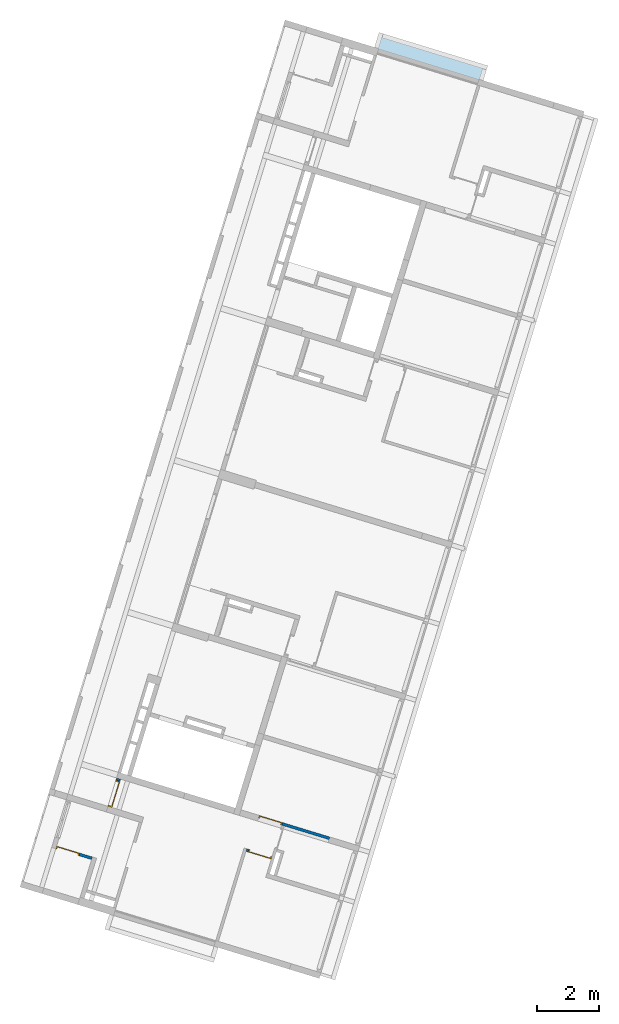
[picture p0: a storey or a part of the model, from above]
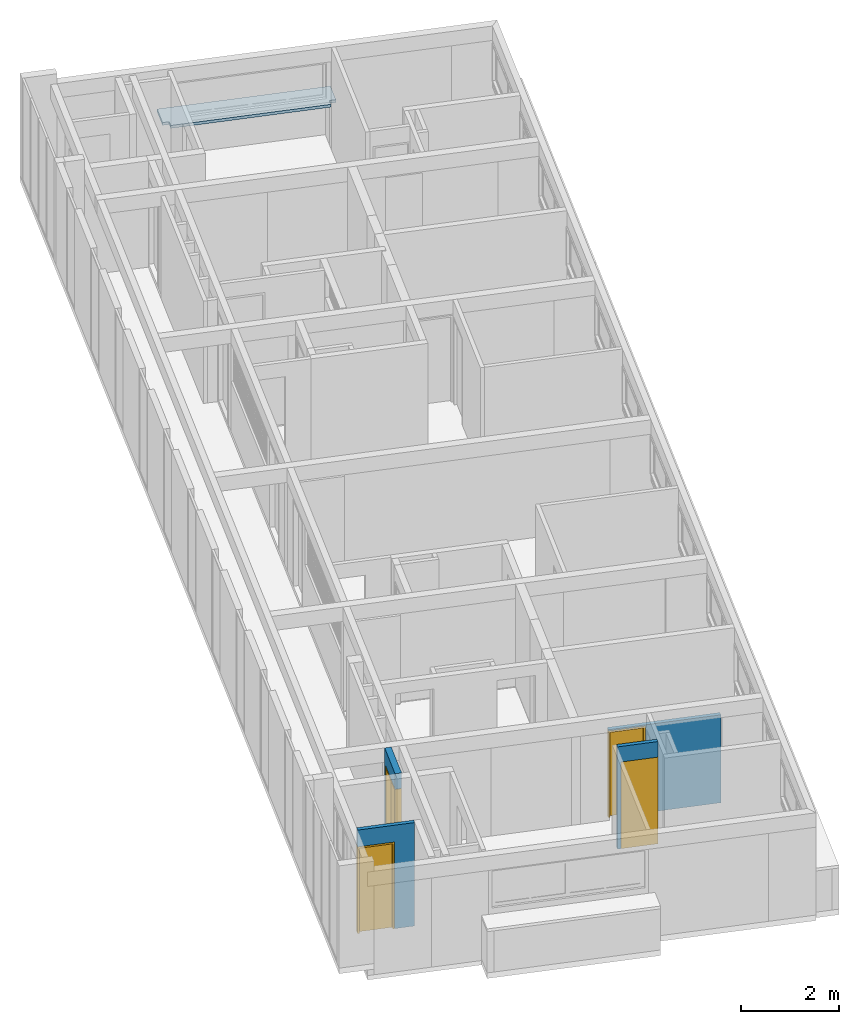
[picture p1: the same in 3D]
Properties of the parts of a building model (IFC2X3), part 1 of 11

# File
Description: ViewDefinition [CoordinationView_V2.0, SurfaceGeometryAddOnView, QuantityTakeOffAddOnView, SpaceBoundary2ndLevelAddOnView], Option [Elements to export: Visible elements (on all stories)], Option [Partial Structure Display: Entire Model], Option [IFC Domain: All], Option [Structural Function: All Elements], Option [Convert Grid elements: On], Option [Convert IFC Annotations and Archicad 2D elements: On], Option [Convert 2D symbols of Doors and Windows: On], Option [Export geometries that Participates in Collision Detection only: Off], Option [Split complex elements: Off], Option [Material Preservation: Explode where necessary], Option [IFC Model position: Survey Point and Project Origin], Option [Curtain Wall export mode: Single Element], Option [Railing export mode: Single Element], Option [Stair export mode: Single Element], Option [Properties To Export: All properties], Option [Space containment: On], Option [IFC Domain For Space Containment: All], Option [Geometry to type objects: Off], Option [Element Properties: All], Option [Building Material Properties: On], Option [Element Parameters: All], Option [Component Parameters: All], Option [IFC Base Quantities: On], Option [Door Window Parameters: On], Option [IFC Space boundaries: On], Option [Archicad Zone Categories as IFC Space classification data: On], Option [Element Classifications: On]
File name: /Users/gustavooliveira/Desktop/Academico/PHD/PAP - AUT0518/NOVOS EXERCICIOS/Pav.-Tipo-JardimEdite.R01.ifc
Time: 2023-04-25T23:43:38
Author: Architect
Organization: Building Designer Office
Written by: The EXPRESS Data Manager Version 5.02.0100.09 : 18 Aug 2016
Made in: IFC file generated by Graphisoft Archicad 26.0.0 INT FULL Macintosh version (IFC add-on version: 3001 INT FULL).
Authorization: The authorising person

# IfcSite, Site
RefLatitude: -23, -36, -48, -600000; RefLongitude: -46, -41, -38, -500000; RefElevation: 728220 mm
BaseQuantities - GrossPerimeter: 0 mm; GrossArea: 0 m2

# IfcBuilding, Building
Description: Jardim-Edite-Pavimento-Tipo
BaseQuantities - GrossFloorArea: 304.282 m2

# IfcBuildingStorey, Pavimento tipo
In: Building
Elevation: 0 mm
BaseQuantities - NetHeight: 2700 mm; GrossHeight: 2700 mm; Height: 2700 mm; GrossFloorArea: 304.282 m2

# IfcSpace: Circulação Comum (4)
In: Pavimento tipo
InteriorOrExteriorSpace: INTERNAL
Pset_SpaceCommon - Category: Circulação Comum
ArchiCADProperties - Surface: Vidro - Azul; Uniform Surface: yes; Zone Category: 0; Zone Category Code: CIR; Layer: A------------GZ; Library Part Name: Selo de Zona BRA 26; Locked: no; Home Story Name: Pavimento tipo; Home Story Number: 0; Element Type: Zone; Absolute Top Link Story: Vazio; Relative Top Link Story: Home + 1; Top Link Story: Home + 1 (Vazio); Surfaces (All): Vidro - Azul; Cover Fill: 25 %; Show On Renovation Filter: All Relevant Filters; Renovation Status: Existing
AC_Pset_Selo_de_Zona_BRA_26 - Tamanho Texto Marcador 1(Padrão): 1.5; Fonte do Texto: Arial Ocidental; Estilo Texto Marcador 1(Padrão): 0; Alinhamento Texto Marcador 1 (padrão): 2; Espaço entre Linhas Texto Marcador 1 (padrão): 1; Fator de Largura do Caractere Texto Marcador 1 (padrão): 1; Espaçamento do Caractere Texto Marcador 1 (padrão): 1; Caneta Texto Marcador 1(Padrão): Texto - Cotas; Área da Parede Extraída: 0; Área de Parede Cortina Extraída: 0; Área da Coluna Extraída: 0; Área Trama Extraída: 0; Áreas Baixas Extraídas: 0; Área Total Extraída: 0; Factor Área Zona: 1; Área de Superfície do Topo do Telhado: 0; Área de Superfície da Base do Telhado: 0; Área de Superfície no Topo da Laje: 0; Área de Superfície no Fundo da Laje: 0; Área da Superfície da Viga no Topo: 0; Superfície da Viga na Base: 0; Área da Superfície do Topo das Inserções da Parede: 0; Superfície de Trás das Inserções da Parede: 0; Área de Superfície do Lado das Inserções da Parede: 0; Nome de Zona (bShowZoneName): yes; Usar Categoria como Nome: no; ID do Element: no; Mostrar ID como...: 2; Área: yes; Tipo de Área: 1; Nível: no; Tipo de Nível: 1; Nível Pavimento Acabado Personal.: ±0.00; Prefixo Acabamento Nível Pavimento: 1; Título Acabamento Nível Pavimento: ANP; Nível Zona Automático: no; Nível Zona Personal.: -0.10; Prefixo Nível Zona: 1; Título Nível Zona: NZ; Acabamento do Piso: no; Código de Acabamento Piso: 0; Acabamento Parede: no; Código de Acabamento Parede: 0; Acabamento do Teto: no; Código de Acabamento do Teto: 0; Acabamento Rodapé: no; Código de Acabamento Rodapé: 0; Acabamento Peitoril / Soleira: no; Código de Acabamento Peitoril / Soleira: 0; Sobrepor Formato do Texto Nome da Zona: no; Nome da Zona Tipo de Fonte: Arial; Nome da Zona Tamanho da Fonte: 2.5; Estilo de Texto Nome da Zona: 1; Caneta Nome de Zona (penZoneName): Aberturas - Geral; Caneta Nome de Zona (penZoneName_int): 3; Sobrepor Formato do Texto Códigos de Acabamento: no; Fonte do Acabamento: Arial; Tamanho do Texto do Acabamento: 2; Estilo de Texto Códigos de Acabamento: 0; Caneta Códigos de Acabamento (penFinish): Zonas - Geral; Caneta Códigos de Acabamento (penFinish_int): 14; Tamanho da forma automático: yes; Diâmetro da cota de nível: 3; Altura da forma: 4.5; Preço por m2: 0; Preço por m3: 0; Preço Calculado a partir de Área Medida: 0; Preço Calculado a partir de Área Útil Medida: 0; Preço Calculado a partir de Área Reduzida: 0; Preço Calculado a partir de Área Calculada: 0; Preço Calculado a partir de Volume Útil: 0; Preço Calculado a partir de Volume Bruto: 0; Ângulo de Rotação: 0 deg
ILUMINAÇÃO E VENTILAÇÃO (Expressão) - Atende: Atende; Não Atende: Não Atende
REVESTIMENTO DE PAREDE POR ZONA (Expressão) - Número de Linhas: 10; DImensão 1: 0 mm; Dimensão 2: 0 mm; Largura do Rejunte: 10 mm; Altura do Revestimento: 100 mm
RODAPÉ (Expressão) - Comprimento da Barra (m): 2.4; Custo da Barra: 0; Estimativa de Custo: 0
AC_Pset_RenovationAndPhasing - Renovation Status: Existing
BaseQuantities - FinishFloorHeight: 0 mm
ArchiCADQuantities - Number of Lamps: 0; Number of Objects: 0; Floor Thickness: 0 mm; Area Reducement: 1 m2; Extracted Column Area: 0 m2; Extracted Fill Area: 0 m2; Extracted Low Area: 0 m2; Extracted Wall Area: 0 m2; Total Extracted Area: 0 m2; Wall Inset Back Side Surface Area: 0 m2; Wall Inset Side Surface Area: 0 m2; Wall Inset Top Surface Area: 0 m2; Extracted Curtain Wall Area: 0 m2; Elevation to Project Zero: 0 mm; Elevation to 1º Nível de Referência: 0 mm; Elevation to 2º Nível de Referência: 0 mm; Elevation to Sea Level: 728220 mm; Elevation to Linked/Home Story: 0 mm; Home Offset: 0 mm; Bottom Elevation To First Reference Level: 0 mm; Bottom Elevation To Home Story: 0 mm; Bottom Elevation To Project Zero: 0 mm; Bottom Elevation To Sea Level: 728220 mm; Bottom Elevation To Second Reference Level: 0 mm
AC_Equantity_Selo_de_Zona_BRA_26 - Nível do Piso: 0 mm; Espessura do Subpiso: 0 mm; Afastamento X: 0 mm; Afastamento Y: 0 mm
Name | LongName = Zone Name = Related Zone Name = Nome de Zona (ROOM_NAME) | Classification | Zone Number = Related Zone Number = Número da Zona | Related Element(s) 3D | Element ID = Hotlink and Element ID = Parent ID | Área Medida = Área Útil Medida = Área Reduzida = Área Calculada = Área da Superfície do Topo = Área da Superfície do Fundo = GrossFloorArea (m2) = NetFloorArea (m2) = SpaceNetFloorAreaBOMA (m2) = SpaceUsableFloorAreaBOMA (m2) = GrossCeilingArea (m2) = NetCeilingArea (m2) = Calculated Area (m2) = Measured Area (m2) = Measured Net Area (m2) = Reduced Area (m2) = Area (m2) = Top Surface Area (Net) (m2) = Bottom Surface Area (Net) (m2) | Nº do Todos os Cantos = Number of the Corners | Nº dos Cantos Côncavos = Number of the Concave Corners | Área da Superfície das Paredes do Perímetro | Área da Superfície das Portas | Área da Superfície das Janelas | Volume = GrossVolume (m3) = NetVolume (m3) = Volume (Net) (m3) | Área da Superfície das Bordas = Edge Surface Area (Net) (m2) | Nível Pavimento Acabado Automático | Área das Aberturas Projetada = Windows Surface Area (m2) | Zona - Número de Azulejos Necessários | Quantidade de Barras | ID Dinâmico por Classificação | BaseQuantities, Height (mm) = FinishCeilingHeight (mm) = ClearHeight (mm) = ArchiCADQuantities, Height (mm) = Top Elevation To First Reference Level (mm) = Top Elevation To Home Story (mm) = Top Elevation To Project Zero (mm) = Top Elevation To Second Reference Level (mm) = Altura (mm) | GrossWallArea (m2) | NetWallArea (m2) = Walls Surface Area (m2) | GrossPerimeter (mm) = NetPerimeter (mm) = Zone Net Perimeter (mm) = Zone Gross Perimeter (mm) = Perímetro (mm) = Perímetro Útil (mm) | Number of Beams | Number of Columns | Number of Doors | Number of Windows | Number of Wall Parts | Doors Surface Area (m2) | Doors Width (mm) | Windows Width (mm) | Walls Perimeter (mm) = Comprimento das Paredes Perímetro (mm) | Top Offset (mm) | Floor Plan Holes Perimeter (mm) = Perímetro dos Vãos (mm) | Top Elevation To Sea Level (mm) | Largura Combinada das Portas (mm) | Largura Combinada das Janelas (mm) | Estimativa de Rodapé (ml) (mm)
06 | Escada | Zoneamento (Classificação ARCHICAD); 4A 16 01 04 Escada (NBR 15965-6 4A); CIR Circulação Comum | 06 | J29; Parede 75; Parede 76; Parede 77; Parede 78; Parede 79; Porta 12; Porta 13; V02 | Zona 06 | 14.7399 | 14 | 7 | 18.4824 | 0 | 0 | 37.7341 | 51.1228 | yes | 0.78 | 19170 | 3 | Zoneamento -Zona 06 | 2560 | 33.4912 | 30.9752 | 19969.8 | 2 | 2 | 1 | 1 | 17 | 1.736 | 800 | 1300 | 8104.9 | -140 | 2890 | 730780 | 0 | 0 | 7304.9
07 | Elevadores | Zoneamento (Classificação ARCHICAD); CIR Circulação Comum; 4A 16 01 01 Elevador (NBR 15965-6 4A) | 07 | Parede 63; V02 | Zona 07 | 6.99 | 4 | 0 | 8.118 | 0 | 0 | 18.873 | 29.673 | no | 0 | 9370 | 1 | Zoneamento -Zona 07 | 2700 | 12.7222 | 8.9962 | 10990 | 2 | 0 | 2 | 0 | 2 | 3.726 | 1620 | 0 | 3690 | 0 | 0 | 730920 | 0 | 0 | 2070
05 | Corredor | Zoneamento (Classificação ARCHICAD); CIR Circulação Comum; 4A 16 04 01 Corredor (NBR 15965-6 4A) | 05 | Laje 11; Parede 69; V01; V05; V06; V07; V08; V09 | Zona 05 | 44.3925 | 10 | 3 | 55.6357 | 7.6384 | 25.944 | 113.645 | 125.901 | yes | 25.944 | 44860 | 14 | Zoneamento -Zona 05 | 2560 | 104.837 | 69.5189 | 49180 | 7 | 5 | 5 | 20 | 11 | 9.3744 | 4320 | 14260 | 37700 | -140 | 0 | 730780 | 3520 | 14260 | 33380
17 | Hall dos Elevadores | Zoneamento (Classificação ARCHICAD); CIR Circulação Comum; 4A 16 16 04 04 Hall do Elevador (NBR 15965-6 4A) | 17 | Parede 53; Parede 63; Parede 71; Parede 72; Parede 73; Parede 74; Porta 10; Porta 11; V02 | Zona 17 | 10.1419 | 12 | 6 | 11.9656 | 0 | 0 | 27.3833 | 42.336 | no | 0 | 14060 | 2 | Zoneamento -Zona 17 | 2700 | 25.3361 | 21.6101 | 15680 | 2 | 3 | 2 | 0 | 9 | 3.726 | 1620 | 0 | 5217.5 | 0 | 2600 | 730920 | 0 | 0 | 3597.5

# IfcSpace: Área Privativa (4)
In: Pavimento tipo
InteriorOrExteriorSpace: INTERNAL; Classification: Zoneamento (Classificação ARCHICAD); 4A 19 Espaços residenciais (NBR 15965-6 4A); APT Área Privativa
Pset_SpaceCommon - Category: Área Privativa
ArchiCADProperties - Surface: Vidro - Azul; Uniform Surface: yes; Zone Category: 0; Zone Category Code: APT; Layer: A------------GZ; Library Part Name: Selo de Zona BRA 26; Locked: no; Home Story Name: Pavimento tipo; Home Story Number: 0; Element Type: Zone; Absolute Top Link Story: Vazio; Relative Top Link Story: Home + 1; Top Link Story: Home + 1 (Vazio); Surfaces (All): Vidro - Azul; Cover Fill: 25 %; Show On Renovation Filter: All Relevant Filters; Renovation Status: Existing
AC_Pset_Selo_de_Zona_BRA_26 - Tamanho Texto Marcador 1(Padrão): 1.5; Fonte do Texto: Arial Ocidental; Estilo Texto Marcador 1(Padrão): 0; Alinhamento Texto Marcador 1 (padrão): 2; Espaço entre Linhas Texto Marcador 1 (padrão): 1; Fator de Largura do Caractere Texto Marcador 1 (padrão): 1; Espaçamento do Caractere Texto Marcador 1 (padrão): 1; Caneta Texto Marcador 1(Padrão): Texto - Geral; Área da Parede Extraída: 0; Área de Parede Cortina Extraída: 0; Área da Coluna Extraída: 0; Área Trama Extraída: 0; Áreas Baixas Extraídas: 0; Área Total Extraída: 0; Factor Área Zona: 1; Área de Superfície do Topo do Telhado: 0; Área de Superfície da Base do Telhado: 0; Área de Superfície no Topo da Laje: 0; Área de Superfície no Fundo da Laje: 0; Área da Superfície da Viga no Topo: 0; Superfície da Viga na Base: 0; Área da Superfície do Topo das Inserções da Parede: 0; Superfície de Trás das Inserções da Parede: 0; Área de Superfície do Lado das Inserções da Parede: 0; Nome de Zona (bShowZoneName): yes; Usar Categoria como Nome: no; ID do Element: no; Mostrar ID como...: 2; Área: yes; Tipo de Área: 1; Nível: no; Tipo de Nível: 1; Nível Pavimento Acabado Automático: no; Nível Pavimento Acabado Personal.: ±0.00; Prefixo Acabamento Nível Pavimento: 1; Título Acabamento Nível Pavimento: ANP; Nível Zona Automático: no; Nível Zona Personal.: -0.10; Prefixo Nível Zona: 1; Título Nível Zona: NZ; Acabamento do Piso: no; Código de Acabamento Piso: 0; Acabamento Parede: no; Código de Acabamento Parede: 0; Acabamento do Teto: no; Código de Acabamento do Teto: 0; Acabamento Rodapé: no; Código de Acabamento Rodapé: 0; Acabamento Peitoril / Soleira: no; Código de Acabamento Peitoril / Soleira: 0; Sobrepor Formato do Texto Nome da Zona: no; Nome da Zona Tipo de Fonte: Arial; Nome da Zona Tamanho da Fonte: 2.5; Estilo de Texto Nome da Zona: 0; Caneta Nome de Zona (penZoneName): Aberturas - Geral; Caneta Nome de Zona (penZoneName_int): 3; Sobrepor Formato do Texto Códigos de Acabamento: no; Fonte do Acabamento: Arial; Tamanho do Texto do Acabamento: 2; Estilo de Texto Códigos de Acabamento: 0; Caneta Códigos de Acabamento (penFinish): Zonas - Geral; Caneta Códigos de Acabamento (penFinish_int): 14; Tamanho da forma automático: yes; Diâmetro da cota de nível: 3; Altura da forma: 4.5; Preço por m2: 0; Preço por m3: 0; Preço Calculado a partir de Área Medida: 0; Preço Calculado a partir de Área Útil Medida: 0; Preço Calculado a partir de Área Reduzida: 0; Preço Calculado a partir de Área Calculada: 0; Preço Calculado a partir de Volume Útil: 0; Preço Calculado a partir de Volume Bruto: 0; Ângulo de Rotação: 0 deg
ILUMINAÇÃO E VENTILAÇÃO (Expressão) - Atende: Atende; Não Atende: Não Atende
REVESTIMENTO DE PAREDE POR ZONA (Expressão) - Número de Linhas: 10; DImensão 1: 0 mm; Dimensão 2: 0 mm; Largura do Rejunte: 10 mm; Altura do Revestimento: 100 mm
RODAPÉ (Expressão) - Comprimento da Barra (m): 2.4; Custo da Barra: 0; Estimativa de Custo: 0
AC_Pset_RenovationAndPhasing - Renovation Status: Existing
BaseQuantities - Height: 2700 mm; FinishCeilingHeight: 2700 mm; FinishFloorHeight: 0 mm; ClearHeight: 2700 mm
ArchiCADQuantities - Number of Doors: 1; Number of Lamps: 0; Number of Objects: 0; Doors Surface Area: 1.9096 m2; Floor Thickness: 0 mm; Area Reducement: 1 m2; Extracted Column Area: 0 m2; Extracted Fill Area: 0 m2; Extracted Low Area: 0 m2; Extracted Wall Area: 0 m2; Total Extracted Area: 0 m2; Wall Inset Back Side Surface Area: 0 m2; Wall Inset Side Surface Area: 0 m2; Wall Inset Top Surface Area: 0 m2; Extracted Curtain Wall Area: 0 m2; Height: 2700 mm; Elevation to Project Zero: 0 mm; Elevation to 1º Nível de Referência: 0 mm; Elevation to 2º Nível de Referência: 0 mm; Elevation to Sea Level: 728220 mm; Elevation to Linked/Home Story: 0 mm; Home Offset: 0 mm; Top Offset: 0 mm; Top Elevation To First Reference Level: 2700 mm; Top Elevation To Home Story: 2700 mm; Top Elevation To Project Zero: 2700 mm; Top Elevation To Sea Level: 730920 mm; Top Elevation To Second Reference Level: 2700 mm; Bottom Elevation To First Reference Level: 0 mm; Bottom Elevation To Home Story: 0 mm; Bottom Elevation To Project Zero: 0 mm; Bottom Elevation To Sea Level: 728220 mm; Bottom Elevation To Second Reference Level: 0 mm
AC_Equantity_Selo_de_Zona_BRA_26 - Nível do Piso: 0 mm; Espessura do Subpiso: 0 mm; Altura: 2700 mm; Afastamento X: 0 mm; Afastamento Y: 0 mm
Name | LongName = Zone Name = Related Zone Name = Nome de Zona (ROOM_NAME) | Zone Number = Related Zone Number = Número da Zona | Related Element(s) 3D | Element ID = Hotlink and Element ID = Parent ID | Área Medida = Área Útil Medida = Área Reduzida = Área Calculada = Área da Superfície do Topo = Área da Superfície do Fundo = GrossFloorArea (m2) = NetFloorArea (m2) = SpaceNetFloorAreaBOMA (m2) = SpaceUsableFloorAreaBOMA (m2) = GrossCeilingArea (m2) = NetCeilingArea (m2) = Calculated Area (m2) = Measured Area (m2) = Measured Net Area (m2) = Reduced Area (m2) = Area (m2) = Top Surface Area (Net) (m2) = Bottom Surface Area (Net) (m2) | Nº do Todos os Cantos = Number of the Corners | Nº dos Cantos Côncavos = Number of the Concave Corners | Área da Superfície das Paredes do Perímetro | Área da Superfície das Portas | Área da Superfície das Janelas | Volume = GrossVolume (m3) = NetVolume (m3) = Volume (Net) (m3) | Área da Superfície das Bordas = Edge Surface Area (Net) (m2) | Área das Aberturas Projetada = Windows Surface Area (m2) | Zona - Número de Azulejos Necessários | Quantidade de Barras | ID Dinâmico por Classificação | GrossWallArea (m2) | NetWallArea (m2) = Walls Surface Area (m2) | GrossPerimeter (mm) = NetPerimeter (mm) = Zone Net Perimeter (mm) = Zone Gross Perimeter (mm) = Perímetro (mm) = Perímetro Útil (mm) | Number of Beams | Number of Columns | Number of Windows | Number of Wall Parts | Doors Width (mm) | Windows Width (mm) | Walls Perimeter (mm) = Comprimento das Paredes Perímetro (mm) | Floor Plan Holes Perimeter (mm) = Perímetro dos Vãos (mm) | Largura Combinada das Portas (mm) | Largura Combinada das Janelas (mm) | Estimativa de Rodapé (ml) (mm)
01 | Apartamento 01 | 01 | J01; J02; J03; J04; J05; J06; J07; J08; J09; Laje 11; Laje 12; Laje 13; Parede 01; Parede 02; Parede 03; Parede 04; Parede 05; Parede 06; Parede 07; Parede 10; Parede 11; Parede 12; Parede 13; Parede 14; Parede 15; Parede 16; Parede 17; Parede 18; Parede 19; Parede 20; Parede 21; Parede 24; Parede 26; Parede 27; Parede 42; Parede 43; Parede 44; Parede 66; Parede 67; Pilar 06; Pilar 07; Pilar 17; Porta 02; Porta 03; Porta 04; Porta 05; V01; V02; V03; V09; V10 | Zona 01 | 52.1599 | 24 | 12 | 28.1855 | 1.90959 | 5.44825 | 140.832 | 106.575 | 0 | 38592 | 7 | Zoneamento -Zona 01 | 22.9575 | 21.0479 | 39472.3 | 5 | 5 | 0 | 18 | 879.999 | 0 | 18540.2 | 1758.97 | 879.996 | 5890 | 17660.2
04 | Apartamento 04 | 04 | J01; J02; J03; J04; J05; J06; J07; J08; J09; Laje 11; Laje 12; Laje 13; Parede 01; Parede 02; Parede 03; Parede 04; Parede 05; Parede 06; Parede 07; Parede 10; Parede 11; Parede 12; Parede 13; Parede 14; Parede 15; Parede 16; Parede 17; Parede 18; Parede 19; Parede 20; Parede 21; Parede 24; Parede 26; Parede 27; Parede 42; Parede 43; Parede 44; Parede 70; Pilar 01; Pilar 02; Porta 02; Porta 03; Porta 04; Porta 05; V01; V02; V03; V04; V05 | Zona 04 | 52.1599 | 24 | 12 | 28.1855 | 1.90959 | 5.44825 | 140.832 | 106.575 | 0 | 38592 | 7 | Zoneamento -Zona 04 | 36.1169 | 34.2073 | 39472.3 | 5 | 5 | 0 | 20 | 880 | 0 | 18540.2 | 1758.98 | 879.996 | 5890 | 17660.2
03 | Apartamento 03 | 03 | J10; J11; J12; J13; Laje 14; Parede 29; Parede 30; Parede 31; Parede 32; Parede 33; Parede 35; Parede 36; Parede 37; Parede 39; Parede 40; Parede 41; Parede 46; Parede 47; Pilar 03; Porta 07; Porta 08; Porta 09; V03; V06 | Zona 03 | 50.3822 | 14 | 7 | 37.9771 | 1.9096 | 9.3875 | 136.032 | 88.4947 | 3.116 | 31896 | 10 | Zoneamento -Zona 03 | 44.0379 | 39.0123 | 32775.8 | 4 | 4 | 5 | 11 | 880 | 3280 | 25515.3 | 1720 | 880 | 10060 | 24635.3
02 | Apartamento 02 | 02 | J10; J11; J12; J13; Laje 14; Parede 29; Parede 30; Parede 31; Parede 32; Parede 33; Parede 35; Parede 36; Parede 37; Parede 39; Parede 40; Parede 41; Parede 46; Parede 47; Pilar 04; Pilar 05; Porta 07; Porta 08; Porta 09; V03; V08 | Zona 02 | 50.3822 | 14 | 7 | 37.9771 | 1.9096 | 9.3875 | 136.032 | 88.4947 | 3.116 | 31896 | 10 | Zoneamento -Zona 02 | 34.2074 | 29.1818 | 32775.8 | 4 | 5 | 5 | 10 | 880 | 3280 | 25515.3 | 1720 | 880 | 10060 | 24635.3

# IfcSpace: Área Técnica (16)
In: Pavimento tipo
InteriorOrExteriorSpace: INTERNAL
Pset_SpaceCommon - Category: Área Técnica
ArchiCADProperties - Surface: Vidro - Azul; Uniform Surface: yes; Zone Category: 0; Zone Category Code: TEC; Layer: A------------GZ; Library Part Name: Selo de Zona BRA 26; Locked: no; Home Story Name: Pavimento tipo; Home Story Number: 0; Element Type: Zone; Absolute Top Link Story: Vazio; Relative Top Link Story: Home + 1; Top Link Story: Home + 1 (Vazio); Surfaces (All): Vidro - Azul; Cover Fill: 25 %; Show On Renovation Filter: All Relevant Filters; Renovation Status: Existing
AC_Pset_Selo_de_Zona_BRA_26 - Tamanho Texto Marcador 1(Padrão): 1.5; Fonte do Texto: Arial Ocidental; Estilo Texto Marcador 1(Padrão): 0; Alinhamento Texto Marcador 1 (padrão): 2; Espaço entre Linhas Texto Marcador 1 (padrão): 1; Fator de Largura do Caractere Texto Marcador 1 (padrão): 1; Espaçamento do Caractere Texto Marcador 1 (padrão): 1; Caneta Texto Marcador 1(Padrão): Texto - Geral; Nº do Todos os Cantos: 4; Nº dos Cantos Côncavos: 0; Área da Superfície das Portas: 0; Área da Superfície das Janelas: 0; Área da Parede Extraída: 0; Área de Parede Cortina Extraída: 0; Área da Coluna Extraída: 0; Área Trama Extraída: 0; Áreas Baixas Extraídas: 0; Área Total Extraída: 0; Factor Área Zona: 1; Área de Superfície do Topo do Telhado: 0; Área de Superfície da Base do Telhado: 0; Área de Superfície no Topo da Laje: 0; Área de Superfície no Fundo da Laje: 0; Área da Superfície da Viga no Topo: 0; Superfície da Viga na Base: 0; Área da Superfície do Topo das Inserções da Parede: 0; Superfície de Trás das Inserções da Parede: 0; Área de Superfície do Lado das Inserções da Parede: 0; Nome de Zona (bShowZoneName): yes; Usar Categoria como Nome: no; ID do Element: no; Mostrar ID como...: 2; Área: yes; Tipo de Área: 1; Nível: no; Tipo de Nível: 1; Nível Pavimento Acabado Automático: no; Nível Pavimento Acabado Personal.: ±0.00; Prefixo Acabamento Nível Pavimento: 1; Título Acabamento Nível Pavimento: ANP; Nível Zona Automático: no; Nível Zona Personal.: -0.10; Prefixo Nível Zona: 1; Título Nível Zona: NZ; Acabamento do Piso: no; Código de Acabamento Piso: 0; Acabamento Parede: no; Código de Acabamento Parede: 0; Acabamento do Teto: no; Código de Acabamento do Teto: 0; Acabamento Rodapé: no; Código de Acabamento Rodapé: 0; Acabamento Peitoril / Soleira: no; Código de Acabamento Peitoril / Soleira: 0; Sobrepor Formato do Texto Nome da Zona: no; Nome da Zona Tipo de Fonte: Arial; Nome da Zona Tamanho da Fonte: 2.5; Estilo de Texto Nome da Zona: 0; Caneta Nome de Zona (penZoneName): Aberturas - Geral; Caneta Nome de Zona (penZoneName_int): 3; Sobrepor Formato do Texto Códigos de Acabamento: no; Fonte do Acabamento: Arial; Tamanho do Texto do Acabamento: 2; Estilo de Texto Códigos de Acabamento: 0; Caneta Códigos de Acabamento (penFinish): Zonas - Geral; Caneta Códigos de Acabamento (penFinish_int): 14; Tamanho da forma automático: yes; Diâmetro da cota de nível: 3; Altura da forma: 4.5; Preço por m2: 0; Preço por m3: 0; Preço Calculado a partir de Área Medida: 0; Preço Calculado a partir de Área Útil Medida: 0; Preço Calculado a partir de Área Reduzida: 0; Preço Calculado a partir de Área Calculada: 0; Preço Calculado a partir de Volume Útil: 0; Preço Calculado a partir de Volume Bruto: 0; Ângulo de Rotação: 0 deg
ILUMINAÇÃO E VENTILAÇÃO (Expressão) - Atende: Atende; Não Atende: Não Atende
REVESTIMENTO DE PAREDE POR ZONA (Expressão) - Número de Linhas: 10; DImensão 1: 0 mm; Dimensão 2: 0 mm; Largura do Rejunte: 10 mm; Altura do Revestimento: 100 mm
RODAPÉ (Expressão) - Comprimento da Barra (m): 2.4; Custo da Barra: 0; Estimativa de Custo: 0
AC_Pset_RenovationAndPhasing - Renovation Status: Existing
BaseQuantities - Height: 2700 mm; FinishCeilingHeight: 2700 mm; FinishFloorHeight: 0 mm; ClearHeight: 2700 mm
ArchiCADQuantities - Number of Doors: 0; Number of Lamps: 0; Number of Objects: 0; Doors Surface Area: 0 m2; Doors Width: 0 mm; Floor Thickness: 0 mm; Area Reducement: 1 m2; Extracted Column Area: 0 m2; Extracted Fill Area: 0 m2; Extracted Low Area: 0 m2; Extracted Wall Area: 0 m2; Number of the Concave Corners: 0; Number of the Corners: 4; Total Extracted Area: 0 m2; Wall Inset Back Side Surface Area: 0 m2; Wall Inset Side Surface Area: 0 m2; Wall Inset Top Surface Area: 0 m2; Extracted Curtain Wall Area: 0 m2; Height: 2700 mm; Elevation to Project Zero: 0 mm; Elevation to 1º Nível de Referência: 0 mm; Elevation to 2º Nível de Referência: 0 mm; Elevation to Sea Level: 728220 mm; Elevation to Linked/Home Story: 0 mm; Home Offset: 0 mm; Top Offset: 0 mm; Floor Plan Holes Perimeter: 0 mm; Top Elevation To First Reference Level: 2700 mm; Top Elevation To Home Story: 2700 mm; Top Elevation To Project Zero: 2700 mm; Top Elevation To Sea Level: 730920 mm; Top Elevation To Second Reference Level: 2700 mm; Bottom Elevation To First Reference Level: 0 mm; Bottom Elevation To Home Story: 0 mm; Bottom Elevation To Project Zero: 0 mm; Bottom Elevation To Sea Level: 728220 mm; Bottom Elevation To Second Reference Level: 0 mm
AC_Equantity_Selo_de_Zona_BRA_26 - Perímetro dos Vãos: 0 mm; Largura Combinada das Portas: 0 mm; Largura Combinada das Janelas: 0 mm; Nível do Piso: 0 mm; Espessura do Subpiso: 0 mm; Altura: 2700 mm; Afastamento X: 0 mm; Afastamento Y: 0 mm
Name | LongName = Zone Name = Related Zone Name = Nome de Zona (ROOM_NAME) | Classification | Zone Number = Related Zone Number = Número da Zona | Element ID = Hotlink and Element ID = Parent ID | Área Medida = Área Útil Medida = Área Reduzida = Área Calculada = Área da Superfície do Topo = Área da Superfície do Fundo = GrossFloorArea (m2) = NetFloorArea (m2) = SpaceNetFloorAreaBOMA (m2) = SpaceUsableFloorAreaBOMA (m2) = GrossCeilingArea (m2) = NetCeilingArea (m2) = Calculated Area (m2) = Measured Area (m2) = Measured Net Area (m2) = Reduced Area (m2) = Area (m2) = Top Surface Area (Net) (m2) = Bottom Surface Area (Net) (m2) | Área da Superfície das Paredes do Perímetro | Volume = GrossVolume (m3) = NetVolume (m3) = Volume (Net) (m3) | Área da Superfície das Bordas = Edge Surface Area (Net) (m2) | Área das Aberturas Projetada = Windows Surface Area (m2) | Zona - Número de Azulejos Necessários | Quantidade de Barras | ID Dinâmico por Classificação | GrossWallArea (m2) | NetWallArea (m2) = Walls Surface Area (m2) | GrossPerimeter (mm) = NetPerimeter (mm) = Zone Net Perimeter (mm) = Zone Gross Perimeter (mm) = Perímetro (mm) = Perímetro Útil (mm) | Number of Beams | Number of Columns = Number of Windows | Number of Wall Parts | Windows Width (mm) | Walls Perimeter (mm) = Comprimento das Paredes Perímetro (mm) = Estimativa de Rodapé (ml) (mm)
18 | Telefone / Tv | Zoneamento (Classificação ARCHICAD); 4A 13 01 13 16 Shaft de Distribuição de Dados (NBR 15965-6 4A); TEC Área Técnica | 18 | Zona 18 | 0.126 | 19.6709 | 0.3402 | 4.374 | 0 | 1620 | 4 | Zoneamento -Zona 18 | 3.8292 | 3.8292 | 1620 | 1 | 0 | 4 | 0 | 8259.8
25 | Prumada Adm | Zoneamento (Classificação ARCHICAD); TEC Área Técnica; 4A 13 01 13 13 Shaft de Distribuição de Energia (NBR 15965-6 4A) | 25 | Zona 25 | 0.1725 | 6.708 | 0.46575 | 7.02 | 0 | 2600 | 1 | Zoneamento -Zona 25 | 6.70795 | 6.70795 | 2600 | 0 | 0 | 4 | 0 | 2600
19 | Interfone | Zoneamento (Classificação ARCHICAD); 4A 13 01 13 16 Shaft de Distribuição de Dados (NBR 15965-6 4A); TEC Área Técnica | 19 | Zona 19 | 0.25725 | 19.6709 | 0.694574 | 7.749 | 0 | 2870 | 4 | Zoneamento -Zona 19 | 7.1845 | 7.1845 | 2870 | 1 | 0 | 6 | 0 | 8259.8 | ArchiCADProperties - Related Element(s) 3D: Parede 50
21 | Gás / Água | Zoneamento (Classificação ARCHICAD); TEC Área Técnica; 4A 13 01 13 19 Shaft de Distribuição de Gás (NBR 15965-6 4A) | 21 | Zona 21 | 0.16485 | 19.6709 | 0.445094 | 5.37299 | 0 | 1990 | 4 | Zoneamento -Zona 21 | 4.17465 | 4.17465 | 1990 | 1 | 0 | 3 | 0 | 8259.8
24 | Prumada Força | Zoneamento (Classificação ARCHICAD); TEC Área Técnica; 4A 13 01 13 13 Shaft de Distribuição de Energia (NBR 15965-6 4A) | 24 | Zona 24 | 0.209979 | 19.6709 | 0.566942 | 6.53345 | 0 | 2420 | 4 | Zoneamento -Zona 24 | 5.17613 | 5.17613 | 2419.8 | 1 | 0 | 3 | 0 | 8259.8
22 | Interfone | Zoneamento (Classificação ARCHICAD); 4A 13 01 13 16 Shaft de Distribuição de Dados (NBR 15965-6 4A); TEC Área Técnica | 22 | Zona 22 | 0.0797999 | 19.6709 | 0.21546 | 3.186 | 0 | 1180 | 4 | Zoneamento -Zona 22 | 2.804 | 2.804 | 1180 | 1 | 0 | 4 | 0 | 8259.8
09 | Aréa Técnica | Zoneamento (Classificação ARCHICAD); TEC Área Técnica; 4A 13 01 13 22 Shaft de Distribuição de Hidráulica (NBR 15965-6 4A) | 09 | Zona 09 | 0.103528 | 4.50297 | 0.279526 | 4.74922 | 0 | 1759 | 1 | Zoneamento -Zona 09 | 4.14457 | 4.14457 | 1758.97 | 0 | 0 | 3 | 0 | 1758.97
23 | Telefone / Tv | Zoneamento (Classificação ARCHICAD); 4A 13 01 13 16 Shaft de Distribuição de Dados (NBR 15965-6 4A); TEC Área Técnica | 23 | Zona 23 | 0.1302 | 19.6709 | 0.35154 | 4.482 | 0 | 1660 | 4 | Zoneamento -Zona 23 | 3.9224 | 3.9224 | 1660 | 1 | 0 | 4 | 0 | 8259.8
16 | Aréa Técnica | Zoneamento (Classificação ARCHICAD); TEC Área Técnica; 4A 13 04 16 Zona de Distribuição de Ar (NBR 15965-6 4A) | 16 | Zona 16 | 2.1021 | 3.8466 | 5.67567 | 16.065 | 0.78 | 5950 | 1 | Zoneamento -Zona 16 | 11.5221 | 10.7421 | 5950 | 1 | 1 | 4 | 1300 | 1665
12 | Aréa Técnica | Zoneamento (Classificação ARCHICAD); TEC Área Técnica; 4A 13 01 13 22 Shaft de Distribuição de Hidráulica (NBR 15965-6 4A) | 12 | Zona 12 | 0.1065 | 4.4032 | 0.287551 | 4.644 | 0 | 1720 | 1 | Zoneamento -Zona 12 | 1.81322 | 1.81322 | 1720 | 0 | 0 | 1 | 0 | 1720 | ArchiCADProperties - Related Element(s) 3D: Parede 30; Parede 36
15 | Aréa Técnica | Zoneamento (Classificação ARCHICAD); TEC Área Técnica; 4A 13 01 13 22 Shaft de Distribuição de Hidráulica (NBR 15965-6 4A) | 15 | Zona 15 | 0.194001 | 3.4568 | 0.523801 | 6.318 | 0 | 2340 | 1 | Zoneamento -Zona 15 | 1.024 | 1.024 | 2340 | 1 | 0 | 2 | 0 | 1370 | ArchiCADProperties - Related Element(s) 3D: Parede 05; V02
08 | Aréa Técnica | Zoneamento (Classificação ARCHICAD); TEC Área Técnica; 4A 13 01 13 22 Shaft de Distribuição de Hidráulica (NBR 15965-6 4A) | 08 | Zona 08 | 0.194 | 3.4568 | 0.5238 | 6.318 | 0 | 2340 | 1 | Zoneamento -Zona 08 | 3.45676 | 3.45676 | 2340 | 1 | 0 | 3 | 0 | 1370 | ArchiCADProperties - Related Element(s) 3D: V02
11 | Aréa Técnica | Zoneamento (Classificação ARCHICAD); TEC Área Técnica; 4A 13 01 13 22 Shaft de Distribuição de Hidráulica (NBR 15965-6 4A) | 11 | Zona 11 | 0.1065 | 4.4032 | 0.287551 | 4.644 | 0 | 1720 | 1 | Zoneamento -Zona 11 | 1.81322 | 1.81322 | 1720 | 0 | 0 | 1 | 0 | 1720 | ArchiCADProperties - Related Element(s) 3D: Parede 30; Parede 36
10 | Prumada Força | Zoneamento (Classificação ARCHICAD); TEC Área Técnica; 4A 13 01 13 13 Shaft de Distribuição de Energia (NBR 15965-6 4A) | 10 | Zona 10 | 0.209979 | 19.6709 | 0.566942 | 6.53345 | 0 | 2420 | 4 | Zoneamento -Zona 10 | 5.17613 | 5.17613 | 2419.8 | 1 | 0 | 3 | 0 | 8259.8
20 | Gás / Água | Zoneamento (Classificação ARCHICAD); TEC Área Técnica; 4A 13 01 13 19 Shaft de Distribuição de Gás (NBR 15965-6 4A) | 20 | Zona 20 | 0.1428 | 19.6709 | 0.38556 | 4.806 | 0 | 1780 | 4 | Zoneamento -Zona 20 | 4.202 | 4.202 | 1780 | 1 | 0 | 4 | 0 | 8259.8
14 | Aréa Técnica | Zoneamento (Classificação ARCHICAD); TEC Área Técnica; 4A 13 01 13 22 Shaft de Distribuição de Hidráulica (NBR 15965-6 4A) | 14 | Zona 14 | 0.103528 | 4.50297 | 0.279526 | 4.74922 | 0 | 1759 | 1 | Zoneamento -Zona 14 | 4.14456 | 4.14456 | 1758.97 | 0 | 0 | 3 | 0 | 1758.97

# IfcBeam: Concreto Armado - Estrutural 140 x 360 (3)
In: 01
Classification: Viga (Classificação ARCHICAD); 3E 12 06 02 00 Viga (NBR 15965-5 3E); Material: Concreto Armado - Estrutural
ArchiCADProperties - Beam Cross Section: Rectangular; End Surface: Concreto - 03; Left Side Surface: Concreto - 03; Right Side Surface: Concreto - 03; Beam Slant Angle: 0 deg; Structural Analytical Model Generation: yes; Layer: A--VIGA-STRU-E-; Building Material / Composite / Profile / Fill: Concreto Armado - Estrutural; Building Material: Concreto Armado - Estrutural; Locked: no; Home Story Name: Pavimento tipo; Home Story Number: 0; Element Type: Beam; Structure Type: Basic; Building Materials (All): Concreto Armado - Estrutural; Surfaces (All): Concreto - 03; Cover Fill: Trama Vazia; Slant Angle: 0 deg; Number of Openings: 0; Top Surface: Concreto - 03; Bottom Surface: Concreto - 03; Show On Renovation Filter: All Relevant Filters; Structural Function: Load-Bearing Element; Renovation Status: Existing
ESTRUTURA (Expressão) - Custo por Volume (m3): 0; Estimativa de Custo Total por Volume: 0; Estimativa de Custo Total por Volume (R$): 0,00 R$
SUPERFÍCIES (Mapas) - Superfície do Topo (Geral): Concreto - 03; Superfície da Base (Geral): Concreto - 03
AC_Pset_RenovationAndPhasing - Renovation Status: Existing
Pset_BeamCommon - LoadBearing: yes; Reference: Concreto Armado - Estrutural 140 x 360
Component Properties - Concreto Armado - Estrutural, Component Type: Core
Material Properties - Concreto Armado - Estrutural, ThermalConductivity: 2.5; Concreto Armado - Estrutural, SpecificHeatCapacity: 1000 J/kg/K; Concreto Armado - Estrutural, MassDensity: 2400 kg/m3; Concreto Armado - Estrutural, Embodied Energy: 2.33 (MJ/kg); Concreto Armado - Estrutural, Embodied Carbon: 0.242 (kgCO₂/kg); Concreto Armado - Estrutural, Name: Concreto Armado - Estrutural; Concreto Armado - Estrutural, ID: CON; Concreto Armado - Estrutural, Participates in Collision Detection: yes
BaseQuantities - Width: 140 mm; Depth: 360 mm; CrossSectionArea: 0.0504 m2
ArchiCADQuantities - Hole Number: 0; Holes Edge Surface Area: 0 m2; Holes Surface Area: 0 m2; Holes Volume: 0 m3; Offset: 0 mm; Height: 360 mm; Width: 140 mm; Elevation to Project Zero: 2560 mm; Elevation to 1º Nível de Referência: 2560 mm; Elevation to 2º Nível de Referência: 2560 mm; Elevation to Sea Level: 730780 mm; Elevation to Linked/Home Story: 2560 mm; Home Offset: 2560 mm; Top Elevation To First Reference Level: 2560 mm; Top Elevation To Home Story: 2560 mm; Top Elevation To Project Zero: 2560 mm; Top Elevation To Sea Level: 730780 mm; Top Elevation To Second Reference Level: 2560 mm; Bottom Elevation To First Reference Level: 2200 mm; Bottom Elevation To Home Story: 2200 mm; Bottom Elevation To Project Zero: 2200 mm; Bottom Elevation To Sea Level: 730420 mm; Bottom Elevation To Second Reference Level: 2200 mm; Cross Section Height at Top/End (perpendicular): 360 mm; Cross Section Height at Bottom/Start (perpendicular): 360 mm; Cross Section Width at Top/End (perpendicular): 140 mm; Cross Section Width at Bottom/Start (perpendicular): 140 mm; Cross Section Height at Top/End (cut): 360 mm; Cross Section Height at Bottom/Start (cut): 360 mm; Cross Section Width at Top/End (cut): 140 mm; Cross Section Width at Bottom/Start (cut): 140 mm; Number of Segments: 1
Component Quantities - Concreto Armado - Estrutural, Component Thickness: 140 mm; Concreto Armado - Estrutural, Rectangular Component Height: 360 mm; Concreto Armado - Estrutural, Rectangular Component Width: 140 mm; Concreto Armado - Estrutural, Component Cross Section Area: 0.0504 m2
Name | Description | Element ID = Hotlink and Element ID = Parent ID | Colliding Zones | Related Zone Name | Related Zone Number | Position | ID Dinâmico por Classificação | IsExternal | Concreto Armado - Estrutural, Embodied Carbon | Concreto Armado - Estrutural, Embodied Energy (MJ) | NetSurfaceAreaExtrudedSides (m2) = OuterSurfaceArea (m2) | Length (mm) = 3D Length (mm) | TotalSurfaceArea (m2) = GrossSurfaceArea (m2) = NetSurfaceArea (m2) | GrossVolume (m3) = Volume (Gross) (m3) | NetVolume (m3) = Volume (Net) (m3) = Volume (Conditional) (m3) = Concreto Armado - Estrutural, Component Volume (Net) (m3) = Concreto Armado - Estrutural, Component Volume (Gross) (m3) = Concreto Armado - Estrutural, Component Volume (Conditional) (m3) | Surface Area of Both Beam Ends (m2) | Surface Area of the Beam Left Side (Net) (m2) | Length Left (mm) | Length Right (mm) | Surface Area of the Beam Right Side (Net) (m2) | Area (m2) = Top Surface Area (Net) (m2) = Bottom Surface Area (Net) (m2) = Área da Superfície do Topo (Geral) (m2) = Área da Superfície da Base (Geral) (m2) | Surface Area (m2) | Cross Section Area at Bottom/Start (m2) = Cross Section Area at Top/End (m2) | Concreto Armado - Estrutural, Mass (kg) | Concreto Armado - Estrutural, Projected Component Area (Net) (m2) = Concreto Armado - Estrutural, Projected Component Area (Gross) (m2)
V03 | Viga-exterior-generico_in-loco-concreto_armado-140mm-360mm | V03 | Apartamento 01; Apartamento 02; Apartamento 03; Apartamento 04 | Apartamento 04 | 04 | Exterior | Viga -V03 | yes | 845.97 (kgCO₂) | 8145.08 | 28.9 | 29090 | 29.0008 | 1.45656 | 1.45656 | 0.169926 | 10.4724 | 29090 | 28710 | 10.3356 | 4.046 | 29.0699 | 0.0849631 | 3495.74 | 10.4724
V01 | Viga-interior-generico_in-loco-concreto_armado-140mm-360mm | V01 | Apartamento 01; Apartamento 04; Corredor | Corredor | 05 | Interior | Viga -V01 | no | 840.408 (kgCO₂) | 8091.53 | 28.71 | 28900 | 28.8108 | 1.45656 | 1.44698 | 0.169926 | 10.2672 | 28710 | 29090 | 10.404 | 4.0194 | 28.9807 | 0.0849631 | 3472.76 | 10.404
V02 | Viga-interior-generico_in-loco-concreto_armado-140mm-360mm | V02 | Apartamento 01; Apartamento 04; Aréa Técnica; Aréa Técnica; Elevadores; Escada; Hall dos Elevadores | Corredor | 05 | Interior | Viga -V02 | no | 809.087 (kgCO₂) | 7789.97 | 27.64 | 27640 | 27.7408 | 1.44094 | 1.39306 | 0.1008 | 9.9504 | 28590 | 28590 | 9.9504 | 3.8696 | 28.2448 | 0.0504 | 3343.33 | 9.9504

# IfcBeam: Concreto Armado - Estrutural 190 x 360 (7)
Classification: Viga (Classificação ARCHICAD); 3E 12 06 02 00 Viga (NBR 15965-5 3E); Material: Concreto Armado - Estrutural
ArchiCADProperties - Beam Cross Section: Rectangular; End Surface: Concreto - 03; Left Side Surface: Concreto - 03; Right Side Surface: Concreto - 03; Beam Slant Angle: 0 deg; Structural Analytical Model Generation: yes; Layer: A--VIGA-STRU-E-; Building Material / Composite / Profile / Fill: Concreto Armado - Estrutural; Building Material: Concreto Armado - Estrutural; Locked: no; Home Story Name: Pavimento tipo; Home Story Number: 0; Element Type: Beam; Structure Type: Basic; Building Materials (All): Concreto Armado - Estrutural; Surfaces (All): Concreto - 03; Cover Fill: Trama Vazia; Slant Angle: 0 deg; Number of Openings: 0; Top Surface: Concreto - 03; Bottom Surface: Concreto - 03; Show On Renovation Filter: All Relevant Filters; Structural Function: Load-Bearing Element; Renovation Status: Existing
ESTRUTURA (Expressão) - Custo por Volume (m3): 0; Estimativa de Custo Total por Volume: 0; Estimativa de Custo Total por Volume (R$): 0,00 R$
SUPERFÍCIES (Mapas) - Superfície do Topo (Geral): Concreto - 03; Superfície da Base (Geral): Concreto - 03
AC_Pset_RenovationAndPhasing - Renovation Status: Existing
Pset_BeamCommon - LoadBearing: yes; Reference: Concreto Armado - Estrutural 190 x 360
Component Properties - Concreto Armado - Estrutural, Component Type: Core
Material Properties - Concreto Armado - Estrutural, ThermalConductivity: 2.5; Concreto Armado - Estrutural, SpecificHeatCapacity: 1000 J/kg/K; Concreto Armado - Estrutural, MassDensity: 2400 kg/m3; Concreto Armado - Estrutural, Embodied Energy: 2.33 (MJ/kg); Concreto Armado - Estrutural, Embodied Carbon: 0.242 (kgCO₂/kg); Concreto Armado - Estrutural, Name: Concreto Armado - Estrutural; Concreto Armado - Estrutural, ID: CON; Concreto Armado - Estrutural, Participates in Collision Detection: yes
BaseQuantities - Width: 190 mm; Depth: 360 mm; CrossSectionArea: 0.0684 m2
ArchiCADQuantities - Hole Number: 0; Holes Edge Surface Area: 0 m2; Holes Surface Area: 0 m2; Holes Volume: 0 m3; Offset: 0 mm; Height: 360 mm; Width: 190 mm; Elevation to Project Zero: 2560 mm; Elevation to 1º Nível de Referência: 2560 mm; Elevation to 2º Nível de Referência: 2560 mm; Elevation to Sea Level: 730780 mm; Elevation to Linked/Home Story: 2560 mm; Home Offset: 2560 mm; Top Elevation To First Reference Level: 2560 mm; Top Elevation To Home Story: 2560 mm; Top Elevation To Project Zero: 2560 mm; Top Elevation To Sea Level: 730780 mm; Top Elevation To Second Reference Level: 2560 mm; Bottom Elevation To First Reference Level: 2200 mm; Bottom Elevation To Home Story: 2200 mm; Bottom Elevation To Project Zero: 2200 mm; Bottom Elevation To Sea Level: 730420 mm; Bottom Elevation To Second Reference Level: 2200 mm; Cross Section Height at Top/End (perpendicular): 360 mm; Cross Section Height at Bottom/Start (perpendicular): 360 mm; Cross Section Width at Top/End (perpendicular): 190 mm; Cross Section Width at Bottom/Start (perpendicular): 190 mm; Cross Section Height at Top/End (cut): 360 mm; Cross Section Height at Bottom/Start (cut): 360 mm; Cross Section Width at Top/End (cut): 190 mm; Cross Section Width at Bottom/Start (cut): 190 mm; Number of Segments: 1
Component Quantities - Concreto Armado - Estrutural, Component Thickness: 190 mm; Concreto Armado - Estrutural, Rectangular Component Height: 360 mm; Concreto Armado - Estrutural, Rectangular Component Width: 190 mm; Concreto Armado - Estrutural, Component Cross Section Area: 0.0684 m2
Name | In | Description | Element ID = Hotlink and Element ID = Parent ID | Colliding Zones | Related Zone Name | Related Zone Number | Position | ID Dinâmico por Classificação | IsExternal | Concreto Armado - Estrutural, Embodied Carbon | Concreto Armado - Estrutural, Embodied Energy (MJ) | NetSurfaceAreaExtrudedSides (m2) = OuterSurfaceArea (m2) | Length (mm) = 3D Length (mm) | TotalSurfaceArea (m2) = GrossSurfaceArea (m2) = NetSurfaceArea (m2) | GrossVolume (m3) = Volume (Gross) (m3) | NetVolume (m3) = Volume (Net) (m3) = Volume (Conditional) (m3) = Concreto Armado - Estrutural, Component Volume (Net) (m3) = Concreto Armado - Estrutural, Component Volume (Gross) (m3) = Concreto Armado - Estrutural, Component Volume (Conditional) (m3) | Surface Area of Both Beam Ends (m2) | Surface Area of the Beam Left Side (Net) (m2) | Length Left (mm) | Length Right (mm) | Surface Area of the Beam Right Side (Net) (m2) | Area (m2) = Top Surface Area (Net) (m2) = Bottom Surface Area (Net) (m2) = Área da Superfície do Topo (Geral) (m2) = Área da Superfície da Base (Geral) (m2) | Surface Area (m2) | Cross Section Area at Bottom/Start (m2) | Cross Section Area at Top/End (m2) | Concreto Armado - Estrutural, Mass (kg) | Concreto Armado - Estrutural, Projected Component Area (Net) (m2) = Concreto Armado - Estrutural, Projected Component Area (Gross) (m2)
V09 | 01 | Viga-interior-generico_in-loco-concreto_armado-190mm-360mm | V09 | Apartamento 01; Corredor | Corredor | 05 | Interior | Viga -V09 | no | 363.897 (kgCO₂) | 3503.63 | 10.076 | 9160 | 10.2128 | 0.645696 | 0.626544 | 0 | 3.2976 | 9160 | 9160 | 3.2976 | 1.7404 | 10.2128 | 0 | 0 | 1503.71 | 3.2976
V10 | 01 | Viga-exterior-generico_in-loco-concreto_armado-190mm-360mm | V10 | Apartamento 01 | Apartamento 01 | 01 | Exterior | Viga -V10 | yes | 369.459 (kgCO₂) | 3557.18 | 10.23 | 9440 | 10.3668 | 0.63612 | 0.63612 | 0.169926 | 3.2976 | 9160 | 9440 | 3.3984 | 1.767 | 10.3999 | 0.0849631 | 0.0849631 | 1526.69 | 3.3984
V04 | 04 | Viga-exterior-generico_in-loco-concreto_armado-190mm-360mm | V04 | Apartamento 04 | Apartamento 04 | 04 | Exterior | Viga -V04 | yes | 369.458 (kgCO₂) | 3557.18 | 10.23 | 9440 | 10.3668 | 0.63612 | 0.63612 | 0.169926 | 3.3984 | 9440 | 9160 | 3.2976 | 1.767 | 10.3999 | 0.0849631 | 0.0849631 | 1526.69 | 3.3984
V05 | 04 | Viga-interior-generico_in-loco-concreto_armado-190mm-360mm | V05 | Apartamento 04; Corredor | Corredor | 05 | Interior | Viga -V05 | no | 369.542 (kgCO₂) | 3557.99 | 10.2323 | 9302.11 | 10.3691 | 0.64584 | 0.636264 | 0.0684 | 3.34876 | 9302.11 | 9302.11 | 3.34876 | 1.7674 | 10.3691 | 0.0684 | 0 | 1527.03 | 3.34876
V06 | 03 | Viga-interior-generico_in-loco-concreto_armado-190mm-360mm | V06 | Apartamento 03; Corredor | Corredor | 05 | Interior | Viga -V06 | no | 363.897 (kgCO₂) | 3503.63 | 10.076 | 9160 | 10.2128 | 0.645696 | 0.626544 | 0 | 3.2976 | 9160 | 9160 | 3.2976 | 1.7404 | 10.2128 | 0 | 0 | 1503.71 | 3.2976
V08 | 05 | Viga-interior-generico_in-loco-concreto_armado-190mm-360mm | V08 | Apartamento 02; Corredor | Corredor | 05 | Interior | Viga -V08 | no | 363.897 (kgCO₂) | 3503.63 | 10.076 | 9160 | 10.2128 | 0.645696 | 0.626544 | 0 | 3.2976 | 9160 | 9160 | 3.2976 | 1.7404 | 10.2128 | 0 | 0 | 1503.71 | 3.2976
V07 | 05 | Viga-interior-generico_in-loco-concreto_armado-190mm-360mm | V07 | Corredor | Corredor | 05 | Interior | Viga -V07 | no | 363.897 (kgCO₂) | 3503.63 | 10.076 | 9160 | 10.2128 | 0.645696 | 0.626544 | 0 | 3.2976 | 9160 | 9160 | 3.2976 | 1.7404 | 10.2128 | 0 | 0 | 1503.71 | 3.2976

# IfcColumn: Concreto - Estrutural 1000 x 190 (7)
Description: Pilar_retangular_seção_constante_1000mm_190mm; Classification: Pilar (Classificação ARCHICAD); 3E 12 10 02 02 Pilar (NBR 15965-5 3E); Material: Concreto - Estrutural
ArchiCADProperties - Column Cross Section: Rectangular; Column Slant Angle: 90 deg; Extrusion Surface: Concreto - 03; End Surface: Concreto - 03; Structural Analytical Model Generation: yes; Layer: A--PILR-STRU-E-; Building Material / Composite / Profile / Fill: Concreto - Estrutural; Building Material: Concreto - Estrutural; Locked: no; Home Story Name: Pavimento tipo; Home Story Number: 0; Element Type: Column; Absolute Top Link Story: Vazio; Relative Top Link Story: Home + 1; Top Link Story: Home + 1 (Vazio); Structure Type: Basic; Building Materials (All): Concreto - Estrutural; Surfaces (All): Concreto - 03; Cover Fill: Trama Vazia; Slant Angle: 90 deg; Show On Renovation Filter: All Relevant Filters; Structural Function: Load-Bearing Element; Renovation Status: Existing
ESTRUTURA (Expressão) - Custo por Volume (m3): 0
AC_Pset_RenovationAndPhasing - Renovation Status: Existing
Pset_ColumnCommon - LoadBearing: yes; Reference: Concreto - Estrutural 1000 x 190
Component Properties - Concreto - Estrutural, Embodied Carbon: 190.357 (kgCO₂); Concreto - Estrutural, Embodied Energy: 1845.89 MJ; Concreto - Estrutural, Component Type: Core
Material Properties - Concreto - Estrutural, ThermalConductivity: 2.3; Concreto - Estrutural, SpecificHeatCapacity: 1000 J/kg/K; Concreto - Estrutural, MassDensity: 2300 kg/m3; Concreto - Estrutural, Embodied Energy: 1.92 (MJ/kg); Concreto - Estrutural, Embodied Carbon: 0.198 (kgCO₂/kg); Concreto - Estrutural, Name: Concreto - Estrutural; Concreto - Estrutural, ID: CON; Concreto - Estrutural, Participates in Collision Detection: yes
BaseQuantities - Length: 2200 mm; Width: 1000 mm; Depth: 190 mm; CrossSectionArea: 0.19 m2; OuterSurfaceArea: 5.236 m2; TotalSurfaceArea: 5.616 m2; GrossSurfaceArea: 5.616 m2; GrossVolume: 0.418 m3; NetVolume: 0.418 m3
ArchiCADQuantities - Core Height / Diameter: 190 mm; Volume of the Column Core (Net): 0.418 m3; Core Width: 1000 mm; Surface Area of the Column Core (Gross, without Top/Bottom): 5.236 m2; Surface Area of the Column Core Top (Gross): 0.19 m2; Surface Area of the Column Core Bottom (Gross): 0.19 m2; Volume of the Column Core (Gross): 0.418 m3; Surface Area of the Column Veneer (Gross, without Top/Bottom): 0 m2; Surface Area of the Column Veneer Top (Gross): 0 m2; Surface Area of the Column Veneer Bottom (Gross): 0 m2; Volume of the Column Veneer (Gross): 0 m3; Maximum Height of the Column: 2200 mm; Minimum Height of the Column: 2200 mm; Surface Area of the Column Core Bottom (Net): 0.19 m2; Surface Area of the Column Core (Net, without Top/Bottom): 5.236 m2; Surface Area of the Column Core Top (Net): 0.19 m2; Surface Area of the Column Veneer Bottom (Net): 0 m2; Surface Area of the Column Veneer (Net): 0 m2; Surface Area of the Column Veneer Top (Net): 0 m2; Perimeter of Column Profile (bottom): 2380 mm; Volume of the Column Veneer (Net): 0 m3; Area: 0.19 m2; Height: 2200 mm; Volume (Net): 0.418 m3; Width: 1000 mm; Elevation to Project Zero: 0 mm; Elevation to 1º Nível de Referência: 0 mm; Elevation to 2º Nível de Referência: 0 mm; Elevation to Sea Level: 728220 mm; Elevation to Linked/Home Story: 0 mm; Home Offset: 0 mm; Top Offset: -500 mm; Surface Area: 5.236 m2; 3D Length: 2200 mm; Volume (Gross): 0.418 m3; Top Elevation To First Reference Level: 2200 mm; Top Elevation To Home Story: 2200 mm; Top Elevation To Project Zero: 2200 mm; Top Elevation To Sea Level: 730420 mm; Top Elevation To Second Reference Level: 2200 mm; Bottom Elevation To First Reference Level: 0 mm; Bottom Elevation To Home Story: 0 mm; Bottom Elevation To Project Zero: 0 mm; Bottom Elevation To Sea Level: 728220 mm; Bottom Elevation To Second Reference Level: 0 mm; Cross Section Height at Top/End (perpendicular): 190 mm; Cross Section Height at Bottom/Start (perpendicular): 190 mm; Cross Section Width at Top/End (perpendicular): 1000 mm; Cross Section Width at Bottom/Start (perpendicular): 1000 mm; Cross Section Height at Top/End (cut): 190 mm; Cross Section Height at Bottom/Start (cut): 190 mm; Cross Section Width at Top/End (cut): 1000 mm; Cross Section Width at Bottom/Start (cut): 1000 mm; Cross Section Area at Bottom/Start: 0.19 m2; Cross Section Area at Top/End: 0.19 m2; Number of Segments: 1; Top Surface Area (Net): 0.19 m2; Bottom Surface Area (Net): 5.236 m2; Top Surface Area (Gross): 0.19 m2
Component Quantities - Concreto - Estrutural, Mass: 961.4 kg; Concreto - Estrutural, Component Thickness: 1000 mm; Concreto - Estrutural, Rectangular Component Height: 190 mm; Concreto - Estrutural, Rectangular Component Width: 1000 mm; Concreto - Estrutural, Component Cross Section Area: 0.19 m2; Concreto - Estrutural, Component Volume (Net): 0.418 m3; Concreto - Estrutural, Component Volume (Gross): 0.418 m3
Name | In | Element ID = Hotlink and Element ID = Parent ID | Colliding Zones = Related Zone Name | Related Zone Number | Position | ID Dinâmico por Classificação | IsExternal
Pilar 06 | 01 | Pilar 06 | Apartamento 01 | 01 | Interior | Pilar -Pilar 06 | no
Pilar 07 | 01 | Pilar 07 | Apartamento 01 | 01 | Exterior | Pilar -Pilar 07 | yes
Pilar 01 | 04 | Pilar 01 | Apartamento 04 | 04 | Exterior | Pilar -Pilar 01 | yes
Pilar 02 | 04 | Pilar 02 | Apartamento 04 | 04 | Interior | Pilar -Pilar 02 | no
Pilar 03 | 03 | Pilar 03 | Apartamento 03 | 03 | Interior | Pilar -Pilar 03 | no
Pilar 05 | 02 | Pilar 05 | Apartamento 02 | 02 | Interior | Pilar -Pilar 05 | no
Pilar 04 | 02 | Pilar 04 | Apartamento 02 | 02 | Interior | Pilar -Pilar 04 | no

# IfcColumn: Concreto - Estrutural 1200 x 250 (4)
In: Pavimento tipo
Description: Pilar_retangular_seção_constante_1200mm_250mm; Classification: Pilar (Classificação ARCHICAD); 3E 12 10 02 02 Pilar (NBR 15965-5 3E); Material: Concreto - Estrutural
ArchiCADProperties - Column Cross Section: Rectangular; Column Slant Angle: 90 deg; Extrusion Surface: Concreto - 03; End Surface: Concreto - 03; Structural Analytical Model Generation: yes; Layer: A--PILR-STRU-E-; Building Material / Composite / Profile / Fill: Concreto - Estrutural; Building Material: Concreto - Estrutural; Locked: no; Home Story Name: Pavimento tipo; Home Story Number: 0; Element Type: Column; Absolute Top Link Story: Vazio; Relative Top Link Story: Home + 1; Top Link Story: Home + 1 (Vazio); Structure Type: Basic; Building Materials (All): Concreto - Estrutural; Surfaces (All): Concreto - 03; Cover Fill: Trama Vazia; Slant Angle: 90 deg; Show On Renovation Filter: All Relevant Filters; Structural Function: Load-Bearing Element; Renovation Status: Existing
ESTRUTURA (Expressão) - Custo por Volume (m3): 0
AC_Pset_RenovationAndPhasing - Renovation Status: Existing
Pset_ColumnCommon - LoadBearing: yes; Reference: Concreto - Estrutural 1200 x 250
Component Properties - Concreto - Estrutural, Component Type: Core
Material Properties - Concreto - Estrutural, ThermalConductivity: 2.3; Concreto - Estrutural, SpecificHeatCapacity: 1000 J/kg/K; Concreto - Estrutural, MassDensity: 2300 kg/m3; Concreto - Estrutural, Embodied Energy: 1.92 (MJ/kg); Concreto - Estrutural, Embodied Carbon: 0.198 (kgCO₂/kg); Concreto - Estrutural, Name: Concreto - Estrutural; Concreto - Estrutural, ID: CON; Concreto - Estrutural, Participates in Collision Detection: yes
BaseQuantities - Width: 1200 mm; Depth: 250 mm; CrossSectionArea: 0.3 m2
ArchiCADQuantities - Core Height / Diameter: 250 mm; Core Width: 1200 mm; Surface Area of the Column Core Top (Gross): 0.3 m2; Surface Area of the Column Core Bottom (Gross): 0.3 m2; Surface Area of the Column Veneer (Gross, without Top/Bottom): 0 m2; Surface Area of the Column Veneer Top (Gross): 0 m2; Surface Area of the Column Veneer Bottom (Gross): 0 m2; Volume of the Column Veneer (Gross): 0 m3; Surface Area of the Column Core Bottom (Net): 0.3 m2; Surface Area of the Column Core Top (Net): 0.3 m2; Surface Area of the Column Veneer Bottom (Net): 0 m2; Surface Area of the Column Veneer (Net): 0 m2; Surface Area of the Column Veneer Top (Net): 0 m2; Perimeter of Column Profile (bottom): 2900 mm; Volume of the Column Veneer (Net): 0 m3; Area: 0.3 m2; Width: 1200 mm; Top Offset: -500 mm; Top Elevation To First Reference Level: 2200 mm; Top Elevation To Home Story: 2200 mm; Top Elevation To Project Zero: 2200 mm; Top Elevation To Sea Level: 730420 mm; Top Elevation To Second Reference Level: 2200 mm; Cross Section Height at Top/End (perpendicular): 250 mm; Cross Section Height at Bottom/Start (perpendicular): 250 mm; Cross Section Width at Top/End (perpendicular): 1200 mm; Cross Section Width at Bottom/Start (perpendicular): 1200 mm; Cross Section Height at Top/End (cut): 250 mm; Cross Section Height at Bottom/Start (cut): 250 mm; Cross Section Width at Top/End (cut): 1200 mm; Cross Section Width at Bottom/Start (cut): 1200 mm; Cross Section Area at Bottom/Start: 0.3 m2; Cross Section Area at Top/End: 0.3 m2; Number of Segments: 1; Top Surface Area (Net): 0.3 m2; Top Surface Area (Gross): 0.3 m2
Component Quantities - Concreto - Estrutural, Component Thickness: 1200 mm; Concreto - Estrutural, Rectangular Component Height: 250 mm; Concreto - Estrutural, Rectangular Component Width: 1200 mm; Concreto - Estrutural, Component Cross Section Area: 0.3 m2
Name | Element ID = Hotlink and Element ID = Parent ID | Related Zone Name | Related Zone Number | Position | ID Dinâmico por Classificação | IsExternal | Concreto - Estrutural, Embodied Carbon | Concreto - Estrutural, Embodied Energy (MJ) | Length (mm) = Maximum Height of the Column (mm) = Minimum Height of the Column (mm) = Height (mm) = 3D Length (mm) | OuterSurfaceArea (m2) = Surface Area of the Column Core (Gross, without Top/Bottom) (m2) = Surface Area of the Column Core (Net, without Top/Bottom) (m2) = Surface Area (m2) = Bottom Surface Area (Net) (m2) | TotalSurfaceArea (m2) = GrossSurfaceArea (m2) | GrossVolume (m3) = NetVolume (m3) = Volume of the Column Core (Net) (m3) = Volume of the Column Core (Gross) (m3) = Volume (Net) (m3) = Volume (Gross) (m3) = Concreto - Estrutural, Component Volume (Net) (m3) = Concreto - Estrutural, Component Volume (Gross) (m3) | Elevation to Project Zero (mm) = Elevation to 1º Nível de Referência (mm) = Elevation to 2º Nível de Referência (mm) = Elevation to Linked/Home Story (mm) = Home Offset (mm) = Bottom Elevation To First Reference Level (mm) = Bottom Elevation To Home Story (mm) = Bottom Elevation To Project Zero (mm) = Bottom Elevation To Second Reference Level (mm) | Elevation to Sea Level (mm) = Bottom Elevation To Sea Level (mm) | Concreto - Estrutural, Mass (kg)
Pilar 14 | Pilar 14 | Corredor | 05 | Interior | Pilar -Pilar 14 | no | 300.564 (kgCO₂) | 2914.56 | 2200 | 6.38 | 6.98 | 0.66 | 0 | 728220 | 1518
Pilar 12 | Pilar 12 | Apartamento 04 | 04 | Exterior | Pilar -Pilar 12 | yes | 304.663 (kgCO₂) | 2954.3 | 2230 | 6.467 | 7.067 | 0.669 | -30 | 728190 | 1538.7
Pilar 16 | Pilar 16 | Corredor | 05 | Interior | Pilar -Pilar 16 | no | 300.564 (kgCO₂) | 2914.56 | 2200 | 6.38 | 6.98 | 0.66 | 0 | 728220 | 1518
Pilar 18 | Pilar 18 | Apartamento 01 | 01 | Exterior | Pilar -Pilar 18 | yes | 304.663 (kgCO₂) | 2954.3 | 2230 | 6.467 | 7.067 | 0.669 | -30 | 728190 | 1538.7

# IfcColumn: Concreto - Estrutural 1200 x 300, Pilar 15
In: Pavimento tipo
Description: Pilar_retangular_seção_constante_1200mm_300mm; Classification: Pilar (Classificação ARCHICAD); 3E 12 10 02 02 Pilar (NBR 15965-5 3E); Material: Concreto - Estrutural
ArchiCADProperties - Column Cross Section: Rectangular; Column Slant Angle: 90 deg; Extrusion Surface: Concreto - 03; End Surface: Concreto - 03; Structural Analytical Model Generation: yes; Element ID: Pilar 15; Hotlink and Element ID: Pilar 15; Layer: A--PILR-STRU-E-; Building Material / Composite / Profile / Fill: Concreto - Estrutural; Building Material: Concreto - Estrutural; Related Zone Name: Corredor; Related Zone Number: 05; Locked: no; Home Story Name: Pavimento tipo; Home Story Number: 0; Element Type: Column; Absolute Top Link Story: Vazio; Relative Top Link Story: Home + 1; Top Link Story: Home + 1 (Vazio); Structure Type: Basic; Parent ID: Pilar 15; Building Materials (All): Concreto - Estrutural; Surfaces (All): Concreto - 03; Cover Fill: Trama Vazia; Slant Angle: 90 deg; Position: Interior; Show On Renovation Filter: All Relevant Filters; Structural Function: Load-Bearing Element; Renovation Status: Existing
ESTRUTURA (Expressão) - Custo por Volume (m3): 0
EXPRESSÕES DE TEXTO (Expressão) - ID Dinâmico por Classificação: Pilar -Pilar 15
AC_Pset_RenovationAndPhasing - Renovation Status: Existing
Pset_ColumnCommon - IsExternal: no; LoadBearing: yes; Reference: Concreto - Estrutural 1200 x 300
Component Properties - Concreto - Estrutural, Embodied Carbon: 360.677 (kgCO₂); Concreto - Estrutural, Embodied Energy: 3497.47 MJ; Concreto - Estrutural, Component Type: Core
Material Properties - Concreto - Estrutural, ThermalConductivity: 2.3; Concreto - Estrutural, SpecificHeatCapacity: 1000 J/kg/K; Concreto - Estrutural, MassDensity: 2300 kg/m3; Concreto - Estrutural, Embodied Energy: 1.92 (MJ/kg); Concreto - Estrutural, Embodied Carbon: 0.198 (kgCO₂/kg); Concreto - Estrutural, Name: Concreto - Estrutural; Concreto - Estrutural, ID: CON; Concreto - Estrutural, Participates in Collision Detection: yes
BaseQuantities - Length: 2200 mm; Width: 1200 mm; Depth: 300 mm; CrossSectionArea: 0.36 m2; OuterSurfaceArea: 6.6 m2; TotalSurfaceArea: 7.32 m2; GrossSurfaceArea: 7.32 m2; GrossVolume: 0.792 m3; NetVolume: 0.792 m3
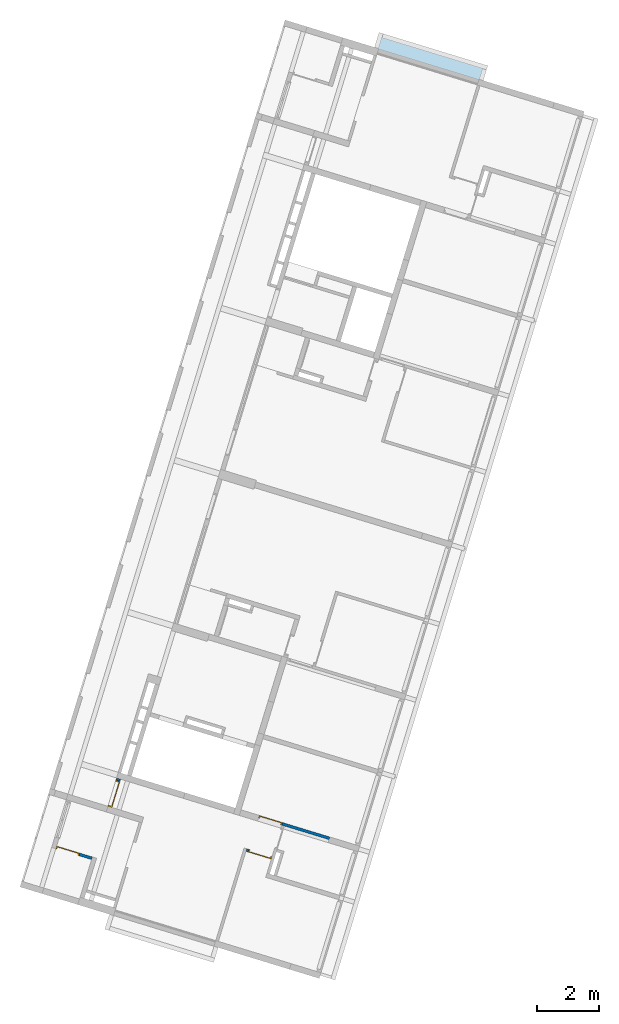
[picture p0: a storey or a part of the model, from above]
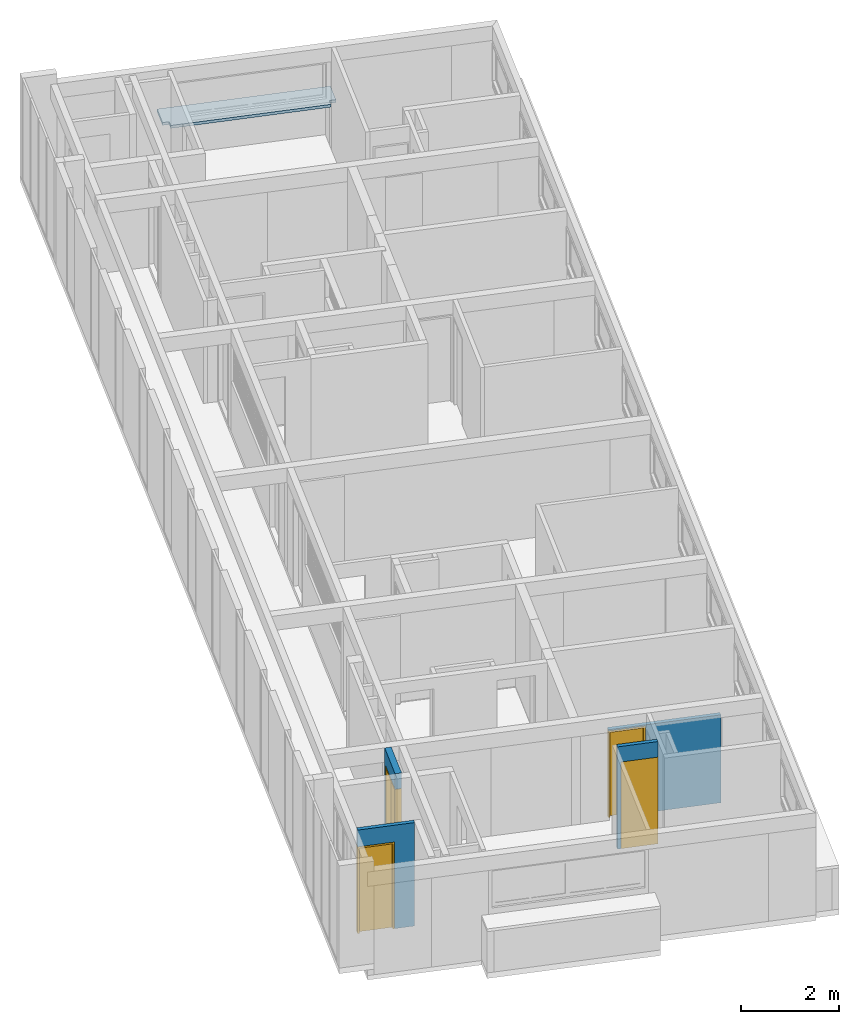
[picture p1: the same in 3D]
Properties of the parts of a building model (IFC2X3), part 4 of 11

# IfcDoor: Door 26 (9)
AC_Equantity_Door_26 - Height: 2170 mm; Z Dimension: 1000 mm; Bottom Level: 1000 mm; Top Level: 0 mm; Reveal to Wall Core: 0 mm; New Wall Fill Width Right: 150 mm; New Wall Fill Width Left: 150 mm; Shoulder Height: 1840 mm; Sidelight 1 Width (gs_sidelight_width_right): 0 mm; Sidelight 1 Width (gs_sidelight_width_right_half): 150 mm; Sidelight 1 Width (gs_sidelight_width_right_orig): 300 mm; Sidelight 1 Sill Height: 0 mm; Sidelight 2 Width (gs_sidelight_width_left): 0 mm; Sidelight 2 Width (gs_sidelight_width_left_half): 300 mm; Sidelight 2 Width (gs_sidelight_width_left_orig): 600 mm; Sidelight 2 Sill Height: 0 mm; Transom Height: 300 mm; Pivot Axis Offset: 275 mm; Tolerance Side 1: 0 mm; Tolerance Side 1 Lower: 0 mm; Tolerance Sidelight 1 Bottom: 0 mm; Tolerance Side 2: 0 mm; Tolerance Side 2 Lower: 0 mm; Tolerance Sidelight 2 Bottom: 0 mm; Tolerance Upper: 0 mm; Tolerance Lower: 0 mm; Wallhole Height: 2170 mm; Reveal Height: 2170 mm; Unit Height: 2170 mm; Egress Height: 2130 mm; Nominal Leaf Height: 2140 mm; Frame Thickness: 115 mm; Frame Thickness Inside: 115 mm; Leaf Offset: 0 mm; Frame Width: 40 mm; Frame Oversize: 10 mm; Frame Outer Thickness: 10 mm; Frame Width Side 1: 40 mm; Middle Frame Width Side 1: 40 mm; Bottom Frame Width Side 1: 40 mm; Frame Width Side 2: 40 mm; Middle Frame Width Side 2: 40 mm; Bottom Frame Width Side 2: 40 mm; Transom Frame Width (gs_frame_width_transom): 40 mm; Upper Frame Width: 40 mm; Door Stop Thickness: 32 mm; Door Stop Width: 16 mm; Rebate Width: 10 mm; Leaf Rebate Depth in 3D: 30 mm; Sidelight and Transom Rebate Width: 10 mm; Sidelight and Transom Rebate Depth: 18 mm; Leaf Thickness: 30 mm; Leaf Frame Width Side: 100 mm; Leaf Frame Width Right: 100 mm; Leaf Frame Width Left: 100 mm; Leaf Frame Width Lower: 200 mm; Leaf Frame Width Upper: 100 mm; Leaf Frame Width Internal: 25 mm; Leaf Undercut: 0 mm; Grid Width: 12 mm; Grid Thickness: 25 mm; Glass Thickness: 12 mm; Handle Height: 1000 mm; Handle Position: 50 mm; Kick Board Height: 100 mm; Horizontal Division Height Sidelight Side 1: 900 mm; Horizontal Division Height Sidelight Side 2: 900 mm; Horizontal Division Height Middle Transom: 900 mm; Horizontal Division Height Transom Side 1: 900 mm; Horizontal Division Height Transom Side 2: 900 mm; Sidelight and Transom Frame Thickness: 44 mm; Transom Frame Width (gs_sash_width): 67 mm; Sidelight Frame Width: 67 mm; Grill Width: 20 mm; Grill Thickness: 25 mm; Sidelight Division Width: 40 mm; Architrave Capital Width: 20 mm; Width Side 1 (gs_tw_right_out): 70 mm; Width Side 2 (gs_tw_left_out): 50 mm; Width Top (gs_tw_top_out): 50 mm; Thickness on Wall (gs_trim_thk_out): 19 mm; Thickness in Wallhole (gs_trim_width_out): 25 mm; Offset (gs_trim_offs_out): 15 mm; Nosing (gs_trim_jambext_nosing_out): 50 mm; Top Overhang (gs_trimov_top_left_out): 0 mm; Top Overhang (gs_trimov_top_right_out): 0 mm; Width Side 1 (gs_tw_right_in): 70 mm; Width Side 2 (gs_tw_left_in): 50 mm; Width Top (gs_tw_top_in): 50 mm; Thickness on Wall (gs_trim_thk_in): 19 mm; Thickness in Wallhole (gs_trim_width_in): 25 mm; Offset (gs_trim_offs_in): 15 mm; Nosing (gs_trim_jambext_nosing_in): 50 mm; Top Overhang (gs_trimov_top_left_in): 0 mm; Top Overhang (gs_trimov_top_right_in): 0 mm; Threshold Thickness: 12 mm; Threshold Width: 10 mm; Threshold External Thickness: 5.80738 mm; Threshold Nosing Outside: 10 mm; Threshold Nosing Inside: 10 mm; Side Overhang Outside: 0 mm; Side Overhang Inside: 0 mm; Sill Thickness: 100 mm; Sill Front Side Thickness: 15 mm; Sill Elevation: 5 mm; Sill Drip Overlap: 20 mm; Sill Drip Width: 30 mm; Sill Nosing: 45 mm; Sill Overhang Side 1: 0 mm; Sill Overhang Side 2: 0 mm; Sill Slip-in Depth: 35 mm; Sill Top Width: 10 mm; Sill Top Height: 10 mm; Sill Slip from Wall: 0 mm; Rear Hole Depth (gs_sill_holeDepthBehind): 0 mm; Width of Sill: 80 mm; Brick Thickness (gs_brick_sill_br_thk): 65 mm; Mortar Thickness (gs_brick_sill_mort_thk): 15 mm; Board Width: 100 mm; Board Thickness: 25 mm; Board Nosing: 30 mm; Board Overhang Side 1: 0 mm; Board Overhang Side 2: 0 mm; Board Slip-in Depth: 0 mm; Profile Height: 65 mm; Profile Thickness: 110 mm; Panel Height: 2088 mm; Inner Offset: 20 mm; Closing Depth: 0 mm; Extra Frame Width: 40 mm; Extra Frame Thickness: 30 mm; Rail Width: 30 mm; Hanging Stick Length: 20 mm; Hanging Stick Radius: 5 mm; Panel Distance: 6 mm; Outside Overhang: 0 mm; Inner Panel Width: 120 mm; 3D Opening Length: 1500 mm; 3D Closed Length: 0 mm; 3D Opening Length 1: 560 mm; 3D Opening Length 2: 140 mm; 3D Opening Height: 1500 mm; 3D Closed Height: 0 mm; Panel Thickness: 50 mm; Panel Frame Width: 50 mm; Frame Width Bottom: 50 mm; Panel Width: 388 mm; Panel Fill Thickness: 10 mm; Louver Thickness: 10 mm; Louver Width: 40 mm; Horizontal Frame Divider Width: 50 mm; Vertical Frame Divider Width: 50 mm; Hole Radius: 10 mm; Vertical Board Width: 100 mm; Z Frame Width: 50 mm; Z Frame Thickness: 25 mm; Vertical Boards Thickness: 25 mm; Horizontal Boards Thickness: 25 mm; Vertical Boards Approximate Width: 80 mm; Horizontal Boards Approximate Width: 115 mm; Box Height (gs_shutRoll_boxHeight): 200 mm; Box Depth (gs_shutRoll_boxWidth): 150 mm; Box Left Offset: 0 mm; Box Right Offset: 0 mm; Depth of Rails: 72.5 mm; Distance from Wall (gs_shutRoll_distFromWall): 0 mm; Distance from Header (gs_shutRoll_distFromHead): 0 mm; Slat Width: 50 mm; Box Height (gs_shutLam_boxHeight): 200 mm; Box Depth (gs_shutLam_boxWidth): 150 mm; Cover Width: 0 mm; Distance from Wall (gs_shutLam_distFromWall): 0 mm; Distance from Header (gs_shutLam_distFromHead): 0 mm; Segment Width (gs_shutLam_segmentWidth): 60 mm; Box Height (gs_shutLam2_boxHeight): 60 mm; Box Width: 60 mm; Distance from Window: 60 mm; Distance from Header (gs_shutLam2_distFromHead): 60 mm; Box Axis Height from Header: 0 mm; Segment Width (gs_shutLam2_segmentWidth): 60 mm; Distance between Arch and Door: 0 mm; Masonry Arch Overhang Side 1: 0 mm; Masonry Arch Overhang Side 2: 0 mm; Masonry Arch Rise: 30 mm; Masonry Arch Projection: 0 mm; Masonry Arch Height: 250 mm; Masonry Arch Depth: 120 mm; Rear Hole Depth (gs_masonry_arch_rearHoleDepth): 0 mm; Brick Thickness (gs_masonry_arch_brick_thk): 65 mm; Mortar Thickness (gs_masonry_arch_mort_thk): 10 mm; Keystone Width: 100 mm; Keystone Oversize: 0 mm; Keystone Projection: 10 mm; Reveal Depth (gs_wido_sill): 0 mm; Reveal Depth (AC_wido_sill): 0 mm; Jamb Depth: 60 mm; Jamb Depth Side 2: 60 mm; Lower Jamb Depth Side 1: 60 mm; Lower Jamb Depth Side 2: 60 mm; Inner Jamb Depth Side 2 (gs_reveal_splayed_innerLeft): 60 mm; Inner Jamb Depth (gs_reveal_splayed_innerRight): 60 mm; Inner Jamb Depth (gs_reveal_double_innerRight): 60 mm; Inner Jamb Depth Side 2 (gs_reveal_double_innerLeft): 60 mm; Inner Lower Jamb Depth Side 1: 60 mm; Inner Lower Jamb Depth Side 2: 60 mm; Head Depth: 60 mm; Sill Depth: 60 mm; Sill Depth Side 1: 60 mm; Sill Depth Side 2: 60 mm; Inner Head Depth (gs_reveal_splayed_innerTop): 60 mm; Inner Sill Depth (gs_reveal_splayed_innerBottom): 0 mm; Inner Head Depth (gs_reveal_double_innerTop): 60 mm; Inner Sill Depth (gs_reveal_double_innerBottom): 0 mm; Inner Sill Depth Side 1: 0 mm; Inner Sill Depth Side 2: 0 mm; Outer Jamb Depth: 80 mm; Plaster Thickness Limit: 40 mm; Distance of Skin from Closer: 0 mm; Closer Width: 38 mm; Closer Thickness: 100 mm; Strip Thickness: 25 mm; Profile Width: 150 mm; Custom Thickness: 15 mm; Skin Overhang to Frame Depth: 0 mm; Left Opening Oversize: 0 mm; Right Opening Oversize: 0 mm; Upper Opening Oversize: 0 mm; Lower Opening Oversize: 0 mm; Opening Width in 3D: 0 mm; Opening Width in 3D on Side 2: 0 mm; Opening Width in 2D: 0 mm; Opening Width in 2D on Side 2: 0 mm; Opening Distance 1 Main Sash Side 1: 0 mm; Opening Distance 2 Main Sash Side 1: 0 mm; Opening Distance 1 Main Sash Side 2: 0 mm; Opening Distance 2 Main Sash Side 2: 0 mm; Opening Distance 1 Middle Transom: 0 mm; Opening Distance 2 Middle Transom: 0 mm; Opening Distance 1 Transom Side 1: 0 mm; Opening Distance 2 Transom Side 1: 0 mm; Opening Distance 1 Transom Side 2: 0 mm; Opening Distance 2 Transom Side 2: 0 mm; Opening Side Width 2: 200 mm; Opening Side Width 1: 100 mm; Opening Side Depth: 1000 mm; Opposite Side Width 2: 100 mm; Opposite Side Width 1: 100 mm; Opposite Side Depth: 1000 mm; AC Left Opening Oversize: 0 mm; AC Right Opening Oversize: 0 mm; AC Upper Opening Oversize: 0 mm; AC Lower Opening Oversize: 0 mm; ID Offset X: 0 mm; ID Offset Y: 0 mm; Custom Text Offset X: 0 mm; Custom Text Offset Y: 0 mm; Leaf Width Offset X: 0 mm; Leaf Width Offset Y: 0 mm
Name | In | Description | OverallWidth (mm) = BaseQuantities, Width (mm) = W/D Opening Width on the Reveal Side (mm) = W/D Opening Width on the Side Opposite to the Reveal Side (mm) = Nominal W/D Opening Width on the Reveal Side (mm) = Nominal W/D Opening Width on the Side Opposite to the Reveal Side (mm) = ArchiCADQuantities, Width (mm) = AC_Equantity_Door_26, Width (mm) = Wallhole Width (mm) = Reveal Width (mm) = Unit Width (mm) | Reveal Dimensions = Wallhole Dimensions = Unit Dimensions = Nominal W x H Size | Egress Dimensions | Leaf Dimensions | Nominal W x H x T Size | Element ID | Hotlink and Element ID | Related Zone Name = To Zone = Location | Related Zone Number = To Zone Number | Parent ID | Hotlink Master ID | From Zone | From Zone Number | Wall Direction Type | Door Leaf Widths | Localização do Produto no Projeto | ID de Aberturas com Master ID | ID Dinâmico por Classificação | Perimeter (mm) | Area (m2) = W/D Opening Nominal Surface Area (m2) = W/D Opening Surface Area on the Reveal Side (m2) = W/D Opening Surface Area on the Side Opposite to the Reveal Side (m2) = Nominal W/D Opening Surface Area on the Reveal Side (m2) = Nominal W/D Opening Surface Area on the Side Opposite to the Reveal Side (m2) | Volume (m3) = NetVolume (m3) = Volume (Net) (m3) = Component, Component Volume (Net) (m3) = Component, Component Volume (Gross) (m3) | Depth (mm) = Wall Thickness (mm) = Frame Thickness (mm) = Real Frame Thickness (mm) | W/D Opening Opening Volume (m3) = W/D Opening Nominal Volume (m3) | W/D Opening Surface Area (m2) = Surface Area (m2) = Bottom Surface Area (Net) (m2) | Elevation to Project Zero (mm) = Elevation to 1º Nível de Referência (mm) = Elevation to 2º Nível de Referência (mm) = Elevation to Linked/Home Story (mm) = Home Offset (mm) | Elevation to Sea Level (mm) = Bottom Elevation To Sea Level (mm) | Top Elevation To First Reference Level (mm) = Top Elevation To Home Story (mm) = Top Elevation To Project Zero (mm) = Top Elevation To Second Reference Level (mm) | Top Elevation To Sea Level (mm) | Bottom Elevation To First Reference Level (mm) = Bottom Elevation To Home Story (mm) = Bottom Elevation To Project Zero (mm) = Bottom Elevation To Second Reference Level (mm) | Sill Height to Current Story (mm) | Egress Width (mm) | Nominal Leaf Width (mm) | Nominal Leaf Width Side 1 (mm) | Sidelight Division Thickness (mm) | Colliding Zones
Apt 03 - Porta 06 | Pavimento tipo | Porta_abrir-interior-generico-generico-generico-88cm | 880 | 0,88×2,17 | 0,80×2,13 | 0,82×2,14 | 0,88×2,17×0,14 | Porta 06 | Apt 03 - Porta 06 | Apartamento 03 | 03 | Parede 34 | Apt 03 - | Corredor | 05 | 3 | 0,82 | Projeto: Jardim EditeLocal: Piso: Pavimento tipo Cômodo: Apartamento 03 | Apt 03 - 03Porta 06 | Porta -Porta 06 | 6100 | 1.9096 | 0.079904 | 140 | 0.267344 | 5.5706 | 0 | 728220 | 2170 | 730390 | -8.57253e-15 | 0 | 800 | 820 | 360 | 100
Apt 01 - Porta 03 | 01 | Porta_abrir-interior-generico-generico-generico-78cm | 780 | 0,78×2,17 | 0,70×2,13 | 0,72×2,14 | 0,78×2,17×0,09 | Porta 03 | Apt 01 - Porta 03 | Apartamento 01 | 01 | Parede 10 | Apt 01 - | Apartamento 01 | 01 | 1 | 0,72 | Projeto: Jardim EditeLocal: Piso: Pavimento tipo Cômodo: Apartamento 01 | Apt 01 - 01Porta 03 | Porta -Porta 03 | 5900 | 1.6926 | 0.062874 | 90 | 0.152334 | 4.5846 | 0 | 728220 | 2170 | 730390 | -5.51091e-15 | 0 | 700 | 720 | 350 | 90 | Apartamento 01
Apt 04 - Porta 05 | Pavimento tipo | Porta_abrir-interior-generico-generico-generico-78cm | 780 | 0,78×2,17 | 0,70×2,13 | 0,72×2,14 | 0,78×2,17×0,09 | Porta 05 | Apt 04 - Porta 05 | Apartamento 04 | 04 | Parede 14 | Apt 04 - | Apartamento 04 | 04 | 1 | 0,72 | Projeto: Jardim EditeLocal: Piso: Pavimento tipo Cômodo: Apartamento 04 | Apt 04 - 04Porta 05 | Porta -Porta 05 | 5900 | 1.6926 | 0.062874 | 90 | 0.152334 | 4.5846 | 0 | 728220 | 2170 | 730390 | -5.51091e-15 | 0 | 700 | 720 | 350 | 90 | Apartamento 04
Apt 04 - Porta 04 | Pavimento tipo | Porta_abrir-interior-generico-generico-generico-68cm | 680 | 0,68×2,17 | 0,60×2,13 | 0,62×2,14 | 0,68×2,17×0,09 | Porta 04 | Apt 04 - Porta 04 | Apartamento 04 | 04 | Parede 20 | Apt 04 - | Apartamento 04 | 04 | 1 | 0,62 | Projeto: Jardim EditeLocal: Piso: Pavimento tipo Cômodo: Apartamento 04 | Apt 04 - 04Porta 04 | Porta -Porta 04 | 5700 | 1.4756 | 0.056124 | 90 | 0.132804 | 4.1246 | 0 | 728220 | 2170 | 730390 | -5.51091e-15 | 0 | 600 | 620 | 310 | 90 | Apartamento 04
Apt 04 - Porta 02 | 04 | Porta_abrir-interior-generico-generico-generico-78cm | 780 | 0,78×2,17 | 0,70×2,13 | 0,72×2,14 | 0,78×2,17×0,09 | Porta 02 | Apt 04 - Porta 02 | Apartamento 04 | 04 | Parede 06 | Apt 04 - | Apartamento 04 | 04 | 1 | 0,72 | Projeto: Jardim EditeLocal: Piso: Pavimento tipo Cômodo: Apartamento 04 | Apt 04 - 04Porta 02 | Porta -Porta 02 | 5900 | 1.6926 | 0.062874 | 90 | 0.152334 | 4.5846 | -30 | 728190 | 2140 | 730360 | -30 | 2670 | 700 | 720 | 350 | 90 | Apartamento 04
Apt 03 - Porta 09 | 03 | Porta_abrir-interior-generico-generico-generico-68cm | 680 | 0,68×2,17 | 0,60×2,13 | 0,62×2,14 | 0,68×2,17×0,14 | Porta 09 | Apt 03 - Porta 09 | Apartamento 03 | 03 | Parede 39 | Apt 03 - | Apartamento 03 | 03 | 1 | 0,62 | Projeto: Jardim EditeLocal: Piso: Pavimento tipo Cômodo: Apartamento 03 | Apt 03 - 03Porta 09 | Porta -Porta 09 | 5700 | 1.4756 | 0.066004 | 140 | 0.206584 | 4.6306 | 0 | 728220 | 2170 | 730390 | -8.57253e-15 | 0 | 600 | 620 | 310 | 90 | Apartamento 03
Apt 02 - Porta 07 | 02 | Porta_abrir-interior-generico-generico-generico-78cm | 780 | 0,78×2,17 | 0,70×2,13 | 0,72×2,14 | 0,78×2,17×0,09 | Porta 07 | Apt 02 - Porta 07 | Apartamento 02 | 02 | Parede 29 | Apt 02 - | Apartamento 02 | 02 | 1 | 0,72 | Projeto: Jardim EditeLocal: Piso: Pavimento tipo Cômodo: Apartamento 02 | Apt 02 - 02Porta 07 | Porta -Porta 07 | 5900 | 1.6926 | 0.062874 | 90 | 0.152334 | 4.5846 | 0 | 728220 | 2170 | 730390 | -5.51091e-15 | 0 | 700 | 720 | 350 | 90 | Apartamento 02
Apt 02 - Porta 08 | 02 | Porta_abrir-interior-generico-generico-generico-78cm | 780 | 0,78×2,17 | 0,70×2,13 | 0,72×2,14 | 0,78×2,17×0,09 | Porta 08 | Apt 02 - Porta 08 | Apartamento 02 | 02 | Parede 40 | Apt 02 - | Apartamento 02 | 02 | 2 | 0,72 | Projeto: Jardim EditeLocal: Piso: Pavimento tipo Cômodo: Apartamento 02 | Apt 02 - 02Porta 08 | Porta -Porta 08 | 5900 | 1.6926 | 0.062874 | 90 | 0.152334 | 4.5846 | 0 | 728220 | 2170 | 730390 | -5.51091e-15 | 0 | 700 | 720 | 350 | 90 | Apartamento 02
Apt 04 - Porta 01 | Pavimento tipo | Porta_abrir-interior-generico-generico-generico-88cm | 880 | 0,88×2,17 | 0,80×2,13 | 0,82×2,14 | 0,88×2,17×0,14 | Porta 01 | Apt 04 - Porta 01 | Apartamento 04 | 04 | Parede 22 | Apt 04 - | Corredor | 05 | 0 | 0,82 | Projeto: Jardim EditeLocal: Piso: Pavimento tipo Cômodo: Apartamento 04 | Apt 04 - 04Porta 01 | Porta -Porta 01 | 6100 | 1.9096 | 0.079904 | 140 | 0.267344 | 5.5706 | 0 | 728220 | 2170 | 730390 | -8.57253e-15 | 0 | 800 | 820 | 360 | 100

# IfcDoor: Door 26, Porta 12
In: 06
Type - OperationType: SINGLE_SWING_RIGHT; ParameterTakesPrecedence: no; Sizeable: no
Type - Door Lining Properties - LiningThickness: 50 mm
Type - Door Panel Properties - Panel 1 - PanelDepth: 50 mm; PanelOperation: SWINGING; PanelWidth: 1; PanelPosition: MIDDLE
Description: Porta_abrir-corta-fogo-generico-generico-generico-80cm; OverallHeight: 2220 mm; OverallWidth: 900 mm; Classification: Porta (Classificação ARCHICAD); 3E 20 02 02 04 Porta de girar (NBR 15965-5 3E)
Pset_DoorCommon - ThermalTransmittance: 0; IsExternal: no
ArchiCADProperties - Reveal Dimensions: 0,90×2,22; Wallhole Dimensions: 0,90×2,22; Unit Dimensions: 0,90×2,22; Egress Dimensions: 0,80×2,17; Leaf Dimensions: 0,86×2,20; Nominal W x H Size: 0,80×2,17; Nominal W x H x T Size: 0,80×2,17×0,14; Wall Structure: Tijolo - Estrutural; Orientation: E; Opening Library Part Name: Door 26; Opening Side Fill Index: Trama Vazia; Element ID: Porta 12; Hotlink and Element ID: Porta 12; Layer: A--PRDE-VEDS-E-; Library Part Name: Door 26; Building Material / Composite / Profile / Fill: Trama Vazia; Fill Type: Trama Vazia; Colliding Zones: Escada; Related Zone Name: Corredor; Related Zone Number: 05; Locked: no; Home Story Name: Pavimento tipo; Home Story Number: 0; Element Type: Door; Parent ID: Parede 79; Surfaces (All): Pintura - Vermelhão; From Zone: Corredor; From Zone Number: 05; Position: Interior; Show On Renovation Filter: All Relevant Filters; Structural Function: Non-Load-Bearing Element; Renovation Status: Existing
AC_Pset_Door_26 - Wall Contours (0-None,1-Full,2-Side,3-Length): 0; Hotspots 0-None,1-2D,2-3D,3-All: 3; Show 2D Hotspots in 3D: yes; Floor Plan Display Option: 3; Hole Position Angle: 0 deg; Hole has Wall's Side Surface: yes; Hole Surface's Split is Curved in Curved Walls: no; Wall Type: 1; Wall Direction Type: 1; Reveal Anchor Position: 1; Opening Direction: 0; Flip: no; Parapet Wall Inset Value: 3; Demolition / New construction: 1; New Wall Fill Type: Bloco; New Wall Fill Pen: Geral - Geral; New Wall Fill Background Pen: Fundos - Cor 1; Show new construction on Wall: no; Demolition line type: 1; Show Demolition/New parameter: no; Display as Transom: no; Sidelight (gs_SidelightTransomRelation): Abaixo da Bandeira; Sidelight (gs_SidelightTransomRelation_m): 1; Sidelight 1: no; Sidelight 2: no; Transom: no; Uniform Tolerances: yes; Nominal Size: 8; Set Wallhole Size as Nominal Size: no; Set Reveal Size as Nominal Size: no; Set Unit Size as Nominal Size: no; Set Egress Size as Nominal Size: yes; Set Leaf Size as Nominal Size: no; Transfer Current Nominal Size to Selection: no; Show Editable Hotspots: yes; 2D Detail Level: 1; Show Reveal on Symbol: 2; Symbolic Display of Opening: no; 3D Detail Level: 8; Opening Direction Sidelight (gs_opening_dir_sl): Oposta à Folha; Opening Direction Sidelight (gs_opening_dir_sl_m): 2; Door Frame (gs_pocket_door_frame): yes; Frame Style (gs_frame_style): Rebaixo Samblado; Frame Style (gs_frame_style_m): 3; Frame Thickness=Wall Thickness: yes; Uniform Frame Thickness: yes; Centered Leaf: yes; Uniform Frame Width: yes; Frame Style Changed Automatically: no; Number of Door Leaves: 4; Number of Door Leaves - Side 2: 3; Door Panel Style: 1; Leaves Configuration (gs_LeavesConfig): Folhas Uniformes; Leaves Configuration (gs_iLeavesConfig): 1; Grid Position (gs_grill_pos): Por tudo; Grid Position (gs_grill_pos_m): 3; Panes Number Vertically: 4; Panes Number Horizontally: 3; Panes Number Vertically Side 1: 4; Panes Number Horizontally Side 1: 3; Show as Glass Panel on Symbol: no; Show Chinese Spring Door Symbol: no; Show Symbol as Airtight Panel: no; Opening Handle (gs_handle_type): Barra Pânico 1; Opening Handle (gs_handle_type_m): 34; Show Handle on Symbol: no; Kick Board Outside (bKickBoardOut): no; Kick Board Inside (bKickBoardIn): no; Uniform Sashes: no; Opening Type (gs_optype_m_05): 3; Opening Type (gs_optype_m_09): 3; Opening Type (gs_optype_m_02): 1; Opening Type (gs_optype_m_06): 1; Opening Type (gs_optype_m_10): 1; Sash Type (MullionStyle_00): Sem Grelha; Sash Type (iMullionStyle_00): 1; Sash Type (iMullionStyle_05): 1; Sash Type (iMullionStyle_09): 1; Sash Type (iMullionStyle_02): 1; Sash Type (iMullionStyle_06): 1; Sash Type (iMullionStyle_10): 1; Hotspot Grill Editing: yes; Grid Position (MullionPosition): Por tudo; Grid Position (iMullionPosition): 3; Panes Number Vertically Main Sash Side 1: 4; Panes Number Horizontally Main Sash Side 1: 2; Panes Number Vertically 2 Main Sash Side 1: 4; Panes Number Horizontally 2 Main Sash Side 1: 2; Panes Number Vertically Main Sash Side 2: 4; Panes Number Horizontally Main Sash Side 2: 2; Panes Number Vertically 2 Main Sash Side 2: 4; Panes Number Horizontally 2 Main Sash Side 2: 2; Panes Number Vertically Middle Transom: 2; Panes Number Horizontally Middle Transom: 2; Panes Number Vertically 2 Middle Transom: 2; Panes Number Horizontally 2 Middle Transom: 2; Panes Number Vertically Transom Side 1: 2; Panes Number Horizontally Transom Side 1: 2; Panes Number Vertically 2 Transom Side 1: 2; Panes Number Horizontally 2 Transom Side 1: 2; Panes Number Vertically Transom Side 2: 2; Panes Number Horizontally Transom Side 2: 2; Panes Number Vertically 2 Transom Side 2: 2; Panes Number Horizontally 2 Transom Side 2: 2; Casing Outside: no; Casing Type Outside (gs_trimtype_out): Simples; Casing Type Outside (gs_trimtype_out_int): 1; Outside Casing Head Type: 1; Architrave Capital: yes; Architrave Capital Type: 1; Cover Outer Wall Surface: yes; Uniform Casing Widths (gs_trim_outside_uniform): yes; Casing Inside: no; Casing Type Inside (gs_trimtype_in): Simples; Casing Type Inside (gs_trimtype_in_int): 1; Cover Inner Wall Surface: yes; Uniform Casing Widths (gs_trim_inside_uniform): yes; Threshold (bThreshold): no; Threshold Type: 4; Threshold Angle: 3.1996 deg; Threshold Changed Automatically: no; Sill - Door: no; Sill - Sidelight Side 1: no; Sill - Sidelight Side 2: no; Sill Oversize: no; Type of the Sill: 3; Sill Angle: 10 deg; Sill is Curved in Curved Walls: yes; Insulation below Sill: yes; Use Wall Insulation Skin: no; Brick Sill 3D Detail Level: 1; Sill Style Changed Automatically: no; Board - Sidelight Side 1: no; Board - Sidelight Side 2: no; Board - Door: no; Board Angle: 0 deg; Board is Curved in Curved Walls: yes; Board in Polygonal Walls: 1; Natural Ventilation: no; Natural Ventilation Type: 2; Sunshade: no; Sunshade Type: 1; Enabled Sunshade Types: 126; Number of Panels: 2; Number of Panels 2: 1; Panel Position (gs_shutter_panelPos): Simétrico; Panel Position (gs_shutter_iPanelPos): 1; Automatic Shutter Height: yes; Extra Frame: no; Cover Type (gs_slidingShutter_cover): Perfil-Z; Cover Type (gs_slidingShutter_iCover): 1; Stacking Direction (gs_foldingShutter_stacking): Dentro; Stacking Direction (gs_foldingShutter_iStacking): 1; Open in 3D: yes; 3D Opening Angle: 180 deg; Show 2D Symbol: yes; Show Opening Lines on Symbol: no; Panel Type (gs_shutPanel_type): Estilo 1; Panel Type (gs_shutPanel_iType): 1; Different Bottom Frame Width: no; Automatic Shutter Width: yes; Louver Angle: 30 deg; Holes Number Horizontal: 5; Holes Number Vertical: 8; Rolling Shutter Placement (gs_shutRoll_placement): Na Fachada; Rolling Shutter Placement (gs_shutRoll_iPlacement): 1; Box Type (gs_shutRoll_boxType): Rectangular; Box Type (gs_shutRoll_iBoxType): 1; Rail Position (gs_shutRoll_railPos): Em Guarnição; Rail Position (gs_shutRoll_iRailPos): 1; Show Casing behind Sunshade (gs_shutRoll_showCasingBehind): no; Insulation behind Box (gs_shutRoll_cutWallBehind): no; Include Height in Wallhole Height: no; Box Top Angle: 10 deg; Box Default Width (gs_shutRoll_boxDefaultSize): Largura Face de Vão; Box Default Width (gs_shutRoll_iBoxDefaultSize): 1; Venetian Blinds Placement (gs_shutLam_placement): Fixada na Fachada; Venetian Blinds Placement (gs_shutLam_iPlacement): 1; Insulation behind Box (gs_shutLam_cutWallBehind): no; Opened Box: yes; Rail (gs_shutLam_bRail): yes; Rail Position (gs_shutLam_railPos): Em Guarnição; Rail Position (gs_shutLam_iRailPos): 1; Show Casing behind Sunshade (gs_shutLam_showCasingBehind): no; Rotation Angle of Slats (gs_shutLam_rotation): 45 deg; Rotation Angle of Slats (gs_shutLam2_rotation): 45 deg; Masonry Arch (bMasonryArch): no; Masonry Arch (gs_masonry_arch_int): 2; Masonry Arch Type (gs_masonry_arch_structure): Arco de Reboco; Masonry Arch Type (gs_masonry_arch_structure_int): 1; Arch on Header: yes; Niche below Arch: yes; Skewback Angle: 75 deg; Custom Niche Surface: no; Reveal Type (gs_reveal_type_new): Requadro Reto - Borda; Reveal Type (gs_reveal_type_int): 1; Bottom Reveal Type (gs_reveal_type_bottom): Requadro Reto; Bottom Reveal Type (gs_reveal_type_bottom_int): 2; Set Jamb Depth on Side: 1; Uniform Jamb Depth: yes; Outer Reveal Type: Requadro Reto; Reveal Type (gs_reveal_doubleOuterTypeInt): 0; Inner Reveal Type: Requadro Reto; Reveal Type (gs_reveal_doubleInnerTypeInt): 0; Angle Side 2: 20 deg; Angle Side: 20 deg; Upper Side Angle: 20 deg; Bottom Side Angle: 20 deg; Outer Angle Side 2: 20 deg; Outer Angle Side: 20 deg; Outer Angle Upper Side: 20 deg; Outer Angle Bottom Side: 20 deg; Rail under Leaves: no; Rail (gs_door_rail_ext): Off; Rail (gs_door_rail_ext_m): 1; Use Wall Finish Component: no; Auto Turn Inside Face Plaster: yes; Turn Inside Face Plaster: 0; Auto Turn Outside Face Plaster: yes; Turn Outside Face Plaster: 0; Dimensionable on 2D: no; Show in 3D: no; Closure Type (gs_closure_type): Sem Fechamento; Closure Type (gs_closure_type_int): 1; Turn Skin on Side (gs_cavity_side): Ambas; Turn Skin on Side (iCavityClosureSide): 1; Number of Skins to Turn: 1; Number from (gs_nTurnDir): Face externa; Number from (iCavityClosureTurnDir): 1; Place Closer on Side 1: yes; Place Closer on Side 2: yes; Place Closer on Top: no; Place Closer on Bottom: no; Place Closer to Skin: 1; Place Closer from Side (gs_cc_dutch_ClosureToSide): 1; Gap at Outside Skin: yes; Turn Skin to Closer: no; Insert Insulation Strip: yes; Show Insulation Strip: yes; Contour Pen (gs_penJoint): Aberturas - Corte Não Estrutural; Contour Line Type (gs_ltJoint): 1; Fill Type (gs_fillJoint): Isolamento 2; Fill Pen (gs_penJointFg): Geral - Geral; Fill Background Pen (gs_penJointBg): Elementos 2D - Desenhos; Custom Surface: no; Surface: Madeira - Pinho Granulado Horizontal; Contour Pen (gs_penPlug): Aberturas - Corte Não Estrutural; Contour Line Type (gs_ltPlug): 1; Fill Type (gs_fillPlug): Isolamento 2; Fill Pen (gs_penPlugFg): Geral - Geral; Fill Background Pen (gs_penPlugBg): Elementos 2D - Desenhos; Edited Jamb Side: 1; Edited Wall Side: 1; Edited Skin Number: 1; Turn-in Skin: no; Consider Skin as Plaster: no; Turn-in Thickness: 1; Hatch Orientation: 1; Separating Line at Turn-in: no; Separating Line Pen: Geral - Geral; Last Selected Side: no; Closure Method Changed Automatically: no; Connection on Side 1: no; Connection on Side 2: no; Connection on the Top: no; Opening Type (gs_leaf_optype): Preso Lateral; Opening Type (gs_leaf_optype_m): 1; End Panel Opening Side 1: no; End Panel Opening Side 2: no; Opening Angle in 2D: 90 deg; Opening Angle in 2D on Side 2: 90 deg; Opening Angle in 3D: 0 deg; End Panel Opening Angle in 3D on Side 2: 0 deg; Opening Angle of Main Sash Side 1 (openingAngle_05): 0 deg; Opening Angle of Main Sash Side 1 (openingAngle2_05): 0 deg; Opening Angle of Main Sash Side 2 (openingAngle_09): 0 deg; Opening Angle of Main Sash Side 2 (openingAngle2_09): 0 deg; Opening Angle of Middle Transom (openingAngle_02): 0 deg; Opening Angle of Middle Transom (openingAngle2_02): 0 deg; Opening Angle of Transom Side 1 (openingAngle_06): 0 deg; Opening Angle of Transom Side 1 (openingAngle2_06): 0 deg; Opening Angle of Transom Side 2 (openingAngle_10): 0 deg; Opening Angle of Transom Side 2 (openingAngle2_10): 0 deg; Double Acting Line Type: 4; Override MVO for 2D Symbolic Display: no; Opening Line Type: 1; Opening Line Shape (or_SwingType): Curva; Opening Line Shape (or_iSwingType): 1; Opening Line Shape (or_SlidingType): Nenhum; Opening Line Shape (or_iSlidingType): 0; Show Glazing Line in 2D: yes; Glazing Line Pen in 2D (or_iGlazingLinePen): 3; Glazing Line Pen in 2D (or_glazingLinePen): Aberturas - Geral; Override MVO for Door 3D Projections: no; Show Opening Line (or_bOplines3d): yes; Line Type Opening Side (or_opLineType3dIn): Linha Sólida; Line Type Opening Side (or_iOpLineType3dIn): 0; Line Type Opposite Side (or_opLineType3dOut): Linha Sólida; Line Type Opposite Side (or_iOpLineType3dOut): 0; Line Orientation (or_oplineStyle): Maçaneta; Line Orientation (or_iOplineStyle): 1; Opening Line Pen in 2D/3D (or_opLinePen): Aberturas - Geral; Opening Line Pen in 2D/3D (or_iOpLinePen): 3; Override MVO for Sidelight/Transom 3D Projections: no; Show Opening Line (or_bWinOplines3d): yes; Line Type Opening Side (or_winOpLineType3dIn): Linha Sólida; Line Type Opening Side (or_iWinOpLineType3dIn): 0; Line Type Opposite Side (or_winOpLineType3dOut): Linha Sólida; Line Type Opposite Side (or_iWinOpLineType3dOut): 0; Line Orientation (or_winOplineStyle): Maçaneta; Line Orientation (or_iWinOplineStyle): 1; Opening Line Pen in 2D/3D (or_winOpLinePen): Aberturas - Geral; Opening Line Pen in 2D/3D (or_iWinOpLinePen): 3; Symbol Pen: Aberturas - Geral; Frame Contour Pen: Aberturas - Moldura; Casing Cut Line Pen on Both Sides: Aberturas - Geral; Leaf Contour Pen: Aberturas - Geral; Wall Contour Line (gs_wcont_line): Desligado; Wall Contour Line (iWallContourLine): 1; Wall Contour Line Type Inside: 4; Wall Contour Line Type Outside: 4; Hidden Wall Contour Line Type Inside: 4; Hidden Wall Contour Line Type Outside: 4; Sidelight Wall Contour Line (gs_wcont_line_sl): Ambos Lados; Sidelight Wall Contour Line (iWallContourLineSl): 4; Sidelight Wall Contour Line Type Inside: 1; Sidelight Wall Contour Line Type Outside: 1; Sidelight Hidden Wall Contour Line Type Inside: 4; Sidelight Hidden Wall Contour Line Type Outside: 4; Wall Contour Line Pen: Aberturas - Geral; Use Fills: yes; Frame Fill Type: Trama Vazia; Frame Fill Pen: Aberturas - Fundo de Trama; Frame Fill Background Pen: Fundos - Cor 1; Leaf Fill Type: Ar (Vazio); Leaf Fill Pen: Aberturas - Fundo de Trama; Leaf Fill Background Pen: Fundos - Cor 1; Airtight Symbol Fill Type: Trama Sólida; Airtight Symbol Fill Pen: Geral - Geral; Airtight Symbol Fill Background Pen: Geral - Geral; Door Plan Symbol Fill Type: Trama Vazia; Door Plan Symbol Fill Pen: Fundos - Cor 1; Door Plan Symbol Fill Background Pen: Transparent; Sidelight Plan Symbol Fill Type: Trama Vazia; Sidelight Plan Symbol Fill Pen: Fundos - Cor 1; Sidelight Plan Symbol Fill Background Pen: Fundos - Cor 1; Threshold and Sill Line Type: 1; Threshold Section Contour Pen: Aberturas - Geral; Threshold Section Fill Type: Trama Vazia; Threshold Section Fill Pen: Fundos - Cor 1; Threshold Section Fill Background Pen: Fundos - Cor 1; Sill 3D and Uncut Pen: Geral - Geral; Sill Section Contour Pen: Geral - Geral; Sill Section Fill Type: Trama Vazia; Sill Section Fill Pen: Fundos - Cor 1; Sill Section Fill Background Pen: Fundos - Cor 1; Section Insulation Contour Pen: Geral - Geral; Section Insulation Fill Type: Isolamento 2; Section Insulation Fill Pen: Geral - Geral; Section Insulation Fill Background Pen: Fundos - Cor 1; Board 3D and Uncut Pen: Geral - Geral; Board Section Contour Pen: Geral - Geral; Board Section Fill Type: Trama Vazia; Board Section Fill Pen: Fundos - Cor 1; Board Section Fill Bkg. Pen: Fundos - Cor 1; Casing Fill Type Inside: Trama Vazia; Casing Fill Pen Inside: Aberturas - Fundo de Trama; Casing Fill Background Pen Inside: Fundos - Cor 1; Casing Fill Type Outside: Trama Vazia; Casing Fill Pen Outside: Aberturas - Fundo de Trama; Casing Fill Background Pen Outside: Fundos - Cor 1; Arch Section Fill Type: Trama Vazia; Arch Section Fill Pen: Fundos - Cor 1; Arch Section Fill Bkg. Pen: Fundos - Cor 1; Ventilation Profile Section Fill Type: Ar (Vazio); Ventilation Profile Section Fill Pen: Fundos - Cor 1; Ventilation Profile Section Fill Background Pen: Fundos - Cor 1; Sunshade Symbol Line Type: 1; Sunshade Cut Line Pen: Geral - Geral; 3D/Section Uncut Line Pen: Aberturas - Geral; Sunshade Cut Fill Type: Trama Vazia; Sunshade Cut Fill Pen: Geral - Geral; Sunshade Cut Fill Background Pen: Window Background; Sunshade Insulation Fill Type: Trama Vazia; Sunshade Insulation Fill Pen: Geral - Geral; Sunshade Insulation Background Pen: Window Background; Uncut Fill Type: Trama Vazia; Uncut Fill Pen: Elementos 2D - Geral; Uncut Fill Background Pen: Fundos - Cor 1; Opening Side Values (gs_opside_list): Pessoal; Opening Side Values (gs_opside_list_m): 0; Frame Element Joinery (gs_SashText_typ): Travessa Sobrepõe Montante; Frame Element Joinery (gs_SashText_typ_num): 2; Frame Pen: Aberturas - Geral; Leaf Pen: Aberturas - Geral; Sash Glass Pen: Aberturas - Corte Não Estrutural; Leaf Glass Pen: Aberturas - Corte Não Estrutural; Masonry Arch Pen: Paredes - Geral; Curve Resolution: 32; Shadow: yes; Uniform Door Surfaces: no; Frame Outside: Pintura - Vermelhão; Frame Inside: Pintura - Vermelhão; Leaf Outside: Pintura - Vermelhão; Leaf Inside: Pintura - Vermelhão; Leaf 2: Madeira - Pinho Granulado Horizontal; Leaf 3: Madeira - Pinho Granulado Horizontal; Lock: Pintura - Anthracite; Grid Outside (gs_grill_mat): Madeira - Pinho Granulado Horizontal; Grid Inside (gs_grill_mat2): Madeira - Pinho Granulado Horizontal; Grid Outside (gs_leaf_grill_mat): Madeira - Pinho Granulado Horizontal; Grid Inside (gs_leaf_grill_mat2): Madeira - Pinho Granulado Horizontal; Solid Panel Outside: Madeira - Pinho Granulado Horizontal; Solid Panel Inside: Madeira - Pinho Granulado Horizontal; Sash Glass: Vidro - Simples; Leaf Glass: Vidro - Simples; Rail (gs_rail_mat): Metal - Ferro; Louver Outside: Madeira - Pinho Granulado Horizontal; Louver Inside: Madeira - Pinho Granulado Horizontal; Kick Plate: Metal - Alumínio; Uniform Casing Surfaces: no; Interior Casing: Pintura - Vermelhão; Exterior Casing: Pintura - Vermelhão; Ventilation Profile: Metal - Alumínio; Shutter Panel: Madeira - Pinho Granulado Horizontal; Shutter Panel Frame: Madeira - Pinho Granulado Horizontal; Rolling Shutter Box: Metal - Aço Inoxidável; Rolling Shutter Blades: Pintura - Branco Titânio; Rolling Shutter Rail: Pintura - Branco Titânio; Venetian Blinds Box: Metal - Aço Inoxidável; Venetian Blinds Segments: Pintura - Branco Titânio; Sliding Shutter Rail: Metal - Aço Inoxidável; Threshold (gs_treshold_mat): Pedra - Granito Cinza; Threshold Metal: Metal - Alumínio; Sill (gs_sill_mat): Tijolo - Aparelho ao Comprido; Brick Sill Mortar: Estuque - Branco Áspera; Board (gs_board_mat): Madeira - Pinho Granulado Horizontal; Handle: Metal - Aço Inoxidável; Handle Accessories: Metal - Ferro; Kick Board Outside (matKickBoardOut): Metal - Aço Inoxidável; Kick Board Inside (matKickBoardIn): Metal - Aço Inoxidável; Masonry Arch Brick: Tijolo - Aparelho ao Comprido; Masonry Arch Mortar: Estuque - Branco Áspera; Masonry Arch Keystone: Pedra - Arenito 01; Niche: Pintura - Óxido de Chumbo Amarelo; Tags and Labels: 1; Show Leaf Width Dimensions: yes; Show Door ID: no; Show Custom Text: yes; Custom Text: <Texto Personalizado>; Always Readable: yes; Font Type: Arial; Font Size: 2; Font Style: 0; Text Pen (iPenText): 1; Text Pen (penText): Geral - Geral; Door belongs to the Zone into which it opens: yes; Cost: 0; Location as: Nome do Compartimento; Total Glazed Area (gs_list_glassarea_tmp): 0; Override Glazed Area: yes; Total Glazed Area (gs_list_glassarea): 0; Total Glass Perimeter: 0; Free Air Performance (mm2/l/m): 0; Group Type (FM_Type): Outros; Group Type (iFMType): 25; Object Weight: 0; Object Weight Unit: kg; Door Orientation Definition: 0; Door Orientation: E; Door Closer: no; Vision Panel Type: Sem Painel Vision; Hold Open Device: no; Door Leaf Widths: 0,86; IFC Operation (ifc_optypestr): Porta Simples Abertura Simples; IFC Operation (ifc_optype): 1
CLASSIFICAÇÕES GERAIS - Resistência ao Fogo: 60 minutos; Transmissão Sonora: 0
INFORMAÇÕES DO PRODUTO - Data de Aquisição: DD/MM/YYYY
FABRICAÇÃO - Data de Fabricação: DD/MM/YYYY; Site do Produto: www.graphisoft.com
GARANTIA - Ínicio da Garantia: DD/MM/YYYY; Fim da Garantia: DD/MM/YYYY
ABERTURAS - Tipo de Abertura: Abrir Simples; Material: Aço Galvanizado
EXPRESSÕES DE TEXTO (Expressão) - Localização do Produto no Projeto: Projeto: Jardim EditeLocal: Piso: Pavimento tipo Cômodo: Corredor; ID de Aberturas com Master ID: 05Porta 12; ID Dinâmico por Classificação: Porta -Porta 12
AC_Pset_RenovationAndPhasing - Renovation Status: Existing
BaseQuantities - Height: 2220 mm; Width: 900 mm; Perimeter: 6240 mm; Area: 1.998 m2; Volume: 0.12348 m3; Depth: 140 mm; NetVolume: 0.12348 m3
ArchiCADQuantities - W/D Opening Opening Volume: 0.27972 m3; W/D Opening Nominal Volume: 0.24304 m3; W/D Opening Surface Area: 6.1202 m2; W/D Opening Nominal Surface Area: 1.736 m2; W/D Opening Width on the Reveal Side: 900 mm; W/D Opening Height on the Reveal Side: 2220 mm; W/D Opening Width on the Side Opposite to the Reveal Side: 900 mm; W/D Opening Height on the Side Opposite to the Reveal Side: 2220 mm; W/D Opening Surface Area on the Reveal Side: 1.998 m2; W/D Opening Surface Area on the Side Opposite to the Reveal Side: 1.998 m2; Nominal W/D Opening Width on the Reveal Side: 900 mm; Nominal W/D Opening Height on the Reveal Side: 2220 mm; Nominal W/D Opening Width on the Side Opposite to the Reveal Side: 900 mm; Nominal W/D Opening Height on the Side Opposite to the Reveal Side: 2220 mm; Nominal W/D Opening Surface Area on the Reveal Side: 1.998 m2; Nominal W/D Opening Surface Area on the Side Opposite to the Reveal Side: 1.998 m2; Sill/Header Value: 0 mm; W/D Nominal Sill Height: 0 mm; W/D Sill Height on the Reveal Side: 20 mm; W/D Sill Height on the Side Opposite to the Reveal Side: 20 mm; W/D Nominal Head Height: 2170 mm; W/D Head Height on the Reveal Side: 2140 mm; W/D Head Height on the Side Opposite to the Reveal Side: 2140 mm; Wall Thickness: 140 mm; Frame Thickness: 140 mm; Height: 2170 mm; Volume (Net): 0.12348 m3; Width: 800 mm; Elevation to Project Zero: 0 mm; Elevation to 1º Nível de Referência: 0 mm; Elevation to 2º Nível de Referência: 0 mm; Elevation to Sea Level: 728220 mm; Elevation to Linked/Home Story: 0 mm; Home Offset: 0 mm; Surface Area: 6.1202 m2; Top Elevation To First Reference Level: 2220 mm; Top Elevation To Home Story: 2220 mm; Top Elevation To Project Zero: 2220 mm; Top Elevation To Sea Level: 730440 mm; Top Elevation To Second Reference Level: 2220 mm; Bottom Elevation To First Reference Level: -8.57253e-15 mm; Bottom Elevation To Home Story: -8.57253e-15 mm; Bottom Elevation To Project Zero: -8.57253e-15 mm; Bottom Elevation To Sea Level: 728220 mm; Bottom Elevation To Second Reference Level: -8.57253e-15 mm; Bottom Surface Area (Net): 6.1202 m2
AC_Equantity_Door_26 - Width: 800 mm; Height: 2170 mm; Z Dimension: 1000 mm; Bottom Level: 1000 mm; Top Level: 0 mm; Sill Height to Current Story: 0 mm; Reveal to Wall Core: 0 mm; New Wall Fill Width Right: 150 mm; New Wall Fill Width Left: 150 mm; Shoulder Height: 1840 mm; Sidelight 1 Width (gs_sidelight_width_right): 0 mm; Sidelight 1 Width (gs_sidelight_width_right_half): 150 mm; Sidelight 1 Width (gs_sidelight_width_right_orig): 300 mm; Sidelight 1 Sill Height: 0 mm; Sidelight 2 Width (gs_sidelight_width_left): 0 mm; Sidelight 2 Width (gs_sidelight_width_left_half): 300 mm; Sidelight 2 Width (gs_sidelight_width_left_orig): 600 mm; Sidelight 2 Sill Height: 0 mm; Transom Height: 300 mm; Pivot Axis Offset: 275 mm; Tolerance Side 1: 0 mm; Tolerance Side 1 Lower: 0 mm; Tolerance Sidelight 1 Bottom: 0 mm; Tolerance Side 2: 0 mm; Tolerance Side 2 Lower: 0 mm; Tolerance Sidelight 2 Bottom: 0 mm; Tolerance Upper: 0 mm; Tolerance Lower: 0 mm; Wallhole Width: 900 mm; Wallhole Height: 2220 mm; Reveal Width: 900 mm; Reveal Height: 2220 mm; Unit Width: 900 mm; Unit Height: 2220 mm; Egress Width: 800 mm; Egress Height: 2170 mm; Nominal Leaf Width: 860 mm; Nominal Leaf Height: 2200 mm; Frame Thickness: 115 mm; Frame Thickness Inside: 115 mm; Leaf Offset: 0 mm; Frame Width: 50 mm; Frame Oversize: 10 mm; Frame Outer Thickness: 10 mm; Frame Width Side 1: 40 mm; Middle Frame Width Side 1: 40 mm; Bottom Frame Width Side 1: 40 mm; Frame Width Side 2: 40 mm; Middle Frame Width Side 2: 40 mm; Bottom Frame Width Side 2: 40 mm; Transom Frame Width (gs_frame_width_transom): 40 mm; Upper Frame Width: 40 mm; Door Stop Thickness: 32 mm; Door Stop Width: 16 mm; Rebate Width: 30 mm; Leaf Rebate Depth in 3D: 50 mm; Sidelight and Transom Rebate Width: 10 mm; Sidelight and Transom Rebate Depth: 18 mm; Nominal Leaf Width Side 1: 380 mm; Leaf Thickness: 50 mm; Leaf Frame Width Side: 100 mm; Leaf Frame Width Right: 100 mm; Leaf Frame Width Left: 100 mm; Leaf Frame Width Lower: 200 mm; Leaf Frame Width Upper: 100 mm; Leaf Frame Width Internal: 25 mm; Leaf Undercut: 0 mm; Grid Width: 12 mm; Grid Thickness: 25 mm; Glass Thickness: 12 mm; Handle Height: 1000 mm; Handle Position: 50 mm; Kick Board Height: 100 mm; Horizontal Division Height Sidelight Side 1: 900 mm; Horizontal Division Height Sidelight Side 2: 900 mm; Horizontal Division Height Middle Transom: 900 mm; Horizontal Division Height Transom Side 1: 900 mm; Horizontal Division Height Transom Side 2: 900 mm; Sidelight and Transom Frame Thickness: 44 mm; Transom Frame Width (gs_sash_width): 67 mm; Sidelight Frame Width: 67 mm; Grill Width: 20 mm; Grill Thickness: 25 mm; Sidelight Division Width: 40 mm; Sidelight Division Thickness: 90 mm; Architrave Capital Width: 20 mm; Width Side 1 (gs_tw_right_out): 100 mm; Width Side 2 (gs_tw_left_out): 100 mm; Width Top (gs_tw_top_out): 100 mm; Thickness on Wall (gs_trim_thk_out): 12 mm; Thickness in Wallhole (gs_trim_width_out): 25 mm; Offset (gs_trim_offs_out): 0 mm; Nosing (gs_trim_jambext_nosing_out): 50 mm; Top Overhang (gs_trimov_top_left_out): 0 mm; Top Overhang (gs_trimov_top_right_out): 0 mm; Width Side 1 (gs_tw_right_in): 100 mm; Width Side 2 (gs_tw_left_in): 100 mm; Width Top (gs_tw_top_in): 100 mm; Thickness on Wall (gs_trim_thk_in): 10 mm; Thickness in Wallhole (gs_trim_width_in): 25 mm; Offset (gs_trim_offs_in): 40 mm; Nosing (gs_trim_jambext_nosing_in): 50 mm; Top Overhang (gs_trimov_top_left_in): 0 mm; Top Overhang (gs_trimov_top_right_in): 0 mm; Threshold Thickness: 12 mm; Threshold Width: 10 mm; Threshold External Thickness: 5.80738 mm; Threshold Nosing Outside: 10 mm; Threshold Nosing Inside: 10 mm; Side Overhang Outside: 0 mm; Side Overhang Inside: 0 mm; Sill Thickness: 100 mm; Sill Front Side Thickness: 15 mm; Sill Elevation: 5 mm; Sill Drip Overlap: 20 mm; Sill Drip Width: 30 mm; Sill Nosing: 45 mm; Sill Overhang Side 1: 0 mm; Sill Overhang Side 2: 0 mm; Sill Slip-in Depth: 35 mm; Sill Top Width: 10 mm; Sill Top Height: 10 mm; Sill Slip from Wall: 0 mm; Rear Hole Depth (gs_sill_holeDepthBehind): 0 mm; Width of Sill: 80 mm; Brick Thickness (gs_brick_sill_br_thk): 65 mm; Mortar Thickness (gs_brick_sill_mort_thk): 15 mm; Board Width: 100 mm; Board Thickness: 25 mm; Board Nosing: 30 mm; Board Overhang Side 1: 0 mm; Board Overhang Side 2: 0 mm; Board Slip-in Depth: 0 mm; Profile Height: 65 mm; Profile Thickness: 110 mm; Panel Height: 2088 mm; Inner Offset: 20 mm; Closing Depth: 0 mm; Extra Frame Width: 40 mm; Extra Frame Thickness: 30 mm; Rail Width: 30 mm; Hanging Stick Length: 20 mm; Hanging Stick Radius: 5 mm; Panel Distance: 6 mm; Outside Overhang: 0 mm; Inner Panel Width: 120 mm; 3D Opening Length: 1500 mm; 3D Closed Length: 0 mm; 3D Opening Length 1: 560 mm; 3D Opening Length 2: 140 mm; 3D Opening Height: 1500 mm; 3D Closed Height: 0 mm; Panel Thickness: 50 mm; Panel Frame Width: 50 mm; Frame Width Bottom: 50 mm; Panel Width: 388 mm; Panel Fill Thickness: 10 mm; Louver Thickness: 10 mm; Louver Width: 40 mm; Horizontal Frame Divider Width: 50 mm; Vertical Frame Divider Width: 50 mm; Hole Radius: 10 mm; Vertical Board Width: 100 mm; Z Frame Width: 50 mm; Z Frame Thickness: 25 mm; Vertical Boards Thickness: 25 mm; Horizontal Boards Thickness: 25 mm; Vertical Boards Approximate Width: 80 mm; Horizontal Boards Approximate Width: 115 mm; Box Height (gs_shutRoll_boxHeight): 200 mm; Box Depth (gs_shutRoll_boxWidth): 150 mm; Box Left Offset: 0 mm; Box Right Offset: 0 mm; Depth of Rails: 72.5 mm; Distance from Wall (gs_shutRoll_distFromWall): 0 mm; Distance from Header (gs_shutRoll_distFromHead): 0 mm; Slat Width: 50 mm; Box Height (gs_shutLam_boxHeight): 200 mm; Box Depth (gs_shutLam_boxWidth): 150 mm; Cover Width: 0 mm; Distance from Wall (gs_shutLam_distFromWall): 0 mm; Distance from Header (gs_shutLam_distFromHead): 0 mm; Segment Width (gs_shutLam_segmentWidth): 60 mm; Box Height (gs_shutLam2_boxHeight): 60 mm; Box Width: 60 mm; Distance from Window: 60 mm; Distance from Header (gs_shutLam2_distFromHead): 60 mm; Box Axis Height from Header: 0 mm; Segment Width (gs_shutLam2_segmentWidth): 60 mm; Distance between Arch and Door: 0 mm; Masonry Arch Overhang Side 1: 0 mm; Masonry Arch Overhang Side 2: 0 mm; Masonry Arch Rise: 30 mm; Masonry Arch Projection: 0 mm; Masonry Arch Height: 250 mm; Masonry Arch Depth: 120 mm; Rear Hole Depth (gs_masonry_arch_rearHoleDepth): 0 mm; Brick Thickness (gs_masonry_arch_brick_thk): 65 mm; Mortar Thickness (gs_masonry_arch_mort_thk): 10 mm; Keystone Width: 100 mm; Keystone Oversize: 0 mm; Keystone Projection: 10 mm; Reveal Depth (gs_wido_sill): 0 mm; Reveal Depth (AC_wido_sill): 0 mm; Jamb Depth: 60 mm; Jamb Depth Side 2: 60 mm; Lower Jamb Depth Side 1: 60 mm; Lower Jamb Depth Side 2: 60 mm; Inner Jamb Depth Side 2 (gs_reveal_splayed_innerLeft): 60 mm; Inner Jamb Depth (gs_reveal_splayed_innerRight): 60 mm; Inner Jamb Depth (gs_reveal_double_innerRight): 60 mm; Inner Jamb Depth Side 2 (gs_reveal_double_innerLeft): 60 mm; Inner Lower Jamb Depth Side 1: 60 mm; Inner Lower Jamb Depth Side 2: 60 mm; Head Depth: 60 mm; Sill Depth: 60 mm; Sill Depth Side 1: 60 mm; Sill Depth Side 2: 60 mm; Inner Head Depth (gs_reveal_splayed_innerTop): 60 mm; Inner Sill Depth (gs_reveal_splayed_innerBottom): 0 mm; Inner Head Depth (gs_reveal_double_innerTop): 60 mm; Inner Sill Depth (gs_reveal_double_innerBottom): 0 mm; Inner Sill Depth Side 1: 0 mm; Inner Sill Depth Side 2: 0 mm; Outer Jamb Depth: 80 mm; Plaster Thickness Limit: 40 mm; Distance of Skin from Closer: 0 mm; Closer Width: 38 mm; Closer Thickness: 100 mm; Strip Thickness: 25 mm; Profile Width: 150 mm; Custom Thickness: 15 mm; Skin Overhang to Frame Depth: 0 mm; Left Opening Oversize: 0 mm; Right Opening Oversize: 0 mm; Upper Opening Oversize: 0 mm; Lower Opening Oversize: 0 mm; Opening Width in 3D: 0 mm; Opening Width in 3D on Side 2: 0 mm; Opening Width in 2D: 0 mm; Opening Width in 2D on Side 2: 0 mm; Opening Distance 1 Main Sash Side 1: 0 mm; Opening Distance 2 Main Sash Side 1: 0 mm; Opening Distance 1 Main Sash Side 2: 0 mm; Opening Distance 2 Main Sash Side 2: 0 mm; Opening Distance 1 Middle Transom: 0 mm; Opening Distance 2 Middle Transom: 0 mm; Opening Distance 1 Transom Side 1: 0 mm; Opening Distance 2 Transom Side 1: 0 mm; Opening Distance 1 Transom Side 2: 0 mm; Opening Distance 2 Transom Side 2: 0 mm; Opening Side Width 2: 200 mm; Opening Side Width 1: 100 mm; Opening Side Depth: 1000 mm; Opposite Side Width 2: 100 mm; Opposite Side Width 1: 100 mm; Opposite Side Depth: 1000 mm; AC Left Opening Oversize: 50 mm; AC Right Opening Oversize: 50 mm; AC Upper Opening Oversize: 50 mm; AC Lower Opening Oversize: 0 mm; Real Frame Thickness: 140 mm; ID Offset X: 0 mm; ID Offset Y: 0 mm; Custom Text Offset X: 0 mm; Custom Text Offset Y: 0 mm; Leaf Width Offset X: 0 mm; Leaf Width Offset Y: 0 mm
Component Quantities - Component, Component Volume (Net): 0.12348 m3; Component, Component Volume (Gross): 0.12348 m3

# IfcOpeningElement (73)
Name | In | Depth (mm) | Height (mm) | Width (mm) | Area (m2) | Volume (m3)
Apt 03 - J14 | Pavimento tipo | 140 | 950 | 656 | 0.6232 | 0.0113357
Apt 03 - J15 | Pavimento tipo | 140 | 950 | 656 | 0.6232 | 0.0113357
Apt 03 - J16 | Pavimento tipo | 140 | 950 | 656 | 0.6232 | 0.0113357
Apt 03 - J17 | Pavimento tipo | 140 | 950 | 656 | 0.6232 | 0.0113357
Apt 03 - J18 | Pavimento tipo | 140 | 950 | 656 | 0.6232 | 0.0113357
Apt 03 - Porta 06 | Pavimento tipo | 140 | 2170 | 880 | 1.9096 | 0.079904
Apt 02 - J14 | Pavimento tipo | 140 | 950 | 656 | 0.6232 | 0.0113357
Apt 02 - J15 | Pavimento tipo | 140 | 950 | 656 | 0.6232 | 0.0113357
Apt 02 - J16 | Pavimento tipo | 140 | 950 | 656 | 0.6232 | 0.0113357
Apt 02 - J17 | Pavimento tipo | 140 | 950 | 656 | 0.6232 | 0.0113357
Apt 02 - J18 | Pavimento tipo | 140 | 950 | 656 | 0.6232 | 0.0113357
Apt 02 - Porta 06 | Pavimento tipo | 140 | 2170 | 880 | 1.9096 | 0.079904
Apt 01 - J07 | 01 | 140 | 925 | 2260 | 2.0905 | 0.0328775
Apt 01 - J09 | 01 | 140 | 925 | 2260 | 2.0905 | 0.0328775
Apt 01 - J08 | 01 | 140 | 925 | 1370 | 1.26725 | 0.0237525
Apt 01 - Porta 05 | 01 | 90 | 2170 | 780 | 1.6926 | 0.062874
Apt 01 - Porta 04 | 01 | 90 | 2170 | 680 | 1.4756 | 0.056124
Apt 01 - Porta 02 | 01 | 90 | 2170 | 780 | 1.6926 | 0.062874
Apt 01 - Porta 03 | 01 | 90 | 2170 | 780 | 1.6926 | 0.062874
Apt 01 - J06 | 01 | 140 | 925 | 3220 | 2.9785 | 0.0593525
Apt 01 - J05 | 01 | 140 | 1120 | 1200 | 1.344 | 0.024715
Apt 01 - J01 | 01 | 190 | 2560 | 730 | 1.8688 | 0.02895
Apt 01 - J02 | 01 | 190 | 2560 | 730 | 1.8688 | 0.02895
Apt 01 - J03 | 01 | 190 | 2560 | 730 | 1.8688 | 0.02895
Apt 01 - J04 | 01 | 190 | 2560 | 729.989 | 1.86877 | 0.02895
Apt 01 - Vão 01 | 01 | 90 | 2170 | 850 | 1.8445 | 0
Porta 12 | 06 | 140 | 2220 | 900 | 1.998 | 0.12348
Porta 13 | 06 | 90 | 2220 | 900 | 1.998 | 0.11038
J29 | 06 | 140 | 600 | 1300 | 0.78 | 0.012924
Apt 04 - Porta 05 | 04 | 90 | 2170 | 780 | 1.6926 | 0.062874
Apt 04 - Porta 04 | 04 | 90 | 2170 | 680 | 1.4756 | 0.056124
Apt 04 - J06 | 04 | 140 | 925 | 3220 | 2.9785 | 0.0593525
Apt 04 - Vão 01 | 04 | 90 | 2170 | 850 | 1.8445 | 0
Apt 04 - Porta 02 | 04 | 90 | 2170 | 780 | 1.6926 | 0.062874
Apt 04 - J07 | 04 | 140 | 925 | 2260 | 2.0905 | 0.0328775
Apt 04 - J09 | 04 | 140 | 925 | 2260 | 2.0905 | 0.0328775
Apt 04 - J08 | 04 | 140 | 925 | 1370 | 1.26725 | 0.0237525
Apt 04 - Porta 03 | 04 | 90 | 2170 | 780 | 1.6926 | 0.062874
Apt 04 - J01 | 04 | 190 | 2560 | 730 | 1.8688 | 0.02895
Apt 04 - J02 | 04 | 190 | 2560 | 730 | 1.8688 | 0.02895
Apt 04 - J03 | 04 | 190 | 2560 | 730 | 1.8688 | 0.02895
Apt 04 - J04 | 04 | 190 | 2560 | 729.989 | 1.86877 | 0.02895
Apt 04 - J05 | 04 | 140 | 1120 | 1200 | 1.344 | 0.024715
Apt 03 - Porta 07 | 03 | 90 | 2170 | 780 | 1.6926 | 0.062874
Apt 03 - Vão 02 | 03 | 90 | 2200 | 680 | 1.496 | 0
Apt 03 - J13 | 03 | 140 | 590 | 880 | 0.5192 | 0.015714
Apt 03 - Porta 09 | 03 | 140 | 2170 | 680 | 1.4756 | 0.066004
Apt 03 - Porta 08 | 03 | 90 | 2170 | 780 | 1.6926 | 0.062874
Apt 03 - J10 | 03 | 140 | 925 | 2260 | 2.0905 | 0.0328775
Apt 03 - J11 | 03 | 140 | 925 | 2260 | 2.0905 | 0.0328775
Apt 03 - J12 | 03 | 140 | 925 | 2260 | 2.0905 | 0.0328775
Porta 10 | 17 | 140 | 2300 | 810 | 1.863 | 0
Porta 11 | 17 | 140 | 2300 | 810 | 1.863 | 0
Apt 02 - J10 | 02 | 140 | 925 | 2260 | 2.0905 | 0.0328775
Apt 02 - J11 | 02 | 140 | 925 | 2260 | 2.0905 | 0.0328775
Apt 02 - J12 | 02 | 140 | 925 | 2260 | 2.0905 | 0.0328775
Apt 02 - Porta 07 | 02 | 90 | 2170 | 780 | 1.6926 | 0.062874
Apt 02 - J13 | 02 | 140 | 590 | 880 | 0.5192 | 0.015714
Apt 02 - Porta 08 | 02 | 90 | 2170 | 780 | 1.6926 | 0.062874
Apt 02 - Porta 09 | 02 | 140 | 2170 | 680 | 1.4756 | 0.066004
Apt 02 - Vão 02 | 02 | 90 | 2200 | 680 | 1.496 | 0
J19 | Pavimento tipo | 140 | 2560 | 770 | 1.9712 | 0.03007
J20 | Pavimento tipo | 140 | 2560 | 770 | 1.9712 | 0.03007
J21 | Pavimento tipo | 140 | 2560 | 770 | 1.9712 | 0.03007
J22 | Pavimento tipo | 140 | 2560 | 770 | 1.9712 | 0.03007
J23 | Pavimento tipo | 140 | 2560 | 770 | 1.9712 | 0.03007
J24 | Pavimento tipo | 140 | 2560 | 770 | 1.9712 | 0.03007
J25 | Pavimento tipo | 140 | 2560 | 770 | 1.9712 | 0.03007
J26 | Pavimento tipo | 140 | 2560 | 770 | 1.9712 | 0.03007
J27 | Pavimento tipo | 140 | 2560 | 770 | 1.9712 | 0.03007
J28 | Pavimento tipo | 140 | 2560 | 770 | 1.9712 | 0.03007
Apt 01 - Porta 01 | Pavimento tipo | 140 | 2170 | 880 | 1.9096 | 0.079904
Apt 04 - Porta 01 | Pavimento tipo | 140 | 2170 | 880 | 1.9096 | 0.079904

# IfcSlab: Concreto - Estrutural 110 (8)
In: Pavimento tipo
Type - PredefinedType: FLOOR
Description: Laje_interior_generico_in-loco_concreto-armado_110mm; Classification: Laje (Classificação ARCHICAD); 3E 12 06 08 Laje (NBR 15965-5 3E); Material: Concreto - Estrutural
ArchiCADProperties - Reference Plane Location: Top; Structural Analytical Model Generation: yes; Layer: A--LAJE-STRU-E-; Building Material / Composite / Profile / Fill: Concreto - Estrutural; Building Material: Concreto - Estrutural; Locked: no; Home Story Name: Pavimento tipo; Home Story Number: 0; Element Type: Slab; Structure Type: Basic; Building Materials (All): Concreto - Estrutural; Surfaces (All): Concreto - 03; Cover Fill: Trama Vazia; Number of Openings: 0; Top Surface: Concreto - 03; Edge Surface: Concreto - 03; Bottom Surface: Concreto - 03; Position: Interior; Show On Renovation Filter: All Relevant Filters; Structural Function: Load-Bearing Element; Renovation Status: Existing
PISOS (Expressão) - Índice de Perda (%): 10
ESTRUTURA (Expressão) - Custo por Volume (m3): 0; Estimativa de Custo Total por Volume: 0; Estimativa de Custo Total por Volume (R$): 0,00 R$
SUPERFÍCIES (Mapas) - Superfície do Topo (Geral): Concreto - 03; Superfície da Face (Geral): Concreto - 03; Superfície da Base (Geral): Concreto - 03
AC_Pset_RenovationAndPhasing - Renovation Status: Existing
Pset_SlabCommon - IsExternal: no; LoadBearing: yes
Material Properties - Concreto - Estrutural, ThermalConductivity: 2.3; Concreto - Estrutural, SpecificHeatCapacity: 1000 J/kg/K; Concreto - Estrutural, MassDensity: 2300 kg/m3; Concreto - Estrutural, Embodied Energy: 1.92 (MJ/kg); Concreto - Estrutural, Embodied Carbon: 0.198 (kgCO₂/kg); Concreto - Estrutural, Name: Concreto - Estrutural; Concreto - Estrutural, ID: CON; Concreto - Estrutural, Participates in Collision Detection: yes
BaseQuantities - Width: 110 mm
ArchiCADQuantities - Elevation Bottom: -140 mm; Holes Surface Area: 0 m2; Elevation Top: -30 mm; Height: 110 mm; Elevation to Project Zero: -30 mm; Elevation to 1º Nível de Referência: -30 mm; Elevation to 2º Nível de Referência: -30 mm; Elevation to Sea Level: 728190 mm; Elevation to Linked/Home Story: -30 mm; Home Offset: -30 mm; Thickness: 110 mm; Floor Plan Holes Perimeter: 0 mm; Top Elevation To First Reference Level: -30 mm; Top Elevation To Home Story: -30 mm; Top Elevation To Project Zero: -30 mm; Top Elevation To Sea Level: 728190 mm; Top Elevation To Second Reference Level: -30 mm; Bottom Elevation To First Reference Level: -140 mm; Bottom Elevation To Home Story: -140 mm; Bottom Elevation To Project Zero: -140 mm; Bottom Elevation To Sea Level: 728080 mm; Bottom Elevation To Second Reference Level: -140 mm
Component Quantities - Concreto - Estrutural, Component Thickness: 110 mm
Name | Element ID = Hotlink and Element ID = Parent ID | ID Dinâmico por Classificação | Concreto - Estrutural, Embodied Carbon | Concreto - Estrutural, Embodied Energy (MJ) | Perimeter (mm) = Floor Plan Perimeter (mm) | GrossArea (m2) = NetArea (m2) = Surface Area of the Slab Top (Conditional) (m2) = Surface Area of the Slab Bottom (Gross) (m2) = Surface Area of the Slab Bottom (Gross, with holes) (m2) = Surface Area of the Slab Top (Gross) (m2) = Surface Area of the Slab Top (Gross, with holes) (m2) = Area (m2) = Surface Area (m2) = Top Surface Area (Net) (m2) = Top Surface Area (Conditional) (m2) = Bottom Surface Area (Net) (m2) = Bottom Surface Area (Conditional) (m2) = Bottom Surface Area (Gross) (m2) = Top Surface Area (Gross) (m2) = Área da Superfície do Topo (Geral) (m2) = Área da Superfície da Base (Geral) (m2) = Área Condicional da Superfície do Topo (Geral) (m2) = Área Condicional da Superfície da Base (Geral) (m2) = Concreto - Estrutural, Projected Component Area (Net) (m2) = Concreto - Estrutural, Projected Component Area (Gross) (m2) = Concreto - Estrutural, Projected Component Area (Conditional) (m2) | GrossVolume (m3) = NetVolume (m3) = Volume (Net) (m3) = Volume (Conditional) (m3) = Volume (Gross) (m3) = Concreto - Estrutural, Component Volume (Net) (m3) = Concreto - Estrutural, Component Volume (Gross) (m3) = Concreto - Estrutural, Component Volume (Conditional) (m3) | Surface Area of the Slab Edges (Gross) (m2) = Surface Area of the Slab Edges (Gross, with holes) (m2) = Edge Surface Area (Net) (m2) = Edge Surface Area (Gross) (m2) = Área da Superfície da Face (Geral) (m2) | Concreto - Estrutural, Mass (kg)
Laje 06 | Laje 06 | Laje -Laje 06 | 128.872 (kgCO₂) | 1249.67 | 6897.76 | 2.5726 | 0.282986 | 0.758754 | 650.867
Laje 05 | Laje 05 | Laje -Laje 05 | 80.4973 (kgCO₂) | 780.58 | 5074.3 | 1.60692 | 0.176762 | 0.558173 | 406.552
Laje 03 | Laje 03 | Laje -Laje 03 | 176.466 (kgCO₂) | 1711.18 | 7939.99 | 3.5227 | 0.387497 | 0.873399 | 891.242
Laje 09 | Laje 09 | Laje -Laje 09 | 373.105 (kgCO₂) | 3617.99 | 13240.1 | 7.4481 | 0.819291 | 1.45641 | 1884.37
Laje 04 | Laje 04 | Laje -Laje 04 | 128.876 (kgCO₂) | 1249.71 | 6894.34 | 2.57268 | 0.282995 | 0.758377 | 650.888
Laje 08 | Laje 08 | Laje -Laje 08 | 176.416 (kgCO₂) | 1710.7 | 7939.1 | 3.5217 | 0.387387 | 0.873301 | 890.991
Laje 07 | Laje 07 | Laje -Laje 07 | 80.3857 (kgCO₂) | 779.498 | 5070.92 | 1.6047 | 0.176517 | 0.557802 | 405.989
Laje 02 | Laje 02 | Laje -Laje 02 | 373.101 (kgCO₂) | 3617.95 | 13240 | 7.44802 | 0.819283 | 1.4564 | 1884.35

# IfcSlab: Concreto - Estrutural 120 (2)
In: Pavimento tipo
Type - PredefinedType: FLOOR
Description: Laje_interior_generico_in-loco_concreto-armado_140mm; Classification: Laje (Classificação ARCHICAD); 3E 12 06 08 Laje (NBR 15965-5 3E); Material: Concreto - Estrutural
ArchiCADProperties - Reference Plane Location: Top; Structural Analytical Model Generation: yes; Layer: A--LAJE-STRU-E-; Building Material / Composite / Profile / Fill: Concreto - Estrutural; Building Material: Concreto - Estrutural; Locked: no; Home Story Name: Pavimento tipo; Home Story Number: 0; Element Type: Slab; Structure Type: Basic; Building Materials (All): Concreto - Estrutural; Surfaces (All): Concreto - 03; Cover Fill: Trama Vazia; Number of Openings: 0; Top Surface: Concreto - 03; Edge Surface: Concreto - 03; Bottom Surface: Concreto - 03; Position: Interior; Show On Renovation Filter: All Relevant Filters; Structural Function: Load-Bearing Element; Renovation Status: Existing
PISOS (Expressão) - Índice de Perda (%): 10
ESTRUTURA (Expressão) - Custo por Volume (m3): 0; Estimativa de Custo Total por Volume: 0; Estimativa de Custo Total por Volume (R$): 0,00 R$
SUPERFÍCIES (Mapas) - Superfície do Topo (Geral): Concreto - 03; Superfície da Face (Geral): Concreto - 03; Superfície da Base (Geral): Concreto - 03
AC_Pset_RenovationAndPhasing - Renovation Status: Existing
Pset_SlabCommon - IsExternal: no; LoadBearing: yes
Material Properties - Concreto - Estrutural, ThermalConductivity: 2.3; Concreto - Estrutural, SpecificHeatCapacity: 1000 J/kg/K; Concreto - Estrutural, MassDensity: 2300 kg/m3; Concreto - Estrutural, Embodied Energy: 1.92 (MJ/kg); Concreto - Estrutural, Embodied Carbon: 0.198 (kgCO₂/kg); Concreto - Estrutural, Name: Concreto - Estrutural; Concreto - Estrutural, ID: CON; Concreto - Estrutural, Participates in Collision Detection: yes
BaseQuantities - Width: 120 mm
ArchiCADQuantities - Elevation Bottom: -140 mm; Elevation Top: -20 mm; Height: 120 mm; Elevation to Project Zero: -20 mm; Elevation to 1º Nível de Referência: -20 mm; Elevation to 2º Nível de Referência: -20 mm; Elevation to Sea Level: 728200 mm; Elevation to Linked/Home Story: -20 mm; Home Offset: -20 mm; Thickness: 120 mm; Top Elevation To First Reference Level: -20 mm; Top Elevation To Home Story: -20 mm; Top Elevation To Project Zero: -20 mm; Top Elevation To Sea Level: 728200 mm; Top Elevation To Second Reference Level: -20 mm; Bottom Elevation To First Reference Level: -140 mm; Bottom Elevation To Home Story: -140 mm; Bottom Elevation To Project Zero: -140 mm; Bottom Elevation To Sea Level: 728080 mm; Bottom Elevation To Second Reference Level: -140 mm
Component Quantities - Concreto - Estrutural, Component Thickness: 120 mm
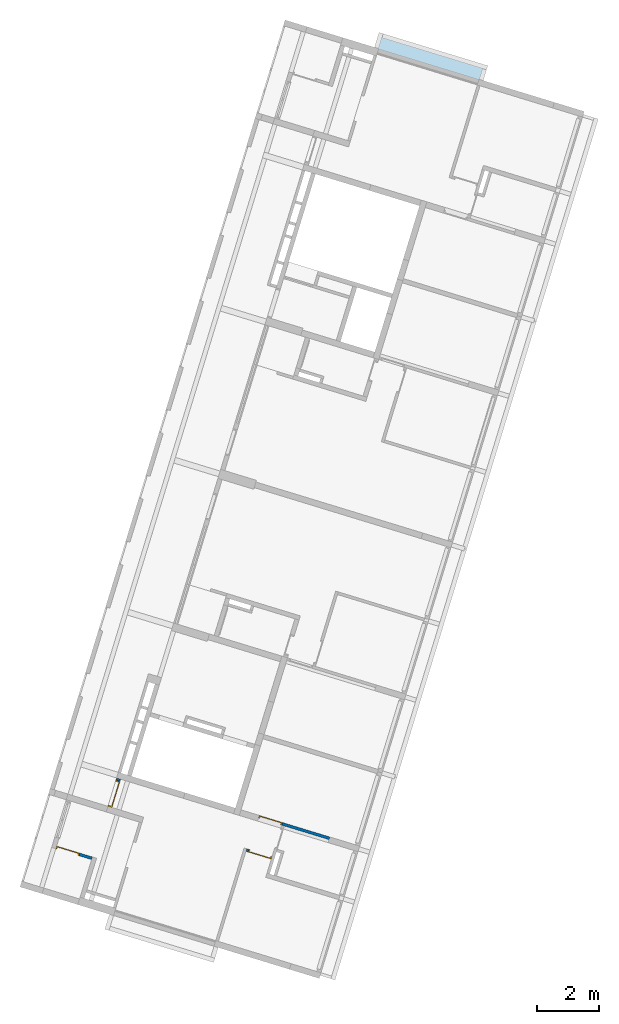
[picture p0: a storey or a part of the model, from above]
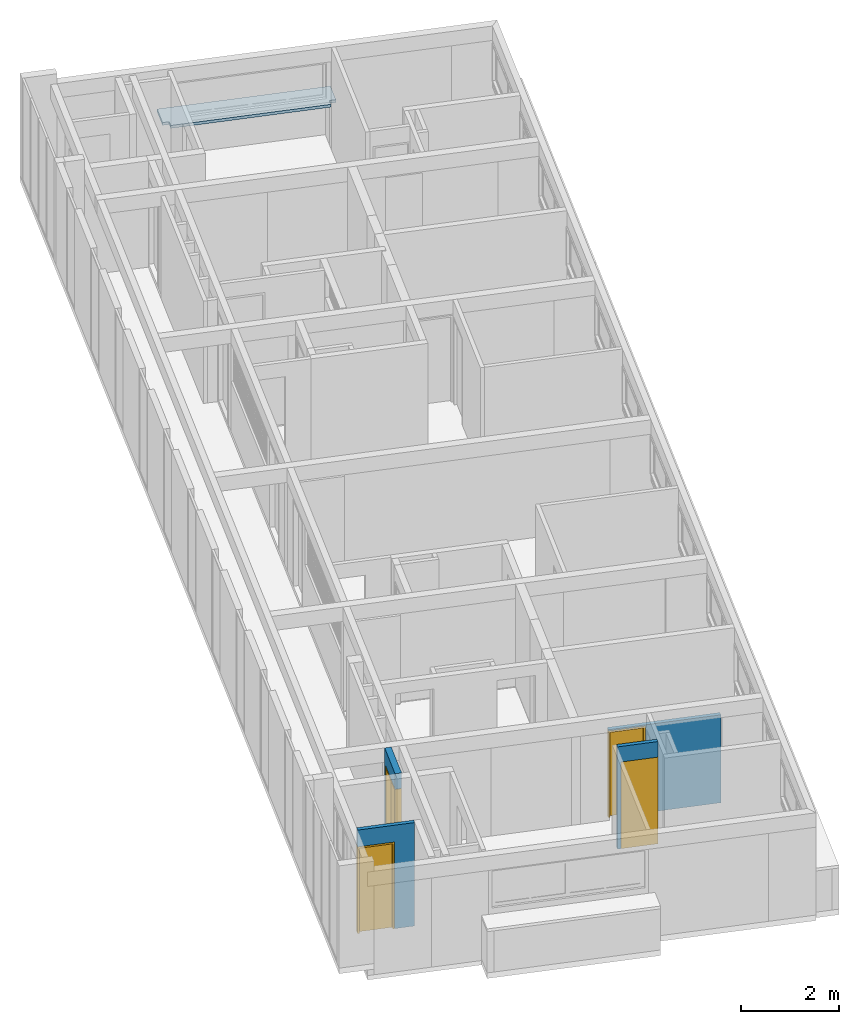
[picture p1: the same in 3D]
Properties of the parts of a building model (IFC2X3), part 5 of 11

# IfcSlab: Concreto - Estrutural 120 (2)
Name | Element ID = Hotlink and Element ID = Parent ID | ID Dinâmico por Classificação | Concreto - Estrutural, Embodied Carbon | Concreto - Estrutural, Embodied Energy (MJ) | Perimeter (mm) | GrossArea (m2) = Surface Area of the Slab Top (Conditional) (m2) = Surface Area of the Slab Bottom (Gross) (m2) = Surface Area of the Slab Top (Gross) (m2) = Top Surface Area (Conditional) (m2) = Bottom Surface Area (Conditional) (m2) = Bottom Surface Area (Gross) (m2) = Top Surface Area (Gross) (m2) = Área Condicional da Superfície do Topo (Geral) (m2) = Área Condicional da Superfície da Base (Geral) (m2) = Concreto - Estrutural, Projected Component Area (Gross) (m2) = Concreto - Estrutural, Projected Component Area (Conditional) (m2) | NetArea (m2) = Surface Area of the Slab Bottom (Gross, with holes) (m2) = Surface Area of the Slab Top (Gross, with holes) (m2) = Area (m2) = Surface Area (m2) = Top Surface Area (Net) (m2) = Bottom Surface Area (Net) (m2) = Área da Superfície do Topo (Geral) (m2) = Área da Superfície da Base (Geral) (m2) = Concreto - Estrutural, Projected Component Area (Net) (m2) | GrossVolume (m3) = Volume (Conditional) (m3) = Volume (Gross) (m3) = Concreto - Estrutural, Component Volume (Gross) (m3) = Concreto - Estrutural, Component Volume (Conditional) (m3) | NetVolume (m3) = Volume (Net) (m3) = Concreto - Estrutural, Component Volume (Net) (m3) | Surface Area of the Slab Edges (Gross) (m2) = Edge Surface Area (Gross) (m2) | Surface Area of the Slab Edges (Gross, with holes) (m2) = Edge Surface Area (Net) (m2) = Área da Superfície da Face (Geral) (m2) | Holes Surface Area (m2) | Floor Plan Perimeter (mm) | Floor Plan Holes Perimeter (mm) | Concreto - Estrutural, Mass (kg)
Laje 16 | Laje 16 | Laje -Laje 16 | 262.66 (kgCO₂) | 2547 | 11179.5 | 4.80639 | 4.80639 | 0.576767 | 0.576767 | 1.34155 | 1.34155 | 0 | 11179.5 | 0 | 1326.56
Laje 15 | Laje 15 | Laje -Laje 15 | 554.237 (kgCO₂) | 5374.42 | 13080 | 10.3144 | 10.1419 | 1.23773 | 1.21703 | 1.5696 | 1.8816 | 0.1725 | 15680 | 2600 | 2799.18

# IfcSlab: Concreto - Estrutural 140 (3)
Type - PredefinedType: FLOOR
Description: Laje_interior_generico_in-loco_concreto-armado_140mm; Classification: Laje (Classificação ARCHICAD); 3E 12 06 08 Laje (NBR 15965-5 3E); Material: Concreto - Estrutural
ArchiCADProperties - Reference Plane Location: Top; Structural Analytical Model Generation: yes; Layer: A--LAJE-STRU-E-; Building Material / Composite / Profile / Fill: Concreto - Estrutural; Building Material: Concreto - Estrutural; Locked: no; Home Story Name: Pavimento tipo; Home Story Number: 0; Element Type: Slab; Structure Type: Basic; Building Materials (All): Concreto - Estrutural; Surfaces (All): Concreto - 03; Cover Fill: Trama Vazia; Number of Openings: 0; Top Surface: Concreto - 03; Edge Surface: Concreto - 03; Bottom Surface: Concreto - 03; Position: Interior; Show On Renovation Filter: All Relevant Filters; Structural Function: Load-Bearing Element; Renovation Status: Existing
PISOS (Expressão) - Índice de Perda (%): 10
ESTRUTURA (Expressão) - Custo por Volume (m3): 0; Estimativa de Custo Total por Volume: 0; Estimativa de Custo Total por Volume (R$): 0,00 R$
SUPERFÍCIES (Mapas) - Superfície do Topo (Geral): Concreto - 03; Superfície da Face (Geral): Concreto - 03; Superfície da Base (Geral): Concreto - 03
AC_Pset_RenovationAndPhasing - Renovation Status: Existing
Pset_SlabCommon - IsExternal: no; LoadBearing: yes
Material Properties - Concreto - Estrutural, ThermalConductivity: 2.3; Concreto - Estrutural, SpecificHeatCapacity: 1000 J/kg/K; Concreto - Estrutural, MassDensity: 2300 kg/m3; Concreto - Estrutural, Embodied Energy: 1.92 (MJ/kg); Concreto - Estrutural, Embodied Carbon: 0.198 (kgCO₂/kg); Concreto - Estrutural, Name: Concreto - Estrutural; Concreto - Estrutural, ID: CON; Concreto - Estrutural, Participates in Collision Detection: yes
BaseQuantities - Width: 140 mm
ArchiCADQuantities - Height: 140 mm; Thickness: 140 mm
Component Quantities - Concreto - Estrutural, Component Thickness: 140 mm
Name | In | Element ID = Hotlink and Element ID = Parent ID | ID Dinâmico por Classificação | Concreto - Estrutural, Embodied Carbon | Concreto - Estrutural, Embodied Energy (MJ) | Perimeter (mm) | GrossArea (m2) = Surface Area of the Slab Bottom (Gross) (m2) = Surface Area of the Slab Top (Gross) (m2) = Bottom Surface Area (Gross) (m2) = Top Surface Area (Gross) (m2) = Concreto - Estrutural, Projected Component Area (Gross) (m2) | NetArea (m2) = Surface Area of the Slab Bottom (Gross, with holes) (m2) = Surface Area of the Slab Top (Gross, with holes) (m2) = Area (m2) = Surface Area (m2) = Top Surface Area (Net) (m2) = Bottom Surface Area (Net) (m2) = Área da Superfície do Topo (Geral) (m2) = Área da Superfície da Base (Geral) (m2) = Concreto - Estrutural, Projected Component Area (Net) (m2) | GrossVolume (m3) = Volume (Conditional) (m3) = Volume (Gross) (m3) = Concreto - Estrutural, Component Volume (Gross) (m3) = Concreto - Estrutural, Component Volume (Conditional) (m3) | NetVolume (m3) = Volume (Net) (m3) = Concreto - Estrutural, Component Volume (Net) (m3) | Elevation Bottom (mm) = Bottom Elevation To First Reference Level (mm) = Bottom Elevation To Home Story (mm) = Bottom Elevation To Project Zero (mm) = Bottom Elevation To Second Reference Level (mm) | Surface Area of the Slab Top (Conditional) (m2) = Top Surface Area (Conditional) (m2) = Bottom Surface Area (Conditional) (m2) = Área Condicional da Superfície do Topo (Geral) (m2) = Área Condicional da Superfície da Base (Geral) (m2) = Concreto - Estrutural, Projected Component Area (Conditional) (m2) | Surface Area of the Slab Edges (Gross) (m2) = Edge Surface Area (Gross) (m2) | Surface Area of the Slab Edges (Gross, with holes) (m2) | Holes Surface Area (m2) | Elevation Top (mm) = Elevation to Project Zero (mm) = Elevation to 1º Nível de Referência (mm) = Elevation to 2º Nível de Referência (mm) = Elevation to Linked/Home Story (mm) = Home Offset (mm) = Top Elevation To First Reference Level (mm) = Top Elevation To Home Story (mm) = Top Elevation To Project Zero (mm) = Top Elevation To Second Reference Level (mm) | Elevation to Sea Level (mm) = Top Elevation To Sea Level (mm) | Floor Plan Perimeter (mm) | Floor Plan Holes Perimeter (mm) | Bottom Elevation To Sea Level (mm) | Edge Surface Area (Net) (m2) = Área da Superfície da Face (Geral) (m2) | Concreto - Estrutural, Mass (kg)
Laje 01 | Pavimento tipo | Laje 01 | Laje -Laje 01 | 12074.8 (kgCO₂) | 117089 | 93300.1 | 205.209 | 189.391 | 28.7293 | 26.5147 | -140 | 189.391 | 13.062 | 19.6096 | 15.8187 | 0 | 728220 | 140068 | 46768.4 | 728080 | 19.6054 | 60983.8
Laje 10 | Pavimento tipo | Laje 10 | Laje -Laje 10 | 2321.43 (kgCO₂) | 22510.9 | 51580 | 37.5032 | 36.4112 | 5.25045 | 5.09757 | -240 | 37.5032 | 7.2212 | 9.14757 | 1.09198 | -100 | 728120 | 65339.8 | 13759.8 | 727980 | 9.14757 | 11724.4
Laje 11 | 01 | Laje 11 | Laje -Laje 11 | 1372.45 (kgCO₂) | 13308.6 | 59660 | 21.5267 | 21.5267 | 3.01373 | 3.01373 | 110 | 21.5267 | 8.3524 | 8.3524 | 0 | 250 | 728470 | 59660 | 0 | 728330 | 8.3524 | 6931.58 | ArchiCADProperties - Colliding Zones: Apartamento 01; Apartamento 04; Corredor

# IfcSlab: Concreto - Estrutural 70 (6)
Type - PredefinedType: FLOOR
Description: Laje_exterior_generico_in-loco_concreto-armado_70mm; Classification: Laje (Classificação ARCHICAD); 3E 12 06 08 Laje (NBR 15965-5 3E); Material: Concreto - Estrutural
ArchiCADProperties - Reference Plane Location: Top; Structural Analytical Model Generation: yes; Layer: A--LAJE-STRU-E-; Building Material / Composite / Profile / Fill: Concreto - Estrutural; Building Material: Concreto - Estrutural; Locked: yes; Home Story Name: Pavimento tipo; Home Story Number: 0; Element Type: Slab; Structure Type: Basic; Building Materials (All): Concreto - Estrutural; Surfaces (All): Concreto - 03; Cover Fill: Trama Vazia; Number of Openings: 0; Top Surface: Concreto - 03; Edge Surface: Concreto - 03; Bottom Surface: Concreto - 03; Position: Exterior; Show On Renovation Filter: All Relevant Filters; Structural Function: Load-Bearing Element; Renovation Status: Existing
PISOS (Expressão) - Índice de Perda (%): 10
ESTRUTURA (Expressão) - Custo por Volume (m3): 0; Estimativa de Custo Total por Volume: 0; Estimativa de Custo Total por Volume (R$): 0,00 R$
SUPERFÍCIES (Mapas) - Superfície do Topo (Geral): Concreto - 03; Superfície da Face (Geral): Concreto - 03; Superfície da Base (Geral): Concreto - 03
AC_Pset_RenovationAndPhasing - Renovation Status: Existing
Pset_SlabCommon - IsExternal: yes; LoadBearing: yes
Material Properties - Concreto - Estrutural, ThermalConductivity: 2.3; Concreto - Estrutural, SpecificHeatCapacity: 1000 J/kg/K; Concreto - Estrutural, MassDensity: 2300 kg/m3; Concreto - Estrutural, Embodied Energy: 1.92 (MJ/kg); Concreto - Estrutural, Embodied Carbon: 0.198 (kgCO₂/kg); Concreto - Estrutural, Name: Concreto - Estrutural; Concreto - Estrutural, ID: CON; Concreto - Estrutural, Participates in Collision Detection: yes
BaseQuantities - Width: 70 mm
ArchiCADQuantities - Elevation Bottom: 1030 mm; Elevation Top: 1100 mm; Height: 70 mm; Elevation to Project Zero: 1100 mm; Elevation to 1º Nível de Referência: 1100 mm; Elevation to 2º Nível de Referência: 1100 mm; Elevation to Sea Level: 729320 mm; Elevation to Linked/Home Story: 1100 mm; Home Offset: 1100 mm; Thickness: 70 mm; Floor Plan Holes Perimeter: 0 mm; Top Elevation To First Reference Level: 1100 mm; Top Elevation To Home Story: 1100 mm; Top Elevation To Project Zero: 1100 mm; Top Elevation To Sea Level: 729320 mm; Top Elevation To Second Reference Level: 1100 mm; Bottom Elevation To First Reference Level: 1030 mm; Bottom Elevation To Home Story: 1030 mm; Bottom Elevation To Project Zero: 1030 mm; Bottom Elevation To Sea Level: 729250 mm; Bottom Elevation To Second Reference Level: 1030 mm
Component Quantities - Concreto - Estrutural, Component Thickness: 70 mm
Name | In | Element ID = Parent ID | Hotlink and Element ID | Colliding Zones | Hotlink Master ID | ID Dinâmico por Classificação | Concreto - Estrutural, Embodied Carbon | Concreto - Estrutural, Embodied Energy (MJ) | Perimeter (mm) = Floor Plan Perimeter (mm) | GrossArea (m2) = Surface Area of the Slab Bottom (Gross) (m2) = Surface Area of the Slab Bottom (Gross, with holes) (m2) = Surface Area of the Slab Top (Gross) (m2) = Surface Area of the Slab Top (Gross, with holes) (m2) = Bottom Surface Area (Gross) (m2) = Top Surface Area (Gross) (m2) | NetArea (m2) = Surface Area of the Slab Top (Conditional) (m2) = Area (m2) = Surface Area (m2) = Top Surface Area (Net) (m2) = Top Surface Area (Conditional) (m2) = Bottom Surface Area (Net) (m2) = Bottom Surface Area (Conditional) (m2) = Área da Superfície do Topo (Geral) (m2) = Área da Superfície da Base (Geral) (m2) = Área Condicional da Superfície do Topo (Geral) (m2) = Área Condicional da Superfície da Base (Geral) (m2) = Concreto - Estrutural, Projected Component Area (Net) (m2) = Concreto - Estrutural, Projected Component Area (Gross) (m2) = Concreto - Estrutural, Projected Component Area (Conditional) (m2) | GrossVolume (m3) = NetVolume (m3) = Volume (Net) (m3) = Volume (Conditional) (m3) = Volume (Gross) (m3) = Concreto - Estrutural, Component Volume (Net) (m3) = Concreto - Estrutural, Component Volume (Gross) (m3) = Concreto - Estrutural, Component Volume (Conditional) (m3) | Surface Area of the Slab Edges (Gross) (m2) = Surface Area of the Slab Edges (Gross, with holes) (m2) = Edge Surface Area (Gross) (m2) | Holes Surface Area (m2) | Edge Surface Area (Net) (m2) = Área da Superfície da Face (Geral) (m2) | Concreto - Estrutural, Mass (kg)
Apt 01 - Laje 12 | 01 | Laje 12 | Apt 01 - Laje 12 | Apartamento 01 | Apt 01 - | Laje -Laje 12 | 73.2174 (kgCO₂) | 709.987 | 8580 | 2.2968 | 2.2968 | 0.160776 | 0.6006 | 0 | 0.6006 | 369.785
Apt 01 - Laje 13 | 01 | Laje 13 | Apt 01 - Laje 13 | Apartamento 01 | Apt 01 - | Laje -Laje 13 | 136.444 (kgCO₂) | 1323.1 | 15430 | 4.2802 | 4.2802 | 0.299614 | 1.0801 | 0.00000140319 | 1.0703 | 689.112
Apt 04 - Laje 13 | 04 | Laje 13 | Apt 04 - Laje 13 | Apartamento 04 | Apt 04 - | Laje -Laje 13 | 136.444 (kgCO₂) | 1323.1 | 15430 | 4.2802 | 4.2802 | 0.299614 | 1.0801 | 0 | 1.0801 | 689.112
Apt 04 - Laje 12 | 04 | Laje 12 | Apt 04 - Laje 12 | Apartamento 04 | Apt 04 - | Laje -Laje 12 | 73.2174 (kgCO₂) | 709.987 | 8580 | 2.2968 | 2.2968 | 0.160776 | 0.6006 | 0 | 0.6006 | 369.785
Apt 03 - Laje 14 | 03 | Laje 14 | Apt 03 - Laje 14 | Apartamento 03 | Apt 03 - | Laje -Laje 14 | 153.865 (kgCO₂) | 1492.03 | 17140 | 4.8267 | 4.8267 | 0.337869 | 1.1998 | 0.00000282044 | 1.18335 | 777.098
Apt 02 - Laje 14 | 02 | Laje 14 | Apt 02 - Laje 14 | Apartamento 02 | Apt 02 - | Laje -Laje 14 | 153.865 (kgCO₂) | 1492.03 | 17140 | 4.8267 | 4.82669 | 0.337869 | 1.1998 | 0.00000736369 | 1.17355 | 777.098

# IfcWall: Tijolo - Estrutural 140 (57)
Classification: Parede (Classificação ARCHICAD); 3E 14 02 00 Parede (NBR 15965-5 3E); Material: Tijolo - Estrutural
Pset_WallCommon - AcousticRating: 0,00
ArchiCADProperties - Wall Complexity: Straight; Geometry Method: Uniform; Inside Face Surface: Tijolo - Comum ao Comprido; Outside Face Surface: Tijolo - Comum ao Comprido; Wall Inside Slant Angle: 90 deg; Wall Outside Slant Angle: 90 deg; Layer: A--PRDE-VEDS-E-; Building Material / Composite / Profile / Fill: Tijolo - Estrutural; Building Material: Tijolo - Estrutural; Home Story Name: Pavimento tipo; Home Story Number: 0; Element Type: Wall; Structure Type: Basic; Building Materials (All): Tijolo - Estrutural; Surfaces (All): Tijolo - Comum ao Comprido; Slant Angle: 90 deg; Number of Openings: 0; Edge Surface: Tijolo - Comum ao Comprido; Show On Renovation Filter: All Relevant Filters; Renovation Status: Existing
CLASSIFICAÇÕES GERAIS - Transmissão Sonora: 0
SUPERFÍCIES (Mapas) - Superfície da Face (Geral): Tijolo - Comum ao Comprido
AC_Pset_RenovationAndPhasing - Renovation Status: Existing
Material Properties - Tijolo - Estrutural, ThermalConductivity: 0.6; Tijolo - Estrutural, SpecificHeatCapacity: 840 J/kg/K; Tijolo - Estrutural, MassDensity: 1500 kg/m3; Tijolo - Estrutural, Embodied Energy: 3 (MJ/kg); Tijolo - Estrutural, Embodied Carbon: 0.24 (kgCO₂/kg); Tijolo - Estrutural, Name: Tijolo - Estrutural; Tijolo - Estrutural, ID: VED; Tijolo - Estrutural, Participates in Collision Detection: yes
BaseQuantities - Width: 140 mm
ArchiCADQuantities - Number of Holes (Number of Empty Openings): 0; Volume of the Columns: 0 m3; Maximum Height of the Wall Skin on the Inside Face: 0 mm; Minimum Height of the Wall Skin on the Inside Face: 0 mm; Maximum Height of the Wall Skin on the Outside Face: 0 mm; Minimum Height of the Wall Skin on the Outside Face: 0 mm; Air Skin Thickness: 0 mm; Wall Component Thickness on the Inside Face: 0 mm; Wall Component Thickness on the Outside Face: 0 mm; End Thickness of the Wall: 140 mm; Surface Area of Empty Openings in the Wall: 0 m2; Width: 140 mm; Thickness: 140 mm; Insulation Skin Thickness: 0 mm
ALVENARIAS (Expressão) - Espessura da Argamassa: 10 mm
Component Quantities - Tijolo - Estrutural, Component Thickness: 140 mm; Tijolo - Estrutural, Rectangular Component Width: 140 mm
Name | In | Description | IsExternal | LoadBearing | Reference Line Location | Structural Analytical Model Generation | Element ID = Parent ID | Hotlink and Element ID | Related Zone Name | Related Zone Number | Locked | Absolute Top Link Story | Relative Top Link Story | Top Link Story | Position | Structural Function | ID Dinâmico por Classificação | Tijolo - Estrutural, Embodied Carbon | Tijolo - Estrutural, Embodied Energy (MJ) | Length (mm) = Average length of the Wall (mm) = Length of the Wall at the Center (mm) | BaseQuantities, Height (mm) = Maximum Height of the Wall (mm) | GrossFootprintArea (m2) = NetFootprintArea (m2) = Area (m2) = Top Surface Area (Net) (m2) | GrossSideArea (m2) | NetSideArea (m2) | GrossVolume (m3) = Volume (Conditional) (m3) = Tijolo - Estrutural, Component Volume (Gross) (m3) | NetVolume (m3) = Volume (Net) (m3) | Number of Doors | Number of Windows | Number of Columns | Minimum Height of the Wall (mm) | Area of the Doors (m2) | Combined Width of Doors (mm) | Area of the Windows (m2) | Combined Width of Windows (mm) | Analytic Surface Area of Openings on the Inside Face (m2) | Analytic Surface Area of Openings on the Outside Face (m2) | Surface Area of the Wall Inside Face (Net) (m2) | Surface Area of the Wall Outside Face (Net) (m2) = Surface Area (m2) = Bottom Surface Area (Net) (m2) | Analytic Volume of the Openings (m3) | Length of Reference Line (mm) | Length of the Wall Inside Face (Conditional) (mm) | Surface Area of the Wall Inside Face (Conditional) (m2) = Tijolo - Estrutural, Projected Component Area (Conditional) (m2) | Length of the Wall Outside Face (Conditional) (mm) | Surface Area of the Wall Outside Face (Conditional) (m2) | Surface Area of the Wall Inside Face (Gross) (m2) | Surface Area of the Wall Outside Face (Gross) (m2) | Length of the Wall on the Inside Face (mm) | Length of the Wall on the Outside Face (mm) | ArchiCADQuantities, Height (mm) = Tijolo - Estrutural, Rectangular Component Height (mm) | Elevation to Project Zero (mm) = Elevation to 1º Nível de Referência (mm) = Elevation to 2º Nível de Referência (mm) = Elevation to Linked/Home Story (mm) = Home Offset (mm) = Bottom Elevation To First Reference Level (mm) = Bottom Elevation To Home Story (mm) = Bottom Elevation To Project Zero (mm) = Bottom Elevation To Second Reference Level (mm) | Elevation to Sea Level (mm) = Bottom Elevation To Sea Level (mm) | Top Offset (mm) | 3D Length (mm) | Volume (Gross) (m3) | Floor Plan Perimeter (mm) | Top Elevation To First Reference Level (mm) = Top Elevation To Home Story (mm) = Top Elevation To Project Zero (mm) = Top Elevation To Second Reference Level (mm) | Top Elevation To Sea Level (mm) | Edge Surface Area (Net) (m2) = Área da Superfície da Face (Geral) (m2) | Tijolo - Estrutural, Mass (kg) | Tijolo - Estrutural, Projected Component Area (Net) (m2) | Tijolo - Estrutural, Projected Component Area (Gross) (m2) | Tijolo - Estrutural, Component Cross Section Area (m2) | Tijolo - Estrutural, Component Volume (Net) (m3) | Tijolo - Estrutural, Component Volume (Conditional) (m3) | Hotlink Master ID | Colliding Zones
Parede 45 | Pavimento tipo | Parede-exterior-generico-in_loco-tijolo_maciço_sem_revestimento-140mm | yes | yes | Center | yes | Parede 45 | Parede 45 | Apartamento 01 | 01 | no | Not Linked | Not Linked | Not Linked | Exterior | Load-Bearing Element | Parede -Parede 45 | 22.2128 (kgCO₂) | 277.66 | 427.894 | 1030 | 0.0599051 | 0.440731 | 0.440731 | 0.0617023 | 0.0617023 | 0 | 0 | 0 | 1030 | 0 | 0 | 0 | 0 | 0 | 0 | 0.440731 | 0.440731 | 0 | 427.894 | 427.894 | 0.440731 | 427.894 | 0.440731 | 0.440731 | 0.440731 | 427.894 | 427.894 | 1030 | 0 | 728220 | 0 | 427.894 | 0.0617023 | 1135.79 | 1030 | 729250 | 0.40821 | 92.5534 | 0.440731 | 0.440731 | 0.1442 | 0.0617023 | 0.0617023
Apt 03 - Parede 34 | Pavimento tipo | Parede-interior-generico-in_loco-tijolo_maciço_sem_revestimento-140mm | no | yes | Center | yes | Parede 34 | Apt 03 - Parede 34 | Corredor | 05 | yes | Not Linked | Not Linked | Not Linked | Interior | Load-Bearing Element | Parede -Parede 34 | 285.032 (kgCO₂) | 3562.9 | 4855 | 2200 | 0.5565 | 10.681 | 5.6554 | 1.49534 | 0.791756 | 1 | 5 | 2 | 2200 | 1.9096 | 880 | 3.116 | 3280 | 5.0256 | 5.0256 | 5.6554 | 5.6554 | 0.703584 | 4855 | 3975 | 7.565 | 3975 | 7.565 | 10.681 | 10.681 | 4855 | 4855 | 2200 | 0 | 728220 | -500 | 4855 | 1.49534 | 9990 | 2200 | 730420 | 1.26 | 1187.63 | 5.6554 | 10.681 | 0.308 | 0.791756 | 1.49534 | Apt 03 -
Apt 03 - Parede 68 | Pavimento tipo | Parede-exterior-generico-in_loco-tijolo_maciço_sem_revestimento-140mm | yes | yes | Inside Face | yes | Parede 68 | Apt 03 - Parede 68 |  |  | yes | Not Linked | Not Linked | Not Linked | Exterior | Load-Bearing Element | Parede -Parede 68 | 397.127 (kgCO₂) | 4964.08 | 7649.99 | 1030 | 1.071 | 7.87949 | 7.87949 | 1.10313 | 1.10313 | 0 | 0 | 0 | 1030 | 0 | 0 | 0 | 0 | 0 | 0 | 7.87949 | 7.87949 | 0 | 7649.99 | 7649.99 | 7.87949 | 7649.99 | 7.87949 | 7.87949 | 7.87949 | 7649.99 | 7649.99 | 1030 | 0 | 728220 | 0 | 7649.99 | 1.10313 | 15580 | 1030 | 729250 | 2.4304 | 1654.69 | 7.87949 | 7.87949 | 0.1442 | 1.10313 | 1.10313 | Apt 03 -
Parede 60 | Pavimento tipo | Parede-interior-generico-in_loco-tijolo_maciço_sem_revestimento-140mm | no | yes | Outside Face | yes | Parede 60 | Parede 60 | Escada | 06 | no | Vazio | Home + 1 | Home + 1 (Vazio) | Interior | Load-Bearing Element | Parede -Parede 60 | 448.019 (kgCO₂) | 5600.24 | 3864.9 | 2300 | 0.541086 | 8.88927 | 8.88927 | 1.2445 | 1.2445 | 0 | 0 | 0 | 0 | 0 | 0 | 0 | 0 | 0 | 0 | 8.88927 | 8.88927 | -1.55431e-15 | 3864.9 | 3864.9 | 8.88927 | 3864.9 | 8.88927 | 9.89414 | 9.89414 | 3864.9 | 3864.9 | 2560 | -100 | 728120 | -240 | 3864.9 | 1.38518 | 8009.8 | 2200 | 730420 | 0.863086 | 1866.75 | 8.88927 | 8.88927 | 0.3584 | 1.2445 | 1.2445
Parede 48 | Pavimento tipo | Parede-exterior-generico-in_loco-tijolo_maciço_sem_revestimento-140mm | yes | yes | Center | yes | Parede 48 | Parede 48 | Apartamento 03 | 03 | no | Not Linked | Not Linked | Not Linked | Exterior | Load-Bearing Element | Parede -Parede 48 | 22.2128 (kgCO₂) | 277.66 | 427.894 | 1030 | 0.0599051 | 0.440731 | 0.440731 | 0.0617023 | 0.0617023 | 0 | 0 | 1 | 1030 | 0 | 0 | 0 | 0 | 0 | 0 | 0.440731 | 0.440731 | 0 | 427.894 | 427.894 | 0.440731 | 427.894 | 0.440731 | 0.440731 | 0.440731 | 427.894 | 427.894 | 1030 | 0 | 728220 | -140 | 427.894 | 0.0617023 | 1135.79 | 1030 | 729250 | 0.40821 | 92.5534 | 0.440731 | 0.440731 | 0.1442 | 0.0617023 | 0.0617023
Apt 04 - Parede 58 | Pavimento tipo | Parede-exterior-generico-in_loco-tijolo_maciço_sem_revestimento-140mm | yes | yes | Outside Face | yes | Parede 58 | Apt 04 - Parede 58 |  |  | yes | Not Linked | Not Linked | Not Linked | Exterior | Load-Bearing Element | Parede -Parede 58 | 352.742 (kgCO₂) | 4409.28 | 6750.01 | 1030 | 0.951301 | 6.99886 | 6.99886 | 0.97984 | 0.97984 | 0 | 0 | 0 | 0 | 0 | 0 | 0 | 0 | 0 | 0 | 6.99886 | 6.99886 | 0 | 6795.01 | 6705.01 | 6.99886 | 6795.01 | 6.99886 | 6.99886 | 6.99886 | 6705.01 | 6795.01 | 1030 | 0 | 728220 | 0 | 6795.01 | 0.97984 | 13806.5 | 1030 | 729250 | 2.0468 | 1469.76 | 6.99886 | 6.99886 | 0.1442 | 0.97984 | 0.97984 | Apt 04 -
Apt 02 - Parede 68 | Pavimento tipo | Parede-exterior-generico-in_loco-tijolo_maciço_sem_revestimento-140mm | yes | yes | Inside Face | yes | Parede 68 | Apt 02 - Parede 68 |  |  | yes | Not Linked | Not Linked | Not Linked | Exterior | Load-Bearing Element | Parede -Parede 68 | 397.127 (kgCO₂) | 4964.08 | 7649.99 | 1030 | 1.071 | 7.87949 | 7.87949 | 1.10313 | 1.10313 | 0 | 0 | 0 | 1030 | 0 | 0 | 0 | 0 | 0 | 0 | 7.87949 | 7.87949 | 0 | 7649.99 | 7649.99 | 7.87949 | 7649.99 | 7.87949 | 7.87949 | 7.87949 | 7649.99 | 7649.99 | 1030 | 0 | 728220 | 0 | 7649.99 | 1.10313 | 15580 | 1030 | 729250 | 2.4304 | 1654.69 | 7.87949 | 7.87949 | 0.1442 | 1.10313 | 1.10313 | Apt 02 -
Apt 02 - Parede 34 | Pavimento tipo | Parede-interior-generico-in_loco-tijolo_maciço_sem_revestimento-140mm | no | yes | Center | yes | Parede 34 | Apt 02 - Parede 34 | Corredor | 05 | yes | Not Linked | Not Linked | Not Linked | Interior | Load-Bearing Element | Parede -Parede 34 | 285.032 (kgCO₂) | 3562.9 | 4855 | 2200 | 0.5565 | 10.681 | 5.6554 | 1.49534 | 0.791756 | 1 | 5 | 2 | 2200 | 1.9096 | 880 | 3.116 | 3280 | 5.0256 | 5.0256 | 5.6554 | 5.6554 | 0.703584 | 4855 | 3975 | 7.565 | 3975 | 7.565 | 10.681 | 10.681 | 4855 | 4855 | 2200 | 0 | 728220 | -500 | 4855 | 1.49534 | 9990 | 2200 | 730420 | 1.26 | 1187.63 | 5.6554 | 10.681 | 0.308 | 0.791756 | 1.49534 | Apt 02 -
Parede 67 | 01 | Parede-interior-generico-in_loco-tijolo_maciço_sem_revestimento-140mm | no | yes | Outside Face | yes | Parede 67 | Parede 67 | Apartamento 01 | 01 | no | Not Linked | Not Linked | Not Linked | Interior | Load-Bearing Element | Parede -Parede 67 | 10.6546 (kgCO₂) | 133.182 | 1510 | 140 | 0.2114 | 0.2114 | 0.2114 | 0.029596 | 0.029596 | 0 | 0 | 0 | 140 | 0 | 0 | 0 | 0 | 0 | 0 | 0.2114 | 0.2114 | 0 | 1510 | 1510 | 0.2114 | 1510 | 0.2114 | 0.2114 | 0.2114 | 1510 | 1510 | 140 | -30 | 728190 | 0 | 1510 | 0.029596 | 3300 | 110 | 728330 | 0.462 | 44.394 | 0.2114 | 0.2114 | 0.0196 | 0.029596 | 0.029596 |  | Apartamento 01
Parede 66 | 01 | Parede-interior-generico-in_loco-tijolo_maciço_sem_revestimento-140mm | no | yes | Center | yes | Parede 66 | Parede 66 | Apartamento 01 | 01 | no | Vazio | Home + 1 | Home + 1 (Vazio) | Interior | Load-Bearing Element | Parede -Parede 66 | 495.452 (kgCO₂) | 6193.16 | 3935 | 2560 | 0.5376 | 9.83041 | 9.83041 | 1.37626 | 1.37626 | 0 | 0 | 0 | 0 | 0 | 0 | 0 | 0 | 0 | 0 | 9.83041 | 9.83041 | 0 | 3935 | 4030 | 9.83041 | 3840 | 9.83041 | 10.3168 | 10.3168 | 4030 | 3840 | 2560 | 0 | 728220 | -140 | 3840 | 1.44435 | 8246.01 | 2560 | 730780 | 1.4336 | 2064.39 | 9.83041 | 9.83041 | 0.3584 | 1.37626 | 1.37626 |  | Apartamento 01
Apt 01 - Parede 24 | 01 | Parede-exterior-generico-in_loco-tijolo_maciço_sem_revestimento-140mm | yes | yes | Outside Face | yes | Parede 24 | Apt 01 - Parede 24 | Apartamento 01 | 01 | yes | Not Linked | Not Linked | Not Linked | Exterior | Load-Bearing Element | Parede -Parede 24 | 86.6001 (kgCO₂) | 1082.5 | 6705.01 | 1100 | 0.912103 | 7.16651 | 1.71826 | 1.00331 | 0.240557 | 0 | 3 | 1 | 0 | 0 | 0 | 5.44825 | 5890 | 5.44825 | 5.44825 | 1.71826 | 1.71826 | 0.762756 | 6705.01 | 6705.01 | 2.98551 | 6705.01 | 2.98551 | 7.37551 | 7.37551 | 6705.01 | 6705.01 | 1100 | 1100 | 729320 | -500 | 6515.01 | 1.03257 | 13690 | 2200 | 730420 | 2.13221 | 360.834 | 1.71826 | 7.16651 | 0.154 | 0.240556 | 1.00331 | Apt 01 - | Apartamento 01
Apt 01 - Parede 11 | 01 | Parede-interior-generico-in_loco-tijolo_maciço_sem_revestimento-140mm | no | yes | Inside Face | yes | Parede 11 | Apt 01 - Parede 11 | Apartamento 01 | 01 | yes | Not Linked | Not Linked | Not Linked | Interior | Load-Bearing Element | Parede -Parede 11 | 323.871 (kgCO₂) | 4048.38 | 2405 | 2560 | 0.3626 | 6.426 | 6.426 | 0.89964 | 0.89964 | 0 | 0 | 0 | 0 | 0 | 0 | 0 | 0 | 0 | 0 | 6.426 | 6.426 | 0 | 2590 | 2450 | 6.426 | 2360 | 6.426 | 6.6304 | 6.6304 | 2450 | 2360 | 2560 | 0 | 728220 | -140 | 2590 | 0.928256 | 5116.43 | 2560 | 730780 | 0.7056 | 1349.46 | 6.426 | 6.426 | 0.3584 | 0.89964 | 0.89964 | Apt 01 - | Apartamento 01
Apt 01 - Parede 27 | 01 | Parede-exterior-generico-in_loco-tijolo_maciço_sem_revestimento-140mm | yes | yes | Outside Face | yes | Parede 27 | Apt 01 - Parede 27 | Apartamento 01 | 01 | yes | Not Linked | Not Linked | Not Linked | Exterior | Load-Bearing Element | Parede -Parede 27 | 18.6883 (kgCO₂) | 233.604 | 430 | 1030 | 0.0504 | 0.3708 | 0.3708 | 0.051912 | 0.051912 | 0 | 0 | 0 | 0 | 0 | 0 | 0 | 0 | 0 | 0 | 0.3708 | 0.3708 | 0 | 500 | 360 | 0.3708 | 500 | 0.3708 | 0.7107 | 0.7107 | 360 | 500 | 1030 | 0 | 728220 | -140 | 360 | 0.099498 | 1197.99 | 1030 | 729250 | 0.1008 | 77.8681 | 0.3708 | 0.3708 | 0.1442 | 0.051912 | 0.051912 | Apt 01 - | Apartamento 01
Apt 01 - Parede 17 | 01 | Parede-interior-generico-in_loco-tijolo_maciço_sem_revestimento-140mm | no | yes | Center | yes | Parede 17 | Apt 01 - Parede 17 | Apartamento 01 | 01 | yes | Not Linked | Not Linked | Not Linked | Interior | Load-Bearing Element | Parede -Parede 17 | 176.222 (kgCO₂) | 2202.78 | 1304.99 | 2590 | 0.188999 | 3.49647 | 3.49647 | 0.489506 | 0.489506 | 0 | 0 | 0 | 0 | 0 | 0 | 0 | 0 | 0 | 0 | 3.49647 | 3.49647 | 0 | 1349.99 | 1349.99 | 3.49647 | 1259.99 | 3.49647 | 3.49647 | 3.49647 | 1349.99 | 1259.99 | 2590 | -30 | 728190 | -140 | 1349.99 | 0.489506 | 2916.41 | 2560 | 730780 | 0.740597 | 734.26 | 3.49647 | 3.49647 | 0.3626 | 0.489506 | 0.489506 | Apt 01 - | Apartamento 01
Apt 01 - Parede 26 | 01 | Parede-exterior-generico-in_loco-tijolo_maciço_sem_revestimento-140mm | yes | yes | Outside Face | yes | Parede 26 | Apt 01 - Parede 26 | Apartamento 01 | 01 | yes | Not Linked | Not Linked | Not Linked | Exterior | Load-Bearing Element | Parede -Parede 26 | 182.211 (kgCO₂) | 2277.64 | 3510 | 1030 | 0.4914 | 3.6153 | 3.6153 | 0.506142 | 0.506142 | 0 | 0 | 0 | 0 | 0 | 0 | 0 | 0 | 0 | 0 | 3.6153 | 3.6153 | 0 | 3510 | 3370 | 3.6153 | 3650 | 3.6153 | 3.7595 | 3.7595 | 3370 | 3650 | 1030 | 0 | 728220 | -140 | 3510 | 0.52633 | 7415.98 | 1030 | 729250 | 0.9828 | 759.213 | 3.6153 | 3.6153 | 0.1442 | 0.506142 | 0.506142 | Apt 01 - | Apartamento 01
Apt 01 - Parede 43 | 01 | Parede-exterior-generico-in_loco-tijolo_maciço_sem_revestimento-140mm | yes | yes | Outside Face | yes | Parede 43 | Apt 01 - Parede 43 | Apartamento 01 | 01 | yes | Not Linked | Not Linked | Not Linked | Exterior | Load-Bearing Element | Parede -Parede 43 | 18.6883 (kgCO₂) | 233.604 | 360.001 | 1030 | 0.0504001 | 0.370801 | 0.370801 | 0.0519121 | 0.0519121 | 0 | 0 | 0 | 0 | 0 | 0 | 0 | 0 | 0 | 0 | 0.370801 | 0.370801 | 0 | 500.001 | 360.001 | 0.370801 | 360.001 | 0.370801 | 0.515001 | 0.515001 | 360.001 | 360.001 | 1030 | 0 | 728220 | -140 | 360.001 | 0.0721001 | 1000 | 1030 | 729250 | 0.245 | 77.8681 | 0.370801 | 0.370801 | 0.1442 | 0.0519121 | 0.0519121 | Apt 01 - | Apartamento 01
Apt 01 - Parede 03 | 01 | Parede-exterior-generico-in_loco-tijolo_maciço_sem_revestimento-140mm | yes | yes | Outside Face | yes | Parede 03 | Apt 01 - Parede 03 | Apartamento 01 | 01 | yes | Not Linked | Not Linked | Not Linked | Exterior | Load-Bearing Element | Parede -Parede 03 | 36.7165 (kgCO₂) | 458.956 | 3370 | 1100 | 0.4718 | 3.707 | 0.728502 | 0.51898 | 0.10199 | 0 | 1 | 1 | 1100 | 0 | 0 | 2.9785 | 3220 | 2.9785 | 2.9785 | 0.728502 | 0.728502 | 0.41699 | 3370 | 3370 | 0.728502 | 3370 | 0.728502 | 3.707 | 3.707 | 3370 | 3370 | 1100 | 1100 | 729320 | -500 | 3370 | 0.51898 | 7020 | 2200 | 730420 | 1.2516 | 152.985 | 0.728502 | 3.707 | 0.154 | 0.10199 | 0.51898 | Apt 01 - | Apartamento 01
Apt 01 - Parede 44 | 01 | Parede-exterior-generico-in_loco-tijolo_maciço_sem_revestimento-140mm | yes | yes | Center | yes | Parede 44 | Apt 01 - Parede 44 | Apartamento 01 | 01 | yes | Not Linked | Not Linked | Not Linked | Exterior | Load-Bearing Element | Parede -Parede 44 | 18.6883 (kgCO₂) | 233.604 | 360 | 1030 | 0.0504 | 0.3708 | 0.3708 | 0.051912 | 0.051912 | 0 | 0 | 1 | 0 | 0 | 0 | 0 | 0 | 0 | 0 | 0.3708 | 0.3708 | 0 | 500 | 360 | 0.3708 | 360 | 0.3708 | 0.515 | 0.515 | 360 | 360 | 1030 | 0 | 728220 | -140 | 360 | 0.0721 | 1000 | 1030 | 729250 | 0.245 | 77.8681 | 0.3708 | 0.3708 | 0.1442 | 0.051912 | 0.051912 | Apt 01 - | Apartamento 01
Apt 01 - Parede 16 | 01 | Parede-interior-generico-in_loco-tijolo_maciço_sem_revestimento-140mm | no | yes | Outside Face | yes | Parede 16 | Apt 01 - Parede 16 | Apartamento 01 | 01 | yes | Not Linked | Not Linked | Not Linked | Interior | Load-Bearing Element | Parede -Parede 16 | 100.801 (kgCO₂) | 1260.02 | 1555.01 | 2230 | 0.224002 | 3.34403 | 2.00003 | 0.468164 | 0.280004 | 0 | 1 | 0 | 0 | 0 | 0 | 1.344 | 1200 | 1.344 | 1.344 | 2.00003 | 2.00003 | 0.18816 | 1700.01 | 1600.01 | 3.34403 | 1510.01 | 3.34403 | 3.99173 | 3.99173 | 1600.01 | 1510.01 | 2230 | -30 | 728190 | -500 | 1600.02 | 0.558842 | 3416.46 | 2200 | 730420 | 0.448004 | 420.006 | 2.00003 | 3.34403 | 0.3122 | 0.280004 | 0.468164 | Apt 01 - | Apartamento 01
Parede 79 | 06 | Parede-interior-generico-in_loco-tijolo_maciço_sem_revestimento-140mm | no | yes | Outside Face | yes | Parede 79 | Parede 79 | Corredor | 05 | no | Vazio | Home + 1 | Home + 1 (Vazio) | Interior | Load-Bearing Element | Parede -Parede 79 | 10.4175 (kgCO₂) | 130.218 | 984.998 | 2220 | 0.1379 | 2.1867 | 0.206696 | 0.306137 | 0.0289374 | 1 | 0 | 1 | 2220 | 1.998 | 800 | 0 | 0 | 1.98 | 1.98 | 0.206696 | 0.206696 | 0.2772 | 984.998 | 84.998 | 2.1867 | 984.998 | 2.1867 | 2.54129 | 2.54129 | 984.998 | 984.998 | 2580 | -20 | 728200 | -140 | 984.998 | 0.355781 | 2250 | 2200 | 730420 | 0.7595 | 43.4061 | 0.206696 | 2.1867 | 0.3612 | 0.0289374 | 0.306137 |  | Escada
Parede 77 | 06 | Parede-interior-generico-in_loco-tijolo_maciço_sem_revestimento-140mm | no | yes | Inside Face | yes | Parede 77 | Parede 77 | Escada | 06 | no | Vazio | Home + 1 | Home + 1 (Vazio) | Interior | Load-Bearing Element | Parede -Parede 77 | 327.696 (kgCO₂) | 4096.2 | 2455 | 2600 | 0.3633 | 6.5019 | 6.5019 | 0.910266 | 0.910266 | 0 | 0 | 0 | 0 | 0 | 0 | 0 | 0 | 0 | 0 | 6.5019 | 6.5019 | 0 | 2505 | 2410 | 6.5019 | 2500 | 6.5019 | 6.9902 | 6.9902 | 2410 | 2500 | 2600 | -20 | 728200 | -120 | 2595 | 0.978628 | 5216.43 | 2580 | 730800 | 0.7133 | 1365.4 | 6.5019 | 6.5019 | 0.364 | 0.910266 | 0.910266 |  | Escada
Parede 75 | 06 | Parede-interior-generico-in_loco-tijolo_maciço_sem_revestimento-140mm | no | yes | Inside Face | yes | Parede 75 | Parede 75 | Escada | 06 | no | Vazio | Home + 1 | Home + 1 (Vazio) | Interior | Load-Bearing Element | Parede -Parede 75 | 199.182 (kgCO₂) | 2489.78 | 1820.01 | 2600 | 0.254801 | 4.73203 | 3.95203 | 0.662484 | 0.553284 | 0 | 1 | 0 | 0 | 0 | 0 | 0.78 | 1300 | 0.78 | 0.78 | 3.95203 | 3.95203 | 0.1092 | 1820.01 | 1820.01 | 4.73203 | 1820.01 | 4.73203 | 5.09603 | 5.09603 | 1820.01 | 1820.01 | 2600 | -20 | 728200 | -120 | 1820.01 | 0.713444 | 3920.02 | 2580 | 730800 | 0.873603 | 829.925 | 3.95203 | 4.73203 | 0.364 | 0.553284 | 0.662484 |  | Escada
Apt 04 - Parede 43 | 04 | Parede-exterior-generico-in_loco-tijolo_maciço_sem_revestimento-140mm | yes | yes | Outside Face | yes | Parede 43 | Apt 04 - Parede 43 | Apartamento 04 | 04 | yes | Not Linked | Not Linked | Not Linked | Exterior | Load-Bearing Element | Parede -Parede 43 | 18.6883 (kgCO₂) | 233.604 | 360.001 | 1030 | 0.0504001 | 0.370801 | 0.370801 | 0.0519121 | 0.0519121 | 0 | 0 | 0 | 0 | 0 | 0 | 0 | 0 | 0 | 0 | 0.370801 | 0.370801 | 0 | 500.001 | 360.001 | 0.370801 | 360.001 | 0.370801 | 0.515001 | 0.515001 | 360.001 | 360.001 | 1030 | 0 | 728220 | -140 | 360.001 | 0.0721001 | 1000 | 1030 | 729250 | 0.245 | 77.8681 | 0.370801 | 0.370801 | 0.1442 | 0.0519121 | 0.0519121 | Apt 04 - | Apartamento 04
Apt 04 - Parede 11 | 04 | Parede-interior-generico-in_loco-tijolo_maciço_sem_revestimento-140mm | no | yes | Inside Face | yes | Parede 11 | Apt 04 - Parede 11 | Apartamento 04 | 04 | yes | Not Linked | Not Linked | Not Linked | Interior | Load-Bearing Element | Parede -Parede 11 | 323.87 (kgCO₂) | 4048.38 | 2405 | 2560 | 0.3626 | 6.426 | 6.426 | 0.89964 | 0.89964 | 0 | 0 | 0 | 0 | 0 | 0 | 0 | 0 | 0 | 0 | 6.426 | 6.426 | 0 | 2590 | 2450 | 6.426 | 2360 | 6.426 | 6.6304 | 6.6304 | 2450 | 2360 | 2560 | 0 | 728220 | -140 | 2590 | 0.928256 | 5116.43 | 2560 | 730780 | 0.7056 | 1349.46 | 6.426 | 6.426 | 0.3584 | 0.89964 | 0.89964 | Apt 04 - | Apartamento 04
Parede 70 | 04 | Parede-interior-generico-in_loco-tijolo_maciço_sem_revestimento-140mm | no | yes | Inside Face | yes | Parede 70 | Parede 70 | Apartamento 04 | 04 | no | Not Linked | Not Linked | Not Linked | Interior | Load-Bearing Element | Parede -Parede 70 | 9.63145 (kgCO₂) | 120.393 | 1460 | 140 | 0.1911 | 0.1911 | 0.1911 | 0.026754 | 0.026754 | 0 | 0 | 0 | 0 | 0 | 0 | 0 | 0 | 0 | 0 | 0.1911 | 0.1911 | 0 | 1460 | 1365 | 0.1911 | 1555 | 0.1911 | 0.2177 | 0.2177 | 1365 | 1555 | 140 | -30 | 728190 | 0 | 1365 | 0.030478 | 3296.01 | 110 | 728330 | 0.4018 | 40.131 | 0.1911 | 0.1911 | 0.0196 | 0.026754 | 0.026754 |  | Apartamento 04
Apt 04 - Parede 26 | 04 | Parede-exterior-generico-in_loco-tijolo_maciço_sem_revestimento-140mm | yes | yes | Outside Face | yes | Parede 26 | Apt 04 - Parede 26 | Apartamento 04 | 04 | yes | Not Linked | Not Linked | Not Linked | Exterior | Load-Bearing Element | Parede -Parede 26 | 182.211 (kgCO₂) | 2277.64 | 3510 | 1030 | 0.4914 | 3.6153 | 3.6153 | 0.506142 | 0.506142 | 0 | 0 | 0 | 0 | 0 | 0 | 0 | 0 | 0 | 0 | 3.6153 | 3.6153 | 0 | 3510 | 3370 | 3.6153 | 3650 | 3.6153 | 3.7595 | 3.7595 | 3370 | 3650 | 1030 | 0 | 728220 | -140 | 3510 | 0.52633 | 7415.98 | 1030 | 729250 | 0.9828 | 759.213 | 3.6153 | 3.6153 | 0.1442 | 0.506142 | 0.506142 | Apt 04 - | Apartamento 04
Apt 04 - Parede 44 | 04 | Parede-exterior-generico-in_loco-tijolo_maciço_sem_revestimento-140mm | yes | yes | Center | yes | Parede 44 | Apt 04 - Parede 44 | Apartamento 04 | 04 | yes | Not Linked | Not Linked | Not Linked | Exterior | Load-Bearing Element | Parede -Parede 44 | 18.6883 (kgCO₂) | 233.604 | 360 | 1030 | 0.0504 | 0.3708 | 0.3708 | 0.051912 | 0.051912 | 0 | 0 | 1 | 0 | 0 | 0 | 0 | 0 | 0 | 0 | 0.3708 | 0.3708 | 0 | 500 | 360 | 0.3708 | 360 | 0.3708 | 0.515 | 0.515 | 360 | 360 | 1030 | 0 | 728220 | -140 | 360 | 0.0721 | 1000 | 1030 | 729250 | 0.245 | 77.8681 | 0.3708 | 0.3708 | 0.1442 | 0.051912 | 0.051912 | Apt 04 - | Apartamento 04
Apt 04 - Parede 27 | 04 | Parede-exterior-generico-in_loco-tijolo_maciço_sem_revestimento-140mm | yes | yes | Outside Face | yes | Parede 27 | Apt 04 - Parede 27 | Apartamento 04 | 04 | yes | Not Linked | Not Linked | Not Linked | Exterior | Load-Bearing Element | Parede -Parede 27 | 18.6883 (kgCO₂) | 233.604 | 430 | 1030 | 0.0504 | 0.3708 | 0.3708 | 0.051912 | 0.051912 | 0 | 0 | 0 | 0 | 0 | 0 | 0 | 0 | 0 | 0 | 0.3708 | 0.3708 | 0 | 500 | 360 | 0.3708 | 500 | 0.3708 | 0.7107 | 0.7107 | 360 | 500 | 1030 | 0 | 728220 | -140 | 360 | 0.099498 | 1197.99 | 1030 | 729250 | 0.1008 | 77.8681 | 0.3708 | 0.3708 | 0.1442 | 0.051912 | 0.051912 | Apt 04 - | Apartamento 04
Apt 04 - Parede 03 | 04 | Parede-exterior-generico-in_loco-tijolo_maciço_sem_revestimento-140mm | yes | yes | Outside Face | yes | Parede 03 | Apt 04 - Parede 03 | Apartamento 04 | 04 | yes | Not Linked | Not Linked | Not Linked | Exterior | Load-Bearing Element | Parede -Parede 03 | 36.7165 (kgCO₂) | 458.956 | 3370 | 1100 | 0.4718 | 3.707 | 0.728502 | 0.51898 | 0.10199 | 0 | 1 | 1 | 1100 | 0 | 0 | 2.9785 | 3220 | 2.9785 | 2.9785 | 0.728502 | 0.728502 | 0.41699 | 3370 | 3370 | 0.728502 | 3370 | 0.728502 | 3.707 | 3.707 | 3370 | 3370 | 1100 | 1100 | 729320 | -500 | 3370 | 0.51898 | 7020 | 2200 | 730420 | 1.2516 | 152.985 | 0.728502 | 3.707 | 0.154 | 0.10199 | 0.51898 | Apt 04 - | Apartamento 04
Apt 04 - Parede 24 | 04 | Parede-exterior-generico-in_loco-tijolo_maciço_sem_revestimento-140mm | yes | yes | Outside Face | yes | Parede 24 | Apt 04 - Parede 24 | Apartamento 04 | 04 | yes | Not Linked | Not Linked | Not Linked | Exterior | Load-Bearing Element | Parede -Parede 24 | 86.6002 (kgCO₂) | 1082.5 | 6705.01 | 1100 | 0.912094 | 7.16651 | 1.71826 | 1.0033 | 0.240552 | 0 | 3 | 2 | 0 | 0 | 0 | 5.44825 | 5890 | 5.44825 | 5.44825 | 1.71826 | 1.71826 | 0.762751 | 6705.01 | 6705.01 | 2.98551 | 6705.01 | 2.98551 | 7.37551 | 7.37551 | 6705.01 | 6705.01 | 1100 | 1100 | 729320 | -500 | 6515.01 | 1.03257 | 13690 | 2200 | 730420 | 2.13219 | 360.834 | 1.71826 | 7.16651 | 0.154 | 0.240556 | 1.0033 | Apt 04 - | Apartamento 04
Apt 04 - Parede 17 | 04 | Parede-interior-generico-in_loco-tijolo_maciço_sem_revestimento-140mm | no | yes | Center | yes | Parede 17 | Apt 04 - Parede 17 | Apartamento 04 | 04 | yes | Not Linked | Not Linked | Not Linked | Interior | Load-Bearing Element | Parede -Parede 17 | 176.222 (kgCO₂) | 2202.78 | 1304.99 | 2590 | 0.188999 | 3.49647 | 3.49647 | 0.489506 | 0.489506 | 0 | 0 | 1 | 0 | 0 | 0 | 0 | 0 | 0 | 0 | 3.49647 | 3.49647 | 0 | 1349.99 | 1349.99 | 3.49647 | 1259.99 | 3.49647 | 3.49647 | 3.49647 | 1349.99 | 1259.99 | 2590 | -30 | 728190 | -140 | 1349.99 | 0.489506 | 2916.41 | 2560 | 730780 | 0.740597 | 734.26 | 3.49647 | 3.49647 | 0.3626 | 0.489506 | 0.489506 | Apt 04 - | Apartamento 04
Apt 04 - Parede 16 | 04 | Parede-interior-generico-in_loco-tijolo_maciço_sem_revestimento-140mm | no | yes | Outside Face | yes | Parede 16 | Apt 04 - Parede 16 | Apartamento 04 | 04 | yes | Not Linked | Not Linked | Not Linked | Interior | Load-Bearing Element | Parede -Parede 16 | 100.801 (kgCO₂) | 1260.02 | 1555.01 | 2230 | 0.224002 | 3.34403 | 2.00003 | 0.468164 | 0.280004 | 0 | 1 | 0 | 0 | 0 | 0 | 1.344 | 1200 | 1.344 | 1.344 | 2.00003 | 2.00003 | 0.18816 | 1700.01 | 1600.01 | 3.34403 | 1510.01 | 3.34403 | 3.99173 | 3.99173 | 1600.01 | 1510.01 | 2230 | -30 | 728190 | -500 | 1600.02 | 0.558842 | 3416.46 | 2200 | 730420 | 0.448004 | 420.006 | 2.00003 | 3.34403 | 0.3122 | 0.280004 | 0.468164 | Apt 04 - | Apartamento 04
Parede 63 | 07 | Parede-interior-generico-in_loco-tijolo_maciço_sem_revestimento-140mm | no | yes | Outside Face | yes | Parede 63 | Parede 63 | Elevadores | 07 | no | Vazio | Home + 1 | Home + 1 (Vazio) | Interior | Load-Bearing Element | Parede -Parede 63 | 353.984 (kgCO₂) | 4424.79 | 3182.5 | 2300 | 0.4277 | 6.9843 | 6.9843 | 0.983288 | 0.983288 | 0 | 0 | 1 | 0 | 0 | 0 | 0 | 0 | 8.88178e-15 | 0 | 7.0265 | 6.9421 | -6.66134e-16 | 3310 | 3055 | 7.0265 | 3310 | 6.9421 | 8.4736 | 8.4736 | 3055 | 3310 | 2560 | -100 | 728120 | -240 | 3055 | 1.1863 | 6795.9 | 2200 | 730420 | 0.730423 | 1474.93 | 7.0265 | 7.0265 | 0.3584 | 0.983288 | 0.983288 |  | Elevadores; Hall dos Elevadores
Apt 03 - Parede 47 | 03 | Parede-exterior-generico-in_loco-tijolo_maciço_sem_revestimento-140mm | yes | yes | Center | yes | Parede 47 | Apt 03 - Parede 47 | Apartamento 03 | 03 | yes | Not Linked | Not Linked | Not Linked | Exterior | Load-Bearing Element | Parede -Parede 47 | 18.6883 (kgCO₂) | 233.604 | 360 | 1030 | 0.0504 | 0.3708 | 0.3708 | 0.051912 | 0.051912 | 0 | 0 | 0 | 0 | 0 | 0 | 0 | 0 | 0 | 0 | 0.3708 | 0.3708 | 0 | 500 | 360 | 0.3708 | 360 | 0.3708 | 0.515 | 0.515 | 360 | 360 | 1030 | 0 | 728220 | 0 | 360 | 0.0721 | 1000 | 1030 | 729250 | 0.245 | 77.868 | 0.3708 | 0.3708 | 0.1442 | 0.051912 | 0.051912 | Apt 03 - | Apartamento 03
Apt 03 - Parede 32 | 03 | Parede-interior-generico-in_loco-tijolo_maciço_sem_revestimento-140mm | no | yes | Outside Face | yes | Parede 32 | Apt 03 - Parede 32 | Apartamento 03 | 03 | yes | Not Linked | Not Linked | Not Linked | Interior | Load-Bearing Element | Parede -Parede 32 | 317.399 (kgCO₂) | 3967.48 | 2320 | 2560 | 0.3444 | 6.29759 | 6.29759 | 0.881663 | 0.881663 | 0 | 0 | 0 | 0 | 0 | 0 | 0 | 0 | 0 | 0 | 6.29759 | 6.29759 | 0 | 2460 | 2180 | 6.29759 | 2460 | 6.29759 | 6.29759 | 6.29759 | 2180 | 2460 | 2560 | 0 | 728220 | -140 | 2460 | 0.881663 | 5035.97 | 2560 | 730780 | 0.688799 | 1322.49 | 6.29759 | 6.29759 | 0.3584 | 0.881663 | 0.881663 | Apt 03 - | Apartamento 03
Apt 03 - Parede 46 | 03 | Parede-exterior-generico-in_loco-tijolo_maciço_sem_revestimento-140mm | yes | yes | Center | yes | Parede 46 | Apt 03 - Parede 46 | Apartamento 03 | 03 | yes | Not Linked | Not Linked | Not Linked | Exterior | Load-Bearing Element | Parede -Parede 46 | 18.579 (kgCO₂) | 232.238 | 357.894 | 1030 | 0.0501052 | 0.368631 | 0.368631 | 0.0516084 | 0.0516084 | 0 | 0 | 1 | 1030 | 0 | 0 | 0 | 0 | 0 | 0 | 0.368631 | 0.368631 | 0 | 357.894 | 357.894 | 0.368631 | 357.894 | 0.368631 | 0.368631 | 0.368631 | 357.894 | 357.894 | 1030 | 0 | 728220 | -140 | 357.894 | 0.0516084 | 995.789 | 1030 | 729250 | 0.38861 | 77.4126 | 0.368631 | 0.368631 | 0.1442 | 0.0516084 | 0.0516084 | Apt 03 - | Apartamento 03
Apt 03 - Parede 35 | 03 | Parede-interior-generico-in_loco-tijolo_maciço_sem_revestimento-140mm | no | yes | Outside Face | yes | Parede 35 | Apt 03 - Parede 35 | Apartamento 03 | 03 | yes | Not Linked | Not Linked | Not Linked | Interior | Load-Bearing Element | Parede -Parede 35 | 106.361 (kgCO₂) | 1329.52 | 1027.17 | 2560 | 0.143804 | 2.62955 | 2.11035 | 0.368136 | 0.295448 | 0 | 1 | 0 | 0 | 0 | 0 | 0.5192 | 880 | 0.5192 | 0.5192 | 2.11035 | 2.11035 | 0.072688 | 1122.17 | 1027.17 | 2.62955 | 1027.17 | 2.62955 | 3.08176 | 3.08176 | 1027.17 | 1027.17 | 2560 | 0 | 728220 | -140 | 1027.17 | 0.431446 | 2334.34 | 2560 | 730780 | 0.646007 | 443.173 | 2.11035 | 2.62954 | 0.3584 | 0.295448 | 0.368136 | Apt 03 - | Apartamento 03
Apt 03 - Parede 39 | 03 | Parede-interior-generico-in_loco-tijolo_maciço_sem_revestimento-140mm | no | yes | Outside Face | yes | Parede 39 | Apt 03 - Parede 39 | Apartamento 03 | 03 | yes | Not Linked | Not Linked | Not Linked | Interior | Load-Bearing Element | Parede -Parede 39 | 89.1242 (kgCO₂) | 1114.05 | 1382.16 | 2560 | 0.0822031 | 3.24393 | 1.76833 | 0.454153 | 0.247568 | 1 | 0 | 1 | 0 | 1.4756 | 680 | 0 | 0 | 1.4756 | 1.4756 | 1.76833 | 1.76833 | 0.206586 | 1407.16 | 677.157 | 3.24393 | 727.157 | 3.24393 | 3.80032 | 3.80032 | 1357.16 | 1407.16 | 2560 | 0 | 728220 | -140 | 1267.16 | 0.532045 | 3128.74 | 2560 | 730780 | 0.259605 | 371.351 | 1.76833 | 3.24393 | 0.3584 | 0.247567 | 0.454154 | Apt 03 - | Apartamento 03
Apt 03 - Parede 36 | 03 | Parede-interior-generico-in_loco-tijolo_maciço_sem_revestimento-140mm | no | yes | Outside Face | yes | Parede 36 | Apt 03 - Parede 36 | Apartamento 03 | 03 | yes | Not Linked | Not Linked | Not Linked | Interior | Load-Bearing Element | Parede -Parede 36 | 30.9658 (kgCO₂) | 387.072 | 310 | 2560 | 0.0336 | 0.6144 | 0.6144 | 0.086016 | 0.086016 | 0 | 0 | 0 | 0 | 0 | 0 | 0 | 0 | 0 | 0 | 0.6144 | 0.6144 | 0 | 380 | 240 | 0.6144 | 380 | 0.6144 | 0.9728 | 0.9728 | 240 | 380 | 2560 | 0 | 728220 | -140 | 240 | 0.136192 | 957.99 | 2560 | 730780 | 0.4256 | 129.024 | 0.6144 | 0.6144 | 0.3584 | 0.086016 | 0.086016 | Apt 03 - | Apartamento 03; Aréa Técnica
Apt 03 - Parede 41 | 03 | Parede-exterior-generico-in_loco-tijolo_maciço_sem_revestimento-140mm | yes | yes | Outside Face | yes | Parede 41 | Apt 03 - Parede 41 | Apartamento 03 | 03 | yes | Not Linked | Not Linked | Not Linked | Exterior | Load-Bearing Element | Parede -Parede 41 | 92.2318 (kgCO₂) | 1152.9 | 7555 | 1100 | 1.03109 | 8.1015 | 1.83 | 1.1342 | 0.256196 | 0 | 3 | 2 | 0 | 0 | 0 | 6.2715 | 6780 | 6.2715 | 6.2715 | 1.83 | 1.83 | 0.878004 | 7555 | 7555 | 1.83 | 7555 | 1.83 | 8.3105 | 8.3105 | 7555 | 7555 | 1100 | 1100 | 729320 | -500 | 7365 | 1.16347 | 15390 | 2200 | 730420 | 2.37018 | 384.299 | 1.83 | 8.1015 | 0.154 | 0.256199 | 1.1342 | Apt 03 - | Apartamento 03
Parede 69 | 05 | Parede-interior-generico-in_loco-tijolo_maciço_sem_revestimento-140mm | no | yes | Outside Face | yes | Parede 69 | Parede 69 | Corredor | 05 | no | Not Linked | Not Linked | Not Linked | Interior | Load-Bearing Element | Parede -Parede 69 | 239.039 (kgCO₂) | 2987.99 | 22680 | 210 | 3.1619 | 4.74285 | 4.74285 | 0.663998 | 0.663998 | 0 | 0 | 0 | 0 | 0 | 0 | 0 | 0 | 0 | 0 | 4.74285 | 4.74285 | 0 | 22585 | 22585 | 4.74285 | 22775 | 4.74285 | 4.78275 | 4.78275 | 22585 | 22775 | 210 | -100 | 728120 | 0 | 22585 | 0.669584 | 45736 | 110 | 728330 | 6.35319 | 995.998 | 4.74285 | 4.74285 | 0.0294 | 0.663998 | 0.663998 |  | Corredor
Apt 02 - Parede 36 | 12 | Parede-interior-generico-in_loco-tijolo_maciço_sem_revestimento-140mm | no | yes | Outside Face | yes | Parede 36 | Apt 02 - Parede 36 | Apartamento 02 | 02 | yes | Not Linked | Not Linked | Not Linked | Interior | Load-Bearing Element | Parede -Parede 36 | 30.9658 (kgCO₂) | 387.072 | 310 | 2560 | 0.0336 | 0.6144 | 0.6144 | 0.086016 | 0.086016 | 0 | 0 | 0 | 0 | 0 | 0 | 0 | 0 | 0 | 0 | 0.6144 | 0.6144 | 0 | 380 | 240 | 0.6144 | 380 | 0.6144 | 0.9728 | 0.9728 | 240 | 380 | 2560 | 0 | 728220 | -140 | 240 | 0.136192 | 957.99 | 2560 | 730780 | 0.4256 | 129.024 | 0.6144 | 0.6144 | 0.3584 | 0.086016 | 0.086016 | Apt 02 - | Apartamento 02; Aréa Técnica
Parede 71 | 17 | Parede-interior-generico-in_loco-tijolo_maciço_sem_revestimento-140mm | no | yes | Inside Face | yes | Parede 71 | Parede 71 | Elevadores | 07 | no | Vazio | Home + 1 | Home + 1 (Vazio) | Interior | Load-Bearing Element | Parede -Parede 71 | 269.539 (kgCO₂) | 3369.24 | 3490 | 2600 | 0.4886 | 9.074 | 5.348 | 1.27036 | 0.74872 | 2 | 0 | 1 | 0 | 3.726 | 1620 | 0 | 0 | 3.726 | 3.726 | 5.348 | 5.348 | 0.52164 | 3490 | 1870 | 9.074 | 1870 | 9.074 | 9.4212 | 9.4212 | 3490 | 3490 | 2600 | -20 | 728200 | -120 | 3490 | 1.31897 | 7260 | 2580 | 730800 | 1.3412 | 1123.08 | 5.348 | 9.074 | 0.364 | 0.74872 | 1.27036 |  | Hall dos Elevadores
Apt 02 - Parede 32 | 02 | Parede-interior-generico-in_loco-tijolo_maciço_sem_revestimento-140mm | no | yes | Outside Face | yes | Parede 32 | Apt 02 - Parede 32 | Apartamento 02 | 02 | yes | Not Linked | Not Linked | Not Linked | Interior | Load-Bearing Element | Parede -Parede 32 | 317.399 (kgCO₂) | 3967.48 | 2320 | 2560 | 0.3444 | 6.29759 | 6.29759 | 0.881663 | 0.881663 | 0 | 0 | 0 | 0 | 0 | 0 | 0 | 0 | 0 | 0 | 6.29759 | 6.29759 | 0 | 2460 | 2180 | 6.29759 | 2460 | 6.29759 | 6.29759 | 6.29759 | 2180 | 2460 | 2560 | 0 | 728220 | -140 | 2460 | 0.881663 | 5035.97 | 2560 | 730780 | 0.688799 | 1322.49 | 6.29759 | 6.29759 | 0.3584 | 0.881663 | 0.881663 | Apt 02 - | Apartamento 02
Apt 02 - Parede 46 | 02 | Parede-exterior-generico-in_loco-tijolo_maciço_sem_revestimento-140mm | yes | yes | Center | yes | Parede 46 | Apt 02 - Parede 46 | Apartamento 02 | 02 | yes | Not Linked | Not Linked | Not Linked | Exterior | Load-Bearing Element | Parede -Parede 46 | 18.579 (kgCO₂) | 232.238 | 357.894 | 1030 | 0.0501052 | 0.368631 | 0.368631 | 0.0516084 | 0.0516084 | 0 | 0 | 1 | 1030 | 0 | 0 | 0 | 0 | 0 | 0 | 0.368631 | 0.368631 | 0 | 357.894 | 357.894 | 0.368631 | 357.894 | 0.368631 | 0.368631 | 0.368631 | 357.894 | 357.894 | 1030 | 0 | 728220 | -140 | 357.894 | 0.0516084 | 995.789 | 1030 | 729250 | 0.38861 | 77.4126 | 0.368631 | 0.368631 | 0.1442 | 0.0516084 | 0.0516084 | Apt 02 - | Apartamento 02
Apt 02 - Parede 41 | 02 | Parede-exterior-generico-in_loco-tijolo_maciço_sem_revestimento-140mm | yes | yes | Outside Face | yes | Parede 41 | Apt 02 - Parede 41 | Apartamento 02 | 02 | yes | Not Linked | Not Linked | Not Linked | Exterior | Load-Bearing Element | Parede -Parede 41 | 92.2306 (kgCO₂) | 1152.88 | 7555 | 1100 | 1.0311 | 8.10147 | 1.82997 | 1.13421 | 0.256196 | 0 | 3 | 2 | 0 | 0 | 0 | 6.2715 | 6780 | 6.2715 | 6.2715 | 1.82997 | 1.82997 | 0.87801 | 7555 | 7555 | 1.82997 | 7555 | 1.82997 | 8.3105 | 8.3105 | 7555 | 7555 | 1100 | 1100 | 729320 | -500 | 7364.97 | 1.16347 | 15390 | 2200 | 730420 | 2.21619 | 384.294 | 1.82997 | 8.10147 | 0.154 | 0.256196 | 1.13421 | Apt 02 - | Apartamento 02
Apt 02 - Parede 35 | 02 | Parede-interior-generico-in_loco-tijolo_maciço_sem_revestimento-140mm | no | yes | Outside Face | yes | Parede 35 | Apt 02 - Parede 35 | Apartamento 02 | 02 | yes | Not Linked | Not Linked | Not Linked | Interior | Load-Bearing Element | Parede -Parede 35 | 106.363 (kgCO₂) | 1329.53 | 1027.17 | 2560 | 0.143804 | 2.62957 | 2.11037 | 0.36814 | 0.295452 | 0 | 1 | 0 | 0 | 0 | 0 | 0.5192 | 880 | 0.5192 | 0.5192 | 2.11037 | 2.11037 | 0.072688 | 1122.17 | 1027.17 | 2.62957 | 1027.17 | 2.62957 | 3.08176 | 3.08176 | 1027.17 | 1027.17 | 2560 | 0 | 728220 | -140 | 1027.18 | 0.431446 | 2334.34 | 2560 | 730780 | 0.646009 | 443.178 | 2.11037 | 2.62957 | 0.3584 | 0.295452 | 0.36814 | Apt 02 - | Apartamento 02
Apt 02 - Parede 39 | 02 | Parede-interior-generico-in_loco-tijolo_maciço_sem_revestimento-140mm | no | yes | Outside Face | yes | Parede 39 | Apt 02 - Parede 39 | Apartamento 02 | 02 | yes | Not Linked | Not Linked | Not Linked | Interior | Load-Bearing Element | Parede -Parede 39 | 89.1262 (kgCO₂) | 1114.08 | 1382.16 | 2560 | 0.0822055 | 3.24398 | 1.76838 | 0.454157 | 0.247573 | 1 | 0 | 1 | 0 | 1.4756 | 680 | 0 | 0 | 1.4756 | 1.4756 | 1.76838 | 1.76838 | 0.206584 | 1407.16 | 677.157 | 3.24398 | 727.157 | 3.24398 | 3.80032 | 3.80032 | 1357.16 | 1407.16 | 2560 | 0 | 728220 | -140 | 1267.18 | 0.532045 | 3128.74 | 2560 | 730780 | 0.259607 | 371.359 | 1.76838 | 3.24398 | 0.3584 | 0.247573 | 0.454157 | Apt 02 - | Apartamento 02
Apt 02 - Parede 47 | 02 | Parede-exterior-generico-in_loco-tijolo_maciço_sem_revestimento-140mm | yes | yes | Center | yes | Parede 47 | Apt 02 - Parede 47 | Apartamento 02 | 02 | yes | Not Linked | Not Linked | Not Linked | Exterior | Load-Bearing Element | Parede -Parede 47 | 18.6883 (kgCO₂) | 233.604 | 360 | 1030 | 0.0504 | 0.3708 | 0.3708 | 0.051912 | 0.051912 | 0 | 0 | 0 | 0 | 0 | 0 | 0 | 0 | 0 | 0 | 0.3708 | 0.3708 | 0 | 500 | 360 | 0.3708 | 360 | 0.3708 | 0.515 | 0.515 | 360 | 360 | 1030 | 0 | 728220 | 0 | 360 | 0.0721 | 1000 | 1030 | 729250 | 0.245 | 77.868 | 0.3708 | 0.3708 | 0.1442 | 0.051912 | 0.051912 | Apt 02 - | Apartamento 02
Parede 57 | Pavimento tipo | Parede-exterior-generico-in_loco-tijolo_maciço_sem_revestimento-140mm | yes | yes | Center | yes | Parede 57 | Parede 57 | Corredor | 05 | no | Vazio | Home + 1 | Home + 1 (Vazio) | Exterior | Load-Bearing Element | Parede -Parede 57 | 1908.26 (kgCO₂) | 23853.3 | 22490 | 2560 | 2.0706 | 57.5744 | 37.8624 | 8.06041 | 5.30073 | 0 | 10 | 0 | 2560 | 0 | 0 | 19.712 | 7700 | 19.712 | 19.712 | 37.8624 | 37.8624 | 2.75968 | 22490 | 14790 | 57.5744 | 22490 | 57.5744 | 57.5744 | 57.5744 | 22490 | 22490 | 2560 | 250 | 728470 | 110 | 14790 | 8.06041 | 45260 | 2810 | 731030 | 4.858 | 7951.1 | 37.8624 | 57.5744 | 0.3584 | 5.30073 | 8.06041
Parede 23 | Pavimento tipo | Parede-interior-generico-in_loco-tijolo_maciço_sem_revestimento-140mm | no | no | Center |  | Parede 23 | Parede 23 | Apartamento 04 | 04 | no | Vazio | Home + 1 | Home + 1 (Vazio) | Interior | Non-Load-Bearing Element | Parede -Parede 23 | 495.463 (kgCO₂) | 6193.28 | 3840.09 | 2560 | 0.537613 | 9.83061 | 9.83061 | 1.37628 | 1.37628 | 0 | 0 | 0 | 0 | 0 | 0 | 0 | 0 | 0 | 0 | 9.83061 | 9.83061 | 0 | 3935.09 | 3840.09 | 9.83061 | 3840.09 | 9.83061 | 10.317 | 10.317 | 3840.09 | 3840.09 | 2560 | 0 | 728220 | -140 | 3840.09 | 1.44439 | 7960.19 | 2560 | 730780 | 1.38321 | 2064.43 | 9.83061 | 9.83061 | 0.3584 | 1.37628 | 1.37628
Parede 45 | Pavimento tipo | Parede-exterior-generico-in_loco-tijolo_maciço_sem_revestimento-140mm | yes | yes | Center | yes | Parede 45 | Parede 45 | Apartamento 04 | 04 | no | Not Linked | Not Linked | Not Linked | Exterior | Load-Bearing Element | Parede -Parede 45 | 22.2082 (kgCO₂) | 277.602 | 427.804 | 1030 | 0.0598926 | 0.440638 | 0.440638 | 0.0616894 | 0.0616894 | 0 | 0 | 0 | 1030 | 0 | 0 | 0 | 0 | 0 | 0 | 0.440638 | 0.440638 | 0 | 427.804 | 427.804 | 0.440638 | 427.804 | 0.440638 | 0.440638 | 0.440638 | 427.804 | 427.804 | 1030 | 0 | 728220 | 0 | 427.804 | 0.0616894 | 1135.61 | 1030 | 729250 | 0.408185 | 92.534 | 0.440638 | 0.440638 | 0.1442 | 0.0616894 | 0.0616894
Apt 01 - Parede 22 | Pavimento tipo | Parede-interior-generico-in_loco-tijolo_maciço_sem_revestimento-140mm | no | yes | Outside Face | yes | Parede 22 | Apt 01 - Parede 22 | Corredor | 05 | yes | Not Linked | Not Linked | Not Linked | Interior | Load-Bearing Element | Parede -Parede 22 | 26.3275 (kgCO₂) | 329.094 | 949.996 | 2560 | 0.00979956 | 2.43197 | 0.522367 | 0.340478 | 0.0731321 | 1 | 0 | 1 | 0 | 1.9096 | 880 | 0 | 0 | 1.9096 | 1.9096 | 0.522368 | 0.522367 | 0.267346 | 949.996 | 69.9959 | 2.43197 | 69.9959 | 2.43197 | 2.9184 | 2.91839 | 949.996 | 949.996 | 2560 | 0 | 728220 | -140 | 949.996 | 0.408575 | 2179.99 | 2560 | 730780 | 0.193199 | 109.698 | 0.522367 | 2.43197 | 0.3584 | 0.0731321 | 0.340479 | Apt 01 -
Apt 01 - Parede 25 | Pavimento tipo | Parede-exterior-generico-in_loco-tijolo_maciço_sem_revestimento-140mm | yes | yes | Inside Face | yes | Parede 25 | Apt 01 - Parede 25 | Apartamento 01 | 01 | yes | Not Linked | Not Linked | Not Linked | Exterior | Load-Bearing Element | Parede -Parede 25 | 25.9556 (kgCO₂) | 324.445 | 430 | 1030 | 0.0699989 | 0.51499 | 0.51499 | 0.0720989 | 0.0720989 | 0 | 0 | 1 | 0 | 0 | 0 | 0 | 0 | 0 | 0 | 0.51499 | 0.51499 | 0 | 500 | 360 | 0.51499 | 500 | 0.51499 | 0.515 | 0.515 | 360 | 500 | 1030 | 0 | 728220 | -140 | 499.99 | 0.0721 | 1197.99 | 1030 | 729250 | 0.139998 | 108.148 | 0.51499 | 0.51499 | 0.1442 | 0.0720989 | 0.0720989 | Apt 01 -
Apt 04 - Parede 22 | Pavimento tipo | Parede-interior-generico-in_loco-tijolo_maciço_sem_revestimento-140mm | no | yes | Outside Face | yes | Parede 22 | Apt 04 - Parede 22 | Corredor | 05 | yes | Not Linked | Not Linked | Not Linked | Interior | Load-Bearing Element | Parede -Parede 22 | 26.3285 (kgCO₂) | 329.107 | 949.996 | 2560 | 0.00979942 | 2.43199 | 0.522389 | 0.340479 | 0.0731348 | 1 | 0 | 1 | 2170 | 1.9096 | 880 | 0 | 0 | 1.9096 | 1.9096 | 0.522389 | 0.522389 | 0.267345 | 949.996 | 69.9964 | 2.43199 | 69.9959 | 2.43199 | 2.91839 | 2.91839 | 949.996 | 949.996 | 2560 | 0 | 728220 | -140 | 949.996 | 0.408574 | 2179.99 | 2560 | 730780 | 0.5012 | 109.702 | 0.522389 | 2.43199 | 0.3584 | 0.0731348 | 0.340479 | Apt 04 -
Apt 01 - Parede 58 | Pavimento tipo | Parede-exterior-generico-in_loco-tijolo_maciço_sem_revestimento-140mm | yes | yes | Outside Face | yes | Parede 58 | Apt 01 - Parede 58 |  |  | yes | Not Linked | Not Linked | Not Linked | Exterior | Load-Bearing Element | Parede -Parede 58 | 352.742 (kgCO₂) | 4409.28 | 6750.01 | 1030 | 0.951301 | 6.99886 | 6.99886 | 0.97984 | 0.97984 | 0 | 0 | 0 | 0 | 0 | 0 | 0 | 0 | 0 | 0 | 6.99886 | 6.99886 | 0 | 6795.01 | 6705.01 | 6.99886 | 6795.01 | 6.99886 | 6.99886 | 6.99886 | 6705.01 | 6795.01 | 1030 | 0 | 728220 | 0 | 6795.01 | 0.97984 | 13806.5 | 1030 | 729250 | 2.0468 | 1469.76 | 6.99886 | 6.99886 | 0.1442 | 0.97984 | 0.97984 | Apt 01 -
Apt 04 - Parede 25 | Pavimento tipo | Parede-exterior-generico-in_loco-tijolo_maciço_sem_revestimento-140mm | yes | yes | Inside Face | yes | Parede 25 | Apt 04 - Parede 25 | Apartamento 04 | 04 | yes | Not Linked | Not Linked | Not Linked | Exterior | Load-Bearing Element | Parede -Parede 25 | 25.956 (kgCO₂) | 324.45 | 430 | 1030 | 0.07 | 0.515 | 0.515 | 0.0721 | 0.0721 | 0 | 0 | 1 | 0 | 0 | 0 | 0 | 0 | 0 | 0 | 0.515 | 0.515 | 0 | 500 | 360 | 0.515 | 500 | 0.515 | 0.515 | 0.515 | 360 | 500 | 1030 | 0 | 728220 | -140 | 500 | 0.0721 | 1197.99 | 1030 | 729250 | 0.2842 | 108.15 | 0.515 | 0.515 | 0.1442 | 0.0721 | 0.0721 | Apt 04 -

# IfcWall: Tijolo - Estrutural 190 (23)
Classification: Parede (Classificação ARCHICAD); 3E 14 02 00 Parede (NBR 15965-5 3E); Material: Tijolo - Estrutural
Pset_WallCommon - AcousticRating: 0,00
ArchiCADProperties - Wall Complexity: Straight; Geometry Method: Uniform; Inside Face Surface: Tijolo - Comum ao Comprido; Outside Face Surface: Tijolo - Comum ao Comprido; Wall Inside Slant Angle: 90 deg; Wall Outside Slant Angle: 90 deg; Layer: A--PRDE-VEDS-E-; Building Material / Composite / Profile / Fill: Tijolo - Estrutural; Building Material: Tijolo - Estrutural; Home Story Name: Pavimento tipo; Home Story Number: 0; Element Type: Wall; Structure Type: Basic; Building Materials (All): Tijolo - Estrutural; Surfaces (All): Tijolo - Comum ao Comprido; Slant Angle: 90 deg; Number of Openings: 0; Edge Surface: Tijolo - Comum ao Comprido; Show On Renovation Filter: All Relevant Filters; Renovation Status: Existing
CLASSIFICAÇÕES GERAIS - Transmissão Sonora: 0
SUPERFÍCIES (Mapas) - Superfície da Face (Geral): Tijolo - Comum ao Comprido
AC_Pset_RenovationAndPhasing - Renovation Status: Existing
Material Properties - Tijolo - Estrutural, ThermalConductivity: 0.6; Tijolo - Estrutural, SpecificHeatCapacity: 840 J/kg/K; Tijolo - Estrutural, MassDensity: 1500 kg/m3; Tijolo - Estrutural, Embodied Energy: 3 (MJ/kg); Tijolo - Estrutural, Embodied Carbon: 0.24 (kgCO₂/kg); Tijolo - Estrutural, Name: Tijolo - Estrutural; Tijolo - Estrutural, ID: VED; Tijolo - Estrutural, Participates in Collision Detection: yes
BaseQuantities - Width: 190 mm
ArchiCADQuantities - Number of Doors: 0; Number of Holes (Number of Empty Openings): 0; Volume of the Columns: 0 m3; Maximum Height of the Wall Skin on the Inside Face: 0 mm; Minimum Height of the Wall Skin on the Inside Face: 0 mm; Maximum Height of the Wall Skin on the Outside Face: 0 mm; Minimum Height of the Wall Skin on the Outside Face: 0 mm; Air Skin Thickness: 0 mm; Area of the Doors: 0 m2; Combined Width of Doors: 0 mm; Wall Component Thickness on the Inside Face: 0 mm; Wall Component Thickness on the Outside Face: 0 mm; End Thickness of the Wall: 190 mm; Surface Area of Empty Openings in the Wall: 0 m2; Width: 190 mm; Thickness: 190 mm; Insulation Skin Thickness: 0 mm
ALVENARIAS (Expressão) - Espessura da Argamassa: 10 mm
Component Quantities - Tijolo - Estrutural, Component Thickness: 190 mm; Tijolo - Estrutural, Rectangular Component Width: 190 mm
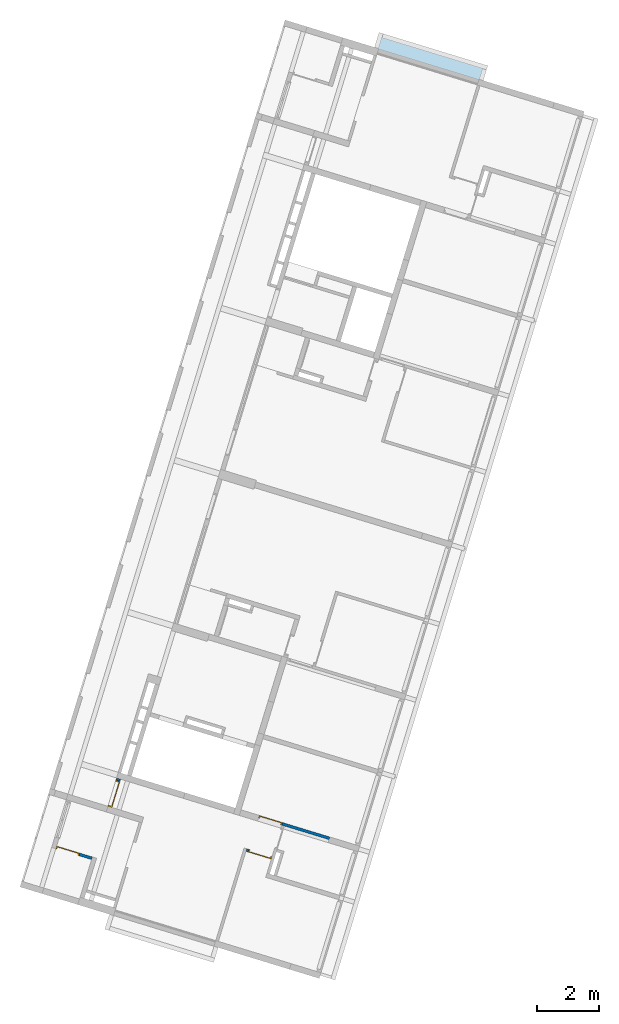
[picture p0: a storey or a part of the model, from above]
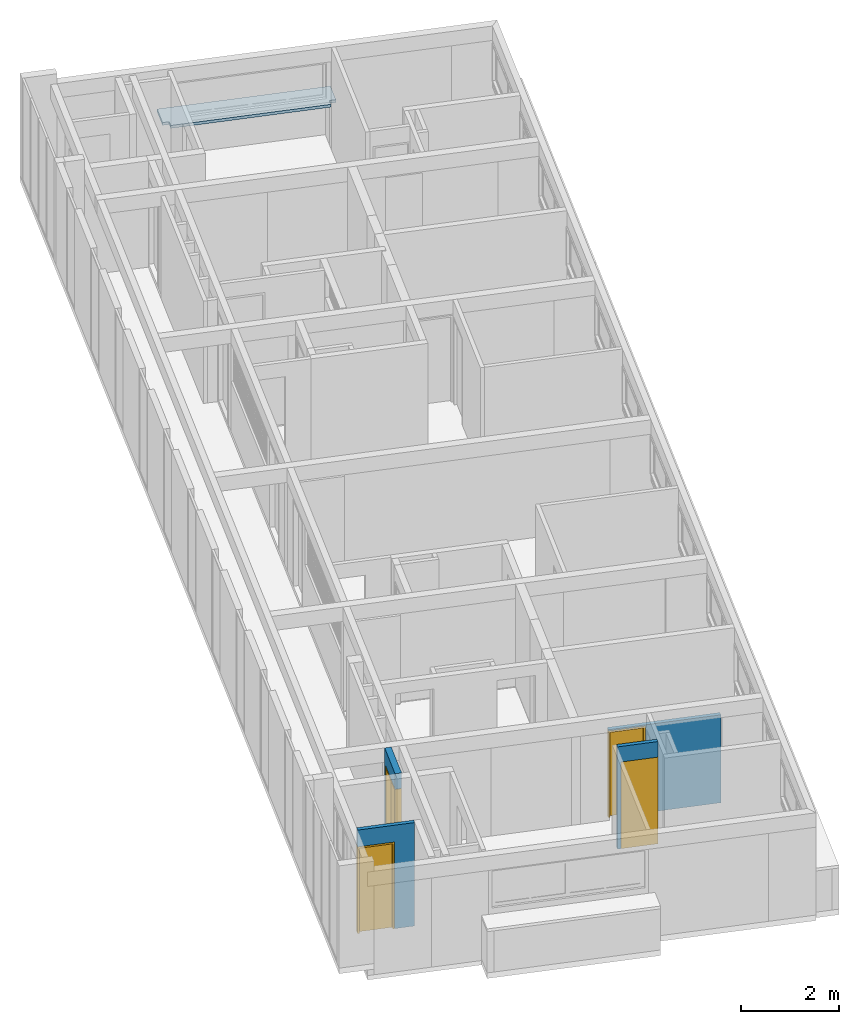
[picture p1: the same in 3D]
Properties of the parts of a building model (IFC2X3), part 6 of 11

# IfcWall: Tijolo - Estrutural 190 (23)
Name | In | Description | IsExternal | LoadBearing | Reference Line Location | Structural Analytical Model Generation | Element ID = Parent ID | Hotlink and Element ID | Related Zone Name | Related Zone Number | Locked | Absolute Top Link Story | Relative Top Link Story | Top Link Story | Hotlink Master ID | Position | Structural Function | ID Dinâmico por Classificação | Tijolo - Estrutural, Embodied Carbon | Tijolo - Estrutural, Embodied Energy (MJ) | Length (mm) = Average length of the Wall (mm) = Length of the Wall at the Center (mm) | BaseQuantities, Height (mm) = Maximum Height of the Wall (mm) = ArchiCADQuantities, Height (mm) = Tijolo - Estrutural, Rectangular Component Height (mm) | GrossFootprintArea (m2) = NetFootprintArea (m2) = Area (m2) = Top Surface Area (Net) (m2) | GrossSideArea (m2) | NetSideArea (m2) | GrossVolume (m3) = Volume (Conditional) (m3) = Tijolo - Estrutural, Component Volume (Gross) (m3) = Tijolo - Estrutural, Component Volume (Conditional) (m3) | NetVolume (m3) = Volume (Net) (m3) = Tijolo - Estrutural, Component Volume (Net) (m3) | Number of Windows | Number of Columns | Minimum Height of the Wall (mm) | Area of the Windows (m2) | Combined Width of Windows (mm) | Analytic Surface Area of Openings on the Inside Face (m2) | Analytic Surface Area of Openings on the Outside Face (m2) | Surface Area of the Wall Inside Face (Net) (m2) = Surface Area of the Wall Inside Face (Conditional) (m2) | Surface Area of the Wall Outside Face (Net) (m2) = Surface Area of the Wall Outside Face (Conditional) (m2) = Surface Area (m2) = Bottom Surface Area (Net) (m2) | Analytic Volume of the Openings (m3) | Length of Reference Line (mm) | Length of the Wall Inside Face (Conditional) (mm) | Length of the Wall Outside Face (Conditional) (mm) | Surface Area of the Wall Inside Face (Gross) (m2) | Surface Area of the Wall Outside Face (Gross) (m2) | Length of the Wall on the Inside Face (mm) | Length of the Wall on the Outside Face (mm) | Elevation to Project Zero (mm) = Elevation to 1º Nível de Referência (mm) = Elevation to 2º Nível de Referência (mm) = Elevation to Linked/Home Story (mm) = Home Offset (mm) = Bottom Elevation To First Reference Level (mm) = Bottom Elevation To Home Story (mm) = Bottom Elevation To Project Zero (mm) = Bottom Elevation To Second Reference Level (mm) | Elevation to Sea Level (mm) = Bottom Elevation To Sea Level (mm) | Top Offset (mm) | 3D Length (mm) | Volume (Gross) (m3) | Floor Plan Perimeter (mm) | Top Elevation To First Reference Level (mm) = Top Elevation To Home Story (mm) = Top Elevation To Project Zero (mm) = Top Elevation To Second Reference Level (mm) | Top Elevation To Sea Level (mm) | Edge Surface Area (Net) (m2) = Área da Superfície da Face (Geral) (m2) | Tijolo - Estrutural, Mass (kg) | Tijolo - Estrutural, Projected Component Area (Net) (m2) = Tijolo - Estrutural, Projected Component Area (Conditional) (m2) | Tijolo - Estrutural, Projected Component Area (Gross) (m2) | Tijolo - Estrutural, Component Cross Section Area (m2) | Colliding Zones
Apt 02 - Parede 28 | Pavimento tipo | Parede-interior-generico-in_loco-tijolo_maciço_sem_revestimento-190mm | no | yes | Center | yes | Parede 28 | Apt 02 - Parede 28 | Apartamento 02 | 02 | yes | Not Linked | Not Linked | Not Linked | Apt 02 - | Interior | Load-Bearing Element | Parede -Parede 28 | 365.666 (kgCO₂) | 4570.83 | 2430 | 2200 | 0.4617 | 5.346 | 5.346 | 1.01574 | 1.01574 | 0 | 2 | 2200 | 0 | 0 | 0 | 0 | 5.346 | 5.346 | 0 | 2430 | 2430 | 2430 | 5.346 | 5.346 | 2430 | 2430 | 0 | 728220 | -500 | 2430 | 1.01574 | 5240 | 2200 | 730420 | 1.7594 | 1523.61 | 5.346 | 5.346 | 0.418
Apt 02 - Parede 38 | Pavimento tipo | Parede-interior-generico-in_loco-tijolo_maciço_sem_revestimento-190mm | no | yes | Center | yes | Parede 38 | Apt 02 - Parede 38 | Apartamento 02 | 02 | yes | Not Linked | Not Linked | Not Linked | Apt 02 - | Interior | Load-Bearing Element | Parede -Parede 38 | 200.494 (kgCO₂) | 2506.18 | 1145 | 2560 | 0.21755 | 2.9312 | 2.9312 | 0.556928 | 0.556928 | 0 | 1 | 2560 | 0 | 0 | 0 | 0 | 2.9312 | 2.9312 | 0 | 1145 | 1145 | 1145 | 2.9312 | 2.9312 | 1145 | 1145 | 0 | 728220 | -140 | 1145 | 0.556928 | 2670 | 2560 | 730780 | 1.4079 | 835.392 | 2.9312 | 2.9312 | 0.4864
Parede 64 | Pavimento tipo | Parede-interior-generico-in_loco-tijolo_maciço_sem_revestimento-190mm | no | yes | Center | yes | Parede 64 | Parede 64 | Apartamento 01 | 01 | no | Not Linked | Not Linked | Not Linked |  | Interior | Load-Bearing Element | Parede -Parede 64 | 67.4148 (kgCO₂) | 842.684 | 314.998 | 2560 | 0.0731497 | 0.985596 | 0.985596 | 0.187263 | 0.187263 | 0 | 1 | 0 | 0 | 0 | 0 | 0 | 0.985597 | 0.985594 | 0 | 314.998 | 384.999 | 244.998 | 0.985597 | 0.985594 | 384.999 | 244.998 | 0 | 728220 | -140 | 384.999 | 0.187263 | 1056.01 | 2560 | 730780 | 0.632699 | 280.895 | 0.985597 | 0.985597 | 0.4864
Apt 03 - Parede 28 | Pavimento tipo | Parede-interior-generico-in_loco-tijolo_maciço_sem_revestimento-190mm | no | yes | Center | yes | Parede 28 | Apt 03 - Parede 28 | Escada | 06 | yes | Not Linked | Not Linked | Not Linked | Apt 03 - | Interior | Load-Bearing Element | Parede -Parede 28 | 365.666 (kgCO₂) | 4570.83 | 2430 | 2200 | 0.4617 | 5.346 | 5.346 | 1.01574 | 1.01574 | 0 | 2 | 2200 | 0 | 0 | 0 | 0 | 5.346 | 5.346 | 0 | 2430 | 2430 | 2430 | 5.346 | 5.346 | 2430 | 2430 | 0 | 728220 | -500 | 2430 | 1.01574 | 5240 | 2200 | 730420 | 1.7594 | 1523.61 | 5.346 | 5.346 | 0.418
Apt 03 - Parede 38 | Pavimento tipo | Parede-interior-generico-in_loco-tijolo_maciço_sem_revestimento-190mm | no | yes | Center | yes | Parede 38 | Apt 03 - Parede 38 | Escada | 06 | yes | Not Linked | Not Linked | Not Linked | Apt 03 - | Interior | Load-Bearing Element | Parede -Parede 38 | 200.493 (kgCO₂) | 2506.17 | 1145 | 2560 | 0.21755 | 2.9312 | 2.9312 | 0.556926 | 0.556926 | 0 | 1 | 2560 | 0 | 0 | 0 | 0 | 2.9312 | 2.9312 | 0 | 1145 | 1145 | 1145 | 2.9312 | 2.9312 | 1145 | 1145 | 0 | 728220 | -140 | 1145 | 0.556928 | 2670 | 2560 | 730780 | 1.4079 | 835.389 | 2.9312 | 2.9312 | 0.4864
Parede 61 | Pavimento tipo | Parede-interior-generico-in_loco-tijolo_maciço_sem_revestimento-190mm | no | yes | Center | yes | Parede 61 | Parede 61 | Escada | 06 | no | Not Linked | Not Linked | Not Linked |  | Interior | Load-Bearing Element | Parede -Parede 61 | 116.444 (kgCO₂) | 1455.55 | 665 | 2560 | 0.12635 | 1.7024 | 1.7024 | 0.323456 | 0.323456 | 0 | 1 | 2560 | 0 | 0 | 0 | 0 | 1.7024 | 1.7024 | 0 | 665 | 665 | 665 | 1.7024 | 1.7024 | 665 | 665 | 0 | 728220 | -140 | 665 | 0.323456 | 1710 | 2560 | 730780 | 1.2255 | 485.184 | 1.7024 | 1.7024 | 0.4864
Apt 01 - Parede 07 | 01 | Parede-interior-generico-in_loco-tijolo_maciço_sem_revestimento-190mm | no | yes | Inside Face | yes | Parede 07 | Apt 01 - Parede 07 | Apartamento 01 | 01 | yes | Not Linked | Not Linked | Not Linked | Apt 01 - | Interior | Load-Bearing Element | Parede -Parede 07 | 71.7941 (kgCO₂) | 897.427 | 505.007 | 2560 | 0.0779016 | 1.04962 | 1.04962 | 0.199428 | 0.199428 | 0 | 0 | 0 | 0 | 0 | 0 | 0 | 1.04961 | 1.04963 | 0 | 505.005 | 600.005 | 410.009 | 1.53601 | 1.53603 | 600.005 | 410.009 | 250 | 728470 | 110 | 410.012 | 0.291844 | 1468.71 | 2810 | 731030 | 0.642203 | 299.142 | 1.04961 | 1.04961 | 0.4864 | Apartamento 01
Apt 01 - Parede 01 | 01 | Parede-exterior-generico-in_loco-tijolo_maciço_sem_revestimento-190mm | yes | yes | Center | yes | Parede 01 | Apt 01 - Parede 01 | Apartamento 01 | 01 | yes | Not Linked | Not Linked | Not Linked | Apt 01 - | Exterior | Load-Bearing Element | Parede -Parede 01 | 126.13 (kgCO₂) | 1576.62 | 645 | 2560 | 0.1406 | 1.844 | 1.844 | 0.35036 | 0.35036 | 0 | 0 | 0 | 0 | 0 | 0 | 0 | 1.844 | 1.844 | 0 | 645 | 739.999 | 550.002 | 1.8944 | 1.89441 | 739.999 | 550.002 | 250 | 728470 | 110 | 740.002 | 0.359936 | 1748.7 | 2810 | 731030 | 0.6992 | 525.54 | 1.844 | 1.844 | 0.4864 | Apartamento 01
Apt 01 - Parede 13 | 01 | Parede-interior-generico-in_loco-tijolo_maciço_sem_revestimento-190mm | no | yes | Inside Face | yes | Parede 13 | Apt 01 - Parede 13 | Apartamento 01 | 01 | yes | Not Linked | Not Linked | Not Linked | Apt 01 - | Interior | Load-Bearing Element | Parede -Parede 13 | 346.11 (kgCO₂) | 4326.37 | 2490 | 2200 | 0.437003 | 5.06 | 5.06 | 0.961416 | 0.961416 | 0 | 2 | 0 | 0 | 0 | 0 | 0 | 5.06 | 5.06 | 0 | 2490 | 2490 | 2490 | 5.478 | 5.478 | 2490 | 2490 | 0 | 728220 | -500 | 2300 | 1.04082 | 5360 | 2200 | 730420 | 1.71 | 1442.12 | 5.06 | 5.06 | 0.418 | Apartamento 01
Apt 01 - Parede 15 | 01 | Parede-exterior-generico-in_loco-tijolo_maciço_sem_revestimento-190mm | yes | yes | Center | yes | Parede 15 | Apt 01 - Parede 15 | Apartamento 01 | 01 | yes | Not Linked | Not Linked | Not Linked | Apt 01 - | Exterior | Load-Bearing Element | Parede -Parede 15 | 33.2673 (kgCO₂) | 415.841 | 3109.98 | 2560 | 0.0360973 | 7.96156 | 0.486378 | 1.5127 | 0.0924092 | 4 | 0 | 0 | 7.4752 | 2920 | 7.47517 | 7.47519 | 0.4864 | 0.486355 | 1.42029 | 3204.99 | 0 | 379.983 | 8.44797 | 8.44795 | 2919.99 | 3299.98 | 250 | 728470 | 110 | 190 | 1.60511 | 6757.36 | 2810 | 731030 | 0.0721946 | 138.614 | 0.4864 | 7.96157 | 0.4864 | Apartamento 01
Apt 01 - Parede 04 | 01 | Parede-exterior-generico-in_loco-tijolo_maciço_sem_revestimento-190mm | yes | yes | Outside Face | yes | Parede 04 | Apt 01 - Parede 04 | Apartamento 01 | 01 | yes | Not Linked | Not Linked | Not Linked | Apt 01 - | Exterior | Load-Bearing Element | Parede -Parede 04 | 380.714 (kgCO₂) | 4758.93 | 2530 | 2200 | 0.480699 | 5.566 | 5.566 | 1.05754 | 1.05754 | 0 | 1 | 0 | 0 | 0 | 0 | 0 | 5.566 | 5.566 | 0 | 2530 | 2530 | 2530 | 5.566 | 5.566 | 2530 | 2530 | 0 | 728220 | -500 | 2530 | 1.05754 | 5440 | 2200 | 730420 | 1.3794 | 1586.31 | 5.566 | 5.566 | 0.418 | Apartamento 01
Apt 01 - Parede 02 | 01 | Parede-exterior-generico-in_loco-tijolo_maciço_sem_revestimento-190mm | yes | yes | Center | yes | Parede 02 | Apt 01 - Parede 02 | Apartamento 01 | 01 | yes | Not Linked | Not Linked | Not Linked | Apt 01 - | Exterior | Load-Bearing Element | Parede -Parede 02 | 183.038 (kgCO₂) | 2287.98 | 1200 | 2230 | 0.228 | 2.676 | 2.676 | 0.508439 | 0.508439 | 0 | 1 | 2230 | 0 | 0 | 0 | 0 | 2.676 | 2.676 | 0 | 1200 | 1200 | 1200 | 2.676 | 2.676 | 1200 | 1200 | -30 | 728190 | -500 | 1200 | 0.508439 | 2780 | 2200 | 730420 | 1.3034 | 762.659 | 2.676 | 2.676 | 0.4237 | Apartamento 01
Apt 04 - Parede 02 | 04 | Parede-exterior-generico-in_loco-tijolo_maciço_sem_revestimento-190mm | yes | yes | Center | yes | Parede 02 | Apt 04 - Parede 02 | Apartamento 04 | 04 | yes | Not Linked | Not Linked | Not Linked | Apt 04 - | Exterior | Load-Bearing Element | Parede -Parede 02 | 184.379 (kgCO₂) | 2304.74 | 1270 | 2230 | 0.254599 | 2.6956 | 2.6956 | 0.512163 | 0.512163 | 0 | 1 | 0 | 0 | 0 | 0 | 0 | 2.6956 | 2.6956 | 0 | 1200 | 1200 | 1340 | 2.6956 | 2.6956 | 1200 | 1340 | -30 | 728190 | -500 | 1340 | 0.512163 | 2966 | 2200 | 730420 | 0.906299 | 768.245 | 2.6956 | 2.6956 | 0.4237 | Apartamento 04
Apt 04 - Parede 07 | 04 | Parede-interior-generico-in_loco-tijolo_maciço_sem_revestimento-190mm | no | yes | Inside Face | yes | Parede 07 | Apt 04 - Parede 07 | Corredor | 05 | yes | Not Linked | Not Linked | Not Linked | Apt 04 - | Interior | Load-Bearing Element | Parede -Parede 07 | 71.7941 (kgCO₂) | 897.427 | 505.007 | 2560 | 0.0779016 | 1.04962 | 1.04962 | 0.199428 | 0.199428 | 0 | 0 | 0 | 0 | 0 | 0 | 2.22045e-16 | 1.04961 | 1.04963 | 1.22125e-15 | 505.005 | 600.005 | 410.009 | 1.53601 | 1.53603 | 600.005 | 410.009 | 250 | 728470 | 110 | 410.012 | 0.291844 | 1468.71 | 2810 | 731030 | 0.642203 | 299.142 | 1.04963 | 1.04963 | 0.4864 | Apartamento 04
Apt 04 - Parede 04 | 04 | Parede-exterior-generico-in_loco-tijolo_maciço_sem_revestimento-190mm | yes | yes | Outside Face | yes | Parede 04 | Apt 04 - Parede 04 | Apartamento 04 | 04 | yes | Not Linked | Not Linked | Not Linked | Apt 04 - | Exterior | Load-Bearing Element | Parede -Parede 04 | 380.714 (kgCO₂) | 4758.93 | 2530 | 2200 | 0.480699 | 5.566 | 5.566 | 1.05754 | 1.05754 | 0 | 1 | 0 | 0 | 0 | 0 | 0 | 5.566 | 5.566 | 0 | 2530 | 2530 | 2530 | 5.566 | 5.566 | 2530 | 2530 | 0 | 728220 | -500 | 2530 | 1.05754 | 5440 | 2200 | 730420 | 1.3794 | 1586.31 | 5.566 | 5.566 | 0.418 | Apartamento 04
Apt 04 - Parede 01 | 04 | Parede-exterior-generico-in_loco-tijolo_maciço_sem_revestimento-190mm | yes | yes | Center | yes | Parede 01 | Apt 04 - Parede 01 | Apartamento 04 | 04 | yes | Not Linked | Not Linked | Not Linked | Apt 04 - | Exterior | Load-Bearing Element | Parede -Parede 01 | 126.129 (kgCO₂) | 1576.62 | 645 | 2560 | 0.140601 | 1.844 | 1.844 | 0.350359 | 0.350359 | 0 | 0 | 0 | 0 | 0 | 0 | 0 | 1.844 | 1.844 | 5.55112e-17 | 645 | 739.999 | 550.002 | 1.8944 | 1.89441 | 739.999 | 550.002 | 250 | 728470 | 110 | 740.002 | 0.359936 | 1748.7 | 2810 | 731030 | 0.6992 | 525.539 | 1.844 | 1.844 | 0.4864 | Apartamento 04
Apt 04 - Parede 13 | 04 | Parede-interior-generico-in_loco-tijolo_maciço_sem_revestimento-190mm | no | yes | Inside Face | yes | Parede 13 | Apt 04 - Parede 13 | Apartamento 04 | 04 | yes | Not Linked | Not Linked | Not Linked | Apt 04 - | Interior | Load-Bearing Element | Parede -Parede 13 | 346.104 (kgCO₂) | 4326.3 | 2490 | 2200 | 0.437 | 5.06 | 5.06 | 0.9614 | 0.9614 | 0 | 2 | 0 | 0 | 0 | 0 | 0 | 5.06 | 5.06 | 0 | 2490 | 2490 | 2490 | 5.478 | 5.478 | 2490 | 2490 | 0 | 728220 | -500 | 2300 | 1.04082 | 5360 | 2200 | 730420 | 1.71 | 1442.1 | 5.06 | 5.06 | 0.418 | Apartamento 04
Apt 04 - Parede 15 | 04 | Parede-exterior-generico-in_loco-tijolo_maciço_sem_revestimento-190mm | yes | yes | Center | yes | Parede 15 | Apt 04 - Parede 15 | Apartamento 04 | 04 | yes | Not Linked | Not Linked | Not Linked | Apt 04 - | Exterior | Load-Bearing Element | Parede -Parede 15 | 33.2673 (kgCO₂) | 415.841 | 3109.98 | 2560 | 0.0360973 | 7.96156 | 0.486378 | 1.5127 | 0.0924092 | 4 | 0 | 0 | 7.4752 | 2920 | 7.47517 | 7.47519 | 0.4864 | 0.486355 | 1.42029 | 3204.99 | 3.10862e-12 | 379.983 | 8.44797 | 8.44795 | 2919.99 | 3299.98 | 250 | 728470 | 110 | 190 | 1.60511 | 6757.36 | 2810 | 731030 | 0.0721946 | 138.614 | 0.486383 | 7.96155 | 0.4864 | Apartamento 04
Parede 65 | Pavimento tipo | Parede-interior-generico-in_loco-tijolo_maciço_sem_revestimento-190mm | no | no | Center |  | Parede 65 | Parede 65 | Apartamento 03 | 03 | no | Vazio | Home + 1 | Home + 1 (Vazio) |  | Interior | Non-Load-Bearing Element | Parede -Parede 65 | 842.688 (kgCO₂) | 10533.6 | 5600.19 | 2200 | 1.064 | 12.32 | 12.32 | 2.3408 | 2.3408 | 0 | 2 | 0 | 0 | 0 | 0 | 0 | 12.32 | 12.32 | 0 | 5600.19 | 5600.19 | 5600.19 | 12.3204 | 12.3204 | 5600.19 | 5600.19 | 0 | 728220 | -500 | 5600 | 2.34088 | 11580.4 | 2200 | 730420 | 2.546 | 3511.2 | 12.32 | 12.32 | 0.418
Apt 01 - Parede 08 | Pavimento tipo | Parede-interior-generico-in_loco-tijolo_maciço_sem_revestimento-190mm | no | yes | Outside Face | yes | Parede 08 | Apt 01 - Parede 08 | Corredor | 05 | yes | Not Linked | Not Linked | Not Linked | Apt 01 - | Interior | Load-Bearing Element | Parede -Parede 08 | 239.017 (kgCO₂) | 2987.71 | 1340 | 2660 | 0.2546 | 3.4944 | 3.4944 | 0.663935 | 0.663935 | 0 | 0 | 210 | 0 | 0 | -4.44089e-16 | 0 | 3.4944 | 3.4944 | -1.22125e-15 | 1340 | 1339.99 | 1340 | 3.56439 | 3.56439 | 1339.99 | 1340 | -100 | 728120 | -140 | 1340 | 0.677235 | 3059.99 | 2560 | 730780 | 1.3984 | 995.903 | 3.4944 | 3.4944 | 0.5054
Apt 04 - Parede 08 | Pavimento tipo | Parede-interior-generico-in_loco-tijolo_maciço_sem_revestimento-190mm | no | yes | Outside Face | yes | Parede 08 | Apt 04 - Parede 08 | Corredor | 05 | yes | Not Linked | Not Linked | Not Linked | Apt 04 - | Interior | Load-Bearing Element | Parede -Parede 08 | 239.017 (kgCO₂) | 2987.71 | 1340 | 2660 | 0.2546 | 3.4944 | 3.4944 | 0.663935 | 0.663935 | 0 | 0 | 0 | 0 | 0 | 8.88178e-16 | 4.44089e-16 | 3.4944 | 3.4944 | 1.11022e-16 | 1340 | 1339.99 | 1340 | 3.56439 | 3.56439 | 1339.99 | 1340 | -100 | 728120 | -140 | 1340 | 0.677235 | 3059.99 | 2560 | 730780 | 0.988 | 995.903 | 3.4944 | 3.4944 | 0.5054
Apt 01 - Parede 09 | Pavimento tipo | Parede-interior-generico-in_loco-tijolo_maciço_sem_revestimento-190mm | no | yes | Inside Face | yes | Parede 09 | Apt 01 - Parede 09 | Apartamento 01 | 01 | yes | Not Linked | Not Linked | Not Linked | Apt 01 - | Interior | Load-Bearing Element | Parede -Parede 09 | 206.677 (kgCO₂) | 2583.47 | 1155 | 2560 | 0.228 | 3.0216 | 3.0216 | 0.574104 | 0.574104 | 0 | 0 | 0 | 0 | 0 | 0 | 0 | 3.0216 | 3.0216 | -2.10942e-15 | 1155 | 1200 | 1110 | 3.072 | 3.072 | 1200 | 1110 | 0 | 728220 | -140 | 1200 | 0.58368 | 2710.24 | 2560 | 730780 | 0.9158 | 861.156 | 3.0216 | 3.0216 | 0.4864
Apt 04 - Parede 09 | Pavimento tipo | Parede-interior-generico-in_loco-tijolo_maciço_sem_revestimento-190mm | no | yes | Inside Face | yes | Parede 09 | Apt 04 - Parede 09 | Apartamento 04 | 04 | yes | Not Linked | Not Linked | Not Linked | Apt 04 - | Interior | Load-Bearing Element | Parede -Parede 09 | 206.677 (kgCO₂) | 2583.47 | 1155 | 2560 | 0.228 | 3.0216 | 3.0216 | 0.574104 | 0.574104 | 0 | 0 | 0 | 0 | 0 | 0 | 0 | 3.0216 | 3.0216 | -6.66134e-16 | 1155 | 1200 | 1110 | 3.072 | 3.072 | 1200 | 1110 | 0 | 728220 | -140 | 1200 | 0.58368 | 2710.24 | 2560 | 730780 | 0.9158 | 861.156 | 3.0216 | 3.0216 | 0.4864

# IfcWall: Tijolo - Estrutural 255, Parede 53
In: 17
Description: Parede-interior-generico-in_loco-tijolo_maciço_sem_revestimento-255mm; Classification: Parede (Classificação ARCHICAD); 3E 14 02 00 Parede (NBR 15965-5 3E); Material: Tijolo - Estrutural
Pset_WallCommon - AcousticRating: 0,00; IsExternal: no; LoadBearing: yes
ArchiCADProperties - Wall Complexity: Straight; Geometry Method: Uniform; Reference Line Location: Outside Face; Inside Face Surface: Tijolo - Comum ao Comprido; Outside Face Surface: Tijolo - Comum ao Comprido; Wall Inside Slant Angle: 90 deg; Wall Outside Slant Angle: 90 deg; Structural Analytical Model Generation: yes; Element ID: Parede 53; Hotlink and Element ID: Parede 53; Layer: A--PRDE-VEDS-E-; Building Material / Composite / Profile / Fill: Tijolo - Estrutural; Building Material: Tijolo - Estrutural; Colliding Zones: Hall dos Elevadores; Related Zone Name: Hall dos Elevadores; Related Zone Number: 17; Locked: no; Home Story Name: Pavimento tipo; Home Story Number: 0; Element Type: Wall; Absolute Top Link Story: Vazio; Relative Top Link Story: Home + 1; Top Link Story: Home + 1 (Vazio); Structure Type: Basic; Parent ID: Parede 53; Building Materials (All): Tijolo - Estrutural; Surfaces (All): Tijolo - Comum ao Comprido; Slant Angle: 90 deg; Number of Openings: 0; Edge Surface: Tijolo - Comum ao Comprido; Position: Interior; Show On Renovation Filter: All Relevant Filters; Structural Function: Load-Bearing Element; Renovation Status: Existing
CLASSIFICAÇÕES GERAIS - Transmissão Sonora: 0
EXPRESSÕES DE TEXTO (Expressão) - ID Dinâmico por Classificação: Parede -Parede 53
SUPERFÍCIES (Mapas) - Superfície da Face (Geral): Tijolo - Comum ao Comprido; Área da Superfície da Face (Geral): 0.187426 m2
AC_Pset_RenovationAndPhasing - Renovation Status: Existing
Component Properties - Tijolo - Estrutural, Embodied Carbon: 100.026 (kgCO₂); Tijolo - Estrutural, Embodied Energy: 1250.32 MJ
Material Properties - Tijolo - Estrutural, ThermalConductivity: 0.6; Tijolo - Estrutural, SpecificHeatCapacity: 840 J/kg/K; Tijolo - Estrutural, MassDensity: 1500 kg/m3; Tijolo - Estrutural, Embodied Energy: 3 (MJ/kg); Tijolo - Estrutural, Embodied Carbon: 0.24 (kgCO₂/kg); Tijolo - Estrutural, Name: Tijolo - Estrutural; Tijolo - Estrutural, ID: VED; Tijolo - Estrutural, Participates in Collision Detection: yes
BaseQuantities - Length: 325 mm; Height: 2560 mm; Width: 255 mm; GrossFootprintArea: 0.1122 m2; NetFootprintArea: 0.1122 m2; GrossSideArea: 1.0896 m2; NetSideArea: 1.0896 m2; GrossVolume: 0.277849 m3; NetVolume: 0.277849 m3
ArchiCADQuantities - Number of Doors: 0; Number of Holes (Number of Empty Openings): 0; Number of Windows: 0; Number of Columns: 0; Volume of the Columns: 0 m3; Maximum Height of the Wall Skin on the Inside Face: 0 mm; Minimum Height of the Wall Skin on the Inside Face: 0 mm; Maximum Height of the Wall: 2560 mm; Minimum Height of the Wall: 0 mm; Maximum Height of the Wall Skin on the Outside Face: 0 mm; Minimum Height of the Wall Skin on the Outside Face: 0 mm; Air Skin Thickness: 0 mm; Area of the Doors: 0 m2; Combined Width of Doors: 0 mm; Wall Component Thickness on the Inside Face: 0 mm; Wall Component Thickness on the Outside Face: 0 mm; Area of the Windows: 0 m2; Combined Width of Windows: 0 mm; Analytic Surface Area of Openings on the Inside Face: -2.22045e-16 m2; Analytic Surface Area of Openings on the Outside Face: -6.66134e-16 m2; Average length of the Wall: 325 mm; Surface Area of the Wall Inside Face (Net): 1.0896 m2; Surface Area of the Wall Outside Face (Net): 1.0896 m2; Analytic Volume of the Openings: -2.22045e-16 m3; Length of Reference Line: 440 mm; Length of the Wall Inside Face (Conditional): 210 mm; Surface Area of the Wall Inside Face (Conditional): 1.0896 m2; Length of the Wall Outside Face (Conditional): 440 mm; Surface Area of the Wall Outside Face (Conditional): 1.0896 m2; Surface Area of the Wall Inside Face (Gross): 1.1264 m2; Surface Area of the Wall Outside Face (Gross): 1.1264 m2; End Thickness of the Wall: 255 mm; Length of the Wall at the Center: 325 mm; Length of the Wall on the Inside Face: 210 mm; Length of the Wall on the Outside Face: 440 mm; Surface Area of Empty Openings in the Wall: 0 m2; Area: 0.1122 m2; Height: 2560 mm; Volume (Net): 0.277849 m3; Width: 255 mm; Elevation to Project Zero: -100 mm; Elevation to 1º Nível de Referência: -100 mm; Elevation to 2º Nível de Referência: -100 mm; Elevation to Sea Level: 728120 mm; Elevation to Linked/Home Story: -100 mm; Home Offset: -100 mm; Top Offset: -240 mm; Surface Area: 1.0896 m2; 3D Length: 440.004 mm; Thickness: 255 mm; Volume (Conditional): 0.277849 m3; Volume (Gross): 0.287232 m3; Insulation Skin Thickness: 0 mm; Floor Plan Perimeter: 1211.32 mm; Top Elevation To First Reference Level: 2460 mm; Top Elevation To Home Story: 2460 mm; Top Elevation To Project Zero: 2460 mm; Top Elevation To Sea Level: 730680 mm; Top Elevation To Second Reference Level: 2460 mm; Bottom Elevation To First Reference Level: -100 mm; Bottom Elevation To Home Story: -100 mm; Bottom Elevation To Project Zero: -100 mm; Bottom Elevation To Sea Level: 728120 mm; Bottom Elevation To Second Reference Level: -100 mm; Top Surface Area (Net): 0.1122 m2; Edge Surface Area (Net): 0.187426 m2; Bottom Surface Area (Net): 1.0896 m2
ALVENARIAS (Expressão) - Espessura da Argamassa: 10 mm
Component Quantities - Tijolo - Estrutural, Mass: 416.773 kg; Tijolo - Estrutural, Projected Component Area (Net): 1.0896 m2; Tijolo - Estrutural, Projected Component Area (Gross): 1.0896 m2; Tijolo - Estrutural, Projected Component Area (Conditional): 1.0896 m2; Tijolo - Estrutural, Component Thickness: 255 mm; Tijolo - Estrutural, Rectangular Component Height: 2560 mm; Tijolo - Estrutural, Rectangular Component Width: 255 mm; Tijolo - Estrutural, Component Cross Section Area: 0.6528 m2; Tijolo - Estrutural, Component Volume (Net): 0.277849 m3; Tijolo - Estrutural, Component Volume (Gross): 0.277849 m3; Tijolo - Estrutural, Component Volume (Conditional): 0.277849 m3

# IfcWall: Tijolo - Estrutural 90 (47)
Classification: Parede (Classificação ARCHICAD); 3E 14 02 00 Parede (NBR 15965-5 3E); Material: Tijolo - Estrutural
Pset_WallCommon - AcousticRating: 0,00; LoadBearing: yes
ArchiCADProperties - Wall Complexity: Straight; Geometry Method: Uniform; Inside Face Surface: Tijolo - Comum ao Comprido; Outside Face Surface: Tijolo - Comum ao Comprido; Wall Inside Slant Angle: 90 deg; Wall Outside Slant Angle: 90 deg; Structural Analytical Model Generation: yes; Layer: A--PRDE-VEDS-E-; Building Material / Composite / Profile / Fill: Tijolo - Estrutural; Building Material: Tijolo - Estrutural; Home Story Name: Pavimento tipo; Home Story Number: 0; Element Type: Wall; Structure Type: Basic; Building Materials (All): Tijolo - Estrutural; Surfaces (All): Tijolo - Comum ao Comprido; Slant Angle: 90 deg; Number of Openings: 0; Edge Surface: Tijolo - Comum ao Comprido; Show On Renovation Filter: All Relevant Filters; Structural Function: Load-Bearing Element; Renovation Status: Existing
CLASSIFICAÇÕES GERAIS - Transmissão Sonora: 0
SUPERFÍCIES (Mapas) - Superfície da Face (Geral): Tijolo - Comum ao Comprido
AC_Pset_RenovationAndPhasing - Renovation Status: Existing
Material Properties - Tijolo - Estrutural, ThermalConductivity: 0.6; Tijolo - Estrutural, SpecificHeatCapacity: 840 J/kg/K; Tijolo - Estrutural, MassDensity: 1500 kg/m3; Tijolo - Estrutural, Embodied Energy: 3 (MJ/kg); Tijolo - Estrutural, Embodied Carbon: 0.24 (kgCO₂/kg); Tijolo - Estrutural, Name: Tijolo - Estrutural; Tijolo - Estrutural, ID: VED; Tijolo - Estrutural, Participates in Collision Detection: yes
BaseQuantities - Width: 90 mm
ArchiCADQuantities - Number of Windows: 0; Volume of the Columns: 0 m3; Maximum Height of the Wall Skin on the Inside Face: 0 mm; Minimum Height of the Wall Skin on the Inside Face: 0 mm; Maximum Height of the Wall Skin on the Outside Face: 0 mm; Minimum Height of the Wall Skin on the Outside Face: 0 mm; Air Skin Thickness: 0 mm; Wall Component Thickness on the Inside Face: 0 mm; Wall Component Thickness on the Outside Face: 0 mm; Area of the Windows: 0 m2; Combined Width of Windows: 0 mm; End Thickness of the Wall: 90 mm; Width: 90 mm; Thickness: 90 mm; Insulation Skin Thickness: 0 mm
ALVENARIAS (Expressão) - Espessura da Argamassa: 10 mm
Component Quantities - Tijolo - Estrutural, Component Thickness: 90 mm; Tijolo - Estrutural, Rectangular Component Width: 90 mm
Name | In | Description | IsExternal | Reference Line Location | Element ID = Parent ID | Hotlink and Element ID | Colliding Zones | Related Zone Name | Related Zone Number | Locked | Absolute Top Link Story | Relative Top Link Story | Top Link Story | Position | ID Dinâmico por Classificação | Tijolo - Estrutural, Embodied Carbon | Tijolo - Estrutural, Embodied Energy (MJ) | Length (mm) = Average length of the Wall (mm) = Length of the Wall at the Center (mm) | BaseQuantities, Height (mm) = Maximum Height of the Wall (mm) = ArchiCADQuantities, Height (mm) = Tijolo - Estrutural, Rectangular Component Height (mm) | GrossFootprintArea (m2) = NetFootprintArea (m2) = Area (m2) = Top Surface Area (Net) (m2) | GrossSideArea (m2) = Surface Area of the Wall Inside Face (Conditional) (m2) | NetSideArea (m2) = Surface Area of the Wall Inside Face (Net) (m2) | GrossVolume (m3) = Volume (Conditional) (m3) = Tijolo - Estrutural, Component Volume (Gross) (m3) | NetVolume (m3) = Volume (Net) (m3) = Tijolo - Estrutural, Component Volume (Net) (m3) | Number of Doors | Number of Holes (Number of Empty Openings) | Number of Columns | Minimum Height of the Wall (mm) | Area of the Doors (m2) | Combined Width of Doors (mm) | Analytic Surface Area of Openings on the Inside Face (m2) = Analytic Surface Area of Openings on the Outside Face (m2) | Surface Area of the Wall Outside Face (Net) (m2) = Surface Area (m2) = Bottom Surface Area (Net) (m2) | Analytic Volume of the Openings (m3) | Length of Reference Line (mm) | Length of the Wall Inside Face (Conditional) (mm) | Length of the Wall Outside Face (Conditional) (mm) | Surface Area of the Wall Outside Face (Conditional) (m2) | Surface Area of the Wall Inside Face (Gross) (m2) | Surface Area of the Wall Outside Face (Gross) (m2) | Length of the Wall on the Inside Face (mm) | Length of the Wall on the Outside Face (mm) | Surface Area of Empty Openings in the Wall (m2) | Elevation to Project Zero (mm) = Elevation to 1º Nível de Referência (mm) = Elevation to 2º Nível de Referência (mm) = Elevation to Linked/Home Story (mm) = Home Offset (mm) = Bottom Elevation To First Reference Level (mm) = Bottom Elevation To Home Story (mm) = Bottom Elevation To Project Zero (mm) = Bottom Elevation To Second Reference Level (mm) | Elevation to Sea Level (mm) = Bottom Elevation To Sea Level (mm) | Top Offset (mm) | 3D Length (mm) | Volume (Gross) (m3) | Floor Plan Perimeter (mm) | Top Elevation To First Reference Level (mm) = Top Elevation To Home Story (mm) = Top Elevation To Project Zero (mm) = Top Elevation To Second Reference Level (mm) | Top Elevation To Sea Level (mm) | Edge Surface Area (Net) (m2) = Área da Superfície da Face (Geral) (m2) | Tijolo - Estrutural, Mass (kg) | Tijolo - Estrutural, Projected Component Area (Net) (m2) | Tijolo - Estrutural, Projected Component Area (Gross) (m2) | Tijolo - Estrutural, Projected Component Area (Conditional) (m2) | Tijolo - Estrutural, Component Cross Section Area (m2) | Tijolo - Estrutural, Component Volume (Conditional) (m3) | Hotlink Master ID
Parede 50 | 19 | Parede-interior-generico-in_loco-tijolo_maciço_sem_revestimento-90mm | no | Outside Face | Parede 50 | Parede 50 | Interfone | Interfone | 19 | no | Vazio | Home + 1 | Home + 1 (Vazio) | Interior | Parede -Parede 50 | 17.4182 (kgCO₂) | 217.728 | 210 | 2560 | 0.0189 | 0.537599 | 0.537599 | 0.0483839 | 0.0483839 | 0 | 0 | 0 | 0 | 0 | 0 | 0 | 0.537599 | 0 | 440 | 210 | 210 | 0.537599 | 1.1264 | 1.1264 | 210 | 210 | 0 | -100 | 728120 | -240 | 210 | 0.101376 | 599.999 | 2460 | 730680 | 0.0377999 | 72.5759 | 0.537599 | 0.537599 | 0.537599 | 0.2304 | 0.0483839
Parede 54 | Pavimento tipo | Parede-interior-generico-in_loco-tijolo_maciço_sem_revestimento-90mm | no | Outside Face | Parede 54 | Parede 54 |  | Interfone | 22 | no | Vazio | Home + 1 | Home + 1 (Vazio) | Interior | Parede -Parede 54 | 17.4183 (kgCO₂) | 217.728 | 210 | 2560 | 0.0189 | 0.5376 | 0.5376 | 0.048384 | 0.048384 | 0 | 0 | 0 | 0 | 0 | 0 | 0 | 0.5376 | 0 | 440 | 210 | 210 | 0.5376 | 1.1264 | 1.1264 | 210 | 210 | 0 | -100 | 728120 | -240 | 210 | 0.101376 | 600 | 2460 | 730680 | 0.0378 | 72.576 | 0.5376 | 0.5376 | 0.5376 | 0.2304 | 0.048384
Parede 56 | Pavimento tipo | Parede-interior-generico-in_loco-tijolo_maciço_sem_revestimento-90mm | no | Outside Face | Parede 56 | Parede 56 |  | Prumada Força | 24 | no | Vazio | Home + 1 | Home + 1 (Vazio) | Interior | Parede -Parede 56 | 17.4183 (kgCO₂) | 217.728 | 210 | 2560 | 0.0189 | 0.5376 | 0.5376 | 0.048384 | 0.048384 | 0 | 0 | 0 | 0 | 0 | 0 | 0 | 0.5376 | 0 | 440 | 210 | 210 | 0.5376 | 1.1264 | 1.1264 | 210 | 210 | 0 | -100 | 728120 | -240 | 210 | 0.101376 | 600 | 2460 | 730680 | 0.0378 | 72.5761 | 0.5376 | 0.5376 | 0.5376 | 0.2304 | 0.048384
Parede 49 | Pavimento tipo | Parede-interior-generico-in_loco-tijolo_maciço_sem_revestimento-90mm | no | Outside Face | Parede 49 | Parede 49 |  | Prumada Força | 10 | no | Vazio | Home + 1 | Home + 1 (Vazio) | Interior | Parede -Parede 49 | 17.4182 (kgCO₂) | 217.728 | 210 | 2560 | 0.0189 | 0.537599 | 0.537599 | 0.048384 | 0.048384 | 0 | 0 | 0 | 0 | 0 | 0 | 0 | 0.5376 | 0 | 440 | 210 | 210 | 0.5376 | 1.1264 | 1.1264 | 210 | 210 | 0 | -100 | 728120 | -240 | 210 | 0.101376 | 600 | 2460 | 730680 | 0.0378 | 72.5759 | 0.537599 | 0.537599 | 0.537599 | 0.2304 | 0.048384
Parede 52 | Pavimento tipo | Parede-interior-generico-in_loco-tijolo_maciço_sem_revestimento-90mm | no | Outside Face | Parede 52 | Parede 52 |  | Corredor | 05 | no | Vazio | Home + 1 | Home + 1 (Vazio) | Interior | Parede -Parede 52 | 17.4182 (kgCO₂) | 217.727 | 254.999 | 2560 | 0.0188999 | 0.537598 | 0.537598 | 0.0483839 | 0.0483839 | 0 | 0 | 0 | 0 | 0 | 0 | 0 | 0.537598 | 0 | 439.999 | 209.999 | 299.999 | 0.537598 | 1.1264 | 1.1264 | 209.999 | 299.999 | 0 | -100 | 728120 | -240 | 209.999 | 0.101376 | 727.278 | 2460 | 730680 | 0.0377999 | 72.5758 | 0.537598 | 0.537598 | 0.537598 | 0.2304 | 0.0483839
Apt 01 - Parede 42 | 01 | Parede-exterior-generico-in_loco-tijolo_maciço_sem_revestimento-90mm | yes | Outside Face | Parede 42 | Apt 01 - Parede 42 | Apartamento 01 | Apartamento 01 | 01 | yes | Not Linked | Not Linked | Not Linked | Exterior | Parede -Parede 42 | 12.0139 (kgCO₂) | 150.174 | 430 | 1030 | 0.0324 | 0.3708 | 0.3708 | 0.033372 | 0.033372 | 0 | 0 | 1 | 0 | 0 | 0 | 0 | 0.370801 | 0 | 500.001 | 360 | 500.001 | 0.370801 | 0.515 | 0.515001 | 360 | 500.001 | 0 | 0 | 728220 | 0 | 360.001 | 0.04635 | 1116.44 | 1030 | 729250 | 0.1575 | 50.0581 | 0.370801 | 0.370801 | 0.370801 | 0.0927 | 0.033372 | Apt 01 -
Apt 01 - Parede 14 | 01 | Parede-interior-generico-in_loco-tijolo_maciço_sem_revestimento-90mm | no | Outside Face | Parede 14 | Apt 01 - Parede 14 | Apartamento 01 | Apartamento 01 | 01 | yes | Not Linked | Not Linked | Not Linked | Interior | Parede -Parede 14 | 114.093 (kgCO₂) | 1426.17 | 2370 | 2200 | 0.1431 | 5.214 | 3.5214 | 0.46926 | 0.316926 | 1 | 0 | 1 | 2200 | 1.6926 | 780 | 1.6926 | 3.5214 | 0.152334 | 2370 | 1590 | 1590 | 5.214 | 5.214 | 5.214 | 2370 | 2370 | 0 | 0 | 728220 | -500 | 2370 | 0.46926 | 4920 | 2200 | 730420 | 0.5571 | 475.389 | 3.5214 | 5.214 | 5.214 | 0.198 | 0.46926 | Apt 01 -
Apt 01 - Parede 21 | 01 | Parede-interior-generico-in_loco-tijolo_maciço_sem_revestimento-90mm | no | Outside Face | Parede 21 | Apt 01 - Parede 21 | Apartamento 01 | Apartamento 01 | 01 | yes | Not Linked | Not Linked | Not Linked | Interior | Parede -Parede 21 | 61.3786 (kgCO₂) | 767.232 | 785 | 2560 | 0.0666 | 1.8944 | 1.8944 | 0.170496 | 0.170496 | 0 | 0 | 0 | 0 | 0 | 0 | 0 | 1.8944 | 0 | 970 | 740 | 830 | 1.8944 | 2.4832 | 2.4832 | 740 | 830 | 0 | 0 | 728220 | -140 | 740 | 0.223488 | 1787.28 | 2560 | 730780 | 0.1332 | 255.744 | 1.8944 | 1.8944 | 1.8944 | 0.2304 | 0.170496 | Apt 01 -
Apt 01 - Parede 20 | 01 | Parede-interior-generico-in_loco-tijolo_maciço_sem_revestimento-90mm | no | Outside Face | Parede 20 | Apt 01 - Parede 20 | Apartamento 01 | Apartamento 01 | 01 | yes | Not Linked | Not Linked | Not Linked | Interior | Parede -Parede 20 | 84.564 (kgCO₂) | 1057.05 | 1769.99 | 2560 | 0.0837 | 4.0856 | 2.61 | 0.367704 | 0.2349 | 1 | 0 | 0 | 0 | 1.4756 | 680 | 1.4756 | 2.61 | 0.132804 | 1839.99 | 1019.99 | 1159.99 | 4.0856 | 4.71037 | 4.71037 | 1699.99 | 1839.99 | 0 | 0 | 728220 | -140 | 1610 | 0.423934 | 3796.41 | 2560 | 730780 | 0.2196 | 352.35 | 2.61 | 4.0856 | 4.0856 | 0.2304 | 0.367704 | Apt 01 -
Apt 01 - Parede 06 | 01 | Parede-interior-generico-in_loco-tijolo_maciço_sem_revestimento-90mm | no | Inside Face | Parede 06 | Apt 01 - Parede 06 | Apartamento 01 | Apartamento 01 | 01 | yes | Not Linked | Not Linked | Not Linked | Interior | Parede -Parede 06 | 45.8603 (kgCO₂) | 573.254 | 1340.02 | 2590 | 0.0378017 | 3.10804 | 1.41544 | 0.279724 | 0.12739 | 1 | 0 | 0 | 0 | 1.6926 | 780 | 1.6926 | 1.41544 | 0.152334 | 1270.02 | 560.019 | 560.018 | 3.10804 | 3.78285 | 3.78285 | 1340.02 | 1340.02 | 0 | -30 | 728190 | -140 | 1200.02 | 0.340456 | 3012.91 | 2560 | 730780 | 0.145802 | 191.085 | 1.41544 | 3.10804 | 3.10804 | 0.2331 | 0.279724 | Apt 01 -
Apt 01 - Parede 05 | 01 | Parede-interior-generico-in_loco-tijolo_maciço_sem_revestimento-90mm | no | Center | Parede 05 | Apt 01 - Parede 05 | Apartamento 01; Aréa Técnica | Apartamento 01 | 01 | yes | Not Linked | Not Linked | Not Linked | Interior | Parede -Parede 05 | 79.7655 (kgCO₂) | 997.069 | 970 | 2590 | 0.0873 | 2.4619 | 2.4619 | 0.221571 | 0.221571 | 0 | 0 | 0 | 0 | 0 | 0 | 0 | 2.4619 | 3.33067e-16 | 1085 | 970 | 970 | 2.4619 | 3.10665 | 3.10665 | 970 | 970 | 0 | -30 | 728190 | -140 | 970 | 0.279598 | 2120 | 2560 | 730780 | 0.162 | 332.356 | 2.4619 | 2.4619 | 2.4619 | 0.2331 | 0.221571 | Apt 01 -
Apt 01 - Parede 12 | 01 | Parede-interior-generico-in_loco-tijolo_maciço_sem_revestimento-90mm | no | Outside Face | Parede 12 | Apt 01 - Parede 12 | Apartamento 01 | Apartamento 01 | 01 | yes | Not Linked | Not Linked | Not Linked | Interior | Parede -Parede 12 | 19.0771 (kgCO₂) | 238.464 | 185 | 2560 | 0.0207 | 0.5888 | 0.5888 | 0.052992 | 0.052992 | 0 | 0 | 0 | 0 | 0 | 0 | 0 | 0.5888 | 0 | 320 | 140 | 230 | 0.5888 | 0.8192 | 0.8192 | 140 | 230 | 0 | 0 | 728220 | -140 | 230 | 0.073728 | 587.279 | 2560 | 730780 | 0.0414 | 79.488 | 0.5888 | 0.5888 | 0.5888 | 0.2304 | 0.052992 | Apt 01 -
Apt 01 - Parede 10 | 01 | Parede-interior-generico-in_loco-tijolo_maciço_sem_revestimento-90mm | no | Outside Face | Parede 10 | Apt 01 - Parede 10 | Apartamento 01 | Apartamento 01 | 01 | yes | Not Linked | Not Linked | Not Linked | Interior | Parede -Parede 10 | 15.662 (kgCO₂) | 195.775 | 894.999 | 2560 | 0.00629986 | 2.176 | 0.483396 | 0.19584 | 0.0435057 | 1 | 0 | 0 | 0 | 1.6926 | 780 | 1.6926 | 0.483396 | 0.152334 | 939.999 | 69.9984 | 159.999 | 2.176 | 2.6368 | 2.6368 | 849.999 | 939.999 | 0 | 0 | 728220 | -140 | 849.999 | 0.237312 | 2007.28 | 2560 | 730780 | 0.0827998 | 65.2585 | 0.483396 | 2.176 | 2.176 | 0.2304 | 0.19584 | Apt 01 -
Apt 01 - Parede 19 | 01 | Parede-interior-generico-in_loco-tijolo_maciço_sem_revestimento-90mm | no | Outside Face | Parede 19 | Apt 01 - Parede 19 | Apartamento 01 | Apartamento 01 | 01 | yes | Not Linked | Not Linked | Not Linked | Interior | Parede -Parede 19 | 257.957 (kgCO₂) | 3224.46 | 3065 | 2560 | 0.279901 | 7.9616 | 7.9616 | 0.716547 | 0.716547 | 0 | 0 | 0 | 0 | 0 | 0 | 0 | 7.9616 | 0 | 3300 | 3020 | 3110 | 7.9616 | 8.448 | 8.448 | 3020 | 3110 | 0 | 0 | 728220 | -140 | 3110.01 | 0.76032 | 6347.28 | 2560 | 730780 | 0.559801 | 1074.82 | 7.9616 | 7.9616 | 7.9616 | 0.2304 | 0.716547 | Apt 01 -
Apt 01 - Parede 18 | 01 | Parede-interior-generico-in_loco-tijolo_maciço_sem_revestimento-90mm | no | Center | Parede 18 | Apt 01 - Parede 18 | Apartamento 01 | Apartamento 01 | 01 | yes | Not Linked | Not Linked | Not Linked | Interior | Parede -Parede 18 | 177.458 (kgCO₂) | 2218.23 | 2955 | 2560 | 0.1809 | 7.3216 | 5.4771 | 0.658944 | 0.492939 | 0 | 1 | 0 | 0 | 0 | 0 | 1.8445 | 5.4771 | 0.166005 | 3050 | 2200 | 2010 | 7.3216 | 7.808 | 7.808 | 3050 | 2860 | 1.8445 | 0 | 728220 | -140 | 2860 | 0.70272 | 6210.24 | 2560 | 730780 | 0.6687 | 739.409 | 5.4771 | 7.3216 | 7.3216 | 0.2304 | 0.658944 | Apt 01 -
Parede 76 | 06 | Parede-interior-generico-in_loco-tijolo_maciço_sem_revestimento-90mm | no | Inside Face | Parede 76 | Parede 76 | Escada | Escada | 06 | no | Vazio | Home + 1 | Home + 1 (Vazio) | Interior | Parede -Parede 76 | 27.7992 (kgCO₂) | 347.49 | 400 | 2600 | 0.0297 | 0.858001 | 0.858001 | 0.0772201 | 0.0772201 | 0 | 0 | 0 | 0 | 0 | 0 | 0 | 0.858001 | 0 | 330 | 330 | 470 | 0.858001 | 1.456 | 1.456 | 330 | 470 | 0 | -20 | 728200 | -120 | 330 | 0.13104 | 1056.43 | 2580 | 730800 | 0.0594 | 115.83 | 0.858001 | 0.858001 | 0.858001 | 0.234 | 0.0772201
Parede 78 | 06 | Parede-interior-generico-in_loco-tijolo_maciço_sem_revestimento-90mm | no | Inside Face | Parede 78 | Parede 78 | Escada | Escada | 06 | no | Vazio | Home + 1 | Home + 1 (Vazio) | Interior | Parede -Parede 78 | 120.172 (kgCO₂) | 1502.15 | 2195 | 2600 | 0.19755 | 5.707 | 3.709 | 0.51363 | 0.33381 | 1 | 0 | 0 | 0 | 1.998 | 800 | 1.998 | 3.709 | 0.17982 | 2335 | 2195 | 2195 | 5.707 | 6.4182 | 6.4182 | 2195 | 2195 | 0 | -20 | 728200 | -120 | 2195 | 0.577638 | 4570 | 2580 | 730800 | 0.3951 | 500.715 | 3.709 | 5.707 | 5.707 | 0.234 | 0.51363
Apt 04 - Parede 21 | 04 | Parede-interior-generico-in_loco-tijolo_maciço_sem_revestimento-90mm | no | Outside Face | Parede 21 | Apt 04 - Parede 21 | Apartamento 04 | Apartamento 04 | 04 | yes | Not Linked | Not Linked | Not Linked | Interior | Parede -Parede 21 | 61.3786 (kgCO₂) | 767.232 | 785 | 2560 | 0.0666 | 1.8944 | 1.8944 | 0.170496 | 0.170496 | 0 | 0 | 0 | 0 | 0 | 0 | 0 | 1.8944 | 0 | 970 | 740 | 830 | 1.8944 | 2.4832 | 2.4832 | 740 | 830 | 0 | 0 | 728220 | -140 | 740 | 0.223488 | 1787.28 | 2560 | 730780 | 0.1332 | 255.744 | 1.8944 | 1.8944 | 1.8944 | 0.2304 | 0.170496 | Apt 04 -
Apt 04 - Parede 14 | 04 | Parede-interior-generico-in_loco-tijolo_maciço_sem_revestimento-90mm | no | Outside Face | Parede 14 | Apt 04 - Parede 14 | Apartamento 04 | Apartamento 04 | 04 | yes | Not Linked | Not Linked | Not Linked | Interior | Parede -Parede 14 | 114.093 (kgCO₂) | 1426.17 | 2370 | 2200 | 0.1431 | 5.214 | 3.5214 | 0.46926 | 0.316926 | 1 | 0 | 1 | 2200 | 1.6926 | 780 | 1.6926 | 3.5214 | 0.152334 | 2370 | 1590 | 1590 | 5.214 | 5.214 | 5.214 | 2370 | 2370 | 0 | 0 | 728220 | -500 | 2370 | 0.46926 | 4920 | 2200 | 730420 | 0.5571 | 475.389 | 3.5214 | 5.214 | 5.214 | 0.198 | 0.46926 | Apt 04 -
Apt 04 - Parede 05 | 04 | Parede-interior-generico-in_loco-tijolo_maciço_sem_revestimento-90mm | no | Center | Parede 05 | Apt 04 - Parede 05 | Apartamento 04 | Apartamento 04 | 04 | yes | Not Linked | Not Linked | Not Linked | Interior | Parede -Parede 05 | 79.7656 (kgCO₂) | 997.069 | 970 | 2590 | 0.0873 | 2.4619 | 2.4619 | 0.221571 | 0.221571 | 0 | 0 | 0 | 0 | 0 | 0 | 0 | 2.4619 | -6.10623e-16 | 1085 | 970 | 970 | 2.4619 | 3.10665 | 3.10665 | 970 | 970 | 0 | -30 | 728190 | -140 | 970 | 0.279598 | 2120 | 2560 | 730780 | 0.162 | 332.356 | 2.4619 | 2.4619 | 2.4619 | 0.2331 | 0.221571 | Apt 04 -
Apt 04 - Parede 20 | 04 | Parede-interior-generico-in_loco-tijolo_maciço_sem_revestimento-90mm | no | Outside Face | Parede 20 | Apt 04 - Parede 20 | Apartamento 04 | Apartamento 04 | 04 | yes | Not Linked | Not Linked | Not Linked | Interior | Parede -Parede 20 | 84.564 (kgCO₂) | 1057.05 | 1769.99 | 2560 | 0.0837 | 4.0856 | 2.61 | 0.367704 | 0.2349 | 1 | 0 | 0 | 0 | 1.4756 | 680 | 1.4756 | 2.61 | 0.132804 | 1839.99 | 1019.99 | 1159.99 | 4.0856 | 4.71037 | 4.71037 | 1699.99 | 1839.99 | 0 | 0 | 728220 | -140 | 1610 | 0.423934 | 3796.41 | 2560 | 730780 | 0.2196 | 352.35 | 2.61 | 4.0856 | 4.0856 | 0.2304 | 0.367704 | Apt 04 -
Apt 04 - Parede 18 | 04 | Parede-interior-generico-in_loco-tijolo_maciço_sem_revestimento-90mm | no | Center | Parede 18 | Apt 04 - Parede 18 | Apartamento 04 | Apartamento 04 | 04 | yes | Not Linked | Not Linked | Not Linked | Interior | Parede -Parede 18 | 177.458 (kgCO₂) | 2218.23 | 2955 | 2560 | 0.1809 | 7.3216 | 5.4771 | 0.658944 | 0.492939 | 0 | 1 | 1 | 0 | 0 | 0 | 1.8445 | 5.4771 | 0.166005 | 3050 | 2200 | 2010 | 7.3216 | 7.808 | 7.808 | 3050 | 2860 | 1.8445 | 0 | 728220 | -140 | 2860 | 0.70272 | 6210.24 | 2560 | 730780 | 0.6687 | 739.409 | 5.4771 | 7.3216 | 7.3216 | 0.2304 | 0.658944 | Apt 04 -
Apt 04 - Parede 12 | 04 | Parede-interior-generico-in_loco-tijolo_maciço_sem_revestimento-90mm | no | Outside Face | Parede 12 | Apt 04 - Parede 12 | Apartamento 04 | Apartamento 04 | 04 | yes | Not Linked | Not Linked | Not Linked | Interior | Parede -Parede 12 | 19.0771 (kgCO₂) | 238.464 | 185 | 2560 | 0.0207 | 0.5888 | 0.5888 | 0.052992 | 0.052992 | 0 | 0 | 0 | 0 | 0 | 0 | 0 | 0.5888 | 0 | 320 | 140 | 230 | 0.5888 | 0.8192 | 0.8192 | 140 | 230 | 0 | 0 | 728220 | -140 | 230 | 0.073728 | 587.279 | 2560 | 730780 | 0.0414 | 79.488 | 0.5888 | 0.5888 | 0.5888 | 0.2304 | 0.052992 | Apt 04 -
Apt 04 - Parede 06 | 04 | Parede-interior-generico-in_loco-tijolo_maciço_sem_revestimento-90mm | no | Inside Face | Parede 06 | Apt 04 - Parede 06 | Apartamento 04 | Apartamento 04 | 04 | yes | Not Linked | Not Linked | Not Linked | Interior | Parede -Parede 06 | 45.8603 (kgCO₂) | 573.254 | 1340.02 | 2590 | 0.0378017 | 3.10804 | 1.41544 | 0.279724 | 0.12739 | 1 | 0 | 0 | 0 | 1.6926 | 780 | 1.6926 | 1.41544 | 0.152334 | 1270.02 | 560.019 | 560.018 | 3.10804 | 3.78285 | 3.78285 | 1340.02 | 1340.02 | 0 | -30 | 728190 | -140 | 1200.02 | 0.340456 | 3012.91 | 2560 | 730780 | 0.145802 | 191.085 | 1.41544 | 3.10804 | 3.10804 | 0.2331 | 0.279724 | Apt 04 -
Apt 04 - Parede 42 | 04 | Parede-exterior-generico-in_loco-tijolo_maciço_sem_revestimento-90mm | yes | Outside Face | Parede 42 | Apt 04 - Parede 42 | Apartamento 04 | Apartamento 04 | 04 | yes | Not Linked | Not Linked | Not Linked | Exterior | Parede -Parede 42 | 12.0139 (kgCO₂) | 150.174 | 430 | 1030 | 0.0324 | 0.3708 | 0.3708 | 0.033372 | 0.033372 | 0 | 0 | 1 | 0 | 0 | 0 | 0 | 0.370801 | 0 | 500.001 | 360 | 500.001 | 0.370801 | 0.515 | 0.515001 | 360 | 500.001 | 0 | 0 | 728220 | 0 | 360.001 | 0.04635 | 1116.44 | 1030 | 729250 | 0.1575 | 50.0581 | 0.3708 | 0.3708 | 0.3708 | 0.0927 | 0.033372 | Apt 04 -
Apt 04 - Parede 19 | 04 | Parede-interior-generico-in_loco-tijolo_maciço_sem_revestimento-90mm | no | Outside Face | Parede 19 | Apt 04 - Parede 19 | Apartamento 04 | Apartamento 04 | 04 | yes | Not Linked | Not Linked | Not Linked | Interior | Parede -Parede 19 | 257.957 (kgCO₂) | 3224.46 | 3065 | 2560 | 0.2799 | 7.9616 | 7.9616 | 0.716546 | 0.716546 | 0 | 0 | 0 | 0 | 0 | 0 | 0 | 7.9616 | 0 | 3300 | 3020 | 3110 | 7.9616 | 8.448 | 8.448 | 3020 | 3110 | 0 | 0 | 728220 | -140 | 3110 | 0.76032 | 6347.28 | 2560 | 730780 | 0.5598 | 1074.82 | 7.9616 | 7.9616 | 7.9616 | 0.2304 | 0.716546 | Apt 04 -
Apt 04 - Parede 10 | 04 | Parede-interior-generico-in_loco-tijolo_maciço_sem_revestimento-90mm | no | Outside Face | Parede 10 | Apt 04 - Parede 10 | Apartamento 04 | Apartamento 04 | 04 | yes | Not Linked | Not Linked | Not Linked | Interior | Parede -Parede 10 | 15.662 (kgCO₂) | 195.775 | 894.999 | 2560 | 0.00629986 | 2.176 | 0.483396 | 0.19584 | 0.0435057 | 1 | 0 | 0 | 0 | 1.6926 | 780 | 1.6926 | 0.483396 | 0.152334 | 939.999 | 69.9984 | 159.999 | 2.176 | 2.6368 | 2.6368 | 849.999 | 939.999 | 0 | 0 | 728220 | -140 | 849.999 | 0.237312 | 2007.28 | 2560 | 730780 | 0.0827998 | 65.2585 | 0.483396 | 2.176 | 2.176 | 0.2304 | 0.19584 | Apt 04 -
Apt 03 - Parede 33 | 03 | Parede-interior-generico-in_loco-tijolo_maciço_sem_revestimento-90mm | no | Outside Face | Parede 33 | Apt 03 - Parede 33 | Apartamento 03 | Apartamento 03 | 03 | yes | Not Linked | Not Linked | Not Linked | Interior | Parede -Parede 33 | 245.527 (kgCO₂) | 3069.09 | 2945 | 2560 | 0.2736 | 7.57801 | 7.57801 | 0.682021 | 0.682021 | 0 | 0 | 0 | 0 | 0 | 0 | 0 | 7.57801 | 0 | 3085 | 2900 | 2990 | 7.57801 | 8.01281 | 8.01281 | 2900 | 2990 | 0 | 0 | 728220 | -140 | 3040 | 0.721153 | 6107.28 | 2560 | 730780 | 0.5346 | 1023.03 | 7.57801 | 7.57801 | 7.57801 | 0.2304 | 0.682021 | Apt 03 -
Apt 03 - Parede 37 | 03 | Parede-interior-generico-in_loco-tijolo_maciço_sem_revestimento-90mm | no | Outside Face | Parede 37 | Apt 03 - Parede 37 | Apartamento 03 | Apartamento 03 | 03 | yes | Not Linked | Not Linked | Not Linked | Interior | Parede -Parede 37 | 12.207 (kgCO₂) | 152.587 | 192.171 | 2560 | 0.0132454 | 0.376759 | 0.376759 | 0.0339083 | 0.0339083 | 0 | 0 | 0 | 0 | 0 | 0 | 0 | 0.376759 | 0 | 377.171 | 147.171 | 237.171 | 0.376759 | 0.965559 | 0.965559 | 147.171 | 237.171 | 0 | 0 | 728220 | -140 | 147.171 | 0.0869003 | 601.622 | 2560 | 730780 | 0.0264909 | 50.8624 | 0.376759 | 0.376759 | 0.376759 | 0.2304 | 0.0339083 | Apt 03 -
Apt 03 - Parede 30 | 03 | Parede-interior-generico-in_loco-tijolo_maciço_sem_revestimento-90mm | no | Outside Face | Parede 30 | Apt 03 - Parede 30 | Apartamento 03; Aréa Técnica | Apartamento 03 | 03 | yes | Not Linked | Not Linked | Not Linked | Interior | Parede -Parede 30 | 66.3552 (kgCO₂) | 829.44 | 755 | 2560 | 0.072 | 2.048 | 2.048 | 0.18432 | 0.18432 | 0 | 0 | 0 | 0 | 0 | 0 | 0 | 2.048 | 0 | 940 | 710 | 800 | 2.048 | 2.4064 | 2.4064 | 710 | 800 | 0 | 0 | 728220 | -140 | 800 | 0.216576 | 1727.28 | 2560 | 730780 | 0.144 | 276.48 | 2.048 | 2.048 | 2.048 | 0.2304 | 0.18432 | Apt 03 -
Apt 03 - Parede 29 | 03 | Parede-interior-generico-in_loco-tijolo_maciço_sem_revestimento-90mm | no | Inside Face | Parede 29 | Apt 03 - Parede 29 | Apartamento 03 | Apartamento 03 | 03 | yes | Not Linked | Not Linked | Not Linked | Interior | Parede -Parede 29 | 157.574 (kgCO₂) | 1969.68 | 3050 | 2200 | 0.198 | 6.556 | 4.8634 | 0.59004 | 0.437706 | 1 | 0 | 2 | 0 | 1.6926 | 780 | 1.6926 | 4.8634 | 0.152334 | 2980 | 2200 | 2340 | 6.556 | 6.864 | 6.864 | 2980 | 3120 | 0 | 0 | 728220 | -500 | 2980 | 0.61776 | 6356.43 | 2200 | 730420 | 0.6642 | 656.559 | 4.8634 | 6.556 | 6.556 | 0.198 | 0.59004 | Apt 03 -
Apt 03 - Parede 31 | 03 | Parede-interior-generico-in_loco-tijolo_maciço_sem_revestimento-90mm | no | Outside Face | Parede 31 | Apt 03 - Parede 31 | Apartamento 03 | Apartamento 03 | 03 | yes | Not Linked | Not Linked | Not Linked | Interior | Parede -Parede 31 | 52.7215 (kgCO₂) | 659.018 | 1220 | 2560 | 0.0486002 | 3.1232 | 1.62721 | 0.281088 | 0.146449 | 0 | 1 | 0 | 0 | 0 | 0 | 1.496 | 1.62721 | 0.13464 | 1290 | 540.002 | 540.002 | 3.1232 | 4.07081 | 4.07081 | 1220 | 1220 | 1.496 | 0 | 728220 | -140 | 1220 | 0.366373 | 2620 | 2560 | 730780 | 0.1584 | 219.673 | 1.62721 | 3.1232 | 3.12321 | 0.2304 | 0.281089 | Apt 03 -
Apt 03 - Parede 40 | 03 | Parede-interior-generico-in_loco-tijolo_maciço_sem_revestimento-90mm | no | Center | Parede 40 | Apt 03 - Parede 40 | Apartamento 03 | Apartamento 03 | 03 | yes | Not Linked | Not Linked | Not Linked | Interior | Parede -Parede 40 | 152.52 (kgCO₂) | 1906.5 | 2455 | 2560 | 0.1548 | 6.4 | 4.7074 | 0.576 | 0.423666 | 1 | 0 | 0 | 0 | 1.6926 | 780 | 1.6926 | 4.7074 | 0.152334 | 2500 | 1720 | 1630 | 6.4 | 6.598 | 6.598 | 2500 | 2410 | 0 | 0 | 728220 | -140 | 2500 | 0.59382 | 5127.28 | 2560 | 730780 | 0.3798 | 635.499 | 4.7074 | 6.4 | 6.4 | 0.2304 | 0.576 | Apt 03 -
Apt 02 - Parede 30 | 12 | Parede-interior-generico-in_loco-tijolo_maciço_sem_revestimento-90mm | no | Outside Face | Parede 30 | Apt 02 - Parede 30 | Apartamento 02; Aréa Técnica | Apartamento 02 | 02 | yes | Not Linked | Not Linked | Not Linked | Interior | Parede -Parede 30 | 66.3552 (kgCO₂) | 829.44 | 755 | 2560 | 0.072 | 2.048 | 2.048 | 0.18432 | 0.18432 | 0 | 0 | 0 | 0 | 0 | 0 | 0 | 2.048 | 0 | 940 | 710 | 800 | 2.048 | 2.4064 | 2.4064 | 710 | 800 | 0 | 0 | 728220 | -140 | 800 | 0.216576 | 1727.28 | 2560 | 730780 | 0.144 | 276.48 | 2.048 | 2.048 | 2.048 | 0.2304 | 0.18432 | Apt 02 -
Parede 73 | 17 | Parede-interior-generico-in_loco-tijolo_maciço_sem_revestimento-90mm | no | Outside Face | Parede 73 | Parede 73 | Hall dos Elevadores | Hall dos Elevadores | 17 | no | Vazio | Home + 1 | Home + 1 (Vazio) | Interior | Parede -Parede 73 | 20.2176 (kgCO₂) | 252.72 | 195 | 2600 | 0.0216 | 0.624 | 0.624 | 0.05616 | 0.05616 | 0 | 0 | 0 | 0 | 0 | 0 | 0 | 0.624 | 0 | 380 | 150 | 240 | 0.624 | 0.988 | 0.988 | 150 | 240 | 0 | -20 | 728200 | -120 | 240 | 0.08892 | 607.279 | 2580 | 730800 | 0.0432 | 84.24 | 0.624 | 0.624 | 0.624 | 0.234 | 0.05616
Parede 72 | 17 | Parede-interior-generico-in_loco-tijolo_maciço_sem_revestimento-90mm | no | Outside Face | Parede 72 | Parede 72 | Hall dos Elevadores | Hall dos Elevadores | 17 | no | Vazio | Home + 1 | Home + 1 (Vazio) | Interior | Parede -Parede 72 | 104.458 (kgCO₂) | 1305.72 | 1240 | 2600 | 0.1116 | 3.224 | 3.224 | 0.29016 | 0.29016 | 0 | 0 | 0 | 0 | 0 | 0 | 0 | 3.224 | 0 | 1330 | 1150 | 1330 | 3.224 | 3.458 | 3.458 | 1150 | 1330 | 0 | -20 | 728200 | -120 | 1240 | 0.31122 | 2734.56 | 2580 | 730800 | 0.2232 | 435.24 | 3.224 | 3.224 | 3.224 | 0.234 | 0.29016
Parede 74 | 17 | Parede-interior-generico-in_loco-tijolo_maciço_sem_revestimento-90mm | no | Outside Face | Parede 74 | Parede 74 | Hall dos Elevadores | Hall dos Elevadores | 17 | no | Vazio | Home + 1 | Home + 1 (Vazio) | Interior | Parede -Parede 74 | 12.636 (kgCO₂) | 157.95 | 195 | 2600 | 0.0135 | 0.39 | 0.39 | 0.0351 | 0.0351 | 0 | 0 | 0 | 0 | 0 | 0 | 0 | 0.39 | 0 | 380 | 150 | 240 | 0.39 | 0.988 | 0.988 | 150 | 240 | 0 | -20 | 728200 | -120 | 150 | 0.08892 | 607.279 | 2580 | 730800 | 0.027 | 52.65 | 0.39 | 0.39 | 0.39 | 0.234 | 0.0351
Apt 02 - Parede 29 | 02 | Parede-interior-generico-in_loco-tijolo_maciço_sem_revestimento-90mm | no | Inside Face | Parede 29 | Apt 02 - Parede 29 | Apartamento 02 | Apartamento 02 | 02 | yes | Not Linked | Not Linked | Not Linked | Interior | Parede -Parede 29 | 157.574 (kgCO₂) | 1969.68 | 3050 | 2200 | 0.198 | 6.556 | 4.8634 | 0.59004 | 0.437706 | 1 | 0 | 2 | 0 | 1.6926 | 780 | 1.6926 | 4.8634 | 0.152334 | 2980 | 2200 | 2340 | 6.556 | 6.864 | 6.864 | 2980 | 3120 | 0 | 0 | 728220 | -500 | 2980 | 0.61776 | 6356.43 | 2200 | 730420 | 0.6642 | 656.559 | 4.8634 | 6.556 | 6.556 | 0.198 | 0.59004 | Apt 02 -
Apt 02 - Parede 40 | 02 | Parede-interior-generico-in_loco-tijolo_maciço_sem_revestimento-90mm | no | Center | Parede 40 | Apt 02 - Parede 40 | Apartamento 02 | Apartamento 02 | 02 | yes | Not Linked | Not Linked | Not Linked | Interior | Parede -Parede 40 | 152.52 (kgCO₂) | 1906.5 | 2455 | 2560 | 0.1548 | 6.4 | 4.7074 | 0.576 | 0.423666 | 1 | 0 | 0 | 0 | 1.6926 | 780 | 1.6926 | 4.7074 | 0.152334 | 2500 | 1720 | 1630 | 6.4 | 6.598 | 6.598 | 2500 | 2410 | 0 | 0 | 728220 | -140 | 2500 | 0.59382 | 5127.28 | 2560 | 730780 | 0.3798 | 635.499 | 4.7074 | 6.4 | 6.4 | 0.2304 | 0.576 | Apt 02 -
Apt 02 - Parede 37 | 02 | Parede-interior-generico-in_loco-tijolo_maciço_sem_revestimento-90mm | no | Outside Face | Parede 37 | Apt 02 - Parede 37 | Apartamento 02 | Apartamento 02 | 02 | yes | Not Linked | Not Linked | Not Linked | Interior | Parede -Parede 37 | 12.207 (kgCO₂) | 152.587 | 192.171 | 2560 | 0.0132454 | 0.376759 | 0.376759 | 0.0339083 | 0.0339083 | 0 | 0 | 0 | 0 | 0 | 0 | 0 | 0.376759 | 0 | 377.171 | 147.171 | 237.171 | 0.376759 | 0.965559 | 0.965559 | 147.171 | 237.171 | 0 | 0 | 728220 | -140 | 147.171 | 0.0869003 | 601.622 | 2560 | 730780 | 0.0264909 | 50.8624 | 0.376759 | 0.376759 | 0.376759 | 0.2304 | 0.0339083 | Apt 02 -
Apt 02 - Parede 31 | 02 | Parede-interior-generico-in_loco-tijolo_maciço_sem_revestimento-90mm | no | Outside Face | Parede 31 | Apt 02 - Parede 31 | Apartamento 02 | Apartamento 02 | 02 | yes | Not Linked | Not Linked | Not Linked | Interior | Parede -Parede 31 | 52.7215 (kgCO₂) | 659.018 | 1220 | 2560 | 0.0486002 | 3.1232 | 1.62721 | 0.281088 | 0.146449 | 0 | 1 | 0 | 0 | 0 | 0 | 1.496 | 1.62721 | 0.13464 | 1290 | 540.002 | 540.002 | 3.1232 | 4.07081 | 4.07081 | 1220 | 1220 | 1.496 | 0 | 728220 | -140 | 1220 | 0.366373 | 2620 | 2560 | 730780 | 0.1584 | 219.673 | 1.62721 | 3.1232 | 3.12321 | 0.2304 | 0.281089 | Apt 02 -
Apt 02 - Parede 33 | 02 | Parede-interior-generico-in_loco-tijolo_maciço_sem_revestimento-90mm | no | Outside Face | Parede 33 | Apt 02 - Parede 33 | Apartamento 02 | Apartamento 02 | 02 | yes | Not Linked | Not Linked | Not Linked | Interior | Parede -Parede 33 | 245.527 (kgCO₂) | 3069.09 | 2945 | 2560 | 0.2736 | 7.57801 | 7.57801 | 0.682021 | 0.682021 | 0 | 0 | 0 | 0 | 0 | 0 | 0 | 7.57801 | 0 | 3085 | 2900 | 2990 | 7.57801 | 8.01281 | 8.01281 | 2900 | 2990 | 0 | 0 | 728220 | -140 | 3040 | 0.721153 | 6107.28 | 2560 | 730780 | 0.5346 | 1023.03 | 7.57801 | 7.57801 | 7.57801 | 0.2304 | 0.682021 | Apt 02 -
Parede 51 | Pavimento tipo | Parede-interior-generico-in_loco-tijolo_maciço_sem_revestimento-90mm | no | Outside Face | Parede 51 | Parede 51 |  | Interfone | 19 | no | Vazio | Home + 1 | Home + 1 (Vazio) | Interior | Parede -Parede 51 | 17.4182 (kgCO₂) | 217.727 | 209.999 | 2560 | 0.0189 | 0.537599 | 0.537599 | 0.0483839 | 0.0483839 | 0 | 0 | 0 | 0 | 0 | 0 | 0 | 0.537599 | 0 | 440 | 209.999 | 209.999 | 0.537599 | 1.1264 | 1.1264 | 209.999 | 209.999 | 0 | -100 | 728120 | -240 | 209.999 | 0.101376 | 599.999 | 2460 | 730680 | 0.0377999 | 72.5758 | 0.537599 | 0.537599 | 0.537599 | 0.2304 | 0.0483839
Parede 50 | Pavimento tipo | Parede-interior-generico-in_loco-tijolo_maciço_sem_revestimento-90mm | no | Outside Face | Parede 50 | Parede 50 |  | Telefone / Tv | 18 | no | Vazio | Home + 1 | Home + 1 (Vazio) | Interior | Parede -Parede 50 | 17.4182 (kgCO₂) | 217.728 | 210 | 2560 | 0.0189 | 0.537599 | 0.537599 | 0.0483839 | 0.0483839 | 0 | 0 | 0 | 0 | 0 | 0 | 0 | 0.537599 | 0 | 440 | 210 | 210 | 0.537599 | 1.1264 | 1.1264 | 210 | 210 | 0 | -100 | 728120 | -240 | 210 | 0.101376 | 599.999 | 2460 | 730680 | 0.0377999 | 72.5759 | 0.537599 | 0.537599 | 0.537599 | 0.2304 | 0.0483839
Parede 59 | Pavimento tipo | Parede-interior-generico-in_loco-tijolo_maciço_sem_revestimento-90mm | no | Outside Face | Parede 59 | Parede 59 |  | Corredor | 05 | no | Vazio | Home + 1 | Home + 1 (Vazio) | Interior | Parede -Parede 59 | 320.579 (kgCO₂) | 4007.23 | 3820 | 2560 | 0.34785 | 9.8944 | 9.8944 | 0.890496 | 0.890496 | 0 | 0 | 1 | 0 | 0 | 0 | 0 | 9.8944 | 0 | 3865 | 3775 | 3865 | 9.8944 | 9.8944 | 9.8944 | 3775 | 3865 | 0 | -100 | 728120 | -240 | 3865 | 0.890496 | 7857.28 | 2460 | 730680 | 0.9261 | 1335.74 | 9.8944 | 9.8944 | 9.8944 | 0.2304 | 0.890496
Parede 62 | Pavimento tipo | Parede-interior-generico-in_loco-tijolo_maciço_sem_revestimento-90mm | no | Outside Face | Parede 62 | Parede 62 |  | Corredor | 05 | no | Vazio | Home + 1 | Home + 1 (Vazio) | Interior | Parede -Parede 62 | 253.394 (kgCO₂) | 3167.42 | 3182.5 | 2560 | 0.27495 | 7.8208 | 7.8208 | 0.703872 | 0.703872 | 0 | 0 | 1 | 0 | 0 | 0 | 0 | 7.8208 | 0 | 3310 | 3055 | 3310 | 7.8208 | 8.4736 | 8.4736 | 3055 | 3310 | 0 | -100 | 728120 | -240 | 3055 | 0.762624 | 6725.42 | 2460 | 730680 | 0.7803 | 1055.81 | 7.8208 | 7.8208 | 7.8208 | 0.2304 | 0.703872
Parede 55 | Pavimento tipo | Parede-interior-generico-in_loco-tijolo_maciço_sem_revestimento-90mm | no | Outside Face | Parede 55 | Parede 55 |  | Telefone / Tv | 23 | no | Vazio | Home + 1 | Home + 1 (Vazio) | Interior | Parede -Parede 55 | 17.4183 (kgCO₂) | 217.728 | 210 | 2560 | 0.0189 | 0.5376 | 0.5376 | 0.048384 | 0.048384 | 0 | 0 | 0 | 0 | 0 | 0 | 0 | 0.5376 | 0 | 440 | 210 | 210 | 0.5376 | 1.1264 | 1.1264 | 210 | 210 | 0 | -100 | 728120 | -240 | 210 | 0.101376 | 600 | 2460 | 730680 | 0.0378 | 72.5761 | 0.5376 | 0.5376 | 0.5376 | 0.2304 | 0.048384

# IfcWindow: Janela 26 (6)
Type - OperationType: DOUBLE_PANEL_VERTICAL; ParameterTakesPrecedence: no; Sizeable: no
Type - Window Lining Properties - LiningDepth: 50 mm; LiningThickness: 35 mm; MullionThickness: 50 mm; FirstMullionOffset: 0.5
Type - Window Panel Properties - Panel 1 - OperationType: SLIDINGHORIZONTAL; PanelPosition: LEFT; FrameDepth: 20 mm; FrameThickness: 50 mm
Type - Window Panel Properties - Panel 2 - OperationType: SLIDINGHORIZONTAL; PanelPosition: RIGHT; FrameDepth: 20 mm; FrameThickness: 50 mm
Classification: Janela (Classificação ARCHICAD); 3E 20 04 02 02 Janela de correr (NBR 15965-5 3E)
Pset_WindowCommon - ThermalTransmittance: 0
ArchiCADProperties - Wall Structure: Tijolo - Estrutural; Orientation: L; Opening Library Part Name: Janela 26; Opening Side Fill Index: Trama Vazia; Layer: A--PRDE-VEDS-E-; Library Part Name: Janela 26; Building Material / Composite / Profile / Fill: Trama Vazia; Fill Type: Trama Vazia; Locked: yes; Home Story Name: Pavimento tipo; Home Story Number: 0; Element Type: Window; Surfaces (All): Vidro - Simples; Metal - Alumínio; Show On Renovation Filter: All Relevant Filters; Structural Function: Non-Load-Bearing Element; Renovation Status: Existing
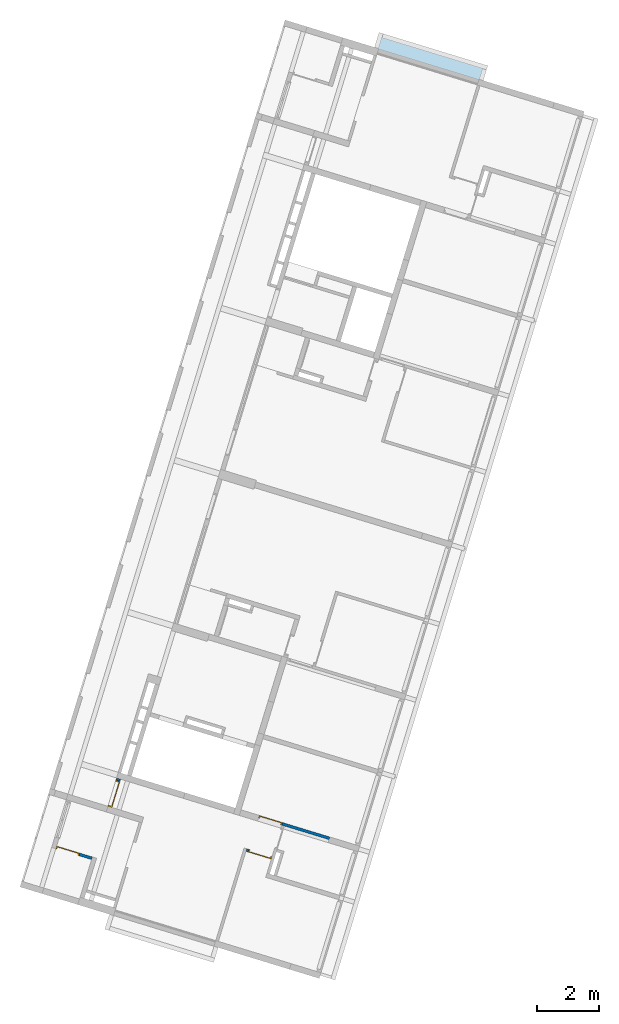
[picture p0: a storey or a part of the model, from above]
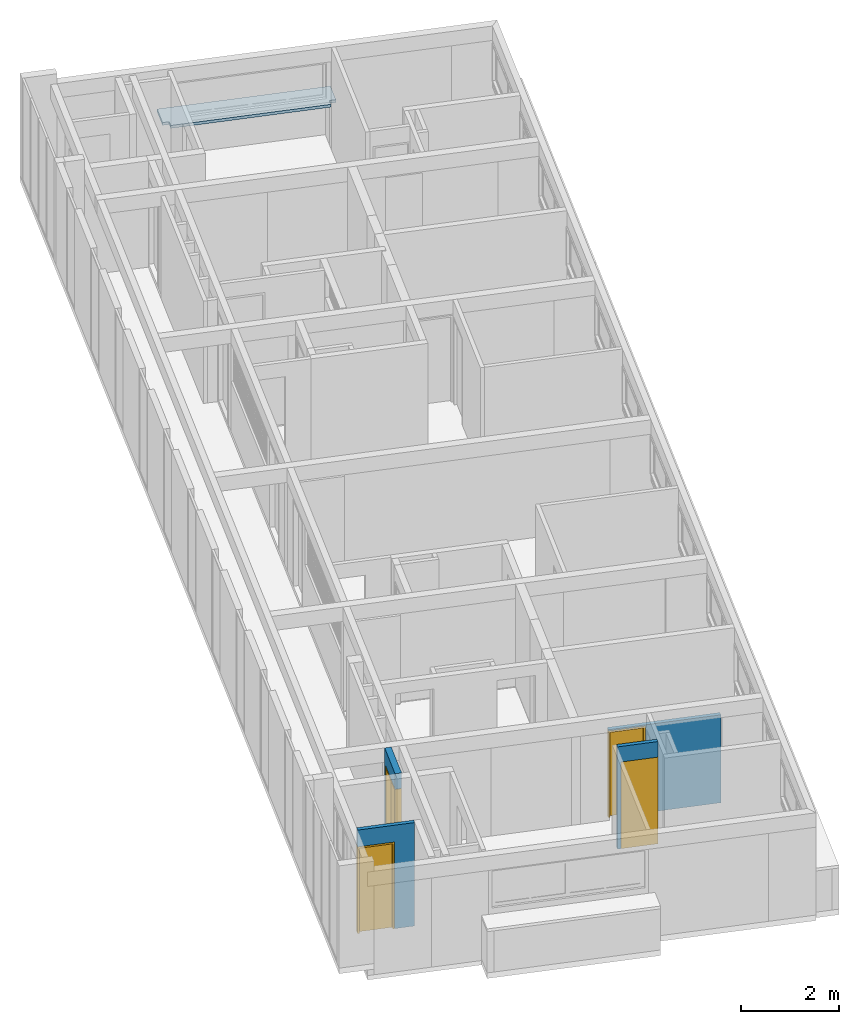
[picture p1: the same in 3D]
Properties of the parts of a building model (IFC2X3), part 9 of 11

# IfcWindow: Janela 26 (2)
AC_Pset_Janela_26 - Contornos Parede (0-Nenhum,1-Completo,2-Lado,3-Comprimento): 0; Pontos-Quentes 0-Nenhum,1-2D,2-3D,3-Todos: 3; Opção de Visualização em Planta: 3; Ângulo de Posição da Abertura: 0 deg; Furo tem Superfície Lateral Parede: yes; Furos em Divisão de Superfícies são Curvos em Paredes Curvas: no; Mostrar Pontos-Quentes 2D em 3D: yes; Tipo de Parede: 1; Tipo de Direção de Parede: 0; Posição de Ancoragem da Abertura: 1; Função de correção de erros de Janela de canto: no; Tipo de Posicionamento (1=CW,0=W): no; Corda: no; Demolição / Nova Construção: 1; Novo Tipo de Trama de Parede: Bloco; Nova Caneta de Trama de Parede: Geral - Geral; Nova Caneta de Fundo de Trama de Parede: Fundos - Cor 1; Mostrar nova construção na Parede: no; Tipo de linha de demolição: 4; Mostrar parâmetro Demolição / Novo: no; Função Janela de Canto: yes; Ângulo de Canto: 90 deg; Espess. Dif. Parede Conexão: no; Pilar de Canto: no; Canto 2: no; Ângulo do Canto 2: 90 deg; Dif. Conexões de Espessura Parede 2: no; Canto 1: no; Ângulo do Canto 1: 90 deg; Dif. Conexões de Espessura Parede 1: no; Tipo de Conexão 1 do Canto: 1; Tipo de Conexão 2 do Canto: 1; Inteiramente Editável: yes; 2D: 1; Mostrar Face de Vão em Símbolo: 2; 3D: 8; Tamanho Nominal: 0; Definir Tamanho de Vão como Tamanho Nominal: yes; Definir Tamanho de Reentrância como Tamanho Nominal: no; Definir Tamanho de Unidade como Tamanho Nominal: no; Transferir Tamanho Nominal Atual para Seleção: no; Painéis Horizontais: 1; Largura Uniforme Batente: yes; Bandeira Superior: no; Bandeira Superior Dividida: no; Bandeira Inferior: no; Bandeira Inferior Dividida: no; Painéis Verticais: 3; Caixilhos Uniformes: no; Direção do Vidro Fixo (FixGlassDir): Pela Direção da Abertura; Direção do Vidro Fixo (FixGlassDir_m): 1; Tipo Abertura Caixilho Principal: Presa Topo; Tipo Abertura (gs_optype_m_01): 8; Tipo Abertura (gs_optype_m_03): 1; Tipo Abertura Caixilho Travessa: Vidro Fixo; Tipo Abertura (gs_optype_m_02): 1; Tipo Caixilho (MullionStyle_00): Sem Grelha; Tipo Caixilho (iMullionStyle_00): 1; Tipo Caixilho Caixilho Principal: Sem Grelha; Tipo Caixilho (iMullionStyle_01): 1; Tipo Caixilho (iMullionStyle_03): 1; Tipo Caixilho Caixilho Travessa: Sem Montantes; Tipo Caixilho (iMullionStyle_02): 1; Painel Person. Espelhado (gs_bMirr_cust_panel_01): no; Painel Person. Espelhado (gs_bMirr_cust_panel2_01): no; Painel Person. Espelhado (gs_bMirr_cust_panel_03): no; Painel Person. Espelhado (gs_bMirr_cust_panel2_03): no; Painel Person. Espelhado (gs_bMirr_cust_panel_02): no; Painel Person. Espelhado (gs_bMirr_cust_panel2_02): no; Editar Ponto-quente Grelha: yes; Posição Grelha (MullionPosition): Por tudo; Posição Grelha (iMullionPosition): 3; Nº Paineis Verticais Caixilho Principal: 3; Nº Paineis Horizontais Caixilho Principal: 4; Nº Paineis Verticais 2 Caixilho Principal: 3; Nº Paineis Horizontais 2 Caixilho Principal: 4; Nº Paineis Verticais Caixilho Inferior: 1; Nº Paineis Horizontais Caixilho Inferior: 4; Nº Paineis Verticais 2 Caixilho Inferior: 1; Nº Paineis Horizontais 2 Caixilho Inferior 2: 4; Nº Paineis Verticais Caixilho Travessa: 1; Nº Paineis Horizontais Caixilho Travessa: 4; Nº Paineis Verticais 2 Caixilho Travessa: 1; Nº Paineis Horizontais 2 Caixilho Travessa: 4; Estilo Venezianas (iLouverStyle): 1; Ângulo de Abertura de Lanternins: 0 deg; Maçaneta Janela: no; Tipo Maçaneta Janela (gs_handle_type_win): Estilo 1; Tipo Maçaneta Janela (gs_handle_type_win_m): 1; Guarnição Externa: no; Tipo Guarnição Externa (gs_trimtype_out): Simples; Tipo Guarnição Externa (gs_trimtype_out_int): 1; Tipo de Travessa Guarnição Externa: 1; Arquitrave Principal: yes; Tipo Arquitrave Principal: 1; Guarnição Externa Inferior: yes; Guarnição/Alizar na Superfície Externa da Parede: yes; Larguras Uniformes da Guarnição (gs_trim_outside_uniform): no; Guarnição Interna: yes; Tipo Guarnição Interna (gs_trimtype_in): Simples; Tipo Guarnição Interna (gs_trimtype_in_int): 1; Guarnição/Alizar na Superfície Interna da Parede: yes; Larguras Uniformes da Guarnição (gs_trim_inside_uniform): yes; Soleira/Peitoril (gs_sill_outside): no; Sobredim. Peitoril: no; Tipo de Parapeito Exterior: 3; Ângulo Peitoril: 8 deg; Parapeito Curvo em Paredes Curvas: yes; Isolamento abaixo do Peitoril: yes; Usar Camada Isolamento de Parede: no; Nível Detalhe 3D Peitoril Tijolo: 1; Peitoril Interno (gs_board_inside): no; Ângulo Peitoril Int.: 0 deg; Peitoril Int. Curvado em Paredes Curvas: yes; Peitoril Int. em Paredes Poligonais: 1; Ventilação Natural: no; Tipo Ventilação Natural: 2; Caixilho Principal: yes; Caixilho Inferior: no; Caixilho Bandeira: no; Quebra-Sol: no; Tipo Quebra-Sol: 1; Tipos de Quebra-Sol Ativados: 126; Número de Paineis: 2; Número de Paineis 2: 1; Posição Painel (gs_shutter_panelPos): Simétrico; Posição Painel (gs_shutter_iPanelPos): 1; Altura Automática Veneziana: yes; Batente Extra: no; Tipo Cobertura (gs_slidingShutter_cover): Perfil-Z; Tipo Cobertura (gs_slidingShutter_iCover): 1; Direção de Empilham. (gs_foldingShutter_stacking): Dentro; Direção de Empilham. (gs_foldingShutter_iStacking): 1; Abrir em 3D: yes; Ângulo de abertura 3D: 180 deg; Mostrar Símbolo 2D: yes; Mostrar Linhas de Abertura no Símbolo: no; Tipo Painel (gs_shutPanel_type): Estilo 1; Tipo Painel (gs_shutPanel_iType): 1; Largura Base Batente Diferente: no; Largura Automática Veneziana: yes; Ângulo Grelha Ventilação: 30 deg; Nº Vãos Horiz.: 5; Nº Vãos Vert.: 8; Posição Rolamento Veneziana (gs_shutRoll_placement): Na Fachada; Posição Rolamento Veneziana (gs_shutRoll_iPlacement): 1; Tipo Caixa (gs_shutRoll_boxType): Rectangular; Tipo Caixa (gs_shutRoll_iBoxType): 1; Posição Grade (gs_shutRoll_railPos): Em Guarnição; Posição Grade (gs_shutRoll_iRailPos): 1; Mostrar Guarnição Atrás do Quebra-Sol (gs_shutRoll_showCasingBehind): no; Isolamento Atrás da Caixa (gs_shutRoll_cutWallBehind): no; Incluir Altura na Altura do Vão da Parede: no; Ângulo de Topo da Caixa: 10 deg; Largura Caixa Original (gs_shutRoll_boxDefaultSize): Largura Face de Vão; Largura Caixa Original (gs_shutRoll_iBoxDefaultSize): 1; Colocação Persianas (gs_shutLam_placement): Fixada na Fachada; Colocação Persianas (gs_shutLam_iPlacement): 1; Isolamento Atrás da Caixa (gs_shutLam_cutWallBehind): no; Caixa Aberta: yes; Trilho: yes; Posição Grade (gs_shutLam_railPos): Em Guarnição; Posição Grade (gs_shutLam_iRailPos): 1; Mostrar Guarnição Atrás do Quebra-Sol (gs_shutLam_showCasingBehind): no; Ângulo Rotação das Lamelas (gs_shutLam_rotation): 45 deg; Ângulo Rotação das Lamelas (gs_shutLam2_rotation): 45 deg; Arco de Alvenaria (bMasonryArch): no; Arco de Alvenaria (gs_masonry_arch_int): 2; Tipo de Arco de Alvenaria (gs_masonry_arch_structure): Arco de Reboco; Tipo de Arco de Alvenaria (gs_masonry_arch_structure_int): 1; Arco no Topo: yes; Nicho abaixo do Arco: yes; Ângulo de Plano do Arco: 75 deg; Superfícies dos Nichos Personalizados: no; Tipo de Requadro (gs_reveal_type_new): Requadro Reto - Borda; Tipo de Requadro (gs_reveal_type_int): 1; Tipo de Requadro Base (gs_reveal_type_bottom): Uniforme; Tipo de Requadro Base (gs_reveal_type_bottom_int): 1; Tipo de Requadro Exterior: Requadro Reto; Tipo de Requadro (gs_reveal_doubleOuterTypeInt): 0; Tipo de Requadro Interior: Requadro Reto; Tipo de Requadro (gs_reveal_doubleInnerTypeInt): 0; Profundidade Uniforme: yes; Ângulo Lado 2: 20 deg; Ângulo Lado: 20 deg; Ângulo do Topo: 20 deg; Ângulo da Base: 20 deg; Usar Componente de Acabamento: no; Auto Ligagem da Face Interna da Argamassa: yes; Ligar Face Interna da Argamassa: 0; Auto Ligagem da face Externa da Argamassa: yes; Ligar Face Externa da Argamassa: 0; Dimensionável em 2D: no; Mostrar em 3D: no; Tipo de Fechamento (gs_closure_type): Sem Fechamento; Tipo de Fechamento (gs_closure_type_int): 1; Dobrar Camada no Lado (gs_cavity_side): Ambas; Dobrar Camada no Lado (iCavityClosureSide): 1; No. de Camadas: 1; Numerar a partir de (gs_nTurnDir): Face externa; Numerar a partir de (iCavityClosureTurnDir): 1; Colocar Fechamento no Lado 2: yes; Colocar Fechamento no Lado 1: yes; Colocar Fechamento no Topo: no; Colocar Fechamento na Base: no; Colocar Fechamento para Camada: 1; Colocar Fechamento do Lado (gs_cc_dutch_ClosureToSide): 1; Fenda na Camada Externa: yes; Dobrar Camada para Encerram.: no; Inserir Camada de Isolamento: yes; Mostrar Camada de Isolamento: yes; Caneta de Contorno (gs_penJoint): Aberturas - Corte Não Estrutural; Tipo Linha Contorno (gs_ltJoint): 1; Tipo de Trama (gs_fillJoint): Isolamento 2; Caneta da Trama (gs_penJointFg): Geral - Geral; Caneta do Fundo da Trama (gs_penJointBg): Elementos 2D - Desenhos; Superfície Personalizada: no; Superfície: Madeira - Pinho Granulado Horizontal; Caneta de Contorno (gs_penPlug): Aberturas - Corte Não Estrutural; Tipo Linha Contorno (gs_ltPlug): 1; Tipo de Trama (gs_fillPlug): Isolamento 2; Caneta da Trama (gs_penPlugFg): Geral - Geral; Caneta do Fundo da Trama (gs_penPlugBg): Elementos 2D - Desenhos; Lado Ombreira Editado: 1; Lado Parede Editado: 1; Número de Camada Editado: 1; Camada que Dobra: no; Considerar Camada como Reboco: no; Espessura da Camada que Dobra: 1; Orientação Trama: 1; Linha Separa Camada que Dobra: no; Caneta Linha Separação: Geral - Geral; Último Lado Selecionado: no; Método de Fechamento Alterado Automaticamente: no; Conexão à Esquerda: no; Conexão à Direita: no; Conexão em Cima: no; Conexão em Baixo: no; Recorte na Parede: no; Tamanhos da Inserção na Parede (gs_parapet_sizes_st): Automático; Tamanhos da Inserção na Parede (iParapetSize): 1; Dimensões Autom. de Largura e Altura: yes; Inserção de Parede Embaixo a (gs_parapet_bottom_st): Piso Atual; Inserção de Parede Embaixo a (iParapetBottom): 1; Mostrar Parapeito Escondido: yes; Tipo Linha Peitoril Escondido: 1; Ângulo de Abertura Caixilho Principal (openingAngle_01): 9.93923e-16 deg; Ângulo de Abertura Caixilho Principal (openingAngle2_01): 0 deg; Ângulo de Abertura Caixilho Inferior (openingAngle_03): 0 deg; Ângulo de Abertura Caixilho Inferior (openingAngle2_03): 0 deg; Ângulo de Abertura Caixilho Travessa (openingAngle_02): 0 deg; Ângulo de Abertura Caixilho Travessa (openingAngle2_02): 0 deg; Ângulo Abertura 2D: 0 deg; Substituir OVM para Visual. Simbólica 2D: no; Tipo Linha Abertura: 1; Forma da Linha de Abertura (or_SwingType): Curva; Forma da Linha de Abertura (or_iSwingType): 1; Forma da Linha de Abertura (or_SlidingType): Nenhum; Forma da Linha de Abertura (or_iSlidingType): 0; Caneta de Linha de Abertura em 2D/3D (or_opLinePen): Aberturas - Geral; Caneta de Linha de Abertura em 2D/3D (or_iOpLinePen): 3; Substituir OVM para Projeções 3D: no; Mostrar Linha de Abertura: yes; Tipo Linha Lado da Abertura (or_opLineType3dIn): Linha Sólida; Tipo Linha Lado da Abertura (or_iOpLineType3dIn): 0; Tipo Linha Lado Oposto (or_opLineType3dOut): Linha Sólida; Tipo Linha Lado Oposto (or_iOpLineType3dOut): 0; Orientação da Linha (or_oplineStyle): Maçaneta; Orientação da Linha (or_iOplineStyle): 1; Caneta de Linha em Vista: Aberturas - Geral; Caneta da Linha em Corte: Aberturas - Moldura; Caneta de Linha em Corte em Ambos os Lados da Guarnição: Aberturas - Geral; Linha Contorno Parede (gs_wcont_line): Ambos Lados; Linha Contorno Parede (iWallContourLine): 4; Tipo de Linha Interior Contorno Parede: 1; Tipo de Linha Exterior Contorno Parede: 1; Linha Interna Tracejada de Projeção Parede: 4; Linha Externa Tracejada de Projeção Parede: 4; Caneta Linha Contorno Parede: Aberturas - Geral; Tramas Usadas: yes; Tipo Trama Batente: Trama Vazia; Caneta Trama Batente: Aberturas - Fundo de Trama; Caneta Fundo Trama Batente: Aberturas - Fundo de Trama; Tipo de Trama Caixilho: Ar (Vazio); Caneta da Trama Caixilho: Aberturas - Fundo de Trama; Caneta da Trama de Fundo Divisões Interiores: Fundos - Cor 1; Tipo de Trama de Não-Cortado: Trama Vazia; Caneta da Trama de Não-Cortado: Aberturas - Fundo de Trama; Caneta de Fundo da Trama Não-Cortado: Aberturas - Fundo de Trama; Tipo Trama Símbolo em Planta: Trama Vazia; Caneta Trama para Símb. em Planta: Aberturas - Fundo de Trama; Caneta Fundo para Simb. em Planta: Aberturas - Fundo de Trama; Caneta de Vista e 3D da Peitoril: Geral - Geral; Caneta de Contorno de Corte Peitoril: Aberturas - Corte Não Estrutural; Tipo de Trama Corte Peitoril: Trama Vazia; Caneta Trama do Parapeito em Corte: Aberturas - Fundo de Trama; Caneta Trama de Fundo do Parapeito em Corte: Aberturas - Fundo de Trama; Caneta de Contorno Isolamento Seção: Aberturas - Corte Não Estrutural; Tipo de Trama do Isolamento da Seção: Isolamento 2; Caneta Trama Isolamento Seção: Aberturas - Fundo de Trama; Caneta da Trama de Fundo Isolamento Seção: Aberturas - Fundo de Trama; Caneta de Vista e 3D do Peitoril Interno: Geral - Geral; Caneta de Contorno Seção Peitoril Interno: Geral - Geral; Tipo de Trama do Peitoril Interno em Corte: Trama Vazia; Caneta Trama do Peitoril Interno em Corte: Fundos - Cor 1; Caneta Trama de Fundo do Peitoril Interno em Corte: Fundos - Cor 1; Tipo de Trama de Guarnição Int.: Trama Vazia; Caneta de Trama de Guarnição Int: Aberturas - Fundo de Trama; Caneta de Fundo de Trama de Guarnição Int: Aberturas - Fundo de Trama; Tipo de Trama de Guarnição Ext: Trama Vazia; Caneta de Trama de Guarnição Ext: Fundos - Cor 1; Caneta de Fundo de Trama de Guarnição Ext: Fundos - Cor 1; Tipo de Trama de Seção do Arco: Trama Vazia; Caneta da Trama da Seção do Arco: Fundos - Cor 1; Caneta de Fundo de Trama de Seção do Arco: Fundos - Cor 1; Tipo de Trama do Corte do Perfil da Ventilação: Ar (Vazio); Caneta da Trama do Corte do Perfil da Ventilação: Fundos - Cor 1; Caneta do Fundo da Trama do Corte do Perfil da Ventilação: Fundos - Cor 1; Tipo de Linha de Símbolo Quebra-Sol: 1; Caneta da Linha em Corte do Quebra-Sol: Geral - Geral; 3D/Caneta das Linhas não Cortadas no Corte: Geral - Geral; Tipo da Trama de Corte Quebra-Sol (gs_sunShade_cutFillType): Trama Vazia; Tipo da Trama de Corte Quebra-Sol (gs_sunShade_cutFillPen): Geral - Geral; Caneta da Trama do Fundo Corte Quebra-Sol: Window Background; Tipo Trama Isolamento Quebra-Sol: Trama Vazia; Caneta da Trama Isolamento Quebra-Sol: Geral - Geral; Caneta do Fundo Isolamento Quebra-Sol: Window Background; Junção Elementos Batente: 2; Caneta Moldura: Aberturas - Geral; Caneta Caixilho: Aberturas - Geral; Caneta Vidro: Aberturas - Fundo de Trama; Caneta de Arco de Alvenaria: Paredes - Geral; Sombra: yes; Superfícies Uniformes Janela: yes; Batente Externo: Metal - Alumínio; Batente Interno: Metal - Alumínio; Caixilho Externo: Metal - Alumínio; Caixilho Interno: Metal - Alumínio; Persianas: Madeira - Pinho Granulado Horizontal; Vidro: Vidro - Simples; Grelha Externa: Metal - Alumínio; Grelha Interna: Metal - Alumínio; Painel Sólido Exterior: Metal - Alumínio; Painel Sólido Interior: Metal - Alumínio; Maçaneta: Metal - Aço Inoxidável; Superfícies Guarnição Uniformes: no; Interior Guarnição: Metal - Alumínio; Exterior Guarnição: Metal - Alumínio; Perfil de Ventilação: Metal - Alumínio; Painel Veneziana: Madeira - Pinho Granulado Horizontal; Moldura Painel Veneziana: Madeira - Pinho Granulado Horizontal; Caixa do Rolamento Veneziana: Metal - Aço Inoxidável; Lâminas Rolamento Veneziana: Pintura - Branco Titânio; Barras Rolamento Veneziana: Pintura - Branco Titânio; Caixa Persianas: Metal - Aço Inoxidável; Segmento Persianas: Pintura - Branco Titânio; Trilho Deslizante Veneziana: Metal - Aço Inoxidável; Soleira/Peitoril (gs_sill_mat): Pedra - Granito Cinza; Argamassa do Peitoril em Tijolo: Estuque - Branco Áspera; Peitoril Interno (gs_board_mat): Pedra - Granito Cinza; Arco de Alvenaria em Tijolo: Tijolo - Aparelho ao Comprido; Argamassa do Arco de Alvenaria: Estuque - Branco Áspera; Fecho Arco de Alvenaria: Pedra - Arenito 01; Nincho: Pintura - Óxido de Chumbo Amarelo; Superfície de Pilar de Canto: Metal - Alumínio; Direção da Abertura: 0; Visualizar como Travessa: no; Caneta Linha Fim Parede: Geral - Geral; Tipo de Linha Fim de Parede: 4; Profundidade Travessa em Símbolo: no; Tipo de Linha do Símbolo da Profundidade Travessa: 4; Caneta do Símbolo da Profundidade Travessa: Texto - Geral; Janela pertence à Zona dentro da qual abre: no; Custo: 0; Área Total Envidraçada (gs_list_glassarea_tmp): 0; Substituir Área Envidraçada: yes; Área Total Envidraçada (gs_list_glassarea): 0; Perimetro Total Vidro: 0; Desempenho Ar Livre (mm2/l/m): 0; Tipo de Grupo (FM_Type): Objetos padrão; Tipo de Grupo (iFMType): 1; Peso Objeto: 0; Unidade Peso Objeto: kg; Definição de Orientação Janela: 0; Operação IFC (ifc_optypestr): Simples; Operação IFC (ifc_optype): 1; Ângulo de Abertura Veneziana: 180 deg; Estilo Linha de Abertura: 2
INFORMAÇÕES DO PRODUTO - Data de Aquisição: DD/MM/YYYY
FABRICAÇÃO - Data de Fabricação: DD/MM/YYYY; Site do Produto: www.graphisoft.com
GARANTIA - Ínicio da Garantia: DD/MM/YYYY; Fim da Garantia: DD/MM/YYYY
ABERTURAS - Tipo de Abertura: Basculante; Material: Alumínio; Vidro
EXPRESSÕES DE TEXTO (Expressão) - ID Dinâmico por Classificação: Janela -J13
AC_Pset_RenovationAndPhasing - Renovation Status: Existing
BaseQuantities - GrossArea: 0.5192 m2; Height: 590 mm; Width: 880 mm; Perimeter: 2940 mm; Area: 0.5192 m2; Volume: 0.015714 m3; Depth: 140 mm; NetVolume: 0.015714 m3
ArchiCADQuantities - W/D Opening Opening Volume: 0.072688 m3; W/D Opening Nominal Volume: 0.072688 m3; W/D Opening Surface Area: 2.64471 m2; W/D Opening Nominal Surface Area: 0.5192 m2; W/D Opening Width on the Reveal Side: 880 mm; W/D Opening Height on the Reveal Side: 590 mm; W/D Opening Width on the Side Opposite to the Reveal Side: 880 mm; W/D Opening Height on the Side Opposite to the Reveal Side: 590 mm; W/D Opening Surface Area on the Reveal Side: 0.5192 m2; W/D Opening Surface Area on the Side Opposite to the Reveal Side: 0.5192 m2; Nominal W/D Opening Width on the Reveal Side: 880 mm; Nominal W/D Opening Height on the Reveal Side: 590 mm; Nominal W/D Opening Width on the Side Opposite to the Reveal Side: 880 mm; Nominal W/D Opening Height on the Side Opposite to the Reveal Side: 590 mm; Nominal W/D Opening Surface Area on the Reveal Side: 0.5192 m2; Nominal W/D Opening Surface Area on the Side Opposite to the Reveal Side: 0.5192 m2; Sill/Header Value: 1630 mm; W/D Nominal Sill Height: 1630 mm; W/D Sill Height on the Reveal Side: 1630 mm; W/D Sill Height on the Side Opposite to the Reveal Side: 1630 mm; W/D Nominal Head Height: 2220 mm; W/D Head Height on the Reveal Side: 2220 mm; W/D Head Height on the Side Opposite to the Reveal Side: 2220 mm; Wall Thickness: 140 mm; Frame Thickness: 50 mm; Height: 590 mm; Volume (Net): 0.015714 m3; Width: 880 mm; Elevation to Project Zero: 1630 mm; Elevation to 1º Nível de Referência: 1630 mm; Elevation to 2º Nível de Referência: 1630 mm; Elevation to Sea Level: 729850 mm; Elevation to Linked/Home Story: 1630 mm; Home Offset: 1630 mm; Surface Area: 2.64471 m2; Top Elevation To First Reference Level: 2235 mm; Top Elevation To Home Story: 2235 mm; Top Elevation To Project Zero: 2235 mm; Top Elevation To Sea Level: 730455 mm; Top Elevation To Second Reference Level: 2235 mm; Bottom Elevation To First Reference Level: 1615 mm; Bottom Elevation To Home Story: 1615 mm; Bottom Elevation To Project Zero: 1615 mm; Bottom Elevation To Sea Level: 729835 mm; Bottom Elevation To Second Reference Level: 1615 mm; Bottom Surface Area (Net): 2.64471 m2
AC_Equantity_Janela_26 - Largura: 880 mm; Altura: 590 mm; Dimensão Z: 1000 mm; Nível da Base: 1000 mm; Nível do Topo: 0 mm; Altura Peitoril ao Piso Atual: 1630 mm; Abertura para o Núcleo da Parede: 0 mm; Nova Largura Direita da Trama de Parede: 150 mm; Nova Largura Esquerda da Trama de Parede: 150 mm; Espessura Parede Ligação: 0 mm; Espessura Parede 2 Conectada: 140 mm; Espessura Parede 1 Conectada: 140 mm; Largura Pilar de Canto: 0 mm; Espessura Pilar Canto: 0 mm; Projeção Pilar de Canto: 0 mm; Tolerância Máxima: 100 mm; Tolerância: 0 mm; Tolerância Esquerda: 0 mm; Tolerância Direita: 0 mm; Tolerância Superior: 0 mm; Tolerância Inferior: 0 mm; Largura de Vão: 880 mm; Altura de Vão: 590 mm; Largura Face de Vão: 880 mm; Altura Face de Vão: 590 mm; Largura Unidade: 880 mm; Altura Unidade: 590 mm; Largura Painel Lado: 0 mm; Largura Painel Meio: 440 mm; Espessura Batente: 50 mm; Largura Batente: 35 mm; Largura Batente Lado 2: 47 mm; Largura Batente Cimo: 47 mm; Largura Batente Base: 47 mm; Profundidade Rebaixo: 20 mm; Largura Rebaixo: 20 mm; Largura Divisão Superior: 100 mm; Altura Divisões Sup. Horiz.: 453 mm; Largura Divisão Inferior: 100 mm; Altura Divisões Inf. Horiz: 330 mm; Largura Montante Lado 1: 100 mm; Largura Montante Lado 2: 100 mm; Altura Divisão Horizontal Caixilho Principal: 355 mm; Altura Divisão Horizontal Caixilho Inferior: 900 mm; Altura Divisão Horizontal Caixilho Travessa: 900 mm; Espessura Estrutura Caixilho: 20 mm; Largura Caixilho: 50 mm; Largura Grelha: 20 mm; Espessura Grelha: 25 mm; Espessura Vidro: 20 mm; Espessura Venezianas: 10 mm; Largura Venezianas: 50 mm; Sobred. Abertura Esquerda: 0 mm; Sobred. Direita Abertura: 0 mm; Sobred. Topo Abertura: 0 mm; Sobred. Base Abertura: 0 mm; Largura Arquitrave Principal: 20 mm; Largura Lado 1 (gs_tw_right_out): 100 mm; Largura Lado 2 (gs_tw_left_out): 100 mm; Largura Topo (gs_tw_top_out): 100 mm; Largura Inferior (gs_tw_bottom_out): 100 mm; Espessura de Parede (gs_trim_thk_out): 25 mm; Espessura na Abertura da Parede (gs_trim_width_out): 25 mm; Paralelas (gs_trim_offs_out): 0 mm; Bordo (gs_trim_jambext_nosing_out): 50 mm; Saliência Superior (gs_trimov_top_left_out): 0 mm; Saliência Superior (gs_trimov_top_right_out): 0 mm; Ressalto Inferior (gs_trimov_bot_left_out): 0 mm; Ressalto Inferior (gs_trimov_bot_right_out): 0 mm; Ressalto Inferior (casingOverhangBottomSideOut): 50 mm; Largura Lado 1 (gs_tw_right_in): 40 mm; Largura Lado 2 (gs_tw_left_in): 100 mm; Largura Topo (gs_tw_top_in): 100 mm; Largura Inferior (gs_tw_bottom_in): 100 mm; Espessura de Parede (gs_trim_thk_in): 25 mm; Espessura na Abertura da Parede (gs_trim_width_in): 25 mm; Paralelas (gs_trim_offs_in): 0 mm; Bordo (gs_trim_jambext_nosing_in): 50 mm; Saliência Superior (gs_trimov_top_left_in): 0 mm; Saliência Superior (gs_trimov_top_right_in): 0 mm; Ressalto Inferior (gs_trimov_bot_left_in): 0 mm; Ressalto Inferior (gs_trimov_bot_right_in): 0 mm; Largura Peitoril: 60 mm; Largura Topo Parapeito: 10 mm; Altura Topo Peitoril: 10 mm; Espessura Peitoril: 30 mm; Espessura Lateral da Frente Peitoril: 15 mm; Elevação Peitoril: 5 mm; Recobrimento Goteira Peitoril: 20 mm; Largura Goteira Peitoril: 30 mm; Testeira Peitoril: 25 mm; Avanço do Parapeito Esquerda: 0 mm; Avanço do Parapeito Direita: 0 mm; Inclinação do Parapeito: 35 mm; Inclin. Peitoril da Parede: 0 mm; Profund. Vão Posterior (gs_sill_holeDepthBehind): 0 mm; Espessura do Tijolo (gs_brick_sill_br_thk): 65 mm; Espessura de Argamassa (gs_brick_sill_mort_thk): 15 mm; Largura Peitoril Int.: 115 mm; Espessura Peitoril Int.: 25 mm; Peitoril Int. Arredondado: 25 mm; Saliência Esq. Peitoril Int.: 0 mm; Saliência Dir. Peitoril Int.: 0 mm; Inclinação do Parapeito Int.: 0 mm; Altura Perfil: 65 mm; Espessura Perfil: 110 mm; Altura Painel: 1500 mm; Afast. Interior: 20 mm; Profund. Fechamento: 0 mm; Largura Batente Extra: 40 mm; Espess. Batente Extra: 30 mm; Largura Barra:: 30 mm; Comprim. Vara Suspensa: 20 mm; Raio Vara Suspensa: 5 mm; Distância Painel: 6 mm; Saliência Exterior: 0 mm; Largura Painel Interior: 120 mm; Comprim. Abertura 3D: 1500 mm; Comprim. Fechado 3D: 0 mm; Comprimento 1 Abertura 3D (gs_shutter_opLength_1): 560 mm; Comprimento 1 Abertura 3D (gs_shutter_opLength_2): 140 mm; Altura Abertura 3D: 1500 mm; Altura Fechado 3D: 0 mm; Espessura Painel: 50 mm; Largura Estrutura Painel: 50 mm; Largura Moldura Inferior: 50 mm; Largura Painel: 0 mm; Espess. de Enchimento de Painel: 10 mm; Espessura da Veneziana: 10 mm; Largura Grelha Ventilação: 40 mm; Largura Divisor Moldura Horiz.: 50 mm; Largura de Divisor Moldura Vert.: 50 mm; Raio do Vão: 10 mm; Largura Bordo Vertical: 100 mm; Largura Estrutura Z: 50 mm; Espessura Estrutura Z: 25 mm; Espess. Placas Verticais: 25 mm; Espess. Placas Horizontais: 25 mm; Largura Aprox. Placas Verticais: 80 mm; Largura Aprox. Placas Horizontais: 115 mm; Altura Caixa (gs_shutRoll_boxHeight): 200 mm; Profund. Caixa (gs_shutRoll_boxWidth): 150 mm; Afast. Caixa Esq.: 0 mm; Afast. Caixa Dir.: 0 mm; Profund. Anteparos: 72.5 mm; Distância da Parede (gs_shutRoll_distFromWall): 0 mm; Distância da Padieira (gs_shutRoll_distFromHead): 0 mm; Largura da Ripa: 50 mm; Altura Caixa (gs_shutLam_boxHeight): 200 mm; Profund. Caixa (gs_shutLam_boxWidth): 150 mm; Largura Capa: 0 mm; Distância da Parede (gs_shutLam_distFromWall): 0 mm; Distância da Padieira (gs_shutLam_distFromHead): 0 mm; Largura Segmento (gs_shutLam_segmentWidth): 60 mm; Altura Caixa (gs_shutLam2_boxHeight): 60 mm; Largura Caixa: 60 mm; Distância da Janela: 60 mm; Distância da Padieira (gs_shutLam2_distFromHead): 60 mm; Altura do Eixo da Caixa da Padieira: 0 mm; Largura Segmento (gs_shutLam2_segmentWidth): 60 mm; Distância entre Arco e Janela: 0 mm; Avanço à Esquerda do Arco de Alvenaria: 0 mm; Avanço à Direita do Arco de Alvenaria: 0 mm; Espelho do Arco de Alvenaria: 30 mm; Projeção do Arco de Alvenaria: 0 mm; Altura do Arco de Alvenaria: 250 mm; Profundidade do Arco de Alvenaria: 120 mm; Profund. Vão Posterior (gs_masonry_arch_rearHoleDepth): 0 mm; Espessura do Tijolo (gs_masonry_arch_brick_thk): 65 mm; Espessura de Argamassa (gs_masonry_arch_mort_thk): 10 mm; Largura Fecho: 100 mm; Sobredimensão Fecho: 0 mm; Projeção Fecho: 10 mm; Profund. Face de Vão (gs_wido_sill): 0 mm; Profund. Face de Vão (AC_wido_sill): 0 mm; Profund. Ombreira Lado 2: 60 mm; Profund. Ombreira: 60 mm; Profund. Ombreira Interior Lado 2 (gs_reveal_splayed_innerLeft): 60 mm; Profund. Ombreira Interior (gs_reveal_splayed_innerRight): 60 mm; Profund. Ombreira Interior Lado 2 (gs_reveal_double_innerLeft): 60 mm; Profund. Ombreira Interior (gs_reveal_double_innerRight): 60 mm; Profund. Batente Cima: 60 mm; Profund. Batente Peitoril: 60 mm; Profundidade Padieira Interior (gs_reveal_splayed_innerTop): 60 mm; Profundidade Peitoril Interior (gs_reveal_splayed_innerBottom): 60 mm; Profundidade Padieira Interior (gs_reveal_double_innerTop): 60 mm; Profundidade Peitoril Interior (gs_reveal_double_innerBottom): 0 mm; Profund. Batente Exterior: 80 mm; Limite Espess. Reboco: 40 mm; Distância de Camada do Encerram.: 0 mm; Largura do Fecho: 38 mm; Espessura do Fecho: 100 mm; Espessura da Camada: 25 mm; Espessura do Perfil: 75 mm; Espessura Personal.: 15 mm; Saliência Camada para Espess. Batente: 0 mm; Profundidade do Recorte: 50 mm; Largura de Parapeito: 1000 mm; Avanço Lateral 1: 0 mm; Avanço Lateral 2: 0 mm; Altura Parapeito: 900 mm; Ressalto Inferior (gs_parapet_botelev): 0 mm; Distância Abertura 1 Caixilho Principal: 0 mm; Distância Abertura 2 Caixilho Principal: 0 mm; Distância Abertura 1 Caixilho Inferior: 0 mm; Distância Abertura 2 Caixilho Inferior: 0 mm; Distância Abertura 1 Bandeira Caixilho: 0 mm; Distância Abertura 2 Bandeira Caixilho: 0 mm; Comprimento Abertura em 2D: 0 mm; Sobred. Abertura Esq. AC: 0 mm; Sobred. Abertura Dir. AC: 0 mm; Sobred. Padieira AC: 0 mm; Sobred. Abertura Base AC: 0 mm
Component Quantities - Component, Component Volume (Net): 0.015714 m3; Component, Component Volume (Gross): 0.015714 m3
Name | In | Orientation | Hotlink and Element ID | Colliding Zones = Related Zone Name = From Zone = To Zone | Related Zone Number = From Zone Number = To Zone Number | Hotlink Master ID | Localização do Produto no Projeto | ID de Aberturas com Master ID
Apt 03 - J13 | 03 | R | Apt 03 - J13 | Apartamento 03 | 03 | Apt 03 - | Projeto: Jardim EditeLocal: Piso: Pavimento tipo Cômodo: Apartamento 03 | Apt 03 - 03J13
Apt 02 - J13 | 02 | L | Apt 02 - J13 | Apartamento 02 | 02 | Apt 02 - | Projeto: Jardim EditeLocal: Piso: Pavimento tipo Cômodo: Apartamento 02 | Apt 02 - 02J13

# IfcWindow: Janela 26, Apt 01 - J08
In: 01
Type - OperationType: TRIPLE_PANEL_BOTTOM; ParameterTakesPrecedence: no; Sizeable: no
Type - Window Lining Properties - LiningDepth: 50 mm; LiningThickness: 35 mm; TransomThickness: 35 mm; MullionThickness: 50 mm; FirstTransomOffset: 0.559459; FirstMullionOffset: 0.5
Type - Window Panel Properties - Panel 1 - OperationType: SLIDINGHORIZONTAL; PanelPosition: LEFT; FrameDepth: 20 mm; FrameThickness: 50 mm
Type - Window Panel Properties - Panel 2 - OperationType: SLIDINGHORIZONTAL; PanelPosition: RIGHT; FrameDepth: 20 mm; FrameThickness: 50 mm
Type - Window Panel Properties - Panel 3 - OperationType: FIXEDCASEMENT; PanelPosition: BOTTOM
Description: Janela-dupla_fixa-generico-generico-aluminio-137cm-925cm; OverallHeight: 925 mm; OverallWidth: 1370 mm; Classification: Janela (Classificação ARCHICAD); 3E 20 04 02 02 Janela de correr (NBR 15965-5 3E)
Pset_WindowCommon - ThermalTransmittance: 0; IsExternal: yes
ArchiCADProperties - Reveal Dimensions: 1,37×0,93; Wallhole Dimensions: 1,37×0,93; Unit Dimensions: 1,37×0,93; Nominal W x H Size: 1,37×0,93; Nominal W x H x T Size: 1,37×0,93×0,14; Wall Structure: Tijolo - Estrutural; Orientation: L; Opening Library Part Name: Janela 26; Opening Side Fill Index: Trama Vazia; Element ID: J08; Hotlink and Element ID: Apt 01 - J08; Layer: A--PRDE-VEDS-E-; Library Part Name: Janela 26; Building Material / Composite / Profile / Fill: Trama Vazia; Fill Type: Trama Vazia; Colliding Zones: Apartamento 01; Related Zone Name: Apartamento 01; Related Zone Number: 01; Locked: yes; Home Story Name: Pavimento tipo; Home Story Number: 0; Element Type: Window; Parent ID: Parede 24; Surfaces (All): Vidro - Simples; Metal - Alumínio; Hotlink Master ID: Apt 01 -; From Zone: Apartamento 01; From Zone Number: 01; To Zone: Apartamento 01; To Zone Number: 01; Position: Exterior; Show On Renovation Filter: All Relevant Filters; Structural Function: Non-Load-Bearing Element; Renovation Status: Existing
AC_Pset_Janela_26 - Contornos Parede (0-Nenhum,1-Completo,2-Lado,3-Comprimento): 0; Pontos-Quentes 0-Nenhum,1-2D,2-3D,3-Todos: 3; Opção de Visualização em Planta: 3; Ângulo de Posição da Abertura: 0 deg; Furo tem Superfície Lateral Parede: yes; Furos em Divisão de Superfícies são Curvos em Paredes Curvas: no; Mostrar Pontos-Quentes 2D em 3D: yes; Tipo de Parede: 1; Tipo de Direção de Parede: 0; Posição de Ancoragem da Abertura: 1; Função de correção de erros de Janela de canto: no; Tipo de Posicionamento (1=CW,0=W): no; Corda: no; Demolição / Nova Construção: 1; Novo Tipo de Trama de Parede: Bloco; Nova Caneta de Trama de Parede: Geral - Geral; Nova Caneta de Fundo de Trama de Parede: Fundos - Cor 1; Mostrar nova construção na Parede: no; Tipo de linha de demolição: 4; Mostrar parâmetro Demolição / Novo: no; Função Janela de Canto: yes; Ângulo de Canto: 90 deg; Espess. Dif. Parede Conexão: no; Pilar de Canto: no; Canto 2: no; Ângulo do Canto 2: 90 deg; Dif. Conexões de Espessura Parede 2: no; Canto 1: no; Ângulo do Canto 1: 90 deg; Dif. Conexões de Espessura Parede 1: no; Tipo de Conexão 1 do Canto: 1; Tipo de Conexão 2 do Canto: 1; Inteiramente Editável: yes; 2D: 1; Mostrar Face de Vão em Símbolo: 2; 3D: 8; Tamanho Nominal: 0; Definir Tamanho de Vão como Tamanho Nominal: yes; Definir Tamanho de Reentrância como Tamanho Nominal: no; Definir Tamanho de Unidade como Tamanho Nominal: no; Transferir Tamanho Nominal Atual para Seleção: no; Painéis Horizontais: 1; Largura Uniforme Batente: yes; Bandeira Superior: yes; Bandeira Superior Dividida: no; Bandeira Inferior: no; Bandeira Inferior Dividida: no; Painéis Verticais: 3; Caixilhos Uniformes: no; Direção do Vidro Fixo (FixGlassDir): Pela Direção da Abertura; Direção do Vidro Fixo (FixGlassDir_m): 1; Tipo Abertura Caixilho Principal: Vidro Fixo; Tipo Abertura (gs_optype_m_01): 1; Tipo Abertura (gs_optype_m_03): 1; Tipo Abertura Caixilho Travessa: Dupla de Correr Simétrica; Tipo Abertura (gs_optype_m_02): 24; Tipo Caixilho (MullionStyle_00): Sem Grelha; Tipo Caixilho (iMullionStyle_00): 1; Tipo Caixilho Caixilho Principal: Sem Grelha; Tipo Caixilho (iMullionStyle_01): 1; Tipo Caixilho (iMullionStyle_03): 1; Tipo Caixilho Caixilho Travessa: Sem Grelha; Tipo Caixilho (iMullionStyle_02): 1; Painel Person. Espelhado (gs_bMirr_cust_panel_01): no; Painel Person. Espelhado (gs_bMirr_cust_panel2_01): no; Painel Person. Espelhado (gs_bMirr_cust_panel_03): no; Painel Person. Espelhado (gs_bMirr_cust_panel2_03): no; Painel Person. Espelhado (gs_bMirr_cust_panel_02): no; Painel Person. Espelhado (gs_bMirr_cust_panel2_02): no; Editar Ponto-quente Grelha: yes; Posição Grelha (MullionPosition): Por tudo; Posição Grelha (iMullionPosition): 3; Nº Paineis Verticais Caixilho Principal: 3; Nº Paineis Horizontais Caixilho Principal: 4; Nº Paineis Verticais 2 Caixilho Principal: 3; Nº Paineis Horizontais 2 Caixilho Principal: 4; Nº Paineis Verticais Caixilho Inferior: 1; Nº Paineis Horizontais Caixilho Inferior: 4; Nº Paineis Verticais 2 Caixilho Inferior: 1; Nº Paineis Horizontais 2 Caixilho Inferior 2: 4; Nº Paineis Verticais Caixilho Travessa: 1; Nº Paineis Horizontais Caixilho Travessa: 4; Nº Paineis Verticais 2 Caixilho Travessa: 1; Nº Paineis Horizontais 2 Caixilho Travessa: 4; Estilo Venezianas (iLouverStyle): 1; Ângulo de Abertura de Lanternins: 0 deg; Maçaneta Janela: no; Tipo Maçaneta Janela (gs_handle_type_win): Estilo 1; Tipo Maçaneta Janela (gs_handle_type_win_m): 1; Guarnição Externa: no; Tipo Guarnição Externa (gs_trimtype_out): Simples; Tipo Guarnição Externa (gs_trimtype_out_int): 1; Tipo de Travessa Guarnição Externa: 1; Arquitrave Principal: yes; Tipo Arquitrave Principal: 1; Guarnição Externa Inferior: no; Guarnição/Alizar na Superfície Externa da Parede: yes; Larguras Uniformes da Guarnição (gs_trim_outside_uniform): no; Guarnição Interna: yes; Tipo Guarnição Interna (gs_trimtype_in): Simples; Tipo Guarnição Interna (gs_trimtype_in_int): 1; Guarnição/Alizar na Superfície Interna da Parede: yes; Larguras Uniformes da Guarnição (gs_trim_inside_uniform): yes; Soleira/Peitoril (gs_sill_outside): no; Sobredim. Peitoril: no; Tipo de Parapeito Exterior: 1; Ângulo Peitoril: 3 deg; Parapeito Curvo em Paredes Curvas: yes; Isolamento abaixo do Peitoril: yes; Usar Camada Isolamento de Parede: no; Nível Detalhe 3D Peitoril Tijolo: 1; Peitoril Interno (gs_board_inside): no; Ângulo Peitoril Int.: 0 deg; Peitoril Int. Curvado em Paredes Curvas: yes; Peitoril Int. em Paredes Poligonais: 1; Ventilação Natural: no; Tipo Ventilação Natural: 2; Caixilho Principal: yes; Caixilho Inferior: no; Caixilho Bandeira: no; Quebra-Sol: no; Tipo Quebra-Sol: 1; Tipos de Quebra-Sol Ativados: 126; Número de Paineis: 2; Número de Paineis 2: 1; Posição Painel (gs_shutter_panelPos): Simétrico; Posição Painel (gs_shutter_iPanelPos): 1; Altura Automática Veneziana: yes; Batente Extra: no; Tipo Cobertura (gs_slidingShutter_cover): Perfil-Z; Tipo Cobertura (gs_slidingShutter_iCover): 1; Direção de Empilham. (gs_foldingShutter_stacking): Dentro; Direção de Empilham. (gs_foldingShutter_iStacking): 1; Abrir em 3D: yes; Ângulo de abertura 3D: 180 deg; Mostrar Símbolo 2D: yes; Mostrar Linhas de Abertura no Símbolo: no; Tipo Painel (gs_shutPanel_type): Estilo 1; Tipo Painel (gs_shutPanel_iType): 1; Largura Base Batente Diferente: no; Largura Automática Veneziana: yes; Ângulo Grelha Ventilação: 30 deg; Nº Vãos Horiz.: 5; Nº Vãos Vert.: 8; Posição Rolamento Veneziana (gs_shutRoll_placement): Na Fachada; Posição Rolamento Veneziana (gs_shutRoll_iPlacement): 1; Tipo Caixa (gs_shutRoll_boxType): Rectangular; Tipo Caixa (gs_shutRoll_iBoxType): 1; Posição Grade (gs_shutRoll_railPos): Em Guarnição; Posição Grade (gs_shutRoll_iRailPos): 1; Mostrar Guarnição Atrás do Quebra-Sol (gs_shutRoll_showCasingBehind): no; Isolamento Atrás da Caixa (gs_shutRoll_cutWallBehind): no; Incluir Altura na Altura do Vão da Parede: no; Ângulo de Topo da Caixa: 10 deg; Largura Caixa Original (gs_shutRoll_boxDefaultSize): Largura Face de Vão; Largura Caixa Original (gs_shutRoll_iBoxDefaultSize): 1; Colocação Persianas (gs_shutLam_placement): Fixada na Fachada; Colocação Persianas (gs_shutLam_iPlacement): 1; Isolamento Atrás da Caixa (gs_shutLam_cutWallBehind): no; Caixa Aberta: yes; Trilho: yes; Posição Grade (gs_shutLam_railPos): Em Guarnição; Posição Grade (gs_shutLam_iRailPos): 1; Mostrar Guarnição Atrás do Quebra-Sol (gs_shutLam_showCasingBehind): no; Ângulo Rotação das Lamelas (gs_shutLam_rotation): 45 deg; Ângulo Rotação das Lamelas (gs_shutLam2_rotation): 45 deg; Arco de Alvenaria (bMasonryArch): no; Arco de Alvenaria (gs_masonry_arch_int): 2; Tipo de Arco de Alvenaria (gs_masonry_arch_structure): Arco de Reboco; Tipo de Arco de Alvenaria (gs_masonry_arch_structure_int): 1; Arco no Topo: yes; Nicho abaixo do Arco: yes; Ângulo de Plano do Arco: 75 deg; Superfícies dos Nichos Personalizados: no; Tipo de Requadro (gs_reveal_type_new): Requadro Reto; Tipo de Requadro (gs_reveal_type_int): 2; Tipo de Requadro Base (gs_reveal_type_bottom): Uniforme; Tipo de Requadro Base (gs_reveal_type_bottom_int): 1; Tipo de Requadro Exterior: Requadro Reto; Tipo de Requadro (gs_reveal_doubleOuterTypeInt): 0; Tipo de Requadro Interior: Requadro Reto; Tipo de Requadro (gs_reveal_doubleInnerTypeInt): 0; Profundidade Uniforme: yes; Ângulo Lado 2: 20 deg; Ângulo Lado: 20 deg; Ângulo do Topo: 20 deg; Ângulo da Base: 20 deg; Usar Componente de Acabamento: no; Auto Ligagem da Face Interna da Argamassa: yes; Ligar Face Interna da Argamassa: 0; Auto Ligagem da face Externa da Argamassa: yes; Ligar Face Externa da Argamassa: 0; Dimensionável em 2D: no; Mostrar em 3D: no; Tipo de Fechamento (gs_closure_type): Sem Fechamento; Tipo de Fechamento (gs_closure_type_int): 1; Dobrar Camada no Lado (gs_cavity_side): Ambas; Dobrar Camada no Lado (iCavityClosureSide): 1; No. de Camadas: 1; Numerar a partir de (gs_nTurnDir): Face externa; Numerar a partir de (iCavityClosureTurnDir): 1; Colocar Fechamento no Lado 2: yes; Colocar Fechamento no Lado 1: yes; Colocar Fechamento no Topo: no; Colocar Fechamento na Base: no; Colocar Fechamento para Camada: 1; Colocar Fechamento do Lado (gs_cc_dutch_ClosureToSide): 1; Fenda na Camada Externa: yes; Dobrar Camada para Encerram.: no; Inserir Camada de Isolamento: yes; Mostrar Camada de Isolamento: yes; Caneta de Contorno (gs_penJoint): Aberturas - Corte Não Estrutural; Tipo Linha Contorno (gs_ltJoint): 1; Tipo de Trama (gs_fillJoint): Isolamento 2; Caneta da Trama (gs_penJointFg): Geral - Geral; Caneta do Fundo da Trama (gs_penJointBg): Elementos 2D - Desenhos; Superfície Personalizada: no; Superfície: Madeira - Pinho Granulado Horizontal; Caneta de Contorno (gs_penPlug): Aberturas - Corte Não Estrutural; Tipo Linha Contorno (gs_ltPlug): 1; Tipo de Trama (gs_fillPlug): Isolamento 2; Caneta da Trama (gs_penPlugFg): Geral - Geral; Caneta do Fundo da Trama (gs_penPlugBg): Elementos 2D - Desenhos; Lado Ombreira Editado: 1; Lado Parede Editado: 1; Número de Camada Editado: 1; Camada que Dobra: no; Considerar Camada como Reboco: no; Espessura da Camada que Dobra: 1; Orientação Trama: 1; Linha Separa Camada que Dobra: no; Caneta Linha Separação: Geral - Geral; Último Lado Selecionado: no; Método de Fechamento Alterado Automaticamente: no; Conexão à Esquerda: no; Conexão à Direita: no; Conexão em Cima: no; Conexão em Baixo: no; Recorte na Parede: no; Tamanhos da Inserção na Parede (gs_parapet_sizes_st): Automático; Tamanhos da Inserção na Parede (iParapetSize): 1; Dimensões Autom. de Largura e Altura: yes; Inserção de Parede Embaixo a (gs_parapet_bottom_st): Piso Atual; Inserção de Parede Embaixo a (iParapetBottom): 1; Mostrar Parapeito Escondido: yes; Tipo Linha Peitoril Escondido: 1; Ângulo de Abertura Caixilho Principal (openingAngle_01): 0 deg; Ângulo de Abertura Caixilho Principal (openingAngle2_01): 0 deg; Ângulo de Abertura Caixilho Inferior (openingAngle_03): 0 deg; Ângulo de Abertura Caixilho Inferior (openingAngle2_03): 0 deg; Ângulo de Abertura Caixilho Travessa (openingAngle_02): 0 deg; Ângulo de Abertura Caixilho Travessa (openingAngle2_02): 0 deg; Ângulo Abertura 2D: 0 deg; Substituir OVM para Visual. Simbólica 2D: no; Tipo Linha Abertura: 1; Forma da Linha de Abertura (or_SwingType): Curva; Forma da Linha de Abertura (or_iSwingType): 1; Forma da Linha de Abertura (or_SlidingType): Nenhum; Forma da Linha de Abertura (or_iSlidingType): 0; Caneta de Linha de Abertura em 2D/3D (or_opLinePen): Aberturas - Geral; Caneta de Linha de Abertura em 2D/3D (or_iOpLinePen): 3; Substituir OVM para Projeções 3D: no; Mostrar Linha de Abertura: yes; Tipo Linha Lado da Abertura (or_opLineType3dIn): Linha Sólida; Tipo Linha Lado da Abertura (or_iOpLineType3dIn): 0; Tipo Linha Lado Oposto (or_opLineType3dOut): Linha Sólida; Tipo Linha Lado Oposto (or_iOpLineType3dOut): 0; Orientação da Linha (or_oplineStyle): Maçaneta; Orientação da Linha (or_iOplineStyle): 1; Caneta de Linha em Vista: Aberturas - Geral; Caneta da Linha em Corte: Aberturas - Moldura; Caneta de Linha em Corte em Ambos os Lados da Guarnição: Aberturas - Geral; Linha Contorno Parede (gs_wcont_line): Ambos Lados; Linha Contorno Parede (iWallContourLine): 4; Tipo de Linha Interior Contorno Parede: 1; Tipo de Linha Exterior Contorno Parede: 1; Linha Interna Tracejada de Projeção Parede: 4; Linha Externa Tracejada de Projeção Parede: 4; Caneta Linha Contorno Parede: Aberturas - Geral; Tramas Usadas: yes; Tipo Trama Batente: Trama Vazia; Caneta Trama Batente: Aberturas - Fundo de Trama; Caneta Fundo Trama Batente: Aberturas - Fundo de Trama; Tipo de Trama Caixilho: Ar (Vazio); Caneta da Trama Caixilho: Aberturas - Fundo de Trama; Caneta da Trama de Fundo Divisões Interiores: Fundos - Cor 1; Tipo de Trama de Não-Cortado: Trama Vazia; Caneta da Trama de Não-Cortado: Aberturas - Fundo de Trama; Caneta de Fundo da Trama Não-Cortado: Aberturas - Fundo de Trama; Tipo Trama Símbolo em Planta: Trama Vazia; Caneta Trama para Símb. em Planta: Aberturas - Fundo de Trama; Caneta Fundo para Simb. em Planta: Aberturas - Fundo de Trama; Caneta de Vista e 3D da Peitoril: Geral - Geral; Caneta de Contorno de Corte Peitoril: Aberturas - Corte Não Estrutural; Tipo de Trama Corte Peitoril: Trama Vazia; Caneta Trama do Parapeito em Corte: Aberturas - Fundo de Trama; Caneta Trama de Fundo do Parapeito em Corte: Aberturas - Fundo de Trama; Caneta de Contorno Isolamento Seção: Aberturas - Corte Não Estrutural; Tipo de Trama do Isolamento da Seção: Isolamento 2; Caneta Trama Isolamento Seção: Aberturas - Fundo de Trama; Caneta da Trama de Fundo Isolamento Seção: Aberturas - Fundo de Trama; Caneta de Vista e 3D do Peitoril Interno: Geral - Geral; Caneta de Contorno Seção Peitoril Interno: Geral - Geral; Tipo de Trama do Peitoril Interno em Corte: Trama Vazia; Caneta Trama do Peitoril Interno em Corte: Fundos - Cor 1; Caneta Trama de Fundo do Peitoril Interno em Corte: Fundos - Cor 1; Tipo de Trama de Guarnição Int.: Trama Vazia; Caneta de Trama de Guarnição Int: Aberturas - Fundo de Trama; Caneta de Fundo de Trama de Guarnição Int: Aberturas - Fundo de Trama; Tipo de Trama de Guarnição Ext: Trama Vazia; Caneta de Trama de Guarnição Ext: Fundos - Cor 1; Caneta de Fundo de Trama de Guarnição Ext: Fundos - Cor 1; Tipo de Trama de Seção do Arco: Trama Vazia; Caneta da Trama da Seção do Arco: Fundos - Cor 1; Caneta de Fundo de Trama de Seção do Arco: Fundos - Cor 1; Tipo de Trama do Corte do Perfil da Ventilação: Ar (Vazio); Caneta da Trama do Corte do Perfil da Ventilação: Fundos - Cor 1; Caneta do Fundo da Trama do Corte do Perfil da Ventilação: Fundos - Cor 1; Tipo de Linha de Símbolo Quebra-Sol: 1; Caneta da Linha em Corte do Quebra-Sol: Geral - Geral; 3D/Caneta das Linhas não Cortadas no Corte: Geral - Geral; Tipo da Trama de Corte Quebra-Sol (gs_sunShade_cutFillType): Trama Vazia; Tipo da Trama de Corte Quebra-Sol (gs_sunShade_cutFillPen): Geral - Geral; Caneta da Trama do Fundo Corte Quebra-Sol: Window Background; Tipo Trama Isolamento Quebra-Sol: Trama Vazia; Caneta da Trama Isolamento Quebra-Sol: Geral - Geral; Caneta do Fundo Isolamento Quebra-Sol: Window Background; Junção Elementos Batente: 2; Caneta Moldura: Aberturas - Geral; Caneta Caixilho: Aberturas - Geral; Caneta Vidro: Aberturas - Fundo de Trama; Caneta de Arco de Alvenaria: Paredes - Geral; Sombra: yes; Superfícies Uniformes Janela: yes; Batente Externo: Metal - Alumínio; Batente Interno: Metal - Alumínio; Caixilho Externo: Metal - Alumínio; Caixilho Interno: Metal - Alumínio; Persianas: Madeira - Pinho Granulado Horizontal; Vidro: Vidro - Simples; Grelha Externa: Metal - Alumínio; Grelha Interna: Metal - Alumínio; Painel Sólido Exterior: Metal - Alumínio; Painel Sólido Interior: Metal - Alumínio; Maçaneta: Metal - Aço Inoxidável; Superfícies Guarnição Uniformes: no; Interior Guarnição: Metal - Alumínio; Exterior Guarnição: Metal - Alumínio; Perfil de Ventilação: Metal - Alumínio; Painel Veneziana: Madeira - Pinho Granulado Horizontal; Moldura Painel Veneziana: Madeira - Pinho Granulado Horizontal; Caixa do Rolamento Veneziana: Metal - Aço Inoxidável; Lâminas Rolamento Veneziana: Pintura - Branco Titânio; Barras Rolamento Veneziana: Pintura - Branco Titânio; Caixa Persianas: Metal - Aço Inoxidável; Segmento Persianas: Pintura - Branco Titânio; Trilho Deslizante Veneziana: Metal - Aço Inoxidável; Soleira/Peitoril (gs_sill_mat): Pedra - Granito Cinza; Argamassa do Peitoril em Tijolo: Estuque - Branco Áspera; Peitoril Interno (gs_board_mat): Madeira - Pinho Granulado Horizontal; Arco de Alvenaria em Tijolo: Tijolo - Aparelho ao Comprido; Argamassa do Arco de Alvenaria: Estuque - Branco Áspera; Fecho Arco de Alvenaria: Pedra - Arenito 01; Nincho: Pintura - Óxido de Chumbo Amarelo; Superfície de Pilar de Canto: Metal - Alumínio; Direção da Abertura: 1; Visualizar como Travessa: no; Caneta Linha Fim Parede: Geral - Geral; Tipo de Linha Fim de Parede: 4; Profundidade Travessa em Símbolo: no; Tipo de Linha do Símbolo da Profundidade Travessa: 4; Caneta do Símbolo da Profundidade Travessa: Texto - Geral; Janela pertence à Zona dentro da qual abre: no; Custo: 0; Área Total Envidraçada (gs_list_glassarea_tmp): 0; Substituir Área Envidraçada: yes; Área Total Envidraçada (gs_list_glassarea): 0; Perimetro Total Vidro: 0; Desempenho Ar Livre (mm2/l/m): 0; Tipo de Grupo (FM_Type): Objetos padrão; Tipo de Grupo (iFMType): 1; Peso Objeto: 0; Unidade Peso Objeto: kg; Definição de Orientação Janela: 0; Operação IFC (ifc_optypestr): Triplo Base; Operação IFC (ifc_optype): 6; Ângulo de Abertura Veneziana: 180 deg; Estilo Linha de Abertura: 2
INFORMAÇÕES DO PRODUTO - Data de Aquisição: DD/MM/YYYY
FABRICAÇÃO - Data de Fabricação: DD/MM/YYYY; Site do Produto: www.graphisoft.com
GARANTIA - Ínicio da Garantia: DD/MM/YYYY; Fim da Garantia: DD/MM/YYYY
ABERTURAS - Tipo de Abertura: Correr 2 Folhas; Material: Alumínio; Vidro
EXPRESSÕES DE TEXTO (Expressão) - Localização do Produto no Projeto: Projeto: Jardim EditeLocal: Piso: Pavimento tipo Cômodo: Apartamento 01; ID de Aberturas com Master ID: Apt 01 - 01J08; ID Dinâmico por Classificação: Janela -J08
AC_Pset_RenovationAndPhasing - Renovation Status: Existing
BaseQuantities - GrossArea: 1.26725 m2; Height: 925 mm; Width: 1370 mm; Perimeter: 4590 mm; Area: 1.26725 m2; Volume: 0.0237525 m3; Depth: 140 mm; NetVolume: 0.0237525 m3
ArchiCADQuantities - W/D Opening Opening Volume: 0.177415 m3; W/D Opening Nominal Volume: 0.177415 m3; W/D Opening Surface Area: 4.69201 m2; W/D Opening Nominal Surface Area: 1.26725 m2; W/D Opening Width on the Reveal Side: 1370 mm; W/D Opening Height on the Reveal Side: 925 mm; W/D Opening Width on the Side Opposite to the Reveal Side: 1370 mm; W/D Opening Height on the Side Opposite to the Reveal Side: 925 mm; W/D Opening Surface Area on the Reveal Side: 1.26725 m2; W/D Opening Surface Area on the Side Opposite to the Reveal Side: 1.26725 m2; Nominal W/D Opening Width on the Reveal Side: 1370 mm; Nominal W/D Opening Height on the Reveal Side: 925 mm; Nominal W/D Opening Width on the Side Opposite to the Reveal Side: 1370 mm; Nominal W/D Opening Height on the Side Opposite to the Reveal Side: 925 mm; Nominal W/D Opening Surface Area on the Reveal Side: 1.26725 m2; Nominal W/D Opening Surface Area on the Side Opposite to the Reveal Side: 1.26725 m2; Sill/Header Value: 150 mm; W/D Nominal Sill Height: 150 mm; W/D Sill Height on the Reveal Side: 150 mm; W/D Sill Height on the Side Opposite to the Reveal Side: 150 mm; W/D Nominal Head Height: 1075 mm; W/D Head Height on the Reveal Side: 1075 mm; W/D Head Height on the Side Opposite to the Reveal Side: 1075 mm; Wall Thickness: 140 mm; Frame Thickness: 50 mm; Height: 925 mm; Volume (Net): 0.0237525 m3; Width: 1370 mm; Elevation to Project Zero: 1250 mm; Elevation to 1º Nível de Referência: 1250 mm; Elevation to 2º Nível de Referência: 1250 mm; Elevation to Sea Level: 729470 mm; Elevation to Linked/Home Story: 1250 mm; Home Offset: 1250 mm; Surface Area: 4.69201 m2; Top Elevation To First Reference Level: 2190 mm; Top Elevation To Home Story: 2190 mm; Top Elevation To Project Zero: 2190 mm; Top Elevation To Sea Level: 730410 mm; Top Elevation To Second Reference Level: 2190 mm; Bottom Elevation To First Reference Level: 1235 mm; Bottom Elevation To Home Story: 1235 mm; Bottom Elevation To Project Zero: 1235 mm; Bottom Elevation To Sea Level: 729455 mm; Bottom Elevation To Second Reference Level: 1235 mm; Bottom Surface Area (Net): 4.69201 m2
AC_Equantity_Janela_26 - Largura: 1370 mm; Altura: 925 mm; Dimensão Z: 1000 mm; Nível da Base: 1000 mm; Nível do Topo: 0 mm; Altura Peitoril ao Piso Atual: 1250 mm; Abertura para o Núcleo da Parede: 50 mm; Nova Largura Direita da Trama de Parede: 150 mm; Nova Largura Esquerda da Trama de Parede: 150 mm; Espessura Parede Ligação: 0 mm; Espessura Parede 2 Conectada: 140 mm; Espessura Parede 1 Conectada: 140 mm; Largura Pilar de Canto: 0 mm; Espessura Pilar Canto: 0 mm; Projeção Pilar de Canto: 0 mm; Tolerância Máxima: 100 mm; Tolerância: 0 mm; Tolerância Esquerda: 0 mm; Tolerância Direita: 0 mm; Tolerância Superior: 0 mm; Tolerância Inferior: 0 mm; Largura de Vão: 1370 mm; Altura de Vão: 925 mm; Largura Face de Vão: 1370 mm; Altura Face de Vão: 925 mm; Largura Unidade: 1370 mm; Altura Unidade: 925 mm; Largura Painel Lado: 0 mm; Largura Painel Meio: 685 mm; Espessura Batente: 50 mm; Largura Batente: 35 mm; Largura Batente Lado 2: 47 mm; Largura Batente Cimo: 47 mm; Largura Batente Base: 47 mm; Profundidade Rebaixo: 20 mm; Largura Rebaixo: 20 mm; Largura Divisão Superior: 100 mm; Altura Divisões Sup. Horiz.: 517.5 mm; Largura Divisão Inferior: 100 mm; Altura Divisões Inf. Horiz: 372.5 mm; Largura Montante Lado 1: 100 mm; Largura Montante Lado 2: 100 mm; Altura Divisão Horizontal Caixilho Principal: 355 mm; Altura Divisão Horizontal Caixilho Inferior: 900 mm; Altura Divisão Horizontal Caixilho Travessa: 295.5 mm; Espessura Estrutura Caixilho: 20 mm; Largura Caixilho: 50 mm; Largura Grelha: 20 mm; Espessura Grelha: 25 mm; Espessura Vidro: 20 mm; Espessura Venezianas: 10 mm; Largura Venezianas: 50 mm; Sobred. Abertura Esquerda: 0 mm; Sobred. Direita Abertura: 0 mm; Sobred. Topo Abertura: 0 mm; Sobred. Base Abertura: 0 mm; Largura Arquitrave Principal: 20 mm; Largura Lado 1 (gs_tw_right_out): 100 mm; Largura Lado 2 (gs_tw_left_out): 100 mm; Largura Topo (gs_tw_top_out): 100 mm; Largura Inferior (gs_tw_bottom_out): 100 mm; Espessura de Parede (gs_trim_thk_out): 25 mm; Espessura na Abertura da Parede (gs_trim_width_out): 25 mm; Paralelas (gs_trim_offs_out): 0 mm; Bordo (gs_trim_jambext_nosing_out): 50 mm; Saliência Superior (gs_trimov_top_left_out): 0 mm; Saliência Superior (gs_trimov_top_right_out): 0 mm; Ressalto Inferior (gs_trimov_bot_left_out): 0 mm; Ressalto Inferior (gs_trimov_bot_right_out): 0 mm; Ressalto Inferior (casingOverhangBottomSideOut): 50 mm; Largura Lado 1 (gs_tw_right_in): 40 mm; Largura Lado 2 (gs_tw_left_in): 100 mm; Largura Topo (gs_tw_top_in): 100 mm; Largura Inferior (gs_tw_bottom_in): 100 mm; Espessura de Parede (gs_trim_thk_in): 25 mm; Espessura na Abertura da Parede (gs_trim_width_in): 25 mm; Paralelas (gs_trim_offs_in): 0 mm; Bordo (gs_trim_jambext_nosing_in): 50 mm; Saliência Superior (gs_trimov_top_left_in): 0 mm; Saliência Superior (gs_trimov_top_right_in): 0 mm; Ressalto Inferior (gs_trimov_bot_left_in): 0 mm; Ressalto Inferior (gs_trimov_bot_right_in): 0 mm; Largura Peitoril: 80 mm; Largura Topo Parapeito: 10 mm; Altura Topo Peitoril: 10 mm; Espessura Peitoril: 25 mm; Espessura Lateral da Frente Peitoril: 15 mm; Elevação Peitoril: 5 mm; Recobrimento Goteira Peitoril: 20 mm; Largura Goteira Peitoril: 30 mm; Testeira Peitoril: 30 mm; Avanço do Parapeito Esquerda: 0 mm; Avanço do Parapeito Direita: 0 mm; Inclinação do Parapeito: 20 mm; Inclin. Peitoril da Parede: 0 mm; Profund. Vão Posterior (gs_sill_holeDepthBehind): 0 mm; Espessura do Tijolo (gs_brick_sill_br_thk): 65 mm; Espessura de Argamassa (gs_brick_sill_mort_thk): 15 mm; Largura Peitoril Int.: 70 mm; Espessura Peitoril Int.: 25 mm; Peitoril Int. Arredondado: 30 mm; Saliência Esq. Peitoril Int.: 0 mm; Saliência Dir. Peitoril Int.: 0 mm; Inclinação do Parapeito Int.: 0 mm; Altura Perfil: 65 mm; Espessura Perfil: 110 mm; Altura Painel: 1500 mm; Afast. Interior: 20 mm; Profund. Fechamento: 0 mm; Largura Batente Extra: 40 mm; Espess. Batente Extra: 30 mm; Largura Barra:: 30 mm; Comprim. Vara Suspensa: 20 mm; Raio Vara Suspensa: 5 mm; Distância Painel: 6 mm; Saliência Exterior: 0 mm; Largura Painel Interior: 120 mm; Comprim. Abertura 3D: 1500 mm; Comprim. Fechado 3D: 0 mm; Comprimento 1 Abertura 3D (gs_shutter_opLength_1): 560 mm; Comprimento 1 Abertura 3D (gs_shutter_opLength_2): 140 mm; Altura Abertura 3D: 1500 mm; Altura Fechado 3D: 0 mm; Espessura Painel: 50 mm; Largura Estrutura Painel: 50 mm; Largura Moldura Inferior: 50 mm; Largura Painel: 0 mm; Espess. de Enchimento de Painel: 10 mm; Espessura da Veneziana: 10 mm; Largura Grelha Ventilação: 40 mm; Largura Divisor Moldura Horiz.: 50 mm; Largura de Divisor Moldura Vert.: 50 mm; Raio do Vão: 10 mm; Largura Bordo Vertical: 100 mm; Largura Estrutura Z: 50 mm; Espessura Estrutura Z: 25 mm; Espess. Placas Verticais: 25 mm; Espess. Placas Horizontais: 25 mm; Largura Aprox. Placas Verticais: 80 mm; Largura Aprox. Placas Horizontais: 115 mm; Altura Caixa (gs_shutRoll_boxHeight): 200 mm; Profund. Caixa (gs_shutRoll_boxWidth): 150 mm; Afast. Caixa Esq.: 0 mm; Afast. Caixa Dir.: 0 mm; Profund. Anteparos: 72.5 mm; Distância da Parede (gs_shutRoll_distFromWall): 0 mm; Distância da Padieira (gs_shutRoll_distFromHead): 0 mm; Largura da Ripa: 50 mm; Altura Caixa (gs_shutLam_boxHeight): 200 mm; Profund. Caixa (gs_shutLam_boxWidth): 150 mm; Largura Capa: 0 mm; Distância da Parede (gs_shutLam_distFromWall): 0 mm; Distância da Padieira (gs_shutLam_distFromHead): 0 mm; Largura Segmento (gs_shutLam_segmentWidth): 60 mm; Altura Caixa (gs_shutLam2_boxHeight): 60 mm; Largura Caixa: 60 mm; Distância da Janela: 60 mm; Distância da Padieira (gs_shutLam2_distFromHead): 60 mm; Altura do Eixo da Caixa da Padieira: 0 mm; Largura Segmento (gs_shutLam2_segmentWidth): 60 mm; Distância entre Arco e Janela: 0 mm; Avanço à Esquerda do Arco de Alvenaria: 0 mm; Avanço à Direita do Arco de Alvenaria: 0 mm; Espelho do Arco de Alvenaria: 30 mm; Projeção do Arco de Alvenaria: 0 mm; Altura do Arco de Alvenaria: 250 mm; Profundidade do Arco de Alvenaria: 120 mm; Profund. Vão Posterior (gs_masonry_arch_rearHoleDepth): 0 mm; Espessura do Tijolo (gs_masonry_arch_brick_thk): 65 mm; Espessura de Argamassa (gs_masonry_arch_mort_thk): 10 mm; Largura Fecho: 100 mm; Sobredimensão Fecho: 0 mm; Projeção Fecho: 10 mm; Profund. Face de Vão (gs_wido_sill): 50 mm; Profund. Face de Vão (AC_wido_sill): 50 mm; Profund. Ombreira Lado 2: 60 mm; Profund. Ombreira: 60 mm; Profund. Ombreira Interior Lado 2 (gs_reveal_splayed_innerLeft): 60 mm; Profund. Ombreira Interior (gs_reveal_splayed_innerRight): 60 mm; Profund. Ombreira Interior Lado 2 (gs_reveal_double_innerLeft): 60 mm; Profund. Ombreira Interior (gs_reveal_double_innerRight): 60 mm; Profund. Batente Cima: 60 mm; Profund. Batente Peitoril: 60 mm; Profundidade Padieira Interior (gs_reveal_splayed_innerTop): 60 mm; Profundidade Peitoril Interior (gs_reveal_splayed_innerBottom): 60 mm; Profundidade Padieira Interior (gs_reveal_double_innerTop): 60 mm; Profundidade Peitoril Interior (gs_reveal_double_innerBottom): 0 mm; Profund. Batente Exterior: 80 mm; Limite Espess. Reboco: 40 mm; Distância de Camada do Encerram.: 0 mm; Largura do Fecho: 38 mm; Espessura do Fecho: 100 mm; Espessura da Camada: 25 mm; Espessura do Perfil: 75 mm; Espessura Personal.: 15 mm; Saliência Camada para Espess. Batente: 0 mm; Profundidade do Recorte: 50 mm; Largura de Parapeito: 1000 mm; Avanço Lateral 1: 0 mm; Avanço Lateral 2: 0 mm; Altura Parapeito: 900 mm; Ressalto Inferior (gs_parapet_botelev): 0 mm; Distância Abertura 1 Caixilho Principal: 0 mm; Distância Abertura 2 Caixilho Principal: 0 mm; Distância Abertura 1 Caixilho Inferior: 0 mm; Distância Abertura 2 Caixilho Inferior: 0 mm; Distância Abertura 1 Bandeira Caixilho: 0 mm; Distância Abertura 2 Bandeira Caixilho: 0 mm; Comprimento Abertura em 2D: 0 mm; Sobred. Abertura Esq. AC: 0 mm; Sobred. Abertura Dir. AC: 0 mm; Sobred. Padieira AC: 0 mm; Sobred. Abertura Base AC: 0 mm
Component Quantities - Component, Component Volume (Net): 0.0237525 m3; Component, Component Volume (Gross): 0.0237525 m3

# IfcWindow: Janela 26, Apt 04 - J08
In: 04
Type - OperationType: TRIPLE_PANEL_BOTTOM; ParameterTakesPrecedence: no; Sizeable: no
Type - Window Lining Properties - LiningDepth: 50 mm; LiningThickness: 35 mm; TransomThickness: 35 mm; MullionThickness: 50 mm; FirstTransomOffset: 0.559459; FirstMullionOffset: 0.5
Type - Window Panel Properties - Panel 1 - OperationType: SLIDINGHORIZONTAL; PanelPosition: RIGHT; FrameDepth: 20 mm; FrameThickness: 50 mm
Type - Window Panel Properties - Panel 2 - OperationType: SLIDINGHORIZONTAL; PanelPosition: LEFT; FrameDepth: 20 mm; FrameThickness: 50 mm
Type - Window Panel Properties - Panel 3 - OperationType: FIXEDCASEMENT; PanelPosition: BOTTOM
Description: Janela-dupla_fixa-generico-generico-aluminio-137cm-925cm; OverallHeight: 925 mm; OverallWidth: 1370 mm; Classification: Janela (Classificação ARCHICAD); 3E 20 04 02 02 Janela de correr (NBR 15965-5 3E)
Pset_WindowCommon - ThermalTransmittance: 0; IsExternal: yes
ArchiCADProperties - Reveal Dimensions: 1,37×0,93; Wallhole Dimensions: 1,37×0,93; Unit Dimensions: 1,37×0,93; Nominal W x H Size: 1,37×0,93; Nominal W x H x T Size: 1,37×0,93×0,14; Wall Structure: Tijolo - Estrutural; Orientation: R; Opening Library Part Name: Janela 26; Opening Side Fill Index: Trama Vazia; Element ID: J08; Hotlink and Element ID: Apt 04 - J08; Layer: A--PRDE-VEDS-E-; Library Part Name: Janela 26; Building Material / Composite / Profile / Fill: Trama Vazia; Fill Type: Trama Vazia; Colliding Zones: Apartamento 04; Related Zone Name: Apartamento 04; Related Zone Number: 04; Locked: yes; Home Story Name: Pavimento tipo; Home Story Number: 0; Element Type: Window; Parent ID: Parede 24; Surfaces (All): Vidro - Simples; Metal - Alumínio; Hotlink Master ID: Apt 04 -; From Zone: Apartamento 04; From Zone Number: 04; To Zone: Apartamento 04; To Zone Number: 04; Position: Exterior; Show On Renovation Filter: All Relevant Filters; Structural Function: Non-Load-Bearing Element; Renovation Status: Existing
